VERSION 5.8 ;
BUSBITCHARS "[]" ;
DIVIDERCHAR "/" ;
UNITS
    DATABASE MICRONS 1000 ;
END UNITS

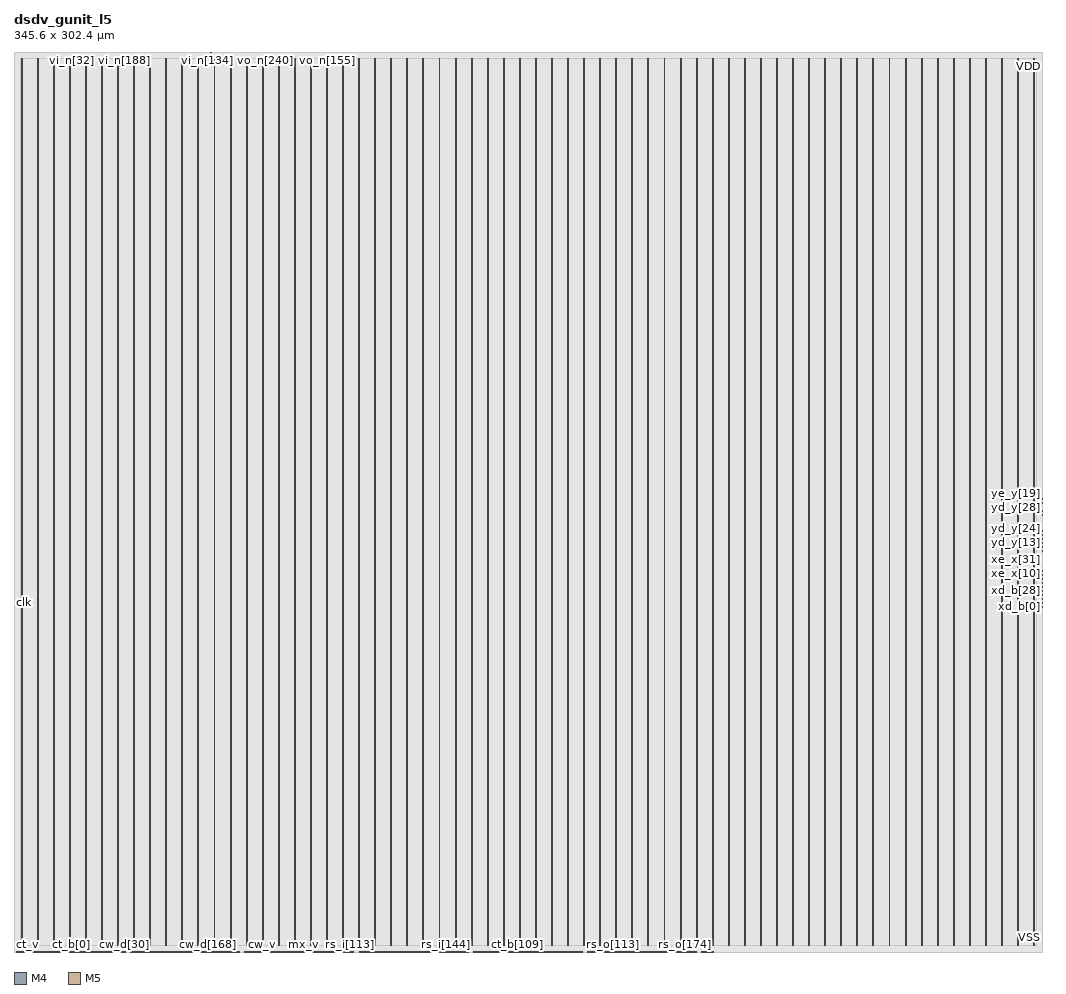
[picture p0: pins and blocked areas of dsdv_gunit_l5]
MACRO dsdv_gunit_l5
  FOREIGN dsdv_gunit_l5 0 0 ;
  CLASS BLOCK ;
  SIZE 345.6 BY 302.4 ;
  PIN clk
    DIRECTION INPUT ;
    USE SIGNAL ;
    PORT
      LAYER M4 ;
        RECT  0 117.456 0.084 117.48 ;
    END
  END clk
  PIN ct_b[0]
    DIRECTION OUTPUT ;
    USE SIGNAL ;
    PORT
      LAYER M5 ;
        RECT  19.152 0 19.176 0.084 ;
    END
  END ct_b[0]
  PIN ct_b[100]
    DIRECTION OUTPUT ;
    USE SIGNAL ;
    PORT
      LAYER M5 ;
        RECT  167.376 0 167.4 0.084 ;
    END
  END ct_b[100]
  PIN ct_b[101]
    DIRECTION OUTPUT ;
    USE SIGNAL ;
    PORT
      LAYER M5 ;
        RECT  167.568 0 167.592 0.084 ;
    END
  END ct_b[101]
  PIN ct_b[102]
    DIRECTION OUTPUT ;
    USE SIGNAL ;
    PORT
      LAYER M5 ;
        RECT  167.76 0 167.784 0.084 ;
    END
  END ct_b[102]
  PIN ct_b[103]
    DIRECTION OUTPUT ;
    USE SIGNAL ;
    PORT
      LAYER M5 ;
        RECT  167.952 0 167.976 0.084 ;
    END
  END ct_b[103]
  PIN ct_b[104]
    DIRECTION OUTPUT ;
    USE SIGNAL ;
    PORT
      LAYER M5 ;
        RECT  168.144 0 168.168 0.084 ;
    END
  END ct_b[104]
  PIN ct_b[105]
    DIRECTION OUTPUT ;
    USE SIGNAL ;
    PORT
      LAYER M5 ;
        RECT  168.336 0 168.36 0.084 ;
    END
  END ct_b[105]
  PIN ct_b[106]
    DIRECTION OUTPUT ;
    USE SIGNAL ;
    PORT
      LAYER M5 ;
        RECT  168.528 0 168.552 0.084 ;
    END
  END ct_b[106]
  PIN ct_b[107]
    DIRECTION OUTPUT ;
    USE SIGNAL ;
    PORT
      LAYER M5 ;
        RECT  168.72 0 168.744 0.084 ;
    END
  END ct_b[107]
  PIN ct_b[108]
    DIRECTION OUTPUT ;
    USE SIGNAL ;
    PORT
      LAYER M5 ;
        RECT  168.912 0 168.936 0.084 ;
    END
  END ct_b[108]
  PIN ct_b[109]
    DIRECTION OUTPUT ;
    USE SIGNAL ;
    PORT
      LAYER M5 ;
        RECT  169.104 0 169.128 0.084 ;
    END
  END ct_b[109]
  PIN ct_b[10]
    DIRECTION OUTPUT ;
    USE SIGNAL ;
    PORT
      LAYER M5 ;
        RECT  21.072 0 21.096 0.084 ;
    END
  END ct_b[10]
  PIN ct_b[110]
    DIRECTION OUTPUT ;
    USE SIGNAL ;
    PORT
      LAYER M5 ;
        RECT  169.296 0 169.32 0.084 ;
    END
  END ct_b[110]
  PIN ct_b[111]
    DIRECTION OUTPUT ;
    USE SIGNAL ;
    PORT
      LAYER M5 ;
        RECT  169.488 0 169.512 0.084 ;
    END
  END ct_b[111]
  PIN ct_b[112]
    DIRECTION OUTPUT ;
    USE SIGNAL ;
    PORT
      LAYER M5 ;
        RECT  169.68 0 169.704 0.084 ;
    END
  END ct_b[112]
  PIN ct_b[113]
    DIRECTION OUTPUT ;
    USE SIGNAL ;
    PORT
      LAYER M5 ;
        RECT  169.872 0 169.896 0.084 ;
    END
  END ct_b[113]
  PIN ct_b[114]
    DIRECTION OUTPUT ;
    USE SIGNAL ;
    PORT
      LAYER M5 ;
        RECT  170.064 0 170.088 0.084 ;
    END
  END ct_b[114]
  PIN ct_b[115]
    DIRECTION OUTPUT ;
    USE SIGNAL ;
    PORT
      LAYER M5 ;
        RECT  170.256 0 170.28 0.084 ;
    END
  END ct_b[115]
  PIN ct_b[116]
    DIRECTION OUTPUT ;
    USE SIGNAL ;
    PORT
      LAYER M5 ;
        RECT  170.448 0 170.472 0.084 ;
    END
  END ct_b[116]
  PIN ct_b[117]
    DIRECTION OUTPUT ;
    USE SIGNAL ;
    PORT
      LAYER M5 ;
        RECT  170.64 0 170.664 0.084 ;
    END
  END ct_b[117]
  PIN ct_b[118]
    DIRECTION OUTPUT ;
    USE SIGNAL ;
    PORT
      LAYER M5 ;
        RECT  170.832 0 170.856 0.084 ;
    END
  END ct_b[118]
  PIN ct_b[119]
    DIRECTION OUTPUT ;
    USE SIGNAL ;
    PORT
      LAYER M5 ;
        RECT  171.024 0 171.048 0.084 ;
    END
  END ct_b[119]
  PIN ct_b[11]
    DIRECTION OUTPUT ;
    USE SIGNAL ;
    PORT
      LAYER M5 ;
        RECT  21.264 0 21.288 0.084 ;
    END
  END ct_b[11]
  PIN ct_b[120]
    DIRECTION OUTPUT ;
    USE SIGNAL ;
    PORT
      LAYER M5 ;
        RECT  171.216 0 171.24 0.084 ;
    END
  END ct_b[120]
  PIN ct_b[121]
    DIRECTION OUTPUT ;
    USE SIGNAL ;
    PORT
      LAYER M5 ;
        RECT  171.408 0 171.432 0.084 ;
    END
  END ct_b[121]
  PIN ct_b[122]
    DIRECTION OUTPUT ;
    USE SIGNAL ;
    PORT
      LAYER M5 ;
        RECT  171.6 0 171.624 0.084 ;
    END
  END ct_b[122]
  PIN ct_b[123]
    DIRECTION OUTPUT ;
    USE SIGNAL ;
    PORT
      LAYER M5 ;
        RECT  171.792 0 171.816 0.084 ;
    END
  END ct_b[123]
  PIN ct_b[124]
    DIRECTION OUTPUT ;
    USE SIGNAL ;
    PORT
      LAYER M5 ;
        RECT  171.984 0 172.008 0.084 ;
    END
  END ct_b[124]
  PIN ct_b[125]
    DIRECTION OUTPUT ;
    USE SIGNAL ;
    PORT
      LAYER M5 ;
        RECT  172.176 0 172.2 0.084 ;
    END
  END ct_b[125]
  PIN ct_b[126]
    DIRECTION OUTPUT ;
    USE SIGNAL ;
    PORT
      LAYER M5 ;
        RECT  172.368 0 172.392 0.084 ;
    END
  END ct_b[126]
  PIN ct_b[127]
    DIRECTION OUTPUT ;
    USE SIGNAL ;
    PORT
      LAYER M5 ;
        RECT  172.56 0 172.584 0.084 ;
    END
  END ct_b[127]
  PIN ct_b[128]
    DIRECTION OUTPUT ;
    USE SIGNAL ;
    PORT
      LAYER M5 ;
        RECT  172.752 0 172.776 0.084 ;
    END
  END ct_b[128]
  PIN ct_b[129]
    DIRECTION OUTPUT ;
    USE SIGNAL ;
    PORT
      LAYER M5 ;
        RECT  172.944 0 172.968 0.084 ;
    END
  END ct_b[129]
  PIN ct_b[12]
    DIRECTION OUTPUT ;
    USE SIGNAL ;
    PORT
      LAYER M5 ;
        RECT  21.456 0 21.48 0.084 ;
    END
  END ct_b[12]
  PIN ct_b[130]
    DIRECTION OUTPUT ;
    USE SIGNAL ;
    PORT
      LAYER M5 ;
        RECT  173.136 0 173.16 0.084 ;
    END
  END ct_b[130]
  PIN ct_b[131]
    DIRECTION OUTPUT ;
    USE SIGNAL ;
    PORT
      LAYER M5 ;
        RECT  173.328 0 173.352 0.084 ;
    END
  END ct_b[131]
  PIN ct_b[132]
    DIRECTION OUTPUT ;
    USE SIGNAL ;
    PORT
      LAYER M5 ;
        RECT  173.52 0 173.544 0.084 ;
    END
  END ct_b[132]
  PIN ct_b[133]
    DIRECTION OUTPUT ;
    USE SIGNAL ;
    PORT
      LAYER M5 ;
        RECT  173.712 0 173.736 0.084 ;
    END
  END ct_b[133]
  PIN ct_b[134]
    DIRECTION OUTPUT ;
    USE SIGNAL ;
    PORT
      LAYER M5 ;
        RECT  173.904 0 173.928 0.084 ;
    END
  END ct_b[134]
  PIN ct_b[135]
    DIRECTION OUTPUT ;
    USE SIGNAL ;
    PORT
      LAYER M5 ;
        RECT  174.096 0 174.12 0.084 ;
    END
  END ct_b[135]
  PIN ct_b[136]
    DIRECTION OUTPUT ;
    USE SIGNAL ;
    PORT
      LAYER M5 ;
        RECT  174.288 0 174.312 0.084 ;
    END
  END ct_b[136]
  PIN ct_b[137]
    DIRECTION OUTPUT ;
    USE SIGNAL ;
    PORT
      LAYER M5 ;
        RECT  174.48 0 174.504 0.084 ;
    END
  END ct_b[137]
  PIN ct_b[138]
    DIRECTION OUTPUT ;
    USE SIGNAL ;
    PORT
      LAYER M5 ;
        RECT  174.672 0 174.696 0.084 ;
    END
  END ct_b[138]
  PIN ct_b[139]
    DIRECTION OUTPUT ;
    USE SIGNAL ;
    PORT
      LAYER M5 ;
        RECT  174.864 0 174.888 0.084 ;
    END
  END ct_b[139]
  PIN ct_b[13]
    DIRECTION OUTPUT ;
    USE SIGNAL ;
    PORT
      LAYER M5 ;
        RECT  21.648 0 21.672 0.084 ;
    END
  END ct_b[13]
  PIN ct_b[140]
    DIRECTION OUTPUT ;
    USE SIGNAL ;
    PORT
      LAYER M5 ;
        RECT  175.056 0 175.08 0.084 ;
    END
  END ct_b[140]
  PIN ct_b[141]
    DIRECTION OUTPUT ;
    USE SIGNAL ;
    PORT
      LAYER M5 ;
        RECT  175.248 0 175.272 0.084 ;
    END
  END ct_b[141]
  PIN ct_b[142]
    DIRECTION OUTPUT ;
    USE SIGNAL ;
    PORT
      LAYER M5 ;
        RECT  175.44 0 175.464 0.084 ;
    END
  END ct_b[142]
  PIN ct_b[143]
    DIRECTION OUTPUT ;
    USE SIGNAL ;
    PORT
      LAYER M5 ;
        RECT  175.632 0 175.656 0.084 ;
    END
  END ct_b[143]
  PIN ct_b[144]
    DIRECTION OUTPUT ;
    USE SIGNAL ;
    PORT
      LAYER M5 ;
        RECT  175.824 0 175.848 0.084 ;
    END
  END ct_b[144]
  PIN ct_b[145]
    DIRECTION OUTPUT ;
    USE SIGNAL ;
    PORT
      LAYER M5 ;
        RECT  176.016 0 176.04 0.084 ;
    END
  END ct_b[145]
  PIN ct_b[146]
    DIRECTION OUTPUT ;
    USE SIGNAL ;
    PORT
      LAYER M5 ;
        RECT  176.208 0 176.232 0.084 ;
    END
  END ct_b[146]
  PIN ct_b[147]
    DIRECTION OUTPUT ;
    USE SIGNAL ;
    PORT
      LAYER M5 ;
        RECT  176.4 0 176.424 0.084 ;
    END
  END ct_b[147]
  PIN ct_b[148]
    DIRECTION OUTPUT ;
    USE SIGNAL ;
    PORT
      LAYER M5 ;
        RECT  176.592 0 176.616 0.084 ;
    END
  END ct_b[148]
  PIN ct_b[149]
    DIRECTION OUTPUT ;
    USE SIGNAL ;
    PORT
      LAYER M5 ;
        RECT  176.784 0 176.808 0.084 ;
    END
  END ct_b[149]
  PIN ct_b[14]
    DIRECTION OUTPUT ;
    USE SIGNAL ;
    PORT
      LAYER M5 ;
        RECT  21.84 0 21.864 0.084 ;
    END
  END ct_b[14]
  PIN ct_b[150]
    DIRECTION OUTPUT ;
    USE SIGNAL ;
    PORT
      LAYER M5 ;
        RECT  176.976 0 177 0.084 ;
    END
  END ct_b[150]
  PIN ct_b[151]
    DIRECTION OUTPUT ;
    USE SIGNAL ;
    PORT
      LAYER M5 ;
        RECT  177.168 0 177.192 0.084 ;
    END
  END ct_b[151]
  PIN ct_b[152]
    DIRECTION OUTPUT ;
    USE SIGNAL ;
    PORT
      LAYER M5 ;
        RECT  177.36 0 177.384 0.084 ;
    END
  END ct_b[152]
  PIN ct_b[153]
    DIRECTION OUTPUT ;
    USE SIGNAL ;
    PORT
      LAYER M5 ;
        RECT  177.552 0 177.576 0.084 ;
    END
  END ct_b[153]
  PIN ct_b[154]
    DIRECTION OUTPUT ;
    USE SIGNAL ;
    PORT
      LAYER M5 ;
        RECT  177.744 0 177.768 0.084 ;
    END
  END ct_b[154]
  PIN ct_b[155]
    DIRECTION OUTPUT ;
    USE SIGNAL ;
    PORT
      LAYER M5 ;
        RECT  177.936 0 177.96 0.084 ;
    END
  END ct_b[155]
  PIN ct_b[156]
    DIRECTION OUTPUT ;
    USE SIGNAL ;
    PORT
      LAYER M5 ;
        RECT  178.128 0 178.152 0.084 ;
    END
  END ct_b[156]
  PIN ct_b[157]
    DIRECTION OUTPUT ;
    USE SIGNAL ;
    PORT
      LAYER M5 ;
        RECT  178.32 0 178.344 0.084 ;
    END
  END ct_b[157]
  PIN ct_b[158]
    DIRECTION OUTPUT ;
    USE SIGNAL ;
    PORT
      LAYER M5 ;
        RECT  178.512 0 178.536 0.084 ;
    END
  END ct_b[158]
  PIN ct_b[159]
    DIRECTION OUTPUT ;
    USE SIGNAL ;
    PORT
      LAYER M5 ;
        RECT  178.704 0 178.728 0.084 ;
    END
  END ct_b[159]
  PIN ct_b[15]
    DIRECTION OUTPUT ;
    USE SIGNAL ;
    PORT
      LAYER M5 ;
        RECT  22.032 0 22.056 0.084 ;
    END
  END ct_b[15]
  PIN ct_b[160]
    DIRECTION OUTPUT ;
    USE SIGNAL ;
    PORT
      LAYER M5 ;
        RECT  178.896 0 178.92 0.084 ;
    END
  END ct_b[160]
  PIN ct_b[161]
    DIRECTION OUTPUT ;
    USE SIGNAL ;
    PORT
      LAYER M5 ;
        RECT  179.088 0 179.112 0.084 ;
    END
  END ct_b[161]
  PIN ct_b[162]
    DIRECTION OUTPUT ;
    USE SIGNAL ;
    PORT
      LAYER M5 ;
        RECT  179.28 0 179.304 0.084 ;
    END
  END ct_b[162]
  PIN ct_b[163]
    DIRECTION OUTPUT ;
    USE SIGNAL ;
    PORT
      LAYER M5 ;
        RECT  179.472 0 179.496 0.084 ;
    END
  END ct_b[163]
  PIN ct_b[164]
    DIRECTION OUTPUT ;
    USE SIGNAL ;
    PORT
      LAYER M5 ;
        RECT  179.664 0 179.688 0.084 ;
    END
  END ct_b[164]
  PIN ct_b[165]
    DIRECTION OUTPUT ;
    USE SIGNAL ;
    PORT
      LAYER M5 ;
        RECT  179.856 0 179.88 0.084 ;
    END
  END ct_b[165]
  PIN ct_b[166]
    DIRECTION OUTPUT ;
    USE SIGNAL ;
    PORT
      LAYER M5 ;
        RECT  180.048 0 180.072 0.084 ;
    END
  END ct_b[166]
  PIN ct_b[167]
    DIRECTION OUTPUT ;
    USE SIGNAL ;
    PORT
      LAYER M5 ;
        RECT  180.24 0 180.264 0.084 ;
    END
  END ct_b[167]
  PIN ct_b[168]
    DIRECTION OUTPUT ;
    USE SIGNAL ;
    PORT
      LAYER M5 ;
        RECT  180.432 0 180.456 0.084 ;
    END
  END ct_b[168]
  PIN ct_b[169]
    DIRECTION OUTPUT ;
    USE SIGNAL ;
    PORT
      LAYER M5 ;
        RECT  180.624 0 180.648 0.084 ;
    END
  END ct_b[169]
  PIN ct_b[16]
    DIRECTION OUTPUT ;
    USE SIGNAL ;
    PORT
      LAYER M5 ;
        RECT  22.224 0 22.248 0.084 ;
    END
  END ct_b[16]
  PIN ct_b[170]
    DIRECTION OUTPUT ;
    USE SIGNAL ;
    PORT
      LAYER M5 ;
        RECT  180.816 0 180.84 0.084 ;
    END
  END ct_b[170]
  PIN ct_b[171]
    DIRECTION OUTPUT ;
    USE SIGNAL ;
    PORT
      LAYER M5 ;
        RECT  181.008 0 181.032 0.084 ;
    END
  END ct_b[171]
  PIN ct_b[172]
    DIRECTION OUTPUT ;
    USE SIGNAL ;
    PORT
      LAYER M5 ;
        RECT  181.2 0 181.224 0.084 ;
    END
  END ct_b[172]
  PIN ct_b[173]
    DIRECTION OUTPUT ;
    USE SIGNAL ;
    PORT
      LAYER M5 ;
        RECT  181.392 0 181.416 0.084 ;
    END
  END ct_b[173]
  PIN ct_b[174]
    DIRECTION OUTPUT ;
    USE SIGNAL ;
    PORT
      LAYER M5 ;
        RECT  181.584 0 181.608 0.084 ;
    END
  END ct_b[174]
  PIN ct_b[175]
    DIRECTION OUTPUT ;
    USE SIGNAL ;
    PORT
      LAYER M5 ;
        RECT  181.776 0 181.8 0.084 ;
    END
  END ct_b[175]
  PIN ct_b[176]
    DIRECTION OUTPUT ;
    USE SIGNAL ;
    PORT
      LAYER M5 ;
        RECT  181.968 0 181.992 0.084 ;
    END
  END ct_b[176]
  PIN ct_b[177]
    DIRECTION OUTPUT ;
    USE SIGNAL ;
    PORT
      LAYER M5 ;
        RECT  182.16 0 182.184 0.084 ;
    END
  END ct_b[177]
  PIN ct_b[178]
    DIRECTION OUTPUT ;
    USE SIGNAL ;
    PORT
      LAYER M5 ;
        RECT  182.352 0 182.376 0.084 ;
    END
  END ct_b[178]
  PIN ct_b[179]
    DIRECTION OUTPUT ;
    USE SIGNAL ;
    PORT
      LAYER M5 ;
        RECT  182.544 0 182.568 0.084 ;
    END
  END ct_b[179]
  PIN ct_b[17]
    DIRECTION OUTPUT ;
    USE SIGNAL ;
    PORT
      LAYER M5 ;
        RECT  22.416 0 22.44 0.084 ;
    END
  END ct_b[17]
  PIN ct_b[180]
    DIRECTION OUTPUT ;
    USE SIGNAL ;
    PORT
      LAYER M5 ;
        RECT  182.736 0 182.76 0.084 ;
    END
  END ct_b[180]
  PIN ct_b[181]
    DIRECTION OUTPUT ;
    USE SIGNAL ;
    PORT
      LAYER M5 ;
        RECT  182.928 0 182.952 0.084 ;
    END
  END ct_b[181]
  PIN ct_b[182]
    DIRECTION OUTPUT ;
    USE SIGNAL ;
    PORT
      LAYER M5 ;
        RECT  183.12 0 183.144 0.084 ;
    END
  END ct_b[182]
  PIN ct_b[183]
    DIRECTION OUTPUT ;
    USE SIGNAL ;
    PORT
      LAYER M5 ;
        RECT  183.312 0 183.336 0.084 ;
    END
  END ct_b[183]
  PIN ct_b[184]
    DIRECTION OUTPUT ;
    USE SIGNAL ;
    PORT
      LAYER M5 ;
        RECT  183.504 0 183.528 0.084 ;
    END
  END ct_b[184]
  PIN ct_b[185]
    DIRECTION OUTPUT ;
    USE SIGNAL ;
    PORT
      LAYER M5 ;
        RECT  183.696 0 183.72 0.084 ;
    END
  END ct_b[185]
  PIN ct_b[186]
    DIRECTION OUTPUT ;
    USE SIGNAL ;
    PORT
      LAYER M5 ;
        RECT  183.888 0 183.912 0.084 ;
    END
  END ct_b[186]
  PIN ct_b[187]
    DIRECTION OUTPUT ;
    USE SIGNAL ;
    PORT
      LAYER M5 ;
        RECT  184.08 0 184.104 0.084 ;
    END
  END ct_b[187]
  PIN ct_b[188]
    DIRECTION OUTPUT ;
    USE SIGNAL ;
    PORT
      LAYER M5 ;
        RECT  184.272 0 184.296 0.084 ;
    END
  END ct_b[188]
  PIN ct_b[189]
    DIRECTION OUTPUT ;
    USE SIGNAL ;
    PORT
      LAYER M5 ;
        RECT  184.464 0 184.488 0.084 ;
    END
  END ct_b[189]
  PIN ct_b[18]
    DIRECTION OUTPUT ;
    USE SIGNAL ;
    PORT
      LAYER M5 ;
        RECT  22.608 0 22.632 0.084 ;
    END
  END ct_b[18]
  PIN ct_b[190]
    DIRECTION OUTPUT ;
    USE SIGNAL ;
    PORT
      LAYER M5 ;
        RECT  184.656 0 184.68 0.084 ;
    END
  END ct_b[190]
  PIN ct_b[191]
    DIRECTION OUTPUT ;
    USE SIGNAL ;
    PORT
      LAYER M5 ;
        RECT  184.848 0 184.872 0.084 ;
    END
  END ct_b[191]
  PIN ct_b[192]
    DIRECTION OUTPUT ;
    USE SIGNAL ;
    PORT
      LAYER M5 ;
        RECT  6.864 0 6.888 0.084 ;
    END
  END ct_b[192]
  PIN ct_b[193]
    DIRECTION OUTPUT ;
    USE SIGNAL ;
    PORT
      LAYER M5 ;
        RECT  7.056 0 7.08 0.084 ;
    END
  END ct_b[193]
  PIN ct_b[194]
    DIRECTION OUTPUT ;
    USE SIGNAL ;
    PORT
      LAYER M5 ;
        RECT  7.248 0 7.272 0.084 ;
    END
  END ct_b[194]
  PIN ct_b[195]
    DIRECTION OUTPUT ;
    USE SIGNAL ;
    PORT
      LAYER M5 ;
        RECT  7.44 0 7.464 0.084 ;
    END
  END ct_b[195]
  PIN ct_b[196]
    DIRECTION OUTPUT ;
    USE SIGNAL ;
    PORT
      LAYER M5 ;
        RECT  7.632 0 7.656 0.084 ;
    END
  END ct_b[196]
  PIN ct_b[197]
    DIRECTION OUTPUT ;
    USE SIGNAL ;
    PORT
      LAYER M5 ;
        RECT  7.824 0 7.848 0.084 ;
    END
  END ct_b[197]
  PIN ct_b[198]
    DIRECTION OUTPUT ;
    USE SIGNAL ;
    PORT
      LAYER M5 ;
        RECT  8.016 0 8.04 0.084 ;
    END
  END ct_b[198]
  PIN ct_b[199]
    DIRECTION OUTPUT ;
    USE SIGNAL ;
    PORT
      LAYER M5 ;
        RECT  8.208 0 8.232 0.084 ;
    END
  END ct_b[199]
  PIN ct_b[19]
    DIRECTION OUTPUT ;
    USE SIGNAL ;
    PORT
      LAYER M5 ;
        RECT  22.8 0 22.824 0.084 ;
    END
  END ct_b[19]
  PIN ct_b[1]
    DIRECTION OUTPUT ;
    USE SIGNAL ;
    PORT
      LAYER M5 ;
        RECT  19.344 0 19.368 0.084 ;
    END
  END ct_b[1]
  PIN ct_b[200]
    DIRECTION OUTPUT ;
    USE SIGNAL ;
    PORT
      LAYER M5 ;
        RECT  8.4 0 8.424 0.084 ;
    END
  END ct_b[200]
  PIN ct_b[201]
    DIRECTION OUTPUT ;
    USE SIGNAL ;
    PORT
      LAYER M5 ;
        RECT  8.592 0 8.616 0.084 ;
    END
  END ct_b[201]
  PIN ct_b[202]
    DIRECTION OUTPUT ;
    USE SIGNAL ;
    PORT
      LAYER M5 ;
        RECT  8.784 0 8.808 0.084 ;
    END
  END ct_b[202]
  PIN ct_b[203]
    DIRECTION OUTPUT ;
    USE SIGNAL ;
    PORT
      LAYER M5 ;
        RECT  8.976 0 9 0.084 ;
    END
  END ct_b[203]
  PIN ct_b[204]
    DIRECTION OUTPUT ;
    USE SIGNAL ;
    PORT
      LAYER M5 ;
        RECT  9.168 0 9.192 0.084 ;
    END
  END ct_b[204]
  PIN ct_b[205]
    DIRECTION OUTPUT ;
    USE SIGNAL ;
    PORT
      LAYER M5 ;
        RECT  9.36 0 9.384 0.084 ;
    END
  END ct_b[205]
  PIN ct_b[206]
    DIRECTION OUTPUT ;
    USE SIGNAL ;
    PORT
      LAYER M5 ;
        RECT  9.552 0 9.576 0.084 ;
    END
  END ct_b[206]
  PIN ct_b[207]
    DIRECTION OUTPUT ;
    USE SIGNAL ;
    PORT
      LAYER M5 ;
        RECT  9.744 0 9.768 0.084 ;
    END
  END ct_b[207]
  PIN ct_b[208]
    DIRECTION OUTPUT ;
    USE SIGNAL ;
    PORT
      LAYER M5 ;
        RECT  9.936 0 9.96 0.084 ;
    END
  END ct_b[208]
  PIN ct_b[209]
    DIRECTION OUTPUT ;
    USE SIGNAL ;
    PORT
      LAYER M5 ;
        RECT  10.128 0 10.152 0.084 ;
    END
  END ct_b[209]
  PIN ct_b[20]
    DIRECTION OUTPUT ;
    USE SIGNAL ;
    PORT
      LAYER M5 ;
        RECT  22.992 0 23.016 0.084 ;
    END
  END ct_b[20]
  PIN ct_b[210]
    DIRECTION OUTPUT ;
    USE SIGNAL ;
    PORT
      LAYER M5 ;
        RECT  10.32 0 10.344 0.084 ;
    END
  END ct_b[210]
  PIN ct_b[211]
    DIRECTION OUTPUT ;
    USE SIGNAL ;
    PORT
      LAYER M5 ;
        RECT  10.512 0 10.536 0.084 ;
    END
  END ct_b[211]
  PIN ct_b[212]
    DIRECTION OUTPUT ;
    USE SIGNAL ;
    PORT
      LAYER M5 ;
        RECT  10.704 0 10.728 0.084 ;
    END
  END ct_b[212]
  PIN ct_b[213]
    DIRECTION OUTPUT ;
    USE SIGNAL ;
    PORT
      LAYER M5 ;
        RECT  10.896 0 10.92 0.084 ;
    END
  END ct_b[213]
  PIN ct_b[214]
    DIRECTION OUTPUT ;
    USE SIGNAL ;
    PORT
      LAYER M5 ;
        RECT  11.088 0 11.112 0.084 ;
    END
  END ct_b[214]
  PIN ct_b[215]
    DIRECTION OUTPUT ;
    USE SIGNAL ;
    PORT
      LAYER M5 ;
        RECT  11.28 0 11.304 0.084 ;
    END
  END ct_b[215]
  PIN ct_b[216]
    DIRECTION OUTPUT ;
    USE SIGNAL ;
    PORT
      LAYER M5 ;
        RECT  11.472 0 11.496 0.084 ;
    END
  END ct_b[216]
  PIN ct_b[217]
    DIRECTION OUTPUT ;
    USE SIGNAL ;
    PORT
      LAYER M5 ;
        RECT  11.664 0 11.688 0.084 ;
    END
  END ct_b[217]
  PIN ct_b[218]
    DIRECTION OUTPUT ;
    USE SIGNAL ;
    PORT
      LAYER M5 ;
        RECT  11.856 0 11.88 0.084 ;
    END
  END ct_b[218]
  PIN ct_b[219]
    DIRECTION OUTPUT ;
    USE SIGNAL ;
    PORT
      LAYER M5 ;
        RECT  12.048 0 12.072 0.084 ;
    END
  END ct_b[219]
  PIN ct_b[21]
    DIRECTION OUTPUT ;
    USE SIGNAL ;
    PORT
      LAYER M5 ;
        RECT  23.184 0 23.208 0.084 ;
    END
  END ct_b[21]
  PIN ct_b[220]
    DIRECTION OUTPUT ;
    USE SIGNAL ;
    PORT
      LAYER M5 ;
        RECT  12.24 0 12.264 0.084 ;
    END
  END ct_b[220]
  PIN ct_b[221]
    DIRECTION OUTPUT ;
    USE SIGNAL ;
    PORT
      LAYER M5 ;
        RECT  12.432 0 12.456 0.084 ;
    END
  END ct_b[221]
  PIN ct_b[222]
    DIRECTION OUTPUT ;
    USE SIGNAL ;
    PORT
      LAYER M5 ;
        RECT  12.624 0 12.648 0.084 ;
    END
  END ct_b[222]
  PIN ct_b[223]
    DIRECTION OUTPUT ;
    USE SIGNAL ;
    PORT
      LAYER M5 ;
        RECT  12.816 0 12.84 0.084 ;
    END
  END ct_b[223]
  PIN ct_b[224]
    DIRECTION OUTPUT ;
    USE SIGNAL ;
    PORT
      LAYER M5 ;
        RECT  13.008 0 13.032 0.084 ;
    END
  END ct_b[224]
  PIN ct_b[225]
    DIRECTION OUTPUT ;
    USE SIGNAL ;
    PORT
      LAYER M5 ;
        RECT  13.2 0 13.224 0.084 ;
    END
  END ct_b[225]
  PIN ct_b[226]
    DIRECTION OUTPUT ;
    USE SIGNAL ;
    PORT
      LAYER M5 ;
        RECT  13.392 0 13.416 0.084 ;
    END
  END ct_b[226]
  PIN ct_b[227]
    DIRECTION OUTPUT ;
    USE SIGNAL ;
    PORT
      LAYER M5 ;
        RECT  13.584 0 13.608 0.084 ;
    END
  END ct_b[227]
  PIN ct_b[228]
    DIRECTION OUTPUT ;
    USE SIGNAL ;
    PORT
      LAYER M5 ;
        RECT  13.776 0 13.8 0.084 ;
    END
  END ct_b[228]
  PIN ct_b[229]
    DIRECTION OUTPUT ;
    USE SIGNAL ;
    PORT
      LAYER M5 ;
        RECT  13.968 0 13.992 0.084 ;
    END
  END ct_b[229]
  PIN ct_b[22]
    DIRECTION OUTPUT ;
    USE SIGNAL ;
    PORT
      LAYER M5 ;
        RECT  23.376 0 23.4 0.084 ;
    END
  END ct_b[22]
  PIN ct_b[230]
    DIRECTION OUTPUT ;
    USE SIGNAL ;
    PORT
      LAYER M5 ;
        RECT  14.16 0 14.184 0.084 ;
    END
  END ct_b[230]
  PIN ct_b[231]
    DIRECTION OUTPUT ;
    USE SIGNAL ;
    PORT
      LAYER M5 ;
        RECT  14.352 0 14.376 0.084 ;
    END
  END ct_b[231]
  PIN ct_b[232]
    DIRECTION OUTPUT ;
    USE SIGNAL ;
    PORT
      LAYER M5 ;
        RECT  14.544 0 14.568 0.084 ;
    END
  END ct_b[232]
  PIN ct_b[233]
    DIRECTION OUTPUT ;
    USE SIGNAL ;
    PORT
      LAYER M5 ;
        RECT  14.736 0 14.76 0.084 ;
    END
  END ct_b[233]
  PIN ct_b[234]
    DIRECTION OUTPUT ;
    USE SIGNAL ;
    PORT
      LAYER M5 ;
        RECT  14.928 0 14.952 0.084 ;
    END
  END ct_b[234]
  PIN ct_b[235]
    DIRECTION OUTPUT ;
    USE SIGNAL ;
    PORT
      LAYER M5 ;
        RECT  15.12 0 15.144 0.084 ;
    END
  END ct_b[235]
  PIN ct_b[236]
    DIRECTION OUTPUT ;
    USE SIGNAL ;
    PORT
      LAYER M5 ;
        RECT  15.312 0 15.336 0.084 ;
    END
  END ct_b[236]
  PIN ct_b[237]
    DIRECTION OUTPUT ;
    USE SIGNAL ;
    PORT
      LAYER M5 ;
        RECT  15.504 0 15.528 0.084 ;
    END
  END ct_b[237]
  PIN ct_b[238]
    DIRECTION OUTPUT ;
    USE SIGNAL ;
    PORT
      LAYER M5 ;
        RECT  15.696 0 15.72 0.084 ;
    END
  END ct_b[238]
  PIN ct_b[239]
    DIRECTION OUTPUT ;
    USE SIGNAL ;
    PORT
      LAYER M5 ;
        RECT  15.888 0 15.912 0.084 ;
    END
  END ct_b[239]
  PIN ct_b[23]
    DIRECTION OUTPUT ;
    USE SIGNAL ;
    PORT
      LAYER M5 ;
        RECT  23.568 0 23.592 0.084 ;
    END
  END ct_b[23]
  PIN ct_b[240]
    DIRECTION OUTPUT ;
    USE SIGNAL ;
    PORT
      LAYER M5 ;
        RECT  16.08 0 16.104 0.084 ;
    END
  END ct_b[240]
  PIN ct_b[241]
    DIRECTION OUTPUT ;
    USE SIGNAL ;
    PORT
      LAYER M5 ;
        RECT  16.272 0 16.296 0.084 ;
    END
  END ct_b[241]
  PIN ct_b[242]
    DIRECTION OUTPUT ;
    USE SIGNAL ;
    PORT
      LAYER M5 ;
        RECT  16.464 0 16.488 0.084 ;
    END
  END ct_b[242]
  PIN ct_b[243]
    DIRECTION OUTPUT ;
    USE SIGNAL ;
    PORT
      LAYER M5 ;
        RECT  16.656 0 16.68 0.084 ;
    END
  END ct_b[243]
  PIN ct_b[244]
    DIRECTION OUTPUT ;
    USE SIGNAL ;
    PORT
      LAYER M5 ;
        RECT  16.848 0 16.872 0.084 ;
    END
  END ct_b[244]
  PIN ct_b[245]
    DIRECTION OUTPUT ;
    USE SIGNAL ;
    PORT
      LAYER M5 ;
        RECT  17.04 0 17.064 0.084 ;
    END
  END ct_b[245]
  PIN ct_b[246]
    DIRECTION OUTPUT ;
    USE SIGNAL ;
    PORT
      LAYER M5 ;
        RECT  17.232 0 17.256 0.084 ;
    END
  END ct_b[246]
  PIN ct_b[247]
    DIRECTION OUTPUT ;
    USE SIGNAL ;
    PORT
      LAYER M5 ;
        RECT  17.424 0 17.448 0.084 ;
    END
  END ct_b[247]
  PIN ct_b[248]
    DIRECTION OUTPUT ;
    USE SIGNAL ;
    PORT
      LAYER M5 ;
        RECT  17.616 0 17.64 0.084 ;
    END
  END ct_b[248]
  PIN ct_b[249]
    DIRECTION OUTPUT ;
    USE SIGNAL ;
    PORT
      LAYER M5 ;
        RECT  17.808 0 17.832 0.084 ;
    END
  END ct_b[249]
  PIN ct_b[24]
    DIRECTION OUTPUT ;
    USE SIGNAL ;
    PORT
      LAYER M5 ;
        RECT  23.76 0 23.784 0.084 ;
    END
  END ct_b[24]
  PIN ct_b[250]
    DIRECTION OUTPUT ;
    USE SIGNAL ;
    PORT
      LAYER M5 ;
        RECT  18 0 18.024 0.084 ;
    END
  END ct_b[250]
  PIN ct_b[251]
    DIRECTION OUTPUT ;
    USE SIGNAL ;
    PORT
      LAYER M5 ;
        RECT  18.192 0 18.216 0.084 ;
    END
  END ct_b[251]
  PIN ct_b[252]
    DIRECTION OUTPUT ;
    USE SIGNAL ;
    PORT
      LAYER M5 ;
        RECT  18.384 0 18.408 0.084 ;
    END
  END ct_b[252]
  PIN ct_b[253]
    DIRECTION OUTPUT ;
    USE SIGNAL ;
    PORT
      LAYER M5 ;
        RECT  18.576 0 18.6 0.084 ;
    END
  END ct_b[253]
  PIN ct_b[254]
    DIRECTION OUTPUT ;
    USE SIGNAL ;
    PORT
      LAYER M5 ;
        RECT  18.768 0 18.792 0.084 ;
    END
  END ct_b[254]
  PIN ct_b[255]
    DIRECTION OUTPUT ;
    USE SIGNAL ;
    PORT
      LAYER M5 ;
        RECT  18.96 0 18.984 0.084 ;
    END
  END ct_b[255]
  PIN ct_b[256]
    DIRECTION OUTPUT ;
    USE SIGNAL ;
    PORT
      LAYER M5 ;
        RECT  0.72 0 0.744 0.084 ;
    END
  END ct_b[256]
  PIN ct_b[257]
    DIRECTION OUTPUT ;
    USE SIGNAL ;
    PORT
      LAYER M5 ;
        RECT  0.912 0 0.936 0.084 ;
    END
  END ct_b[257]
  PIN ct_b[258]
    DIRECTION OUTPUT ;
    USE SIGNAL ;
    PORT
      LAYER M5 ;
        RECT  1.104 0 1.128 0.084 ;
    END
  END ct_b[258]
  PIN ct_b[259]
    DIRECTION OUTPUT ;
    USE SIGNAL ;
    PORT
      LAYER M5 ;
        RECT  1.296 0 1.32 0.084 ;
    END
  END ct_b[259]
  PIN ct_b[25]
    DIRECTION OUTPUT ;
    USE SIGNAL ;
    PORT
      LAYER M5 ;
        RECT  23.952 0 23.976 0.084 ;
    END
  END ct_b[25]
  PIN ct_b[260]
    DIRECTION OUTPUT ;
    USE SIGNAL ;
    PORT
      LAYER M5 ;
        RECT  1.488 0 1.512 0.084 ;
    END
  END ct_b[260]
  PIN ct_b[261]
    DIRECTION OUTPUT ;
    USE SIGNAL ;
    PORT
      LAYER M5 ;
        RECT  1.68 0 1.704 0.084 ;
    END
  END ct_b[261]
  PIN ct_b[262]
    DIRECTION OUTPUT ;
    USE SIGNAL ;
    PORT
      LAYER M5 ;
        RECT  1.872 0 1.896 0.084 ;
    END
  END ct_b[262]
  PIN ct_b[263]
    DIRECTION OUTPUT ;
    USE SIGNAL ;
    PORT
      LAYER M5 ;
        RECT  2.064 0 2.088 0.084 ;
    END
  END ct_b[263]
  PIN ct_b[264]
    DIRECTION OUTPUT ;
    USE SIGNAL ;
    PORT
      LAYER M5 ;
        RECT  2.256 0 2.28 0.084 ;
    END
  END ct_b[264]
  PIN ct_b[265]
    DIRECTION OUTPUT ;
    USE SIGNAL ;
    PORT
      LAYER M5 ;
        RECT  2.448 0 2.472 0.084 ;
    END
  END ct_b[265]
  PIN ct_b[266]
    DIRECTION OUTPUT ;
    USE SIGNAL ;
    PORT
      LAYER M5 ;
        RECT  2.64 0 2.664 0.084 ;
    END
  END ct_b[266]
  PIN ct_b[267]
    DIRECTION OUTPUT ;
    USE SIGNAL ;
    PORT
      LAYER M5 ;
        RECT  2.832 0 2.856 0.084 ;
    END
  END ct_b[267]
  PIN ct_b[268]
    DIRECTION OUTPUT ;
    USE SIGNAL ;
    PORT
      LAYER M5 ;
        RECT  3.024 0 3.048 0.084 ;
    END
  END ct_b[268]
  PIN ct_b[269]
    DIRECTION OUTPUT ;
    USE SIGNAL ;
    PORT
      LAYER M5 ;
        RECT  3.216 0 3.24 0.084 ;
    END
  END ct_b[269]
  PIN ct_b[26]
    DIRECTION OUTPUT ;
    USE SIGNAL ;
    PORT
      LAYER M5 ;
        RECT  24.144 0 24.168 0.084 ;
    END
  END ct_b[26]
  PIN ct_b[270]
    DIRECTION OUTPUT ;
    USE SIGNAL ;
    PORT
      LAYER M5 ;
        RECT  3.408 0 3.432 0.084 ;
    END
  END ct_b[270]
  PIN ct_b[271]
    DIRECTION OUTPUT ;
    USE SIGNAL ;
    PORT
      LAYER M5 ;
        RECT  3.6 0 3.624 0.084 ;
    END
  END ct_b[271]
  PIN ct_b[272]
    DIRECTION OUTPUT ;
    USE SIGNAL ;
    PORT
      LAYER M5 ;
        RECT  3.792 0 3.816 0.084 ;
    END
  END ct_b[272]
  PIN ct_b[273]
    DIRECTION OUTPUT ;
    USE SIGNAL ;
    PORT
      LAYER M5 ;
        RECT  3.984 0 4.008 0.084 ;
    END
  END ct_b[273]
  PIN ct_b[274]
    DIRECTION OUTPUT ;
    USE SIGNAL ;
    PORT
      LAYER M5 ;
        RECT  4.176 0 4.2 0.084 ;
    END
  END ct_b[274]
  PIN ct_b[275]
    DIRECTION OUTPUT ;
    USE SIGNAL ;
    PORT
      LAYER M5 ;
        RECT  4.368 0 4.392 0.084 ;
    END
  END ct_b[275]
  PIN ct_b[27]
    DIRECTION OUTPUT ;
    USE SIGNAL ;
    PORT
      LAYER M5 ;
        RECT  24.336 0 24.36 0.084 ;
    END
  END ct_b[27]
  PIN ct_b[28]
    DIRECTION OUTPUT ;
    USE SIGNAL ;
    PORT
      LAYER M5 ;
        RECT  24.528 0 24.552 0.084 ;
    END
  END ct_b[28]
  PIN ct_b[29]
    DIRECTION OUTPUT ;
    USE SIGNAL ;
    PORT
      LAYER M5 ;
        RECT  24.72 0 24.744 0.084 ;
    END
  END ct_b[29]
  PIN ct_b[2]
    DIRECTION OUTPUT ;
    USE SIGNAL ;
    PORT
      LAYER M5 ;
        RECT  19.536 0 19.56 0.084 ;
    END
  END ct_b[2]
  PIN ct_b[30]
    DIRECTION OUTPUT ;
    USE SIGNAL ;
    PORT
      LAYER M5 ;
        RECT  24.912 0 24.936 0.084 ;
    END
  END ct_b[30]
  PIN ct_b[31]
    DIRECTION OUTPUT ;
    USE SIGNAL ;
    PORT
      LAYER M5 ;
        RECT  25.104 0 25.128 0.084 ;
    END
  END ct_b[31]
  PIN ct_b[32]
    DIRECTION OUTPUT ;
    USE SIGNAL ;
    PORT
      LAYER M5 ;
        RECT  25.296 0 25.32 0.084 ;
    END
  END ct_b[32]
  PIN ct_b[33]
    DIRECTION OUTPUT ;
    USE SIGNAL ;
    PORT
      LAYER M5 ;
        RECT  25.488 0 25.512 0.084 ;
    END
  END ct_b[33]
  PIN ct_b[34]
    DIRECTION OUTPUT ;
    USE SIGNAL ;
    PORT
      LAYER M5 ;
        RECT  25.68 0 25.704 0.084 ;
    END
  END ct_b[34]
  PIN ct_b[35]
    DIRECTION OUTPUT ;
    USE SIGNAL ;
    PORT
      LAYER M5 ;
        RECT  25.872 0 25.896 0.084 ;
    END
  END ct_b[35]
  PIN ct_b[36]
    DIRECTION OUTPUT ;
    USE SIGNAL ;
    PORT
      LAYER M5 ;
        RECT  26.064 0 26.088 0.084 ;
    END
  END ct_b[36]
  PIN ct_b[37]
    DIRECTION OUTPUT ;
    USE SIGNAL ;
    PORT
      LAYER M5 ;
        RECT  26.256 0 26.28 0.084 ;
    END
  END ct_b[37]
  PIN ct_b[38]
    DIRECTION OUTPUT ;
    USE SIGNAL ;
    PORT
      LAYER M5 ;
        RECT  26.448 0 26.472 0.084 ;
    END
  END ct_b[38]
  PIN ct_b[39]
    DIRECTION OUTPUT ;
    USE SIGNAL ;
    PORT
      LAYER M5 ;
        RECT  26.64 0 26.664 0.084 ;
    END
  END ct_b[39]
  PIN ct_b[3]
    DIRECTION OUTPUT ;
    USE SIGNAL ;
    PORT
      LAYER M5 ;
        RECT  19.728 0 19.752 0.084 ;
    END
  END ct_b[3]
  PIN ct_b[40]
    DIRECTION OUTPUT ;
    USE SIGNAL ;
    PORT
      LAYER M5 ;
        RECT  26.832 0 26.856 0.084 ;
    END
  END ct_b[40]
  PIN ct_b[41]
    DIRECTION OUTPUT ;
    USE SIGNAL ;
    PORT
      LAYER M5 ;
        RECT  27.024 0 27.048 0.084 ;
    END
  END ct_b[41]
  PIN ct_b[42]
    DIRECTION OUTPUT ;
    USE SIGNAL ;
    PORT
      LAYER M5 ;
        RECT  27.216 0 27.24 0.084 ;
    END
  END ct_b[42]
  PIN ct_b[43]
    DIRECTION OUTPUT ;
    USE SIGNAL ;
    PORT
      LAYER M5 ;
        RECT  27.408 0 27.432 0.084 ;
    END
  END ct_b[43]
  PIN ct_b[44]
    DIRECTION OUTPUT ;
    USE SIGNAL ;
    PORT
      LAYER M5 ;
        RECT  27.6 0 27.624 0.084 ;
    END
  END ct_b[44]
  PIN ct_b[45]
    DIRECTION OUTPUT ;
    USE SIGNAL ;
    PORT
      LAYER M5 ;
        RECT  27.792 0 27.816 0.084 ;
    END
  END ct_b[45]
  PIN ct_b[46]
    DIRECTION OUTPUT ;
    USE SIGNAL ;
    PORT
      LAYER M5 ;
        RECT  27.984 0 28.008 0.084 ;
    END
  END ct_b[46]
  PIN ct_b[47]
    DIRECTION OUTPUT ;
    USE SIGNAL ;
    PORT
      LAYER M5 ;
        RECT  28.176 0 28.2 0.084 ;
    END
  END ct_b[47]
  PIN ct_b[48]
    DIRECTION OUTPUT ;
    USE SIGNAL ;
    PORT
      LAYER M5 ;
        RECT  28.368 0 28.392 0.084 ;
    END
  END ct_b[48]
  PIN ct_b[49]
    DIRECTION OUTPUT ;
    USE SIGNAL ;
    PORT
      LAYER M5 ;
        RECT  28.56 0 28.584 0.084 ;
    END
  END ct_b[49]
  PIN ct_b[4]
    DIRECTION OUTPUT ;
    USE SIGNAL ;
    PORT
      LAYER M5 ;
        RECT  19.92 0 19.944 0.084 ;
    END
  END ct_b[4]
  PIN ct_b[50]
    DIRECTION OUTPUT ;
    USE SIGNAL ;
    PORT
      LAYER M5 ;
        RECT  28.752 0 28.776 0.084 ;
    END
  END ct_b[50]
  PIN ct_b[51]
    DIRECTION OUTPUT ;
    USE SIGNAL ;
    PORT
      LAYER M5 ;
        RECT  28.944 0 28.968 0.084 ;
    END
  END ct_b[51]
  PIN ct_b[52]
    DIRECTION OUTPUT ;
    USE SIGNAL ;
    PORT
      LAYER M5 ;
        RECT  29.136 0 29.16 0.084 ;
    END
  END ct_b[52]
  PIN ct_b[53]
    DIRECTION OUTPUT ;
    USE SIGNAL ;
    PORT
      LAYER M5 ;
        RECT  29.328 0 29.352 0.084 ;
    END
  END ct_b[53]
  PIN ct_b[54]
    DIRECTION OUTPUT ;
    USE SIGNAL ;
    PORT
      LAYER M5 ;
        RECT  29.52 0 29.544 0.084 ;
    END
  END ct_b[54]
  PIN ct_b[55]
    DIRECTION OUTPUT ;
    USE SIGNAL ;
    PORT
      LAYER M5 ;
        RECT  29.712 0 29.736 0.084 ;
    END
  END ct_b[55]
  PIN ct_b[56]
    DIRECTION OUTPUT ;
    USE SIGNAL ;
    PORT
      LAYER M5 ;
        RECT  29.904 0 29.928 0.084 ;
    END
  END ct_b[56]
  PIN ct_b[57]
    DIRECTION OUTPUT ;
    USE SIGNAL ;
    PORT
      LAYER M5 ;
        RECT  30.096 0 30.12 0.084 ;
    END
  END ct_b[57]
  PIN ct_b[58]
    DIRECTION OUTPUT ;
    USE SIGNAL ;
    PORT
      LAYER M5 ;
        RECT  30.288 0 30.312 0.084 ;
    END
  END ct_b[58]
  PIN ct_b[59]
    DIRECTION OUTPUT ;
    USE SIGNAL ;
    PORT
      LAYER M5 ;
        RECT  30.48 0 30.504 0.084 ;
    END
  END ct_b[59]
  PIN ct_b[5]
    DIRECTION OUTPUT ;
    USE SIGNAL ;
    PORT
      LAYER M5 ;
        RECT  20.112 0 20.136 0.084 ;
    END
  END ct_b[5]
  PIN ct_b[60]
    DIRECTION OUTPUT ;
    USE SIGNAL ;
    PORT
      LAYER M5 ;
        RECT  30.672 0 30.696 0.084 ;
    END
  END ct_b[60]
  PIN ct_b[61]
    DIRECTION OUTPUT ;
    USE SIGNAL ;
    PORT
      LAYER M5 ;
        RECT  30.864 0 30.888 0.084 ;
    END
  END ct_b[61]
  PIN ct_b[62]
    DIRECTION OUTPUT ;
    USE SIGNAL ;
    PORT
      LAYER M5 ;
        RECT  31.056 0 31.08 0.084 ;
    END
  END ct_b[62]
  PIN ct_b[63]
    DIRECTION OUTPUT ;
    USE SIGNAL ;
    PORT
      LAYER M5 ;
        RECT  31.248 0 31.272 0.084 ;
    END
  END ct_b[63]
  PIN ct_b[64]
    DIRECTION OUTPUT ;
    USE SIGNAL ;
    PORT
      LAYER M5 ;
        RECT  185.04 0 185.064 0.084 ;
    END
  END ct_b[64]
  PIN ct_b[65]
    DIRECTION OUTPUT ;
    USE SIGNAL ;
    PORT
      LAYER M5 ;
        RECT  185.232 0 185.256 0.084 ;
    END
  END ct_b[65]
  PIN ct_b[66]
    DIRECTION OUTPUT ;
    USE SIGNAL ;
    PORT
      LAYER M5 ;
        RECT  185.424 0 185.448 0.084 ;
    END
  END ct_b[66]
  PIN ct_b[67]
    DIRECTION OUTPUT ;
    USE SIGNAL ;
    PORT
      LAYER M5 ;
        RECT  185.616 0 185.64 0.084 ;
    END
  END ct_b[67]
  PIN ct_b[68]
    DIRECTION OUTPUT ;
    USE SIGNAL ;
    PORT
      LAYER M5 ;
        RECT  185.808 0 185.832 0.084 ;
    END
  END ct_b[68]
  PIN ct_b[69]
    DIRECTION OUTPUT ;
    USE SIGNAL ;
    PORT
      LAYER M5 ;
        RECT  186 0 186.024 0.084 ;
    END
  END ct_b[69]
  PIN ct_b[6]
    DIRECTION OUTPUT ;
    USE SIGNAL ;
    PORT
      LAYER M5 ;
        RECT  20.304 0 20.328 0.084 ;
    END
  END ct_b[6]
  PIN ct_b[70]
    DIRECTION OUTPUT ;
    USE SIGNAL ;
    PORT
      LAYER M5 ;
        RECT  186.192 0 186.216 0.084 ;
    END
  END ct_b[70]
  PIN ct_b[71]
    DIRECTION OUTPUT ;
    USE SIGNAL ;
    PORT
      LAYER M5 ;
        RECT  186.384 0 186.408 0.084 ;
    END
  END ct_b[71]
  PIN ct_b[72]
    DIRECTION OUTPUT ;
    USE SIGNAL ;
    PORT
      LAYER M5 ;
        RECT  186.576 0 186.6 0.084 ;
    END
  END ct_b[72]
  PIN ct_b[73]
    DIRECTION OUTPUT ;
    USE SIGNAL ;
    PORT
      LAYER M5 ;
        RECT  186.768 0 186.792 0.084 ;
    END
  END ct_b[73]
  PIN ct_b[74]
    DIRECTION OUTPUT ;
    USE SIGNAL ;
    PORT
      LAYER M5 ;
        RECT  186.96 0 186.984 0.084 ;
    END
  END ct_b[74]
  PIN ct_b[75]
    DIRECTION OUTPUT ;
    USE SIGNAL ;
    PORT
      LAYER M5 ;
        RECT  187.152 0 187.176 0.084 ;
    END
  END ct_b[75]
  PIN ct_b[76]
    DIRECTION OUTPUT ;
    USE SIGNAL ;
    PORT
      LAYER M5 ;
        RECT  187.344 0 187.368 0.084 ;
    END
  END ct_b[76]
  PIN ct_b[77]
    DIRECTION OUTPUT ;
    USE SIGNAL ;
    PORT
      LAYER M5 ;
        RECT  187.536 0 187.56 0.084 ;
    END
  END ct_b[77]
  PIN ct_b[78]
    DIRECTION OUTPUT ;
    USE SIGNAL ;
    PORT
      LAYER M5 ;
        RECT  187.728 0 187.752 0.084 ;
    END
  END ct_b[78]
  PIN ct_b[79]
    DIRECTION OUTPUT ;
    USE SIGNAL ;
    PORT
      LAYER M5 ;
        RECT  187.92 0 187.944 0.084 ;
    END
  END ct_b[79]
  PIN ct_b[7]
    DIRECTION OUTPUT ;
    USE SIGNAL ;
    PORT
      LAYER M5 ;
        RECT  20.496 0 20.52 0.084 ;
    END
  END ct_b[7]
  PIN ct_b[80]
    DIRECTION OUTPUT ;
    USE SIGNAL ;
    PORT
      LAYER M5 ;
        RECT  188.112 0 188.136 0.084 ;
    END
  END ct_b[80]
  PIN ct_b[81]
    DIRECTION OUTPUT ;
    USE SIGNAL ;
    PORT
      LAYER M5 ;
        RECT  188.304 0 188.328 0.084 ;
    END
  END ct_b[81]
  PIN ct_b[82]
    DIRECTION OUTPUT ;
    USE SIGNAL ;
    PORT
      LAYER M5 ;
        RECT  188.496 0 188.52 0.084 ;
    END
  END ct_b[82]
  PIN ct_b[83]
    DIRECTION OUTPUT ;
    USE SIGNAL ;
    PORT
      LAYER M5 ;
        RECT  188.688 0 188.712 0.084 ;
    END
  END ct_b[83]
  PIN ct_b[84]
    DIRECTION OUTPUT ;
    USE SIGNAL ;
    PORT
      LAYER M5 ;
        RECT  188.88 0 188.904 0.084 ;
    END
  END ct_b[84]
  PIN ct_b[85]
    DIRECTION OUTPUT ;
    USE SIGNAL ;
    PORT
      LAYER M5 ;
        RECT  189.072 0 189.096 0.084 ;
    END
  END ct_b[85]
  PIN ct_b[86]
    DIRECTION OUTPUT ;
    USE SIGNAL ;
    PORT
      LAYER M5 ;
        RECT  189.264 0 189.288 0.084 ;
    END
  END ct_b[86]
  PIN ct_b[87]
    DIRECTION OUTPUT ;
    USE SIGNAL ;
    PORT
      LAYER M5 ;
        RECT  189.456 0 189.48 0.084 ;
    END
  END ct_b[87]
  PIN ct_b[88]
    DIRECTION OUTPUT ;
    USE SIGNAL ;
    PORT
      LAYER M5 ;
        RECT  189.648 0 189.672 0.084 ;
    END
  END ct_b[88]
  PIN ct_b[89]
    DIRECTION OUTPUT ;
    USE SIGNAL ;
    PORT
      LAYER M5 ;
        RECT  189.84 0 189.864 0.084 ;
    END
  END ct_b[89]
  PIN ct_b[8]
    DIRECTION OUTPUT ;
    USE SIGNAL ;
    PORT
      LAYER M5 ;
        RECT  20.688 0 20.712 0.084 ;
    END
  END ct_b[8]
  PIN ct_b[90]
    DIRECTION OUTPUT ;
    USE SIGNAL ;
    PORT
      LAYER M5 ;
        RECT  190.032 0 190.056 0.084 ;
    END
  END ct_b[90]
  PIN ct_b[91]
    DIRECTION OUTPUT ;
    USE SIGNAL ;
    PORT
      LAYER M5 ;
        RECT  190.224 0 190.248 0.084 ;
    END
  END ct_b[91]
  PIN ct_b[92]
    DIRECTION OUTPUT ;
    USE SIGNAL ;
    PORT
      LAYER M5 ;
        RECT  190.416 0 190.44 0.084 ;
    END
  END ct_b[92]
  PIN ct_b[93]
    DIRECTION OUTPUT ;
    USE SIGNAL ;
    PORT
      LAYER M5 ;
        RECT  190.608 0 190.632 0.084 ;
    END
  END ct_b[93]
  PIN ct_b[94]
    DIRECTION OUTPUT ;
    USE SIGNAL ;
    PORT
      LAYER M5 ;
        RECT  190.8 0 190.824 0.084 ;
    END
  END ct_b[94]
  PIN ct_b[95]
    DIRECTION OUTPUT ;
    USE SIGNAL ;
    PORT
      LAYER M5 ;
        RECT  190.992 0 191.016 0.084 ;
    END
  END ct_b[95]
  PIN ct_b[96]
    DIRECTION OUTPUT ;
    USE SIGNAL ;
    PORT
      LAYER M5 ;
        RECT  166.608 0 166.632 0.084 ;
    END
  END ct_b[96]
  PIN ct_b[97]
    DIRECTION OUTPUT ;
    USE SIGNAL ;
    PORT
      LAYER M5 ;
        RECT  166.8 0 166.824 0.084 ;
    END
  END ct_b[97]
  PIN ct_b[98]
    DIRECTION OUTPUT ;
    USE SIGNAL ;
    PORT
      LAYER M5 ;
        RECT  166.992 0 167.016 0.084 ;
    END
  END ct_b[98]
  PIN ct_b[99]
    DIRECTION OUTPUT ;
    USE SIGNAL ;
    PORT
      LAYER M5 ;
        RECT  167.184 0 167.208 0.084 ;
    END
  END ct_b[99]
  PIN ct_b[9]
    DIRECTION OUTPUT ;
    USE SIGNAL ;
    PORT
      LAYER M5 ;
        RECT  20.88 0 20.904 0.084 ;
    END
  END ct_b[9]
  PIN ct_v
    DIRECTION OUTPUT ;
    USE SIGNAL ;
    PORT
      LAYER M5 ;
        RECT  4.56 0 4.584 0.084 ;
    END
  END ct_v
  PIN cw_a[0]
    DIRECTION INPUT ;
    USE SIGNAL ;
    PORT
      LAYER M5 ;
        RECT  4.752 0 4.776 0.084 ;
    END
  END cw_a[0]
  PIN cw_a[1]
    DIRECTION INPUT ;
    USE SIGNAL ;
    PORT
      LAYER M5 ;
        RECT  4.944 0 4.968 0.084 ;
    END
  END cw_a[1]
  PIN cw_a[2]
    DIRECTION INPUT ;
    USE SIGNAL ;
    PORT
      LAYER M5 ;
        RECT  5.136 0 5.16 0.084 ;
    END
  END cw_a[2]
  PIN cw_a[3]
    DIRECTION INPUT ;
    USE SIGNAL ;
    PORT
      LAYER M5 ;
        RECT  5.328 0 5.352 0.084 ;
    END
  END cw_a[3]
  PIN cw_a[4]
    DIRECTION INPUT ;
    USE SIGNAL ;
    PORT
      LAYER M5 ;
        RECT  5.52 0 5.544 0.084 ;
    END
  END cw_a[4]
  PIN cw_a[5]
    DIRECTION INPUT ;
    USE SIGNAL ;
    PORT
      LAYER M5 ;
        RECT  5.712 0 5.736 0.084 ;
    END
  END cw_a[5]
  PIN cw_a[6]
    DIRECTION INPUT ;
    USE SIGNAL ;
    PORT
      LAYER M5 ;
        RECT  5.904 0 5.928 0.084 ;
    END
  END cw_a[6]
  PIN cw_a[7]
    DIRECTION INPUT ;
    USE SIGNAL ;
    PORT
      LAYER M5 ;
        RECT  6.096 0 6.12 0.084 ;
    END
  END cw_a[7]
  PIN cw_a[8]
    DIRECTION INPUT ;
    USE SIGNAL ;
    PORT
      LAYER M5 ;
        RECT  6.288 0 6.312 0.084 ;
    END
  END cw_a[8]
  PIN cw_a[9]
    DIRECTION INPUT ;
    USE SIGNAL ;
    PORT
      LAYER M5 ;
        RECT  6.48 0 6.504 0.084 ;
    END
  END cw_a[9]
  PIN cw_d[0]
    DIRECTION INPUT ;
    USE SIGNAL ;
    PORT
      LAYER M5 ;
        RECT  6.672 0 6.696 0.084 ;
    END
  END cw_d[0]
  PIN cw_d[100]
    DIRECTION INPUT ;
    USE SIGNAL ;
    PORT
      LAYER M5 ;
        RECT  39.696 0 39.72 0.084 ;
    END
  END cw_d[100]
  PIN cw_d[101]
    DIRECTION INPUT ;
    USE SIGNAL ;
    PORT
      LAYER M5 ;
        RECT  39.888 0 39.912 0.084 ;
    END
  END cw_d[101]
  PIN cw_d[102]
    DIRECTION INPUT ;
    USE SIGNAL ;
    PORT
      LAYER M5 ;
        RECT  40.08 0 40.104 0.084 ;
    END
  END cw_d[102]
  PIN cw_d[103]
    DIRECTION INPUT ;
    USE SIGNAL ;
    PORT
      LAYER M5 ;
        RECT  40.272 0 40.296 0.084 ;
    END
  END cw_d[103]
  PIN cw_d[104]
    DIRECTION INPUT ;
    USE SIGNAL ;
    PORT
      LAYER M5 ;
        RECT  40.464 0 40.488 0.084 ;
    END
  END cw_d[104]
  PIN cw_d[105]
    DIRECTION INPUT ;
    USE SIGNAL ;
    PORT
      LAYER M5 ;
        RECT  40.656 0 40.68 0.084 ;
    END
  END cw_d[105]
  PIN cw_d[106]
    DIRECTION INPUT ;
    USE SIGNAL ;
    PORT
      LAYER M5 ;
        RECT  40.848 0 40.872 0.084 ;
    END
  END cw_d[106]
  PIN cw_d[107]
    DIRECTION INPUT ;
    USE SIGNAL ;
    PORT
      LAYER M5 ;
        RECT  41.04 0 41.064 0.084 ;
    END
  END cw_d[107]
  PIN cw_d[108]
    DIRECTION INPUT ;
    USE SIGNAL ;
    PORT
      LAYER M5 ;
        RECT  41.232 0 41.256 0.084 ;
    END
  END cw_d[108]
  PIN cw_d[109]
    DIRECTION INPUT ;
    USE SIGNAL ;
    PORT
      LAYER M5 ;
        RECT  41.424 0 41.448 0.084 ;
    END
  END cw_d[109]
  PIN cw_d[10]
    DIRECTION INPUT ;
    USE SIGNAL ;
    PORT
      LAYER M5 ;
        RECT  33.168 0 33.192 0.084 ;
    END
  END cw_d[10]
  PIN cw_d[110]
    DIRECTION INPUT ;
    USE SIGNAL ;
    PORT
      LAYER M5 ;
        RECT  41.616 0 41.64 0.084 ;
    END
  END cw_d[110]
  PIN cw_d[111]
    DIRECTION INPUT ;
    USE SIGNAL ;
    PORT
      LAYER M5 ;
        RECT  41.808 0 41.832 0.084 ;
    END
  END cw_d[111]
  PIN cw_d[112]
    DIRECTION INPUT ;
    USE SIGNAL ;
    PORT
      LAYER M5 ;
        RECT  42 0 42.024 0.084 ;
    END
  END cw_d[112]
  PIN cw_d[113]
    DIRECTION INPUT ;
    USE SIGNAL ;
    PORT
      LAYER M5 ;
        RECT  42.192 0 42.216 0.084 ;
    END
  END cw_d[113]
  PIN cw_d[114]
    DIRECTION INPUT ;
    USE SIGNAL ;
    PORT
      LAYER M5 ;
        RECT  42.384 0 42.408 0.084 ;
    END
  END cw_d[114]
  PIN cw_d[115]
    DIRECTION INPUT ;
    USE SIGNAL ;
    PORT
      LAYER M5 ;
        RECT  42.576 0 42.6 0.084 ;
    END
  END cw_d[115]
  PIN cw_d[116]
    DIRECTION INPUT ;
    USE SIGNAL ;
    PORT
      LAYER M5 ;
        RECT  42.768 0 42.792 0.084 ;
    END
  END cw_d[116]
  PIN cw_d[117]
    DIRECTION INPUT ;
    USE SIGNAL ;
    PORT
      LAYER M5 ;
        RECT  42.96 0 42.984 0.084 ;
    END
  END cw_d[117]
  PIN cw_d[118]
    DIRECTION INPUT ;
    USE SIGNAL ;
    PORT
      LAYER M5 ;
        RECT  43.152 0 43.176 0.084 ;
    END
  END cw_d[118]
  PIN cw_d[119]
    DIRECTION INPUT ;
    USE SIGNAL ;
    PORT
      LAYER M5 ;
        RECT  43.344 0 43.368 0.084 ;
    END
  END cw_d[119]
  PIN cw_d[11]
    DIRECTION INPUT ;
    USE SIGNAL ;
    PORT
      LAYER M5 ;
        RECT  33.36 0 33.384 0.084 ;
    END
  END cw_d[11]
  PIN cw_d[120]
    DIRECTION INPUT ;
    USE SIGNAL ;
    PORT
      LAYER M5 ;
        RECT  43.536 0 43.56 0.084 ;
    END
  END cw_d[120]
  PIN cw_d[121]
    DIRECTION INPUT ;
    USE SIGNAL ;
    PORT
      LAYER M5 ;
        RECT  43.728 0 43.752 0.084 ;
    END
  END cw_d[121]
  PIN cw_d[122]
    DIRECTION INPUT ;
    USE SIGNAL ;
    PORT
      LAYER M5 ;
        RECT  43.92 0 43.944 0.084 ;
    END
  END cw_d[122]
  PIN cw_d[123]
    DIRECTION INPUT ;
    USE SIGNAL ;
    PORT
      LAYER M5 ;
        RECT  44.112 0 44.136 0.084 ;
    END
  END cw_d[123]
  PIN cw_d[124]
    DIRECTION INPUT ;
    USE SIGNAL ;
    PORT
      LAYER M5 ;
        RECT  44.304 0 44.328 0.084 ;
    END
  END cw_d[124]
  PIN cw_d[125]
    DIRECTION INPUT ;
    USE SIGNAL ;
    PORT
      LAYER M5 ;
        RECT  44.496 0 44.52 0.084 ;
    END
  END cw_d[125]
  PIN cw_d[126]
    DIRECTION INPUT ;
    USE SIGNAL ;
    PORT
      LAYER M5 ;
        RECT  44.688 0 44.712 0.084 ;
    END
  END cw_d[126]
  PIN cw_d[127]
    DIRECTION INPUT ;
    USE SIGNAL ;
    PORT
      LAYER M5 ;
        RECT  44.88 0 44.904 0.084 ;
    END
  END cw_d[127]
  PIN cw_d[128]
    DIRECTION INPUT ;
    USE SIGNAL ;
    PORT
      LAYER M5 ;
        RECT  45.072 0 45.096 0.084 ;
    END
  END cw_d[128]
  PIN cw_d[129]
    DIRECTION INPUT ;
    USE SIGNAL ;
    PORT
      LAYER M5 ;
        RECT  45.264 0 45.288 0.084 ;
    END
  END cw_d[129]
  PIN cw_d[12]
    DIRECTION INPUT ;
    USE SIGNAL ;
    PORT
      LAYER M5 ;
        RECT  33.552 0 33.576 0.084 ;
    END
  END cw_d[12]
  PIN cw_d[130]
    DIRECTION INPUT ;
    USE SIGNAL ;
    PORT
      LAYER M5 ;
        RECT  45.456 0 45.48 0.084 ;
    END
  END cw_d[130]
  PIN cw_d[131]
    DIRECTION INPUT ;
    USE SIGNAL ;
    PORT
      LAYER M5 ;
        RECT  45.648 0 45.672 0.084 ;
    END
  END cw_d[131]
  PIN cw_d[132]
    DIRECTION INPUT ;
    USE SIGNAL ;
    PORT
      LAYER M5 ;
        RECT  45.84 0 45.864 0.084 ;
    END
  END cw_d[132]
  PIN cw_d[133]
    DIRECTION INPUT ;
    USE SIGNAL ;
    PORT
      LAYER M5 ;
        RECT  46.032 0 46.056 0.084 ;
    END
  END cw_d[133]
  PIN cw_d[134]
    DIRECTION INPUT ;
    USE SIGNAL ;
    PORT
      LAYER M5 ;
        RECT  46.224 0 46.248 0.084 ;
    END
  END cw_d[134]
  PIN cw_d[135]
    DIRECTION INPUT ;
    USE SIGNAL ;
    PORT
      LAYER M5 ;
        RECT  46.416 0 46.44 0.084 ;
    END
  END cw_d[135]
  PIN cw_d[136]
    DIRECTION INPUT ;
    USE SIGNAL ;
    PORT
      LAYER M5 ;
        RECT  46.608 0 46.632 0.084 ;
    END
  END cw_d[136]
  PIN cw_d[137]
    DIRECTION INPUT ;
    USE SIGNAL ;
    PORT
      LAYER M5 ;
        RECT  46.8 0 46.824 0.084 ;
    END
  END cw_d[137]
  PIN cw_d[138]
    DIRECTION INPUT ;
    USE SIGNAL ;
    PORT
      LAYER M5 ;
        RECT  46.992 0 47.016 0.084 ;
    END
  END cw_d[138]
  PIN cw_d[139]
    DIRECTION INPUT ;
    USE SIGNAL ;
    PORT
      LAYER M5 ;
        RECT  47.184 0 47.208 0.084 ;
    END
  END cw_d[139]
  PIN cw_d[13]
    DIRECTION INPUT ;
    USE SIGNAL ;
    PORT
      LAYER M5 ;
        RECT  33.744 0 33.768 0.084 ;
    END
  END cw_d[13]
  PIN cw_d[140]
    DIRECTION INPUT ;
    USE SIGNAL ;
    PORT
      LAYER M5 ;
        RECT  47.376 0 47.4 0.084 ;
    END
  END cw_d[140]
  PIN cw_d[141]
    DIRECTION INPUT ;
    USE SIGNAL ;
    PORT
      LAYER M5 ;
        RECT  47.568 0 47.592 0.084 ;
    END
  END cw_d[141]
  PIN cw_d[142]
    DIRECTION INPUT ;
    USE SIGNAL ;
    PORT
      LAYER M5 ;
        RECT  47.76 0 47.784 0.084 ;
    END
  END cw_d[142]
  PIN cw_d[143]
    DIRECTION INPUT ;
    USE SIGNAL ;
    PORT
      LAYER M5 ;
        RECT  47.952 0 47.976 0.084 ;
    END
  END cw_d[143]
  PIN cw_d[144]
    DIRECTION INPUT ;
    USE SIGNAL ;
    PORT
      LAYER M5 ;
        RECT  48.144 0 48.168 0.084 ;
    END
  END cw_d[144]
  PIN cw_d[145]
    DIRECTION INPUT ;
    USE SIGNAL ;
    PORT
      LAYER M5 ;
        RECT  48.336 0 48.36 0.084 ;
    END
  END cw_d[145]
  PIN cw_d[146]
    DIRECTION INPUT ;
    USE SIGNAL ;
    PORT
      LAYER M5 ;
        RECT  48.528 0 48.552 0.084 ;
    END
  END cw_d[146]
  PIN cw_d[147]
    DIRECTION INPUT ;
    USE SIGNAL ;
    PORT
      LAYER M5 ;
        RECT  48.72 0 48.744 0.084 ;
    END
  END cw_d[147]
  PIN cw_d[148]
    DIRECTION INPUT ;
    USE SIGNAL ;
    PORT
      LAYER M5 ;
        RECT  48.912 0 48.936 0.084 ;
    END
  END cw_d[148]
  PIN cw_d[149]
    DIRECTION INPUT ;
    USE SIGNAL ;
    PORT
      LAYER M5 ;
        RECT  49.104 0 49.128 0.084 ;
    END
  END cw_d[149]
  PIN cw_d[14]
    DIRECTION INPUT ;
    USE SIGNAL ;
    PORT
      LAYER M5 ;
        RECT  33.936 0 33.96 0.084 ;
    END
  END cw_d[14]
  PIN cw_d[150]
    DIRECTION INPUT ;
    USE SIGNAL ;
    PORT
      LAYER M5 ;
        RECT  49.296 0 49.32 0.084 ;
    END
  END cw_d[150]
  PIN cw_d[151]
    DIRECTION INPUT ;
    USE SIGNAL ;
    PORT
      LAYER M5 ;
        RECT  49.488 0 49.512 0.084 ;
    END
  END cw_d[151]
  PIN cw_d[152]
    DIRECTION INPUT ;
    USE SIGNAL ;
    PORT
      LAYER M5 ;
        RECT  49.68 0 49.704 0.084 ;
    END
  END cw_d[152]
  PIN cw_d[153]
    DIRECTION INPUT ;
    USE SIGNAL ;
    PORT
      LAYER M5 ;
        RECT  49.872 0 49.896 0.084 ;
    END
  END cw_d[153]
  PIN cw_d[154]
    DIRECTION INPUT ;
    USE SIGNAL ;
    PORT
      LAYER M5 ;
        RECT  50.064 0 50.088 0.084 ;
    END
  END cw_d[154]
  PIN cw_d[155]
    DIRECTION INPUT ;
    USE SIGNAL ;
    PORT
      LAYER M5 ;
        RECT  50.256 0 50.28 0.084 ;
    END
  END cw_d[155]
  PIN cw_d[156]
    DIRECTION INPUT ;
    USE SIGNAL ;
    PORT
      LAYER M5 ;
        RECT  50.448 0 50.472 0.084 ;
    END
  END cw_d[156]
  PIN cw_d[157]
    DIRECTION INPUT ;
    USE SIGNAL ;
    PORT
      LAYER M5 ;
        RECT  50.64 0 50.664 0.084 ;
    END
  END cw_d[157]
  PIN cw_d[158]
    DIRECTION INPUT ;
    USE SIGNAL ;
    PORT
      LAYER M5 ;
        RECT  50.832 0 50.856 0.084 ;
    END
  END cw_d[158]
  PIN cw_d[159]
    DIRECTION INPUT ;
    USE SIGNAL ;
    PORT
      LAYER M5 ;
        RECT  51.024 0 51.048 0.084 ;
    END
  END cw_d[159]
  PIN cw_d[15]
    DIRECTION INPUT ;
    USE SIGNAL ;
    PORT
      LAYER M5 ;
        RECT  34.128 0 34.152 0.084 ;
    END
  END cw_d[15]
  PIN cw_d[160]
    DIRECTION INPUT ;
    USE SIGNAL ;
    PORT
      LAYER M5 ;
        RECT  51.216 0 51.24 0.084 ;
    END
  END cw_d[160]
  PIN cw_d[161]
    DIRECTION INPUT ;
    USE SIGNAL ;
    PORT
      LAYER M5 ;
        RECT  63.696 0 63.72 0.084 ;
    END
  END cw_d[161]
  PIN cw_d[162]
    DIRECTION INPUT ;
    USE SIGNAL ;
    PORT
      LAYER M5 ;
        RECT  63.888 0 63.912 0.084 ;
    END
  END cw_d[162]
  PIN cw_d[163]
    DIRECTION INPUT ;
    USE SIGNAL ;
    PORT
      LAYER M5 ;
        RECT  64.08 0 64.104 0.084 ;
    END
  END cw_d[163]
  PIN cw_d[164]
    DIRECTION INPUT ;
    USE SIGNAL ;
    PORT
      LAYER M5 ;
        RECT  64.272 0 64.296 0.084 ;
    END
  END cw_d[164]
  PIN cw_d[165]
    DIRECTION INPUT ;
    USE SIGNAL ;
    PORT
      LAYER M5 ;
        RECT  64.464 0 64.488 0.084 ;
    END
  END cw_d[165]
  PIN cw_d[166]
    DIRECTION INPUT ;
    USE SIGNAL ;
    PORT
      LAYER M5 ;
        RECT  64.656 0 64.68 0.084 ;
    END
  END cw_d[166]
  PIN cw_d[167]
    DIRECTION INPUT ;
    USE SIGNAL ;
    PORT
      LAYER M5 ;
        RECT  64.848 0 64.872 0.084 ;
    END
  END cw_d[167]
  PIN cw_d[168]
    DIRECTION INPUT ;
    USE SIGNAL ;
    PORT
      LAYER M5 ;
        RECT  65.04 0 65.064 0.084 ;
    END
  END cw_d[168]
  PIN cw_d[169]
    DIRECTION INPUT ;
    USE SIGNAL ;
    PORT
      LAYER M5 ;
        RECT  65.232 0 65.256 0.084 ;
    END
  END cw_d[169]
  PIN cw_d[16]
    DIRECTION INPUT ;
    USE SIGNAL ;
    PORT
      LAYER M5 ;
        RECT  34.32 0 34.344 0.084 ;
    END
  END cw_d[16]
  PIN cw_d[170]
    DIRECTION INPUT ;
    USE SIGNAL ;
    PORT
      LAYER M5 ;
        RECT  65.424 0 65.448 0.084 ;
    END
  END cw_d[170]
  PIN cw_d[171]
    DIRECTION INPUT ;
    USE SIGNAL ;
    PORT
      LAYER M5 ;
        RECT  65.616 0 65.64 0.084 ;
    END
  END cw_d[171]
  PIN cw_d[172]
    DIRECTION INPUT ;
    USE SIGNAL ;
    PORT
      LAYER M5 ;
        RECT  65.808 0 65.832 0.084 ;
    END
  END cw_d[172]
  PIN cw_d[173]
    DIRECTION INPUT ;
    USE SIGNAL ;
    PORT
      LAYER M5 ;
        RECT  66 0 66.024 0.084 ;
    END
  END cw_d[173]
  PIN cw_d[174]
    DIRECTION INPUT ;
    USE SIGNAL ;
    PORT
      LAYER M5 ;
        RECT  66.192 0 66.216 0.084 ;
    END
  END cw_d[174]
  PIN cw_d[175]
    DIRECTION INPUT ;
    USE SIGNAL ;
    PORT
      LAYER M5 ;
        RECT  66.384 0 66.408 0.084 ;
    END
  END cw_d[175]
  PIN cw_d[176]
    DIRECTION INPUT ;
    USE SIGNAL ;
    PORT
      LAYER M5 ;
        RECT  66.576 0 66.6 0.084 ;
    END
  END cw_d[176]
  PIN cw_d[177]
    DIRECTION INPUT ;
    USE SIGNAL ;
    PORT
      LAYER M5 ;
        RECT  66.768 0 66.792 0.084 ;
    END
  END cw_d[177]
  PIN cw_d[178]
    DIRECTION INPUT ;
    USE SIGNAL ;
    PORT
      LAYER M5 ;
        RECT  66.96 0 66.984 0.084 ;
    END
  END cw_d[178]
  PIN cw_d[179]
    DIRECTION INPUT ;
    USE SIGNAL ;
    PORT
      LAYER M5 ;
        RECT  67.152 0 67.176 0.084 ;
    END
  END cw_d[179]
  PIN cw_d[17]
    DIRECTION INPUT ;
    USE SIGNAL ;
    PORT
      LAYER M5 ;
        RECT  34.512 0 34.536 0.084 ;
    END
  END cw_d[17]
  PIN cw_d[180]
    DIRECTION INPUT ;
    USE SIGNAL ;
    PORT
      LAYER M5 ;
        RECT  67.344 0 67.368 0.084 ;
    END
  END cw_d[180]
  PIN cw_d[181]
    DIRECTION INPUT ;
    USE SIGNAL ;
    PORT
      LAYER M5 ;
        RECT  67.536 0 67.56 0.084 ;
    END
  END cw_d[181]
  PIN cw_d[182]
    DIRECTION INPUT ;
    USE SIGNAL ;
    PORT
      LAYER M5 ;
        RECT  67.728 0 67.752 0.084 ;
    END
  END cw_d[182]
  PIN cw_d[183]
    DIRECTION INPUT ;
    USE SIGNAL ;
    PORT
      LAYER M5 ;
        RECT  67.92 0 67.944 0.084 ;
    END
  END cw_d[183]
  PIN cw_d[184]
    DIRECTION INPUT ;
    USE SIGNAL ;
    PORT
      LAYER M5 ;
        RECT  68.112 0 68.136 0.084 ;
    END
  END cw_d[184]
  PIN cw_d[185]
    DIRECTION INPUT ;
    USE SIGNAL ;
    PORT
      LAYER M5 ;
        RECT  68.304 0 68.328 0.084 ;
    END
  END cw_d[185]
  PIN cw_d[186]
    DIRECTION INPUT ;
    USE SIGNAL ;
    PORT
      LAYER M5 ;
        RECT  68.496 0 68.52 0.084 ;
    END
  END cw_d[186]
  PIN cw_d[187]
    DIRECTION INPUT ;
    USE SIGNAL ;
    PORT
      LAYER M5 ;
        RECT  68.688 0 68.712 0.084 ;
    END
  END cw_d[187]
  PIN cw_d[188]
    DIRECTION INPUT ;
    USE SIGNAL ;
    PORT
      LAYER M5 ;
        RECT  68.88 0 68.904 0.084 ;
    END
  END cw_d[188]
  PIN cw_d[189]
    DIRECTION INPUT ;
    USE SIGNAL ;
    PORT
      LAYER M5 ;
        RECT  69.072 0 69.096 0.084 ;
    END
  END cw_d[189]
  PIN cw_d[18]
    DIRECTION INPUT ;
    USE SIGNAL ;
    PORT
      LAYER M5 ;
        RECT  34.704 0 34.728 0.084 ;
    END
  END cw_d[18]
  PIN cw_d[190]
    DIRECTION INPUT ;
    USE SIGNAL ;
    PORT
      LAYER M5 ;
        RECT  69.264 0 69.288 0.084 ;
    END
  END cw_d[190]
  PIN cw_d[191]
    DIRECTION INPUT ;
    USE SIGNAL ;
    PORT
      LAYER M5 ;
        RECT  69.456 0 69.48 0.084 ;
    END
  END cw_d[191]
  PIN cw_d[192]
    DIRECTION INPUT ;
    USE SIGNAL ;
    PORT
      LAYER M5 ;
        RECT  69.648 0 69.672 0.084 ;
    END
  END cw_d[192]
  PIN cw_d[193]
    DIRECTION INPUT ;
    USE SIGNAL ;
    PORT
      LAYER M5 ;
        RECT  51.408 0 51.432 0.084 ;
    END
  END cw_d[193]
  PIN cw_d[194]
    DIRECTION INPUT ;
    USE SIGNAL ;
    PORT
      LAYER M5 ;
        RECT  51.6 0 51.624 0.084 ;
    END
  END cw_d[194]
  PIN cw_d[195]
    DIRECTION INPUT ;
    USE SIGNAL ;
    PORT
      LAYER M5 ;
        RECT  51.792 0 51.816 0.084 ;
    END
  END cw_d[195]
  PIN cw_d[196]
    DIRECTION INPUT ;
    USE SIGNAL ;
    PORT
      LAYER M5 ;
        RECT  51.984 0 52.008 0.084 ;
    END
  END cw_d[196]
  PIN cw_d[197]
    DIRECTION INPUT ;
    USE SIGNAL ;
    PORT
      LAYER M5 ;
        RECT  52.176 0 52.2 0.084 ;
    END
  END cw_d[197]
  PIN cw_d[198]
    DIRECTION INPUT ;
    USE SIGNAL ;
    PORT
      LAYER M5 ;
        RECT  52.368 0 52.392 0.084 ;
    END
  END cw_d[198]
  PIN cw_d[199]
    DIRECTION INPUT ;
    USE SIGNAL ;
    PORT
      LAYER M5 ;
        RECT  52.56 0 52.584 0.084 ;
    END
  END cw_d[199]
  PIN cw_d[19]
    DIRECTION INPUT ;
    USE SIGNAL ;
    PORT
      LAYER M5 ;
        RECT  34.896 0 34.92 0.084 ;
    END
  END cw_d[19]
  PIN cw_d[1]
    DIRECTION INPUT ;
    USE SIGNAL ;
    PORT
      LAYER M5 ;
        RECT  31.44 0 31.464 0.084 ;
    END
  END cw_d[1]
  PIN cw_d[200]
    DIRECTION INPUT ;
    USE SIGNAL ;
    PORT
      LAYER M5 ;
        RECT  52.752 0 52.776 0.084 ;
    END
  END cw_d[200]
  PIN cw_d[201]
    DIRECTION INPUT ;
    USE SIGNAL ;
    PORT
      LAYER M5 ;
        RECT  52.944 0 52.968 0.084 ;
    END
  END cw_d[201]
  PIN cw_d[202]
    DIRECTION INPUT ;
    USE SIGNAL ;
    PORT
      LAYER M5 ;
        RECT  53.136 0 53.16 0.084 ;
    END
  END cw_d[202]
  PIN cw_d[203]
    DIRECTION INPUT ;
    USE SIGNAL ;
    PORT
      LAYER M5 ;
        RECT  53.328 0 53.352 0.084 ;
    END
  END cw_d[203]
  PIN cw_d[204]
    DIRECTION INPUT ;
    USE SIGNAL ;
    PORT
      LAYER M5 ;
        RECT  53.52 0 53.544 0.084 ;
    END
  END cw_d[204]
  PIN cw_d[205]
    DIRECTION INPUT ;
    USE SIGNAL ;
    PORT
      LAYER M5 ;
        RECT  53.712 0 53.736 0.084 ;
    END
  END cw_d[205]
  PIN cw_d[206]
    DIRECTION INPUT ;
    USE SIGNAL ;
    PORT
      LAYER M5 ;
        RECT  53.904 0 53.928 0.084 ;
    END
  END cw_d[206]
  PIN cw_d[207]
    DIRECTION INPUT ;
    USE SIGNAL ;
    PORT
      LAYER M5 ;
        RECT  54.096 0 54.12 0.084 ;
    END
  END cw_d[207]
  PIN cw_d[208]
    DIRECTION INPUT ;
    USE SIGNAL ;
    PORT
      LAYER M5 ;
        RECT  54.288 0 54.312 0.084 ;
    END
  END cw_d[208]
  PIN cw_d[209]
    DIRECTION INPUT ;
    USE SIGNAL ;
    PORT
      LAYER M5 ;
        RECT  54.48 0 54.504 0.084 ;
    END
  END cw_d[209]
  PIN cw_d[20]
    DIRECTION INPUT ;
    USE SIGNAL ;
    PORT
      LAYER M5 ;
        RECT  35.088 0 35.112 0.084 ;
    END
  END cw_d[20]
  PIN cw_d[210]
    DIRECTION INPUT ;
    USE SIGNAL ;
    PORT
      LAYER M5 ;
        RECT  54.672 0 54.696 0.084 ;
    END
  END cw_d[210]
  PIN cw_d[211]
    DIRECTION INPUT ;
    USE SIGNAL ;
    PORT
      LAYER M5 ;
        RECT  54.864 0 54.888 0.084 ;
    END
  END cw_d[211]
  PIN cw_d[212]
    DIRECTION INPUT ;
    USE SIGNAL ;
    PORT
      LAYER M5 ;
        RECT  55.056 0 55.08 0.084 ;
    END
  END cw_d[212]
  PIN cw_d[213]
    DIRECTION INPUT ;
    USE SIGNAL ;
    PORT
      LAYER M5 ;
        RECT  55.248 0 55.272 0.084 ;
    END
  END cw_d[213]
  PIN cw_d[214]
    DIRECTION INPUT ;
    USE SIGNAL ;
    PORT
      LAYER M5 ;
        RECT  55.44 0 55.464 0.084 ;
    END
  END cw_d[214]
  PIN cw_d[215]
    DIRECTION INPUT ;
    USE SIGNAL ;
    PORT
      LAYER M5 ;
        RECT  55.632 0 55.656 0.084 ;
    END
  END cw_d[215]
  PIN cw_d[216]
    DIRECTION INPUT ;
    USE SIGNAL ;
    PORT
      LAYER M5 ;
        RECT  55.824 0 55.848 0.084 ;
    END
  END cw_d[216]
  PIN cw_d[217]
    DIRECTION INPUT ;
    USE SIGNAL ;
    PORT
      LAYER M5 ;
        RECT  56.016 0 56.04 0.084 ;
    END
  END cw_d[217]
  PIN cw_d[218]
    DIRECTION INPUT ;
    USE SIGNAL ;
    PORT
      LAYER M5 ;
        RECT  56.208 0 56.232 0.084 ;
    END
  END cw_d[218]
  PIN cw_d[219]
    DIRECTION INPUT ;
    USE SIGNAL ;
    PORT
      LAYER M5 ;
        RECT  56.4 0 56.424 0.084 ;
    END
  END cw_d[219]
  PIN cw_d[21]
    DIRECTION INPUT ;
    USE SIGNAL ;
    PORT
      LAYER M5 ;
        RECT  35.28 0 35.304 0.084 ;
    END
  END cw_d[21]
  PIN cw_d[220]
    DIRECTION INPUT ;
    USE SIGNAL ;
    PORT
      LAYER M5 ;
        RECT  56.592 0 56.616 0.084 ;
    END
  END cw_d[220]
  PIN cw_d[221]
    DIRECTION INPUT ;
    USE SIGNAL ;
    PORT
      LAYER M5 ;
        RECT  56.784 0 56.808 0.084 ;
    END
  END cw_d[221]
  PIN cw_d[222]
    DIRECTION INPUT ;
    USE SIGNAL ;
    PORT
      LAYER M5 ;
        RECT  56.976 0 57 0.084 ;
    END
  END cw_d[222]
  PIN cw_d[223]
    DIRECTION INPUT ;
    USE SIGNAL ;
    PORT
      LAYER M5 ;
        RECT  57.168 0 57.192 0.084 ;
    END
  END cw_d[223]
  PIN cw_d[224]
    DIRECTION INPUT ;
    USE SIGNAL ;
    PORT
      LAYER M5 ;
        RECT  57.36 0 57.384 0.084 ;
    END
  END cw_d[224]
  PIN cw_d[225]
    DIRECTION INPUT ;
    USE SIGNAL ;
    PORT
      LAYER M5 ;
        RECT  77.52 0 77.544 0.084 ;
    END
  END cw_d[225]
  PIN cw_d[226]
    DIRECTION INPUT ;
    USE SIGNAL ;
    PORT
      LAYER M5 ;
        RECT  77.712 0 77.736 0.084 ;
    END
  END cw_d[226]
  PIN cw_d[227]
    DIRECTION INPUT ;
    USE SIGNAL ;
    PORT
      LAYER M5 ;
        RECT  77.904 0 77.928 0.084 ;
    END
  END cw_d[227]
  PIN cw_d[228]
    DIRECTION INPUT ;
    USE SIGNAL ;
    PORT
      LAYER M5 ;
        RECT  78.096 0 78.12 0.084 ;
    END
  END cw_d[228]
  PIN cw_d[229]
    DIRECTION INPUT ;
    USE SIGNAL ;
    PORT
      LAYER M5 ;
        RECT  78.288 0 78.312 0.084 ;
    END
  END cw_d[229]
  PIN cw_d[22]
    DIRECTION INPUT ;
    USE SIGNAL ;
    PORT
      LAYER M5 ;
        RECT  35.472 0 35.496 0.084 ;
    END
  END cw_d[22]
  PIN cw_d[230]
    DIRECTION INPUT ;
    USE SIGNAL ;
    PORT
      LAYER M5 ;
        RECT  78.48 0 78.504 0.084 ;
    END
  END cw_d[230]
  PIN cw_d[231]
    DIRECTION INPUT ;
    USE SIGNAL ;
    PORT
      LAYER M5 ;
        RECT  78.672 0 78.696 0.084 ;
    END
  END cw_d[231]
  PIN cw_d[232]
    DIRECTION INPUT ;
    USE SIGNAL ;
    PORT
      LAYER M5 ;
        RECT  78.864 0 78.888 0.084 ;
    END
  END cw_d[232]
  PIN cw_d[233]
    DIRECTION INPUT ;
    USE SIGNAL ;
    PORT
      LAYER M5 ;
        RECT  79.056 0 79.08 0.084 ;
    END
  END cw_d[233]
  PIN cw_d[234]
    DIRECTION INPUT ;
    USE SIGNAL ;
    PORT
      LAYER M5 ;
        RECT  79.248 0 79.272 0.084 ;
    END
  END cw_d[234]
  PIN cw_d[235]
    DIRECTION INPUT ;
    USE SIGNAL ;
    PORT
      LAYER M5 ;
        RECT  79.44 0 79.464 0.084 ;
    END
  END cw_d[235]
  PIN cw_d[236]
    DIRECTION INPUT ;
    USE SIGNAL ;
    PORT
      LAYER M5 ;
        RECT  79.632 0 79.656 0.084 ;
    END
  END cw_d[236]
  PIN cw_d[237]
    DIRECTION INPUT ;
    USE SIGNAL ;
    PORT
      LAYER M5 ;
        RECT  79.824 0 79.848 0.084 ;
    END
  END cw_d[237]
  PIN cw_d[238]
    DIRECTION INPUT ;
    USE SIGNAL ;
    PORT
      LAYER M5 ;
        RECT  80.016 0 80.04 0.084 ;
    END
  END cw_d[238]
  PIN cw_d[239]
    DIRECTION INPUT ;
    USE SIGNAL ;
    PORT
      LAYER M5 ;
        RECT  80.208 0 80.232 0.084 ;
    END
  END cw_d[239]
  PIN cw_d[23]
    DIRECTION INPUT ;
    USE SIGNAL ;
    PORT
      LAYER M5 ;
        RECT  35.664 0 35.688 0.084 ;
    END
  END cw_d[23]
  PIN cw_d[240]
    DIRECTION INPUT ;
    USE SIGNAL ;
    PORT
      LAYER M5 ;
        RECT  80.4 0 80.424 0.084 ;
    END
  END cw_d[240]
  PIN cw_d[241]
    DIRECTION INPUT ;
    USE SIGNAL ;
    PORT
      LAYER M5 ;
        RECT  80.592 0 80.616 0.084 ;
    END
  END cw_d[241]
  PIN cw_d[242]
    DIRECTION INPUT ;
    USE SIGNAL ;
    PORT
      LAYER M5 ;
        RECT  80.784 0 80.808 0.084 ;
    END
  END cw_d[242]
  PIN cw_d[243]
    DIRECTION INPUT ;
    USE SIGNAL ;
    PORT
      LAYER M5 ;
        RECT  80.976 0 81 0.084 ;
    END
  END cw_d[243]
  PIN cw_d[244]
    DIRECTION INPUT ;
    USE SIGNAL ;
    PORT
      LAYER M5 ;
        RECT  81.168 0 81.192 0.084 ;
    END
  END cw_d[244]
  PIN cw_d[245]
    DIRECTION INPUT ;
    USE SIGNAL ;
    PORT
      LAYER M5 ;
        RECT  81.36 0 81.384 0.084 ;
    END
  END cw_d[245]
  PIN cw_d[246]
    DIRECTION INPUT ;
    USE SIGNAL ;
    PORT
      LAYER M5 ;
        RECT  81.552 0 81.576 0.084 ;
    END
  END cw_d[246]
  PIN cw_d[247]
    DIRECTION INPUT ;
    USE SIGNAL ;
    PORT
      LAYER M5 ;
        RECT  81.744 0 81.768 0.084 ;
    END
  END cw_d[247]
  PIN cw_d[248]
    DIRECTION INPUT ;
    USE SIGNAL ;
    PORT
      LAYER M5 ;
        RECT  81.936 0 81.96 0.084 ;
    END
  END cw_d[248]
  PIN cw_d[249]
    DIRECTION INPUT ;
    USE SIGNAL ;
    PORT
      LAYER M5 ;
        RECT  82.128 0 82.152 0.084 ;
    END
  END cw_d[249]
  PIN cw_d[24]
    DIRECTION INPUT ;
    USE SIGNAL ;
    PORT
      LAYER M5 ;
        RECT  35.856 0 35.88 0.084 ;
    END
  END cw_d[24]
  PIN cw_d[250]
    DIRECTION INPUT ;
    USE SIGNAL ;
    PORT
      LAYER M5 ;
        RECT  82.32 0 82.344 0.084 ;
    END
  END cw_d[250]
  PIN cw_d[251]
    DIRECTION INPUT ;
    USE SIGNAL ;
    PORT
      LAYER M5 ;
        RECT  82.512 0 82.536 0.084 ;
    END
  END cw_d[251]
  PIN cw_d[252]
    DIRECTION INPUT ;
    USE SIGNAL ;
    PORT
      LAYER M5 ;
        RECT  82.704 0 82.728 0.084 ;
    END
  END cw_d[252]
  PIN cw_d[253]
    DIRECTION INPUT ;
    USE SIGNAL ;
    PORT
      LAYER M5 ;
        RECT  82.896 0 82.92 0.084 ;
    END
  END cw_d[253]
  PIN cw_d[254]
    DIRECTION INPUT ;
    USE SIGNAL ;
    PORT
      LAYER M5 ;
        RECT  83.088 0 83.112 0.084 ;
    END
  END cw_d[254]
  PIN cw_d[255]
    DIRECTION INPUT ;
    USE SIGNAL ;
    PORT
      LAYER M5 ;
        RECT  83.28 0 83.304 0.084 ;
    END
  END cw_d[255]
  PIN cw_d[25]
    DIRECTION INPUT ;
    USE SIGNAL ;
    PORT
      LAYER M5 ;
        RECT  36.048 0 36.072 0.084 ;
    END
  END cw_d[25]
  PIN cw_d[26]
    DIRECTION INPUT ;
    USE SIGNAL ;
    PORT
      LAYER M5 ;
        RECT  36.24 0 36.264 0.084 ;
    END
  END cw_d[26]
  PIN cw_d[27]
    DIRECTION INPUT ;
    USE SIGNAL ;
    PORT
      LAYER M5 ;
        RECT  36.432 0 36.456 0.084 ;
    END
  END cw_d[27]
  PIN cw_d[28]
    DIRECTION INPUT ;
    USE SIGNAL ;
    PORT
      LAYER M5 ;
        RECT  36.624 0 36.648 0.084 ;
    END
  END cw_d[28]
  PIN cw_d[29]
    DIRECTION INPUT ;
    USE SIGNAL ;
    PORT
      LAYER M5 ;
        RECT  36.816 0 36.84 0.084 ;
    END
  END cw_d[29]
  PIN cw_d[2]
    DIRECTION INPUT ;
    USE SIGNAL ;
    PORT
      LAYER M5 ;
        RECT  31.632 0 31.656 0.084 ;
    END
  END cw_d[2]
  PIN cw_d[30]
    DIRECTION INPUT ;
    USE SIGNAL ;
    PORT
      LAYER M5 ;
        RECT  37.008 0 37.032 0.084 ;
    END
  END cw_d[30]
  PIN cw_d[31]
    DIRECTION INPUT ;
    USE SIGNAL ;
    PORT
      LAYER M5 ;
        RECT  37.2 0 37.224 0.084 ;
    END
  END cw_d[31]
  PIN cw_d[32]
    DIRECTION INPUT ;
    USE SIGNAL ;
    PORT
      LAYER M5 ;
        RECT  37.392 0 37.416 0.084 ;
    END
  END cw_d[32]
  PIN cw_d[33]
    DIRECTION INPUT ;
    USE SIGNAL ;
    PORT
      LAYER M5 ;
        RECT  57.552 0 57.576 0.084 ;
    END
  END cw_d[33]
  PIN cw_d[34]
    DIRECTION INPUT ;
    USE SIGNAL ;
    PORT
      LAYER M5 ;
        RECT  57.744 0 57.768 0.084 ;
    END
  END cw_d[34]
  PIN cw_d[35]
    DIRECTION INPUT ;
    USE SIGNAL ;
    PORT
      LAYER M5 ;
        RECT  57.936 0 57.96 0.084 ;
    END
  END cw_d[35]
  PIN cw_d[36]
    DIRECTION INPUT ;
    USE SIGNAL ;
    PORT
      LAYER M5 ;
        RECT  58.128 0 58.152 0.084 ;
    END
  END cw_d[36]
  PIN cw_d[37]
    DIRECTION INPUT ;
    USE SIGNAL ;
    PORT
      LAYER M5 ;
        RECT  58.32 0 58.344 0.084 ;
    END
  END cw_d[37]
  PIN cw_d[38]
    DIRECTION INPUT ;
    USE SIGNAL ;
    PORT
      LAYER M5 ;
        RECT  58.512 0 58.536 0.084 ;
    END
  END cw_d[38]
  PIN cw_d[39]
    DIRECTION INPUT ;
    USE SIGNAL ;
    PORT
      LAYER M5 ;
        RECT  58.704 0 58.728 0.084 ;
    END
  END cw_d[39]
  PIN cw_d[3]
    DIRECTION INPUT ;
    USE SIGNAL ;
    PORT
      LAYER M5 ;
        RECT  31.824 0 31.848 0.084 ;
    END
  END cw_d[3]
  PIN cw_d[40]
    DIRECTION INPUT ;
    USE SIGNAL ;
    PORT
      LAYER M5 ;
        RECT  58.896 0 58.92 0.084 ;
    END
  END cw_d[40]
  PIN cw_d[41]
    DIRECTION INPUT ;
    USE SIGNAL ;
    PORT
      LAYER M5 ;
        RECT  59.088 0 59.112 0.084 ;
    END
  END cw_d[41]
  PIN cw_d[42]
    DIRECTION INPUT ;
    USE SIGNAL ;
    PORT
      LAYER M5 ;
        RECT  59.28 0 59.304 0.084 ;
    END
  END cw_d[42]
  PIN cw_d[43]
    DIRECTION INPUT ;
    USE SIGNAL ;
    PORT
      LAYER M5 ;
        RECT  59.472 0 59.496 0.084 ;
    END
  END cw_d[43]
  PIN cw_d[44]
    DIRECTION INPUT ;
    USE SIGNAL ;
    PORT
      LAYER M5 ;
        RECT  59.664 0 59.688 0.084 ;
    END
  END cw_d[44]
  PIN cw_d[45]
    DIRECTION INPUT ;
    USE SIGNAL ;
    PORT
      LAYER M5 ;
        RECT  59.856 0 59.88 0.084 ;
    END
  END cw_d[45]
  PIN cw_d[46]
    DIRECTION INPUT ;
    USE SIGNAL ;
    PORT
      LAYER M5 ;
        RECT  60.048 0 60.072 0.084 ;
    END
  END cw_d[46]
  PIN cw_d[47]
    DIRECTION INPUT ;
    USE SIGNAL ;
    PORT
      LAYER M5 ;
        RECT  60.24 0 60.264 0.084 ;
    END
  END cw_d[47]
  PIN cw_d[48]
    DIRECTION INPUT ;
    USE SIGNAL ;
    PORT
      LAYER M5 ;
        RECT  60.432 0 60.456 0.084 ;
    END
  END cw_d[48]
  PIN cw_d[49]
    DIRECTION INPUT ;
    USE SIGNAL ;
    PORT
      LAYER M5 ;
        RECT  60.624 0 60.648 0.084 ;
    END
  END cw_d[49]
  PIN cw_d[4]
    DIRECTION INPUT ;
    USE SIGNAL ;
    PORT
      LAYER M5 ;
        RECT  32.016 0 32.04 0.084 ;
    END
  END cw_d[4]
  PIN cw_d[50]
    DIRECTION INPUT ;
    USE SIGNAL ;
    PORT
      LAYER M5 ;
        RECT  60.816 0 60.84 0.084 ;
    END
  END cw_d[50]
  PIN cw_d[51]
    DIRECTION INPUT ;
    USE SIGNAL ;
    PORT
      LAYER M5 ;
        RECT  61.008 0 61.032 0.084 ;
    END
  END cw_d[51]
  PIN cw_d[52]
    DIRECTION INPUT ;
    USE SIGNAL ;
    PORT
      LAYER M5 ;
        RECT  61.2 0 61.224 0.084 ;
    END
  END cw_d[52]
  PIN cw_d[53]
    DIRECTION INPUT ;
    USE SIGNAL ;
    PORT
      LAYER M5 ;
        RECT  61.392 0 61.416 0.084 ;
    END
  END cw_d[53]
  PIN cw_d[54]
    DIRECTION INPUT ;
    USE SIGNAL ;
    PORT
      LAYER M5 ;
        RECT  61.584 0 61.608 0.084 ;
    END
  END cw_d[54]
  PIN cw_d[55]
    DIRECTION INPUT ;
    USE SIGNAL ;
    PORT
      LAYER M5 ;
        RECT  61.776 0 61.8 0.084 ;
    END
  END cw_d[55]
  PIN cw_d[56]
    DIRECTION INPUT ;
    USE SIGNAL ;
    PORT
      LAYER M5 ;
        RECT  61.968 0 61.992 0.084 ;
    END
  END cw_d[56]
  PIN cw_d[57]
    DIRECTION INPUT ;
    USE SIGNAL ;
    PORT
      LAYER M5 ;
        RECT  62.16 0 62.184 0.084 ;
    END
  END cw_d[57]
  PIN cw_d[58]
    DIRECTION INPUT ;
    USE SIGNAL ;
    PORT
      LAYER M5 ;
        RECT  62.352 0 62.376 0.084 ;
    END
  END cw_d[58]
  PIN cw_d[59]
    DIRECTION INPUT ;
    USE SIGNAL ;
    PORT
      LAYER M5 ;
        RECT  62.544 0 62.568 0.084 ;
    END
  END cw_d[59]
  PIN cw_d[5]
    DIRECTION INPUT ;
    USE SIGNAL ;
    PORT
      LAYER M5 ;
        RECT  32.208 0 32.232 0.084 ;
    END
  END cw_d[5]
  PIN cw_d[60]
    DIRECTION INPUT ;
    USE SIGNAL ;
    PORT
      LAYER M5 ;
        RECT  62.736 0 62.76 0.084 ;
    END
  END cw_d[60]
  PIN cw_d[61]
    DIRECTION INPUT ;
    USE SIGNAL ;
    PORT
      LAYER M5 ;
        RECT  62.928 0 62.952 0.084 ;
    END
  END cw_d[61]
  PIN cw_d[62]
    DIRECTION INPUT ;
    USE SIGNAL ;
    PORT
      LAYER M5 ;
        RECT  63.12 0 63.144 0.084 ;
    END
  END cw_d[62]
  PIN cw_d[63]
    DIRECTION INPUT ;
    USE SIGNAL ;
    PORT
      LAYER M5 ;
        RECT  63.312 0 63.336 0.084 ;
    END
  END cw_d[63]
  PIN cw_d[64]
    DIRECTION INPUT ;
    USE SIGNAL ;
    PORT
      LAYER M5 ;
        RECT  63.504 0 63.528 0.084 ;
    END
  END cw_d[64]
  PIN cw_d[65]
    DIRECTION INPUT ;
    USE SIGNAL ;
    PORT
      LAYER M5 ;
        RECT  69.84 0 69.864 0.084 ;
    END
  END cw_d[65]
  PIN cw_d[66]
    DIRECTION INPUT ;
    USE SIGNAL ;
    PORT
      LAYER M5 ;
        RECT  70.032 0 70.056 0.084 ;
    END
  END cw_d[66]
  PIN cw_d[67]
    DIRECTION INPUT ;
    USE SIGNAL ;
    PORT
      LAYER M5 ;
        RECT  70.224 0 70.248 0.084 ;
    END
  END cw_d[67]
  PIN cw_d[68]
    DIRECTION INPUT ;
    USE SIGNAL ;
    PORT
      LAYER M5 ;
        RECT  70.416 0 70.44 0.084 ;
    END
  END cw_d[68]
  PIN cw_d[69]
    DIRECTION INPUT ;
    USE SIGNAL ;
    PORT
      LAYER M5 ;
        RECT  70.608 0 70.632 0.084 ;
    END
  END cw_d[69]
  PIN cw_d[6]
    DIRECTION INPUT ;
    USE SIGNAL ;
    PORT
      LAYER M5 ;
        RECT  32.4 0 32.424 0.084 ;
    END
  END cw_d[6]
  PIN cw_d[70]
    DIRECTION INPUT ;
    USE SIGNAL ;
    PORT
      LAYER M5 ;
        RECT  70.8 0 70.824 0.084 ;
    END
  END cw_d[70]
  PIN cw_d[71]
    DIRECTION INPUT ;
    USE SIGNAL ;
    PORT
      LAYER M5 ;
        RECT  70.992 0 71.016 0.084 ;
    END
  END cw_d[71]
  PIN cw_d[72]
    DIRECTION INPUT ;
    USE SIGNAL ;
    PORT
      LAYER M5 ;
        RECT  71.184 0 71.208 0.084 ;
    END
  END cw_d[72]
  PIN cw_d[73]
    DIRECTION INPUT ;
    USE SIGNAL ;
    PORT
      LAYER M5 ;
        RECT  71.376 0 71.4 0.084 ;
    END
  END cw_d[73]
  PIN cw_d[74]
    DIRECTION INPUT ;
    USE SIGNAL ;
    PORT
      LAYER M5 ;
        RECT  71.568 0 71.592 0.084 ;
    END
  END cw_d[74]
  PIN cw_d[75]
    DIRECTION INPUT ;
    USE SIGNAL ;
    PORT
      LAYER M5 ;
        RECT  71.76 0 71.784 0.084 ;
    END
  END cw_d[75]
  PIN cw_d[76]
    DIRECTION INPUT ;
    USE SIGNAL ;
    PORT
      LAYER M5 ;
        RECT  71.952 0 71.976 0.084 ;
    END
  END cw_d[76]
  PIN cw_d[77]
    DIRECTION INPUT ;
    USE SIGNAL ;
    PORT
      LAYER M5 ;
        RECT  72.144 0 72.168 0.084 ;
    END
  END cw_d[77]
  PIN cw_d[78]
    DIRECTION INPUT ;
    USE SIGNAL ;
    PORT
      LAYER M5 ;
        RECT  72.336 0 72.36 0.084 ;
    END
  END cw_d[78]
  PIN cw_d[79]
    DIRECTION INPUT ;
    USE SIGNAL ;
    PORT
      LAYER M5 ;
        RECT  72.528 0 72.552 0.084 ;
    END
  END cw_d[79]
  PIN cw_d[7]
    DIRECTION INPUT ;
    USE SIGNAL ;
    PORT
      LAYER M5 ;
        RECT  32.592 0 32.616 0.084 ;
    END
  END cw_d[7]
  PIN cw_d[80]
    DIRECTION INPUT ;
    USE SIGNAL ;
    PORT
      LAYER M5 ;
        RECT  72.72 0 72.744 0.084 ;
    END
  END cw_d[80]
  PIN cw_d[81]
    DIRECTION INPUT ;
    USE SIGNAL ;
    PORT
      LAYER M5 ;
        RECT  72.912 0 72.936 0.084 ;
    END
  END cw_d[81]
  PIN cw_d[82]
    DIRECTION INPUT ;
    USE SIGNAL ;
    PORT
      LAYER M5 ;
        RECT  73.104 0 73.128 0.084 ;
    END
  END cw_d[82]
  PIN cw_d[83]
    DIRECTION INPUT ;
    USE SIGNAL ;
    PORT
      LAYER M5 ;
        RECT  73.296 0 73.32 0.084 ;
    END
  END cw_d[83]
  PIN cw_d[84]
    DIRECTION INPUT ;
    USE SIGNAL ;
    PORT
      LAYER M5 ;
        RECT  73.488 0 73.512 0.084 ;
    END
  END cw_d[84]
  PIN cw_d[85]
    DIRECTION INPUT ;
    USE SIGNAL ;
    PORT
      LAYER M5 ;
        RECT  73.68 0 73.704 0.084 ;
    END
  END cw_d[85]
  PIN cw_d[86]
    DIRECTION INPUT ;
    USE SIGNAL ;
    PORT
      LAYER M5 ;
        RECT  73.872 0 73.896 0.084 ;
    END
  END cw_d[86]
  PIN cw_d[87]
    DIRECTION INPUT ;
    USE SIGNAL ;
    PORT
      LAYER M5 ;
        RECT  74.064 0 74.088 0.084 ;
    END
  END cw_d[87]
  PIN cw_d[88]
    DIRECTION INPUT ;
    USE SIGNAL ;
    PORT
      LAYER M5 ;
        RECT  74.256 0 74.28 0.084 ;
    END
  END cw_d[88]
  PIN cw_d[89]
    DIRECTION INPUT ;
    USE SIGNAL ;
    PORT
      LAYER M5 ;
        RECT  74.448 0 74.472 0.084 ;
    END
  END cw_d[89]
  PIN cw_d[8]
    DIRECTION INPUT ;
    USE SIGNAL ;
    PORT
      LAYER M5 ;
        RECT  32.784 0 32.808 0.084 ;
    END
  END cw_d[8]
  PIN cw_d[90]
    DIRECTION INPUT ;
    USE SIGNAL ;
    PORT
      LAYER M5 ;
        RECT  74.64 0 74.664 0.084 ;
    END
  END cw_d[90]
  PIN cw_d[91]
    DIRECTION INPUT ;
    USE SIGNAL ;
    PORT
      LAYER M5 ;
        RECT  74.832 0 74.856 0.084 ;
    END
  END cw_d[91]
  PIN cw_d[92]
    DIRECTION INPUT ;
    USE SIGNAL ;
    PORT
      LAYER M5 ;
        RECT  75.024 0 75.048 0.084 ;
    END
  END cw_d[92]
  PIN cw_d[93]
    DIRECTION INPUT ;
    USE SIGNAL ;
    PORT
      LAYER M5 ;
        RECT  75.216 0 75.24 0.084 ;
    END
  END cw_d[93]
  PIN cw_d[94]
    DIRECTION INPUT ;
    USE SIGNAL ;
    PORT
      LAYER M5 ;
        RECT  75.408 0 75.432 0.084 ;
    END
  END cw_d[94]
  PIN cw_d[95]
    DIRECTION INPUT ;
    USE SIGNAL ;
    PORT
      LAYER M5 ;
        RECT  75.6 0 75.624 0.084 ;
    END
  END cw_d[95]
  PIN cw_d[96]
    DIRECTION INPUT ;
    USE SIGNAL ;
    PORT
      LAYER M5 ;
        RECT  75.792 0 75.816 0.084 ;
    END
  END cw_d[96]
  PIN cw_d[97]
    DIRECTION INPUT ;
    USE SIGNAL ;
    PORT
      LAYER M5 ;
        RECT  39.12 0 39.144 0.084 ;
    END
  END cw_d[97]
  PIN cw_d[98]
    DIRECTION INPUT ;
    USE SIGNAL ;
    PORT
      LAYER M5 ;
        RECT  39.312 0 39.336 0.084 ;
    END
  END cw_d[98]
  PIN cw_d[99]
    DIRECTION INPUT ;
    USE SIGNAL ;
    PORT
      LAYER M5 ;
        RECT  39.504 0 39.528 0.084 ;
    END
  END cw_d[99]
  PIN cw_d[9]
    DIRECTION INPUT ;
    USE SIGNAL ;
    PORT
      LAYER M5 ;
        RECT  32.976 0 33 0.084 ;
    END
  END cw_d[9]
  PIN cw_v
    DIRECTION INPUT ;
    USE SIGNAL ;
    PORT
      LAYER M5 ;
        RECT  83.472 0 83.496 0.084 ;
    END
  END cw_v
  PIN fault
    DIRECTION OUTPUT ;
    USE SIGNAL ;
    PORT
      LAYER M5 ;
        RECT  95.952 0 95.976 0.084 ;
    END
  END fault
  PIN launch
    DIRECTION INPUT ;
    USE SIGNAL ;
    PORT
      LAYER M5 ;
        RECT  96.144 0 96.168 0.084 ;
    END
  END launch
  PIN mx_i[0]
    DIRECTION INPUT ;
    USE SIGNAL ;
    PORT
      LAYER M5 ;
        RECT  96.336 0 96.36 0.084 ;
    END
  END mx_i[0]
  PIN mx_i[1]
    DIRECTION INPUT ;
    USE SIGNAL ;
    PORT
      LAYER M5 ;
        RECT  96.528 0 96.552 0.084 ;
    END
  END mx_i[1]
  PIN mx_i[2]
    DIRECTION INPUT ;
    USE SIGNAL ;
    PORT
      LAYER M5 ;
        RECT  96.72 0 96.744 0.084 ;
    END
  END mx_i[2]
  PIN mx_i[3]
    DIRECTION INPUT ;
    USE SIGNAL ;
    PORT
      LAYER M5 ;
        RECT  96.912 0 96.936 0.084 ;
    END
  END mx_i[3]
  PIN mx_i[4]
    DIRECTION INPUT ;
    USE SIGNAL ;
    PORT
      LAYER M5 ;
        RECT  97.104 0 97.128 0.084 ;
    END
  END mx_i[4]
  PIN mx_v
    DIRECTION INPUT ;
    USE SIGNAL ;
    PORT
      LAYER M5 ;
        RECT  97.296 0 97.32 0.084 ;
    END
  END mx_v
  PIN mx_y[0]
    DIRECTION INPUT ;
    USE SIGNAL ;
    PORT
      LAYER M5 ;
        RECT  97.488 0 97.512 0.084 ;
    END
  END mx_y[0]
  PIN mx_y[10]
    DIRECTION INPUT ;
    USE SIGNAL ;
    PORT
      LAYER M5 ;
        RECT  99.408 0 99.432 0.084 ;
    END
  END mx_y[10]
  PIN mx_y[11]
    DIRECTION INPUT ;
    USE SIGNAL ;
    PORT
      LAYER M5 ;
        RECT  99.6 0 99.624 0.084 ;
    END
  END mx_y[11]
  PIN mx_y[12]
    DIRECTION INPUT ;
    USE SIGNAL ;
    PORT
      LAYER M5 ;
        RECT  99.792 0 99.816 0.084 ;
    END
  END mx_y[12]
  PIN mx_y[13]
    DIRECTION INPUT ;
    USE SIGNAL ;
    PORT
      LAYER M5 ;
        RECT  99.984 0 100.008 0.084 ;
    END
  END mx_y[13]
  PIN mx_y[14]
    DIRECTION INPUT ;
    USE SIGNAL ;
    PORT
      LAYER M5 ;
        RECT  100.176 0 100.2 0.084 ;
    END
  END mx_y[14]
  PIN mx_y[15]
    DIRECTION INPUT ;
    USE SIGNAL ;
    PORT
      LAYER M5 ;
        RECT  100.368 0 100.392 0.084 ;
    END
  END mx_y[15]
  PIN mx_y[16]
    DIRECTION INPUT ;
    USE SIGNAL ;
    PORT
      LAYER M5 ;
        RECT  100.56 0 100.584 0.084 ;
    END
  END mx_y[16]
  PIN mx_y[17]
    DIRECTION INPUT ;
    USE SIGNAL ;
    PORT
      LAYER M5 ;
        RECT  100.752 0 100.776 0.084 ;
    END
  END mx_y[17]
  PIN mx_y[18]
    DIRECTION INPUT ;
    USE SIGNAL ;
    PORT
      LAYER M5 ;
        RECT  100.944 0 100.968 0.084 ;
    END
  END mx_y[18]
  PIN mx_y[19]
    DIRECTION INPUT ;
    USE SIGNAL ;
    PORT
      LAYER M5 ;
        RECT  101.136 0 101.16 0.084 ;
    END
  END mx_y[19]
  PIN mx_y[1]
    DIRECTION INPUT ;
    USE SIGNAL ;
    PORT
      LAYER M5 ;
        RECT  97.68 0 97.704 0.084 ;
    END
  END mx_y[1]
  PIN mx_y[20]
    DIRECTION INPUT ;
    USE SIGNAL ;
    PORT
      LAYER M5 ;
        RECT  101.328 0 101.352 0.084 ;
    END
  END mx_y[20]
  PIN mx_y[21]
    DIRECTION INPUT ;
    USE SIGNAL ;
    PORT
      LAYER M5 ;
        RECT  101.52 0 101.544 0.084 ;
    END
  END mx_y[21]
  PIN mx_y[22]
    DIRECTION INPUT ;
    USE SIGNAL ;
    PORT
      LAYER M5 ;
        RECT  101.712 0 101.736 0.084 ;
    END
  END mx_y[22]
  PIN mx_y[23]
    DIRECTION INPUT ;
    USE SIGNAL ;
    PORT
      LAYER M5 ;
        RECT  101.904 0 101.928 0.084 ;
    END
  END mx_y[23]
  PIN mx_y[24]
    DIRECTION INPUT ;
    USE SIGNAL ;
    PORT
      LAYER M5 ;
        RECT  102.096 0 102.12 0.084 ;
    END
  END mx_y[24]
  PIN mx_y[25]
    DIRECTION INPUT ;
    USE SIGNAL ;
    PORT
      LAYER M5 ;
        RECT  102.288 0 102.312 0.084 ;
    END
  END mx_y[25]
  PIN mx_y[26]
    DIRECTION INPUT ;
    USE SIGNAL ;
    PORT
      LAYER M5 ;
        RECT  102.48 0 102.504 0.084 ;
    END
  END mx_y[26]
  PIN mx_y[27]
    DIRECTION INPUT ;
    USE SIGNAL ;
    PORT
      LAYER M5 ;
        RECT  102.672 0 102.696 0.084 ;
    END
  END mx_y[27]
  PIN mx_y[28]
    DIRECTION INPUT ;
    USE SIGNAL ;
    PORT
      LAYER M5 ;
        RECT  102.864 0 102.888 0.084 ;
    END
  END mx_y[28]
  PIN mx_y[29]
    DIRECTION INPUT ;
    USE SIGNAL ;
    PORT
      LAYER M5 ;
        RECT  103.056 0 103.08 0.084 ;
    END
  END mx_y[29]
  PIN mx_y[2]
    DIRECTION INPUT ;
    USE SIGNAL ;
    PORT
      LAYER M5 ;
        RECT  97.872 0 97.896 0.084 ;
    END
  END mx_y[2]
  PIN mx_y[30]
    DIRECTION INPUT ;
    USE SIGNAL ;
    PORT
      LAYER M5 ;
        RECT  103.248 0 103.272 0.084 ;
    END
  END mx_y[30]
  PIN mx_y[31]
    DIRECTION INPUT ;
    USE SIGNAL ;
    PORT
      LAYER M5 ;
        RECT  103.44 0 103.464 0.084 ;
    END
  END mx_y[31]
  PIN mx_y[3]
    DIRECTION INPUT ;
    USE SIGNAL ;
    PORT
      LAYER M5 ;
        RECT  98.064 0 98.088 0.084 ;
    END
  END mx_y[3]
  PIN mx_y[4]
    DIRECTION INPUT ;
    USE SIGNAL ;
    PORT
      LAYER M5 ;
        RECT  98.256 0 98.28 0.084 ;
    END
  END mx_y[4]
  PIN mx_y[5]
    DIRECTION INPUT ;
    USE SIGNAL ;
    PORT
      LAYER M5 ;
        RECT  98.448 0 98.472 0.084 ;
    END
  END mx_y[5]
  PIN mx_y[6]
    DIRECTION INPUT ;
    USE SIGNAL ;
    PORT
      LAYER M5 ;
        RECT  98.64 0 98.664 0.084 ;
    END
  END mx_y[6]
  PIN mx_y[7]
    DIRECTION INPUT ;
    USE SIGNAL ;
    PORT
      LAYER M5 ;
        RECT  98.832 0 98.856 0.084 ;
    END
  END mx_y[7]
  PIN mx_y[8]
    DIRECTION INPUT ;
    USE SIGNAL ;
    PORT
      LAYER M5 ;
        RECT  99.024 0 99.048 0.084 ;
    END
  END mx_y[8]
  PIN mx_y[9]
    DIRECTION INPUT ;
    USE SIGNAL ;
    PORT
      LAYER M5 ;
        RECT  99.216 0 99.24 0.084 ;
    END
  END mx_y[9]
  PIN rs_i[0]
    DIRECTION INPUT ;
    USE SIGNAL ;
    PORT
      LAYER M5 ;
        RECT  103.632 0 103.656 0.084 ;
    END
  END rs_i[0]
  PIN rs_i[100]
    DIRECTION INPUT ;
    USE SIGNAL ;
    PORT
      LAYER M5 ;
        RECT  110.544 0 110.568 0.084 ;
    END
  END rs_i[100]
  PIN rs_i[101]
    DIRECTION INPUT ;
    USE SIGNAL ;
    PORT
      LAYER M5 ;
        RECT  110.736 0 110.76 0.084 ;
    END
  END rs_i[101]
  PIN rs_i[102]
    DIRECTION INPUT ;
    USE SIGNAL ;
    PORT
      LAYER M5 ;
        RECT  110.928 0 110.952 0.084 ;
    END
  END rs_i[102]
  PIN rs_i[103]
    DIRECTION INPUT ;
    USE SIGNAL ;
    PORT
      LAYER M5 ;
        RECT  111.12 0 111.144 0.084 ;
    END
  END rs_i[103]
  PIN rs_i[104]
    DIRECTION INPUT ;
    USE SIGNAL ;
    PORT
      LAYER M5 ;
        RECT  111.312 0 111.336 0.084 ;
    END
  END rs_i[104]
  PIN rs_i[105]
    DIRECTION INPUT ;
    USE SIGNAL ;
    PORT
      LAYER M5 ;
        RECT  111.504 0 111.528 0.084 ;
    END
  END rs_i[105]
  PIN rs_i[106]
    DIRECTION INPUT ;
    USE SIGNAL ;
    PORT
      LAYER M5 ;
        RECT  111.696 0 111.72 0.084 ;
    END
  END rs_i[106]
  PIN rs_i[107]
    DIRECTION INPUT ;
    USE SIGNAL ;
    PORT
      LAYER M5 ;
        RECT  111.888 0 111.912 0.084 ;
    END
  END rs_i[107]
  PIN rs_i[108]
    DIRECTION INPUT ;
    USE SIGNAL ;
    PORT
      LAYER M5 ;
        RECT  112.08 0 112.104 0.084 ;
    END
  END rs_i[108]
  PIN rs_i[109]
    DIRECTION INPUT ;
    USE SIGNAL ;
    PORT
      LAYER M5 ;
        RECT  112.272 0 112.296 0.084 ;
    END
  END rs_i[109]
  PIN rs_i[10]
    DIRECTION INPUT ;
    USE SIGNAL ;
    PORT
      LAYER M5 ;
        RECT  105.552 0 105.576 0.084 ;
    END
  END rs_i[10]
  PIN rs_i[110]
    DIRECTION INPUT ;
    USE SIGNAL ;
    PORT
      LAYER M5 ;
        RECT  112.464 0 112.488 0.084 ;
    END
  END rs_i[110]
  PIN rs_i[111]
    DIRECTION INPUT ;
    USE SIGNAL ;
    PORT
      LAYER M5 ;
        RECT  112.656 0 112.68 0.084 ;
    END
  END rs_i[111]
  PIN rs_i[112]
    DIRECTION INPUT ;
    USE SIGNAL ;
    PORT
      LAYER M5 ;
        RECT  112.848 0 112.872 0.084 ;
    END
  END rs_i[112]
  PIN rs_i[113]
    DIRECTION INPUT ;
    USE SIGNAL ;
    PORT
      LAYER M5 ;
        RECT  113.04 0 113.064 0.084 ;
    END
  END rs_i[113]
  PIN rs_i[114]
    DIRECTION INPUT ;
    USE SIGNAL ;
    PORT
      LAYER M5 ;
        RECT  113.232 0 113.256 0.084 ;
    END
  END rs_i[114]
  PIN rs_i[115]
    DIRECTION INPUT ;
    USE SIGNAL ;
    PORT
      LAYER M5 ;
        RECT  113.424 0 113.448 0.084 ;
    END
  END rs_i[115]
  PIN rs_i[116]
    DIRECTION INPUT ;
    USE SIGNAL ;
    PORT
      LAYER M5 ;
        RECT  113.616 0 113.64 0.084 ;
    END
  END rs_i[116]
  PIN rs_i[117]
    DIRECTION INPUT ;
    USE SIGNAL ;
    PORT
      LAYER M5 ;
        RECT  113.808 0 113.832 0.084 ;
    END
  END rs_i[117]
  PIN rs_i[118]
    DIRECTION INPUT ;
    USE SIGNAL ;
    PORT
      LAYER M5 ;
        RECT  114 0 114.024 0.084 ;
    END
  END rs_i[118]
  PIN rs_i[119]
    DIRECTION INPUT ;
    USE SIGNAL ;
    PORT
      LAYER M5 ;
        RECT  114.192 0 114.216 0.084 ;
    END
  END rs_i[119]
  PIN rs_i[11]
    DIRECTION INPUT ;
    USE SIGNAL ;
    PORT
      LAYER M5 ;
        RECT  105.744 0 105.768 0.084 ;
    END
  END rs_i[11]
  PIN rs_i[120]
    DIRECTION INPUT ;
    USE SIGNAL ;
    PORT
      LAYER M5 ;
        RECT  140.496 0 140.52 0.084 ;
    END
  END rs_i[120]
  PIN rs_i[121]
    DIRECTION INPUT ;
    USE SIGNAL ;
    PORT
      LAYER M5 ;
        RECT  140.688 0 140.712 0.084 ;
    END
  END rs_i[121]
  PIN rs_i[122]
    DIRECTION INPUT ;
    USE SIGNAL ;
    PORT
      LAYER M5 ;
        RECT  140.88 0 140.904 0.084 ;
    END
  END rs_i[122]
  PIN rs_i[123]
    DIRECTION INPUT ;
    USE SIGNAL ;
    PORT
      LAYER M5 ;
        RECT  141.072 0 141.096 0.084 ;
    END
  END rs_i[123]
  PIN rs_i[124]
    DIRECTION INPUT ;
    USE SIGNAL ;
    PORT
      LAYER M5 ;
        RECT  141.264 0 141.288 0.084 ;
    END
  END rs_i[124]
  PIN rs_i[125]
    DIRECTION INPUT ;
    USE SIGNAL ;
    PORT
      LAYER M5 ;
        RECT  141.456 0 141.48 0.084 ;
    END
  END rs_i[125]
  PIN rs_i[126]
    DIRECTION INPUT ;
    USE SIGNAL ;
    PORT
      LAYER M5 ;
        RECT  141.648 0 141.672 0.084 ;
    END
  END rs_i[126]
  PIN rs_i[127]
    DIRECTION INPUT ;
    USE SIGNAL ;
    PORT
      LAYER M5 ;
        RECT  141.84 0 141.864 0.084 ;
    END
  END rs_i[127]
  PIN rs_i[128]
    DIRECTION INPUT ;
    USE SIGNAL ;
    PORT
      LAYER M5 ;
        RECT  142.032 0 142.056 0.084 ;
    END
  END rs_i[128]
  PIN rs_i[129]
    DIRECTION INPUT ;
    USE SIGNAL ;
    PORT
      LAYER M5 ;
        RECT  142.224 0 142.248 0.084 ;
    END
  END rs_i[129]
  PIN rs_i[12]
    DIRECTION INPUT ;
    USE SIGNAL ;
    PORT
      LAYER M5 ;
        RECT  105.936 0 105.96 0.084 ;
    END
  END rs_i[12]
  PIN rs_i[130]
    DIRECTION INPUT ;
    USE SIGNAL ;
    PORT
      LAYER M5 ;
        RECT  142.416 0 142.44 0.084 ;
    END
  END rs_i[130]
  PIN rs_i[131]
    DIRECTION INPUT ;
    USE SIGNAL ;
    PORT
      LAYER M5 ;
        RECT  142.608 0 142.632 0.084 ;
    END
  END rs_i[131]
  PIN rs_i[132]
    DIRECTION INPUT ;
    USE SIGNAL ;
    PORT
      LAYER M5 ;
        RECT  142.8 0 142.824 0.084 ;
    END
  END rs_i[132]
  PIN rs_i[133]
    DIRECTION INPUT ;
    USE SIGNAL ;
    PORT
      LAYER M5 ;
        RECT  142.992 0 143.016 0.084 ;
    END
  END rs_i[133]
  PIN rs_i[134]
    DIRECTION INPUT ;
    USE SIGNAL ;
    PORT
      LAYER M5 ;
        RECT  143.184 0 143.208 0.084 ;
    END
  END rs_i[134]
  PIN rs_i[135]
    DIRECTION INPUT ;
    USE SIGNAL ;
    PORT
      LAYER M5 ;
        RECT  143.376 0 143.4 0.084 ;
    END
  END rs_i[135]
  PIN rs_i[136]
    DIRECTION INPUT ;
    USE SIGNAL ;
    PORT
      LAYER M5 ;
        RECT  143.568 0 143.592 0.084 ;
    END
  END rs_i[136]
  PIN rs_i[137]
    DIRECTION INPUT ;
    USE SIGNAL ;
    PORT
      LAYER M5 ;
        RECT  143.76 0 143.784 0.084 ;
    END
  END rs_i[137]
  PIN rs_i[138]
    DIRECTION INPUT ;
    USE SIGNAL ;
    PORT
      LAYER M5 ;
        RECT  143.952 0 143.976 0.084 ;
    END
  END rs_i[138]
  PIN rs_i[139]
    DIRECTION INPUT ;
    USE SIGNAL ;
    PORT
      LAYER M5 ;
        RECT  144.144 0 144.168 0.084 ;
    END
  END rs_i[139]
  PIN rs_i[13]
    DIRECTION INPUT ;
    USE SIGNAL ;
    PORT
      LAYER M5 ;
        RECT  106.128 0 106.152 0.084 ;
    END
  END rs_i[13]
  PIN rs_i[140]
    DIRECTION INPUT ;
    USE SIGNAL ;
    PORT
      LAYER M5 ;
        RECT  144.336 0 144.36 0.084 ;
    END
  END rs_i[140]
  PIN rs_i[141]
    DIRECTION INPUT ;
    USE SIGNAL ;
    PORT
      LAYER M5 ;
        RECT  144.528 0 144.552 0.084 ;
    END
  END rs_i[141]
  PIN rs_i[142]
    DIRECTION INPUT ;
    USE SIGNAL ;
    PORT
      LAYER M5 ;
        RECT  144.72 0 144.744 0.084 ;
    END
  END rs_i[142]
  PIN rs_i[143]
    DIRECTION INPUT ;
    USE SIGNAL ;
    PORT
      LAYER M5 ;
        RECT  144.912 0 144.936 0.084 ;
    END
  END rs_i[143]
  PIN rs_i[144]
    DIRECTION INPUT ;
    USE SIGNAL ;
    PORT
      LAYER M5 ;
        RECT  145.104 0 145.128 0.084 ;
    END
  END rs_i[144]
  PIN rs_i[145]
    DIRECTION INPUT ;
    USE SIGNAL ;
    PORT
      LAYER M5 ;
        RECT  145.296 0 145.32 0.084 ;
    END
  END rs_i[145]
  PIN rs_i[146]
    DIRECTION INPUT ;
    USE SIGNAL ;
    PORT
      LAYER M5 ;
        RECT  145.488 0 145.512 0.084 ;
    END
  END rs_i[146]
  PIN rs_i[147]
    DIRECTION INPUT ;
    USE SIGNAL ;
    PORT
      LAYER M5 ;
        RECT  145.68 0 145.704 0.084 ;
    END
  END rs_i[147]
  PIN rs_i[148]
    DIRECTION INPUT ;
    USE SIGNAL ;
    PORT
      LAYER M5 ;
        RECT  145.872 0 145.896 0.084 ;
    END
  END rs_i[148]
  PIN rs_i[149]
    DIRECTION INPUT ;
    USE SIGNAL ;
    PORT
      LAYER M5 ;
        RECT  146.064 0 146.088 0.084 ;
    END
  END rs_i[149]
  PIN rs_i[14]
    DIRECTION INPUT ;
    USE SIGNAL ;
    PORT
      LAYER M5 ;
        RECT  106.32 0 106.344 0.084 ;
    END
  END rs_i[14]
  PIN rs_i[150]
    DIRECTION INPUT ;
    USE SIGNAL ;
    PORT
      LAYER M5 ;
        RECT  146.256 0 146.28 0.084 ;
    END
  END rs_i[150]
  PIN rs_i[151]
    DIRECTION INPUT ;
    USE SIGNAL ;
    PORT
      LAYER M5 ;
        RECT  146.448 0 146.472 0.084 ;
    END
  END rs_i[151]
  PIN rs_i[152]
    DIRECTION INPUT ;
    USE SIGNAL ;
    PORT
      LAYER M5 ;
        RECT  146.64 0 146.664 0.084 ;
    END
  END rs_i[152]
  PIN rs_i[153]
    DIRECTION INPUT ;
    USE SIGNAL ;
    PORT
      LAYER M5 ;
        RECT  146.832 0 146.856 0.084 ;
    END
  END rs_i[153]
  PIN rs_i[154]
    DIRECTION INPUT ;
    USE SIGNAL ;
    PORT
      LAYER M5 ;
        RECT  147.024 0 147.048 0.084 ;
    END
  END rs_i[154]
  PIN rs_i[155]
    DIRECTION INPUT ;
    USE SIGNAL ;
    PORT
      LAYER M5 ;
        RECT  147.216 0 147.24 0.084 ;
    END
  END rs_i[155]
  PIN rs_i[156]
    DIRECTION INPUT ;
    USE SIGNAL ;
    PORT
      LAYER M5 ;
        RECT  147.408 0 147.432 0.084 ;
    END
  END rs_i[156]
  PIN rs_i[157]
    DIRECTION INPUT ;
    USE SIGNAL ;
    PORT
      LAYER M5 ;
        RECT  147.6 0 147.624 0.084 ;
    END
  END rs_i[157]
  PIN rs_i[158]
    DIRECTION INPUT ;
    USE SIGNAL ;
    PORT
      LAYER M5 ;
        RECT  147.792 0 147.816 0.084 ;
    END
  END rs_i[158]
  PIN rs_i[159]
    DIRECTION INPUT ;
    USE SIGNAL ;
    PORT
      LAYER M5 ;
        RECT  147.984 0 148.008 0.084 ;
    END
  END rs_i[159]
  PIN rs_i[15]
    DIRECTION INPUT ;
    USE SIGNAL ;
    PORT
      LAYER M5 ;
        RECT  106.512 0 106.536 0.084 ;
    END
  END rs_i[15]
  PIN rs_i[160]
    DIRECTION INPUT ;
    USE SIGNAL ;
    PORT
      LAYER M5 ;
        RECT  148.176 0 148.2 0.084 ;
    END
  END rs_i[160]
  PIN rs_i[161]
    DIRECTION INPUT ;
    USE SIGNAL ;
    PORT
      LAYER M5 ;
        RECT  148.368 0 148.392 0.084 ;
    END
  END rs_i[161]
  PIN rs_i[162]
    DIRECTION INPUT ;
    USE SIGNAL ;
    PORT
      LAYER M5 ;
        RECT  148.56 0 148.584 0.084 ;
    END
  END rs_i[162]
  PIN rs_i[163]
    DIRECTION INPUT ;
    USE SIGNAL ;
    PORT
      LAYER M5 ;
        RECT  148.752 0 148.776 0.084 ;
    END
  END rs_i[163]
  PIN rs_i[164]
    DIRECTION INPUT ;
    USE SIGNAL ;
    PORT
      LAYER M5 ;
        RECT  148.944 0 148.968 0.084 ;
    END
  END rs_i[164]
  PIN rs_i[165]
    DIRECTION INPUT ;
    USE SIGNAL ;
    PORT
      LAYER M5 ;
        RECT  149.136 0 149.16 0.084 ;
    END
  END rs_i[165]
  PIN rs_i[166]
    DIRECTION INPUT ;
    USE SIGNAL ;
    PORT
      LAYER M5 ;
        RECT  149.328 0 149.352 0.084 ;
    END
  END rs_i[166]
  PIN rs_i[167]
    DIRECTION INPUT ;
    USE SIGNAL ;
    PORT
      LAYER M5 ;
        RECT  149.52 0 149.544 0.084 ;
    END
  END rs_i[167]
  PIN rs_i[168]
    DIRECTION INPUT ;
    USE SIGNAL ;
    PORT
      LAYER M5 ;
        RECT  149.712 0 149.736 0.084 ;
    END
  END rs_i[168]
  PIN rs_i[169]
    DIRECTION INPUT ;
    USE SIGNAL ;
    PORT
      LAYER M5 ;
        RECT  149.904 0 149.928 0.084 ;
    END
  END rs_i[169]
  PIN rs_i[16]
    DIRECTION INPUT ;
    USE SIGNAL ;
    PORT
      LAYER M5 ;
        RECT  106.704 0 106.728 0.084 ;
    END
  END rs_i[16]
  PIN rs_i[170]
    DIRECTION INPUT ;
    USE SIGNAL ;
    PORT
      LAYER M5 ;
        RECT  150.096 0 150.12 0.084 ;
    END
  END rs_i[170]
  PIN rs_i[171]
    DIRECTION INPUT ;
    USE SIGNAL ;
    PORT
      LAYER M5 ;
        RECT  150.288 0 150.312 0.084 ;
    END
  END rs_i[171]
  PIN rs_i[172]
    DIRECTION INPUT ;
    USE SIGNAL ;
    PORT
      LAYER M5 ;
        RECT  150.48 0 150.504 0.084 ;
    END
  END rs_i[172]
  PIN rs_i[173]
    DIRECTION INPUT ;
    USE SIGNAL ;
    PORT
      LAYER M5 ;
        RECT  150.672 0 150.696 0.084 ;
    END
  END rs_i[173]
  PIN rs_i[174]
    DIRECTION INPUT ;
    USE SIGNAL ;
    PORT
      LAYER M5 ;
        RECT  150.864 0 150.888 0.084 ;
    END
  END rs_i[174]
  PIN rs_i[175]
    DIRECTION INPUT ;
    USE SIGNAL ;
    PORT
      LAYER M5 ;
        RECT  151.056 0 151.08 0.084 ;
    END
  END rs_i[175]
  PIN rs_i[176]
    DIRECTION INPUT ;
    USE SIGNAL ;
    PORT
      LAYER M5 ;
        RECT  151.248 0 151.272 0.084 ;
    END
  END rs_i[176]
  PIN rs_i[177]
    DIRECTION INPUT ;
    USE SIGNAL ;
    PORT
      LAYER M5 ;
        RECT  151.44 0 151.464 0.084 ;
    END
  END rs_i[177]
  PIN rs_i[178]
    DIRECTION INPUT ;
    USE SIGNAL ;
    PORT
      LAYER M5 ;
        RECT  151.632 0 151.656 0.084 ;
    END
  END rs_i[178]
  PIN rs_i[179]
    DIRECTION INPUT ;
    USE SIGNAL ;
    PORT
      LAYER M5 ;
        RECT  151.824 0 151.848 0.084 ;
    END
  END rs_i[179]
  PIN rs_i[17]
    DIRECTION INPUT ;
    USE SIGNAL ;
    PORT
      LAYER M5 ;
        RECT  106.896 0 106.92 0.084 ;
    END
  END rs_i[17]
  PIN rs_i[180]
    DIRECTION INPUT ;
    USE SIGNAL ;
    PORT
      LAYER M5 ;
        RECT  152.016 0 152.04 0.084 ;
    END
  END rs_i[180]
  PIN rs_i[181]
    DIRECTION INPUT ;
    USE SIGNAL ;
    PORT
      LAYER M5 ;
        RECT  152.208 0 152.232 0.084 ;
    END
  END rs_i[181]
  PIN rs_i[182]
    DIRECTION INPUT ;
    USE SIGNAL ;
    PORT
      LAYER M5 ;
        RECT  152.4 0 152.424 0.084 ;
    END
  END rs_i[182]
  PIN rs_i[183]
    DIRECTION INPUT ;
    USE SIGNAL ;
    PORT
      LAYER M5 ;
        RECT  152.592 0 152.616 0.084 ;
    END
  END rs_i[183]
  PIN rs_i[184]
    DIRECTION INPUT ;
    USE SIGNAL ;
    PORT
      LAYER M5 ;
        RECT  128.208 0 128.232 0.084 ;
    END
  END rs_i[184]
  PIN rs_i[185]
    DIRECTION INPUT ;
    USE SIGNAL ;
    PORT
      LAYER M5 ;
        RECT  128.4 0 128.424 0.084 ;
    END
  END rs_i[185]
  PIN rs_i[186]
    DIRECTION INPUT ;
    USE SIGNAL ;
    PORT
      LAYER M5 ;
        RECT  128.592 0 128.616 0.084 ;
    END
  END rs_i[186]
  PIN rs_i[187]
    DIRECTION INPUT ;
    USE SIGNAL ;
    PORT
      LAYER M5 ;
        RECT  128.784 0 128.808 0.084 ;
    END
  END rs_i[187]
  PIN rs_i[188]
    DIRECTION INPUT ;
    USE SIGNAL ;
    PORT
      LAYER M5 ;
        RECT  128.976 0 129 0.084 ;
    END
  END rs_i[188]
  PIN rs_i[189]
    DIRECTION INPUT ;
    USE SIGNAL ;
    PORT
      LAYER M5 ;
        RECT  129.168 0 129.192 0.084 ;
    END
  END rs_i[189]
  PIN rs_i[18]
    DIRECTION INPUT ;
    USE SIGNAL ;
    PORT
      LAYER M5 ;
        RECT  107.088 0 107.112 0.084 ;
    END
  END rs_i[18]
  PIN rs_i[190]
    DIRECTION INPUT ;
    USE SIGNAL ;
    PORT
      LAYER M5 ;
        RECT  129.36 0 129.384 0.084 ;
    END
  END rs_i[190]
  PIN rs_i[191]
    DIRECTION INPUT ;
    USE SIGNAL ;
    PORT
      LAYER M5 ;
        RECT  129.552 0 129.576 0.084 ;
    END
  END rs_i[191]
  PIN rs_i[192]
    DIRECTION INPUT ;
    USE SIGNAL ;
    PORT
      LAYER M5 ;
        RECT  129.744 0 129.768 0.084 ;
    END
  END rs_i[192]
  PIN rs_i[193]
    DIRECTION INPUT ;
    USE SIGNAL ;
    PORT
      LAYER M5 ;
        RECT  129.936 0 129.96 0.084 ;
    END
  END rs_i[193]
  PIN rs_i[194]
    DIRECTION INPUT ;
    USE SIGNAL ;
    PORT
      LAYER M5 ;
        RECT  130.128 0 130.152 0.084 ;
    END
  END rs_i[194]
  PIN rs_i[195]
    DIRECTION INPUT ;
    USE SIGNAL ;
    PORT
      LAYER M5 ;
        RECT  130.32 0 130.344 0.084 ;
    END
  END rs_i[195]
  PIN rs_i[196]
    DIRECTION INPUT ;
    USE SIGNAL ;
    PORT
      LAYER M5 ;
        RECT  130.512 0 130.536 0.084 ;
    END
  END rs_i[196]
  PIN rs_i[197]
    DIRECTION INPUT ;
    USE SIGNAL ;
    PORT
      LAYER M5 ;
        RECT  130.704 0 130.728 0.084 ;
    END
  END rs_i[197]
  PIN rs_i[198]
    DIRECTION INPUT ;
    USE SIGNAL ;
    PORT
      LAYER M5 ;
        RECT  130.896 0 130.92 0.084 ;
    END
  END rs_i[198]
  PIN rs_i[199]
    DIRECTION INPUT ;
    USE SIGNAL ;
    PORT
      LAYER M5 ;
        RECT  131.088 0 131.112 0.084 ;
    END
  END rs_i[199]
  PIN rs_i[19]
    DIRECTION INPUT ;
    USE SIGNAL ;
    PORT
      LAYER M5 ;
        RECT  107.28 0 107.304 0.084 ;
    END
  END rs_i[19]
  PIN rs_i[1]
    DIRECTION INPUT ;
    USE SIGNAL ;
    PORT
      LAYER M5 ;
        RECT  103.824 0 103.848 0.084 ;
    END
  END rs_i[1]
  PIN rs_i[200]
    DIRECTION INPUT ;
    USE SIGNAL ;
    PORT
      LAYER M5 ;
        RECT  131.28 0 131.304 0.084 ;
    END
  END rs_i[200]
  PIN rs_i[201]
    DIRECTION INPUT ;
    USE SIGNAL ;
    PORT
      LAYER M5 ;
        RECT  131.472 0 131.496 0.084 ;
    END
  END rs_i[201]
  PIN rs_i[202]
    DIRECTION INPUT ;
    USE SIGNAL ;
    PORT
      LAYER M5 ;
        RECT  131.664 0 131.688 0.084 ;
    END
  END rs_i[202]
  PIN rs_i[203]
    DIRECTION INPUT ;
    USE SIGNAL ;
    PORT
      LAYER M5 ;
        RECT  131.856 0 131.88 0.084 ;
    END
  END rs_i[203]
  PIN rs_i[204]
    DIRECTION INPUT ;
    USE SIGNAL ;
    PORT
      LAYER M5 ;
        RECT  132.048 0 132.072 0.084 ;
    END
  END rs_i[204]
  PIN rs_i[205]
    DIRECTION INPUT ;
    USE SIGNAL ;
    PORT
      LAYER M5 ;
        RECT  132.24 0 132.264 0.084 ;
    END
  END rs_i[205]
  PIN rs_i[206]
    DIRECTION INPUT ;
    USE SIGNAL ;
    PORT
      LAYER M5 ;
        RECT  132.432 0 132.456 0.084 ;
    END
  END rs_i[206]
  PIN rs_i[207]
    DIRECTION INPUT ;
    USE SIGNAL ;
    PORT
      LAYER M5 ;
        RECT  132.624 0 132.648 0.084 ;
    END
  END rs_i[207]
  PIN rs_i[208]
    DIRECTION INPUT ;
    USE SIGNAL ;
    PORT
      LAYER M5 ;
        RECT  132.816 0 132.84 0.084 ;
    END
  END rs_i[208]
  PIN rs_i[209]
    DIRECTION INPUT ;
    USE SIGNAL ;
    PORT
      LAYER M5 ;
        RECT  133.008 0 133.032 0.084 ;
    END
  END rs_i[209]
  PIN rs_i[20]
    DIRECTION INPUT ;
    USE SIGNAL ;
    PORT
      LAYER M5 ;
        RECT  107.472 0 107.496 0.084 ;
    END
  END rs_i[20]
  PIN rs_i[210]
    DIRECTION INPUT ;
    USE SIGNAL ;
    PORT
      LAYER M5 ;
        RECT  133.2 0 133.224 0.084 ;
    END
  END rs_i[210]
  PIN rs_i[211]
    DIRECTION INPUT ;
    USE SIGNAL ;
    PORT
      LAYER M5 ;
        RECT  133.392 0 133.416 0.084 ;
    END
  END rs_i[211]
  PIN rs_i[212]
    DIRECTION INPUT ;
    USE SIGNAL ;
    PORT
      LAYER M5 ;
        RECT  133.584 0 133.608 0.084 ;
    END
  END rs_i[212]
  PIN rs_i[213]
    DIRECTION INPUT ;
    USE SIGNAL ;
    PORT
      LAYER M5 ;
        RECT  133.776 0 133.8 0.084 ;
    END
  END rs_i[213]
  PIN rs_i[214]
    DIRECTION INPUT ;
    USE SIGNAL ;
    PORT
      LAYER M5 ;
        RECT  133.968 0 133.992 0.084 ;
    END
  END rs_i[214]
  PIN rs_i[215]
    DIRECTION INPUT ;
    USE SIGNAL ;
    PORT
      LAYER M5 ;
        RECT  134.16 0 134.184 0.084 ;
    END
  END rs_i[215]
  PIN rs_i[216]
    DIRECTION INPUT ;
    USE SIGNAL ;
    PORT
      LAYER M5 ;
        RECT  115.92 0 115.944 0.084 ;
    END
  END rs_i[216]
  PIN rs_i[217]
    DIRECTION INPUT ;
    USE SIGNAL ;
    PORT
      LAYER M5 ;
        RECT  116.112 0 116.136 0.084 ;
    END
  END rs_i[217]
  PIN rs_i[218]
    DIRECTION INPUT ;
    USE SIGNAL ;
    PORT
      LAYER M5 ;
        RECT  116.304 0 116.328 0.084 ;
    END
  END rs_i[218]
  PIN rs_i[219]
    DIRECTION INPUT ;
    USE SIGNAL ;
    PORT
      LAYER M5 ;
        RECT  116.496 0 116.52 0.084 ;
    END
  END rs_i[219]
  PIN rs_i[21]
    DIRECTION INPUT ;
    USE SIGNAL ;
    PORT
      LAYER M5 ;
        RECT  107.664 0 107.688 0.084 ;
    END
  END rs_i[21]
  PIN rs_i[220]
    DIRECTION INPUT ;
    USE SIGNAL ;
    PORT
      LAYER M5 ;
        RECT  116.688 0 116.712 0.084 ;
    END
  END rs_i[220]
  PIN rs_i[221]
    DIRECTION INPUT ;
    USE SIGNAL ;
    PORT
      LAYER M5 ;
        RECT  116.88 0 116.904 0.084 ;
    END
  END rs_i[221]
  PIN rs_i[222]
    DIRECTION INPUT ;
    USE SIGNAL ;
    PORT
      LAYER M5 ;
        RECT  117.072 0 117.096 0.084 ;
    END
  END rs_i[222]
  PIN rs_i[223]
    DIRECTION INPUT ;
    USE SIGNAL ;
    PORT
      LAYER M5 ;
        RECT  117.264 0 117.288 0.084 ;
    END
  END rs_i[223]
  PIN rs_i[224]
    DIRECTION INPUT ;
    USE SIGNAL ;
    PORT
      LAYER M5 ;
        RECT  117.456 0 117.48 0.084 ;
    END
  END rs_i[224]
  PIN rs_i[225]
    DIRECTION INPUT ;
    USE SIGNAL ;
    PORT
      LAYER M5 ;
        RECT  117.648 0 117.672 0.084 ;
    END
  END rs_i[225]
  PIN rs_i[226]
    DIRECTION INPUT ;
    USE SIGNAL ;
    PORT
      LAYER M5 ;
        RECT  117.84 0 117.864 0.084 ;
    END
  END rs_i[226]
  PIN rs_i[227]
    DIRECTION INPUT ;
    USE SIGNAL ;
    PORT
      LAYER M5 ;
        RECT  118.032 0 118.056 0.084 ;
    END
  END rs_i[227]
  PIN rs_i[228]
    DIRECTION INPUT ;
    USE SIGNAL ;
    PORT
      LAYER M5 ;
        RECT  118.224 0 118.248 0.084 ;
    END
  END rs_i[228]
  PIN rs_i[229]
    DIRECTION INPUT ;
    USE SIGNAL ;
    PORT
      LAYER M5 ;
        RECT  118.416 0 118.44 0.084 ;
    END
  END rs_i[229]
  PIN rs_i[22]
    DIRECTION INPUT ;
    USE SIGNAL ;
    PORT
      LAYER M5 ;
        RECT  107.856 0 107.88 0.084 ;
    END
  END rs_i[22]
  PIN rs_i[230]
    DIRECTION INPUT ;
    USE SIGNAL ;
    PORT
      LAYER M5 ;
        RECT  118.608 0 118.632 0.084 ;
    END
  END rs_i[230]
  PIN rs_i[231]
    DIRECTION INPUT ;
    USE SIGNAL ;
    PORT
      LAYER M5 ;
        RECT  118.8 0 118.824 0.084 ;
    END
  END rs_i[231]
  PIN rs_i[232]
    DIRECTION INPUT ;
    USE SIGNAL ;
    PORT
      LAYER M5 ;
        RECT  118.992 0 119.016 0.084 ;
    END
  END rs_i[232]
  PIN rs_i[233]
    DIRECTION INPUT ;
    USE SIGNAL ;
    PORT
      LAYER M5 ;
        RECT  119.184 0 119.208 0.084 ;
    END
  END rs_i[233]
  PIN rs_i[234]
    DIRECTION INPUT ;
    USE SIGNAL ;
    PORT
      LAYER M5 ;
        RECT  119.376 0 119.4 0.084 ;
    END
  END rs_i[234]
  PIN rs_i[235]
    DIRECTION INPUT ;
    USE SIGNAL ;
    PORT
      LAYER M5 ;
        RECT  119.568 0 119.592 0.084 ;
    END
  END rs_i[235]
  PIN rs_i[236]
    DIRECTION INPUT ;
    USE SIGNAL ;
    PORT
      LAYER M5 ;
        RECT  119.76 0 119.784 0.084 ;
    END
  END rs_i[236]
  PIN rs_i[237]
    DIRECTION INPUT ;
    USE SIGNAL ;
    PORT
      LAYER M5 ;
        RECT  119.952 0 119.976 0.084 ;
    END
  END rs_i[237]
  PIN rs_i[238]
    DIRECTION INPUT ;
    USE SIGNAL ;
    PORT
      LAYER M5 ;
        RECT  120.144 0 120.168 0.084 ;
    END
  END rs_i[238]
  PIN rs_i[239]
    DIRECTION INPUT ;
    USE SIGNAL ;
    PORT
      LAYER M5 ;
        RECT  120.336 0 120.36 0.084 ;
    END
  END rs_i[239]
  PIN rs_i[23]
    DIRECTION INPUT ;
    USE SIGNAL ;
    PORT
      LAYER M5 ;
        RECT  108.048 0 108.072 0.084 ;
    END
  END rs_i[23]
  PIN rs_i[240]
    DIRECTION INPUT ;
    USE SIGNAL ;
    PORT
      LAYER M5 ;
        RECT  120.528 0 120.552 0.084 ;
    END
  END rs_i[240]
  PIN rs_i[241]
    DIRECTION INPUT ;
    USE SIGNAL ;
    PORT
      LAYER M5 ;
        RECT  120.72 0 120.744 0.084 ;
    END
  END rs_i[241]
  PIN rs_i[242]
    DIRECTION INPUT ;
    USE SIGNAL ;
    PORT
      LAYER M5 ;
        RECT  120.912 0 120.936 0.084 ;
    END
  END rs_i[242]
  PIN rs_i[243]
    DIRECTION INPUT ;
    USE SIGNAL ;
    PORT
      LAYER M5 ;
        RECT  121.104 0 121.128 0.084 ;
    END
  END rs_i[243]
  PIN rs_i[244]
    DIRECTION INPUT ;
    USE SIGNAL ;
    PORT
      LAYER M5 ;
        RECT  121.296 0 121.32 0.084 ;
    END
  END rs_i[244]
  PIN rs_i[245]
    DIRECTION INPUT ;
    USE SIGNAL ;
    PORT
      LAYER M5 ;
        RECT  121.488 0 121.512 0.084 ;
    END
  END rs_i[245]
  PIN rs_i[246]
    DIRECTION INPUT ;
    USE SIGNAL ;
    PORT
      LAYER M5 ;
        RECT  121.68 0 121.704 0.084 ;
    END
  END rs_i[246]
  PIN rs_i[247]
    DIRECTION INPUT ;
    USE SIGNAL ;
    PORT
      LAYER M5 ;
        RECT  121.872 0 121.896 0.084 ;
    END
  END rs_i[247]
  PIN rs_i[248]
    DIRECTION INPUT ;
    USE SIGNAL ;
    PORT
      LAYER M5 ;
        RECT  122.064 0 122.088 0.084 ;
    END
  END rs_i[248]
  PIN rs_i[249]
    DIRECTION INPUT ;
    USE SIGNAL ;
    PORT
      LAYER M5 ;
        RECT  122.256 0 122.28 0.084 ;
    END
  END rs_i[249]
  PIN rs_i[24]
    DIRECTION INPUT ;
    USE SIGNAL ;
    PORT
      LAYER M5 ;
        RECT  89.808 0 89.832 0.084 ;
    END
  END rs_i[24]
  PIN rs_i[250]
    DIRECTION INPUT ;
    USE SIGNAL ;
    PORT
      LAYER M5 ;
        RECT  122.448 0 122.472 0.084 ;
    END
  END rs_i[250]
  PIN rs_i[251]
    DIRECTION INPUT ;
    USE SIGNAL ;
    PORT
      LAYER M5 ;
        RECT  122.64 0 122.664 0.084 ;
    END
  END rs_i[251]
  PIN rs_i[252]
    DIRECTION INPUT ;
    USE SIGNAL ;
    PORT
      LAYER M5 ;
        RECT  122.832 0 122.856 0.084 ;
    END
  END rs_i[252]
  PIN rs_i[253]
    DIRECTION INPUT ;
    USE SIGNAL ;
    PORT
      LAYER M5 ;
        RECT  123.024 0 123.048 0.084 ;
    END
  END rs_i[253]
  PIN rs_i[254]
    DIRECTION INPUT ;
    USE SIGNAL ;
    PORT
      LAYER M5 ;
        RECT  123.216 0 123.24 0.084 ;
    END
  END rs_i[254]
  PIN rs_i[255]
    DIRECTION INPUT ;
    USE SIGNAL ;
    PORT
      LAYER M5 ;
        RECT  123.408 0 123.432 0.084 ;
    END
  END rs_i[255]
  PIN rs_i[256]
    DIRECTION INPUT ;
    USE SIGNAL ;
    PORT
      LAYER M5 ;
        RECT  123.6 0 123.624 0.084 ;
    END
  END rs_i[256]
  PIN rs_i[257]
    DIRECTION INPUT ;
    USE SIGNAL ;
    PORT
      LAYER M5 ;
        RECT  123.792 0 123.816 0.084 ;
    END
  END rs_i[257]
  PIN rs_i[258]
    DIRECTION INPUT ;
    USE SIGNAL ;
    PORT
      LAYER M5 ;
        RECT  123.984 0 124.008 0.084 ;
    END
  END rs_i[258]
  PIN rs_i[259]
    DIRECTION INPUT ;
    USE SIGNAL ;
    PORT
      LAYER M5 ;
        RECT  124.176 0 124.2 0.084 ;
    END
  END rs_i[259]
  PIN rs_i[25]
    DIRECTION INPUT ;
    USE SIGNAL ;
    PORT
      LAYER M5 ;
        RECT  90 0 90.024 0.084 ;
    END
  END rs_i[25]
  PIN rs_i[260]
    DIRECTION INPUT ;
    USE SIGNAL ;
    PORT
      LAYER M5 ;
        RECT  124.368 0 124.392 0.084 ;
    END
  END rs_i[260]
  PIN rs_i[261]
    DIRECTION INPUT ;
    USE SIGNAL ;
    PORT
      LAYER M5 ;
        RECT  124.56 0 124.584 0.084 ;
    END
  END rs_i[261]
  PIN rs_i[262]
    DIRECTION INPUT ;
    USE SIGNAL ;
    PORT
      LAYER M5 ;
        RECT  124.752 0 124.776 0.084 ;
    END
  END rs_i[262]
  PIN rs_i[263]
    DIRECTION INPUT ;
    USE SIGNAL ;
    PORT
      LAYER M5 ;
        RECT  124.944 0 124.968 0.084 ;
    END
  END rs_i[263]
  PIN rs_i[264]
    DIRECTION INPUT ;
    USE SIGNAL ;
    PORT
      LAYER M5 ;
        RECT  125.136 0 125.16 0.084 ;
    END
  END rs_i[264]
  PIN rs_i[265]
    DIRECTION INPUT ;
    USE SIGNAL ;
    PORT
      LAYER M5 ;
        RECT  125.328 0 125.352 0.084 ;
    END
  END rs_i[265]
  PIN rs_i[266]
    DIRECTION INPUT ;
    USE SIGNAL ;
    PORT
      LAYER M5 ;
        RECT  125.52 0 125.544 0.084 ;
    END
  END rs_i[266]
  PIN rs_i[267]
    DIRECTION INPUT ;
    USE SIGNAL ;
    PORT
      LAYER M5 ;
        RECT  125.712 0 125.736 0.084 ;
    END
  END rs_i[267]
  PIN rs_i[268]
    DIRECTION INPUT ;
    USE SIGNAL ;
    PORT
      LAYER M5 ;
        RECT  125.904 0 125.928 0.084 ;
    END
  END rs_i[268]
  PIN rs_i[269]
    DIRECTION INPUT ;
    USE SIGNAL ;
    PORT
      LAYER M5 ;
        RECT  126.096 0 126.12 0.084 ;
    END
  END rs_i[269]
  PIN rs_i[26]
    DIRECTION INPUT ;
    USE SIGNAL ;
    PORT
      LAYER M5 ;
        RECT  90.192 0 90.216 0.084 ;
    END
  END rs_i[26]
  PIN rs_i[270]
    DIRECTION INPUT ;
    USE SIGNAL ;
    PORT
      LAYER M5 ;
        RECT  126.288 0 126.312 0.084 ;
    END
  END rs_i[270]
  PIN rs_i[271]
    DIRECTION INPUT ;
    USE SIGNAL ;
    PORT
      LAYER M5 ;
        RECT  126.48 0 126.504 0.084 ;
    END
  END rs_i[271]
  PIN rs_i[272]
    DIRECTION INPUT ;
    USE SIGNAL ;
    PORT
      LAYER M5 ;
        RECT  126.672 0 126.696 0.084 ;
    END
  END rs_i[272]
  PIN rs_i[273]
    DIRECTION INPUT ;
    USE SIGNAL ;
    PORT
      LAYER M5 ;
        RECT  126.864 0 126.888 0.084 ;
    END
  END rs_i[273]
  PIN rs_i[274]
    DIRECTION INPUT ;
    USE SIGNAL ;
    PORT
      LAYER M5 ;
        RECT  127.056 0 127.08 0.084 ;
    END
  END rs_i[274]
  PIN rs_i[275]
    DIRECTION INPUT ;
    USE SIGNAL ;
    PORT
      LAYER M5 ;
        RECT  127.248 0 127.272 0.084 ;
    END
  END rs_i[275]
  PIN rs_i[27]
    DIRECTION INPUT ;
    USE SIGNAL ;
    PORT
      LAYER M5 ;
        RECT  90.384 0 90.408 0.084 ;
    END
  END rs_i[27]
  PIN rs_i[28]
    DIRECTION INPUT ;
    USE SIGNAL ;
    PORT
      LAYER M5 ;
        RECT  90.576 0 90.6 0.084 ;
    END
  END rs_i[28]
  PIN rs_i[29]
    DIRECTION INPUT ;
    USE SIGNAL ;
    PORT
      LAYER M5 ;
        RECT  90.768 0 90.792 0.084 ;
    END
  END rs_i[29]
  PIN rs_i[2]
    DIRECTION INPUT ;
    USE SIGNAL ;
    PORT
      LAYER M5 ;
        RECT  104.016 0 104.04 0.084 ;
    END
  END rs_i[2]
  PIN rs_i[30]
    DIRECTION INPUT ;
    USE SIGNAL ;
    PORT
      LAYER M5 ;
        RECT  90.96 0 90.984 0.084 ;
    END
  END rs_i[30]
  PIN rs_i[31]
    DIRECTION INPUT ;
    USE SIGNAL ;
    PORT
      LAYER M5 ;
        RECT  91.152 0 91.176 0.084 ;
    END
  END rs_i[31]
  PIN rs_i[32]
    DIRECTION INPUT ;
    USE SIGNAL ;
    PORT
      LAYER M5 ;
        RECT  91.344 0 91.368 0.084 ;
    END
  END rs_i[32]
  PIN rs_i[33]
    DIRECTION INPUT ;
    USE SIGNAL ;
    PORT
      LAYER M5 ;
        RECT  91.536 0 91.56 0.084 ;
    END
  END rs_i[33]
  PIN rs_i[34]
    DIRECTION INPUT ;
    USE SIGNAL ;
    PORT
      LAYER M5 ;
        RECT  91.728 0 91.752 0.084 ;
    END
  END rs_i[34]
  PIN rs_i[35]
    DIRECTION INPUT ;
    USE SIGNAL ;
    PORT
      LAYER M5 ;
        RECT  91.92 0 91.944 0.084 ;
    END
  END rs_i[35]
  PIN rs_i[36]
    DIRECTION INPUT ;
    USE SIGNAL ;
    PORT
      LAYER M5 ;
        RECT  92.112 0 92.136 0.084 ;
    END
  END rs_i[36]
  PIN rs_i[37]
    DIRECTION INPUT ;
    USE SIGNAL ;
    PORT
      LAYER M5 ;
        RECT  92.304 0 92.328 0.084 ;
    END
  END rs_i[37]
  PIN rs_i[38]
    DIRECTION INPUT ;
    USE SIGNAL ;
    PORT
      LAYER M5 ;
        RECT  92.496 0 92.52 0.084 ;
    END
  END rs_i[38]
  PIN rs_i[39]
    DIRECTION INPUT ;
    USE SIGNAL ;
    PORT
      LAYER M5 ;
        RECT  92.688 0 92.712 0.084 ;
    END
  END rs_i[39]
  PIN rs_i[3]
    DIRECTION INPUT ;
    USE SIGNAL ;
    PORT
      LAYER M5 ;
        RECT  104.208 0 104.232 0.084 ;
    END
  END rs_i[3]
  PIN rs_i[40]
    DIRECTION INPUT ;
    USE SIGNAL ;
    PORT
      LAYER M5 ;
        RECT  92.88 0 92.904 0.084 ;
    END
  END rs_i[40]
  PIN rs_i[41]
    DIRECTION INPUT ;
    USE SIGNAL ;
    PORT
      LAYER M5 ;
        RECT  93.072 0 93.096 0.084 ;
    END
  END rs_i[41]
  PIN rs_i[42]
    DIRECTION INPUT ;
    USE SIGNAL ;
    PORT
      LAYER M5 ;
        RECT  93.264 0 93.288 0.084 ;
    END
  END rs_i[42]
  PIN rs_i[43]
    DIRECTION INPUT ;
    USE SIGNAL ;
    PORT
      LAYER M5 ;
        RECT  93.456 0 93.48 0.084 ;
    END
  END rs_i[43]
  PIN rs_i[44]
    DIRECTION INPUT ;
    USE SIGNAL ;
    PORT
      LAYER M5 ;
        RECT  93.648 0 93.672 0.084 ;
    END
  END rs_i[44]
  PIN rs_i[45]
    DIRECTION INPUT ;
    USE SIGNAL ;
    PORT
      LAYER M5 ;
        RECT  93.84 0 93.864 0.084 ;
    END
  END rs_i[45]
  PIN rs_i[46]
    DIRECTION INPUT ;
    USE SIGNAL ;
    PORT
      LAYER M5 ;
        RECT  94.032 0 94.056 0.084 ;
    END
  END rs_i[46]
  PIN rs_i[47]
    DIRECTION INPUT ;
    USE SIGNAL ;
    PORT
      LAYER M5 ;
        RECT  94.224 0 94.248 0.084 ;
    END
  END rs_i[47]
  PIN rs_i[48]
    DIRECTION INPUT ;
    USE SIGNAL ;
    PORT
      LAYER M5 ;
        RECT  94.416 0 94.44 0.084 ;
    END
  END rs_i[48]
  PIN rs_i[49]
    DIRECTION INPUT ;
    USE SIGNAL ;
    PORT
      LAYER M5 ;
        RECT  94.608 0 94.632 0.084 ;
    END
  END rs_i[49]
  PIN rs_i[4]
    DIRECTION INPUT ;
    USE SIGNAL ;
    PORT
      LAYER M5 ;
        RECT  104.4 0 104.424 0.084 ;
    END
  END rs_i[4]
  PIN rs_i[50]
    DIRECTION INPUT ;
    USE SIGNAL ;
    PORT
      LAYER M5 ;
        RECT  94.8 0 94.824 0.084 ;
    END
  END rs_i[50]
  PIN rs_i[51]
    DIRECTION INPUT ;
    USE SIGNAL ;
    PORT
      LAYER M5 ;
        RECT  94.992 0 95.016 0.084 ;
    END
  END rs_i[51]
  PIN rs_i[52]
    DIRECTION INPUT ;
    USE SIGNAL ;
    PORT
      LAYER M5 ;
        RECT  95.184 0 95.208 0.084 ;
    END
  END rs_i[52]
  PIN rs_i[53]
    DIRECTION INPUT ;
    USE SIGNAL ;
    PORT
      LAYER M5 ;
        RECT  95.376 0 95.4 0.084 ;
    END
  END rs_i[53]
  PIN rs_i[54]
    DIRECTION INPUT ;
    USE SIGNAL ;
    PORT
      LAYER M5 ;
        RECT  95.568 0 95.592 0.084 ;
    END
  END rs_i[54]
  PIN rs_i[55]
    DIRECTION INPUT ;
    USE SIGNAL ;
    PORT
      LAYER M5 ;
        RECT  95.76 0 95.784 0.084 ;
    END
  END rs_i[55]
  PIN rs_i[56]
    DIRECTION INPUT ;
    USE SIGNAL ;
    PORT
      LAYER M5 ;
        RECT  83.664 0 83.688 0.084 ;
    END
  END rs_i[56]
  PIN rs_i[57]
    DIRECTION INPUT ;
    USE SIGNAL ;
    PORT
      LAYER M5 ;
        RECT  83.856 0 83.88 0.084 ;
    END
  END rs_i[57]
  PIN rs_i[58]
    DIRECTION INPUT ;
    USE SIGNAL ;
    PORT
      LAYER M5 ;
        RECT  84.048 0 84.072 0.084 ;
    END
  END rs_i[58]
  PIN rs_i[59]
    DIRECTION INPUT ;
    USE SIGNAL ;
    PORT
      LAYER M5 ;
        RECT  84.24 0 84.264 0.084 ;
    END
  END rs_i[59]
  PIN rs_i[5]
    DIRECTION INPUT ;
    USE SIGNAL ;
    PORT
      LAYER M5 ;
        RECT  104.592 0 104.616 0.084 ;
    END
  END rs_i[5]
  PIN rs_i[60]
    DIRECTION INPUT ;
    USE SIGNAL ;
    PORT
      LAYER M5 ;
        RECT  84.432 0 84.456 0.084 ;
    END
  END rs_i[60]
  PIN rs_i[61]
    DIRECTION INPUT ;
    USE SIGNAL ;
    PORT
      LAYER M5 ;
        RECT  84.624 0 84.648 0.084 ;
    END
  END rs_i[61]
  PIN rs_i[62]
    DIRECTION INPUT ;
    USE SIGNAL ;
    PORT
      LAYER M5 ;
        RECT  84.816 0 84.84 0.084 ;
    END
  END rs_i[62]
  PIN rs_i[63]
    DIRECTION INPUT ;
    USE SIGNAL ;
    PORT
      LAYER M5 ;
        RECT  85.008 0 85.032 0.084 ;
    END
  END rs_i[63]
  PIN rs_i[64]
    DIRECTION INPUT ;
    USE SIGNAL ;
    PORT
      LAYER M5 ;
        RECT  85.2 0 85.224 0.084 ;
    END
  END rs_i[64]
  PIN rs_i[65]
    DIRECTION INPUT ;
    USE SIGNAL ;
    PORT
      LAYER M5 ;
        RECT  85.392 0 85.416 0.084 ;
    END
  END rs_i[65]
  PIN rs_i[66]
    DIRECTION INPUT ;
    USE SIGNAL ;
    PORT
      LAYER M5 ;
        RECT  85.584 0 85.608 0.084 ;
    END
  END rs_i[66]
  PIN rs_i[67]
    DIRECTION INPUT ;
    USE SIGNAL ;
    PORT
      LAYER M5 ;
        RECT  85.776 0 85.8 0.084 ;
    END
  END rs_i[67]
  PIN rs_i[68]
    DIRECTION INPUT ;
    USE SIGNAL ;
    PORT
      LAYER M5 ;
        RECT  85.968 0 85.992 0.084 ;
    END
  END rs_i[68]
  PIN rs_i[69]
    DIRECTION INPUT ;
    USE SIGNAL ;
    PORT
      LAYER M5 ;
        RECT  86.16 0 86.184 0.084 ;
    END
  END rs_i[69]
  PIN rs_i[6]
    DIRECTION INPUT ;
    USE SIGNAL ;
    PORT
      LAYER M5 ;
        RECT  104.784 0 104.808 0.084 ;
    END
  END rs_i[6]
  PIN rs_i[70]
    DIRECTION INPUT ;
    USE SIGNAL ;
    PORT
      LAYER M5 ;
        RECT  86.352 0 86.376 0.084 ;
    END
  END rs_i[70]
  PIN rs_i[71]
    DIRECTION INPUT ;
    USE SIGNAL ;
    PORT
      LAYER M5 ;
        RECT  86.544 0 86.568 0.084 ;
    END
  END rs_i[71]
  PIN rs_i[72]
    DIRECTION INPUT ;
    USE SIGNAL ;
    PORT
      LAYER M5 ;
        RECT  86.736 0 86.76 0.084 ;
    END
  END rs_i[72]
  PIN rs_i[73]
    DIRECTION INPUT ;
    USE SIGNAL ;
    PORT
      LAYER M5 ;
        RECT  86.928 0 86.952 0.084 ;
    END
  END rs_i[73]
  PIN rs_i[74]
    DIRECTION INPUT ;
    USE SIGNAL ;
    PORT
      LAYER M5 ;
        RECT  87.12 0 87.144 0.084 ;
    END
  END rs_i[74]
  PIN rs_i[75]
    DIRECTION INPUT ;
    USE SIGNAL ;
    PORT
      LAYER M5 ;
        RECT  87.312 0 87.336 0.084 ;
    END
  END rs_i[75]
  PIN rs_i[76]
    DIRECTION INPUT ;
    USE SIGNAL ;
    PORT
      LAYER M5 ;
        RECT  87.504 0 87.528 0.084 ;
    END
  END rs_i[76]
  PIN rs_i[77]
    DIRECTION INPUT ;
    USE SIGNAL ;
    PORT
      LAYER M5 ;
        RECT  87.696 0 87.72 0.084 ;
    END
  END rs_i[77]
  PIN rs_i[78]
    DIRECTION INPUT ;
    USE SIGNAL ;
    PORT
      LAYER M5 ;
        RECT  87.888 0 87.912 0.084 ;
    END
  END rs_i[78]
  PIN rs_i[79]
    DIRECTION INPUT ;
    USE SIGNAL ;
    PORT
      LAYER M5 ;
        RECT  88.08 0 88.104 0.084 ;
    END
  END rs_i[79]
  PIN rs_i[7]
    DIRECTION INPUT ;
    USE SIGNAL ;
    PORT
      LAYER M5 ;
        RECT  104.976 0 105 0.084 ;
    END
  END rs_i[7]
  PIN rs_i[80]
    DIRECTION INPUT ;
    USE SIGNAL ;
    PORT
      LAYER M5 ;
        RECT  88.272 0 88.296 0.084 ;
    END
  END rs_i[80]
  PIN rs_i[81]
    DIRECTION INPUT ;
    USE SIGNAL ;
    PORT
      LAYER M5 ;
        RECT  88.464 0 88.488 0.084 ;
    END
  END rs_i[81]
  PIN rs_i[82]
    DIRECTION INPUT ;
    USE SIGNAL ;
    PORT
      LAYER M5 ;
        RECT  88.656 0 88.68 0.084 ;
    END
  END rs_i[82]
  PIN rs_i[83]
    DIRECTION INPUT ;
    USE SIGNAL ;
    PORT
      LAYER M5 ;
        RECT  88.848 0 88.872 0.084 ;
    END
  END rs_i[83]
  PIN rs_i[84]
    DIRECTION INPUT ;
    USE SIGNAL ;
    PORT
      LAYER M5 ;
        RECT  89.04 0 89.064 0.084 ;
    END
  END rs_i[84]
  PIN rs_i[85]
    DIRECTION INPUT ;
    USE SIGNAL ;
    PORT
      LAYER M5 ;
        RECT  89.232 0 89.256 0.084 ;
    END
  END rs_i[85]
  PIN rs_i[86]
    DIRECTION INPUT ;
    USE SIGNAL ;
    PORT
      LAYER M5 ;
        RECT  89.424 0 89.448 0.084 ;
    END
  END rs_i[86]
  PIN rs_i[87]
    DIRECTION INPUT ;
    USE SIGNAL ;
    PORT
      LAYER M5 ;
        RECT  89.616 0 89.64 0.084 ;
    END
  END rs_i[87]
  PIN rs_i[88]
    DIRECTION INPUT ;
    USE SIGNAL ;
    PORT
      LAYER M5 ;
        RECT  108.24 0 108.264 0.084 ;
    END
  END rs_i[88]
  PIN rs_i[89]
    DIRECTION INPUT ;
    USE SIGNAL ;
    PORT
      LAYER M5 ;
        RECT  108.432 0 108.456 0.084 ;
    END
  END rs_i[89]
  PIN rs_i[8]
    DIRECTION INPUT ;
    USE SIGNAL ;
    PORT
      LAYER M5 ;
        RECT  105.168 0 105.192 0.084 ;
    END
  END rs_i[8]
  PIN rs_i[90]
    DIRECTION INPUT ;
    USE SIGNAL ;
    PORT
      LAYER M5 ;
        RECT  108.624 0 108.648 0.084 ;
    END
  END rs_i[90]
  PIN rs_i[91]
    DIRECTION INPUT ;
    USE SIGNAL ;
    PORT
      LAYER M5 ;
        RECT  108.816 0 108.84 0.084 ;
    END
  END rs_i[91]
  PIN rs_i[92]
    DIRECTION INPUT ;
    USE SIGNAL ;
    PORT
      LAYER M5 ;
        RECT  109.008 0 109.032 0.084 ;
    END
  END rs_i[92]
  PIN rs_i[93]
    DIRECTION INPUT ;
    USE SIGNAL ;
    PORT
      LAYER M5 ;
        RECT  109.2 0 109.224 0.084 ;
    END
  END rs_i[93]
  PIN rs_i[94]
    DIRECTION INPUT ;
    USE SIGNAL ;
    PORT
      LAYER M5 ;
        RECT  109.392 0 109.416 0.084 ;
    END
  END rs_i[94]
  PIN rs_i[95]
    DIRECTION INPUT ;
    USE SIGNAL ;
    PORT
      LAYER M5 ;
        RECT  109.584 0 109.608 0.084 ;
    END
  END rs_i[95]
  PIN rs_i[96]
    DIRECTION INPUT ;
    USE SIGNAL ;
    PORT
      LAYER M5 ;
        RECT  109.776 0 109.8 0.084 ;
    END
  END rs_i[96]
  PIN rs_i[97]
    DIRECTION INPUT ;
    USE SIGNAL ;
    PORT
      LAYER M5 ;
        RECT  109.968 0 109.992 0.084 ;
    END
  END rs_i[97]
  PIN rs_i[98]
    DIRECTION INPUT ;
    USE SIGNAL ;
    PORT
      LAYER M5 ;
        RECT  110.16 0 110.184 0.084 ;
    END
  END rs_i[98]
  PIN rs_i[99]
    DIRECTION INPUT ;
    USE SIGNAL ;
    PORT
      LAYER M5 ;
        RECT  110.352 0 110.376 0.084 ;
    END
  END rs_i[99]
  PIN rs_i[9]
    DIRECTION INPUT ;
    USE SIGNAL ;
    PORT
      LAYER M5 ;
        RECT  105.36 0 105.384 0.084 ;
    END
  END rs_i[9]
  PIN rs_o[0]
    DIRECTION OUTPUT ;
    USE SIGNAL ;
    PORT
      LAYER M5 ;
        RECT  127.44 0 127.464 0.084 ;
    END
  END rs_o[0]
  PIN rs_o[100]
    DIRECTION OUTPUT ;
    USE SIGNAL ;
    PORT
      LAYER M5 ;
        RECT  198.864 0 198.888 0.084 ;
    END
  END rs_o[100]
  PIN rs_o[101]
    DIRECTION OUTPUT ;
    USE SIGNAL ;
    PORT
      LAYER M5 ;
        RECT  199.056 0 199.08 0.084 ;
    END
  END rs_o[101]
  PIN rs_o[102]
    DIRECTION OUTPUT ;
    USE SIGNAL ;
    PORT
      LAYER M5 ;
        RECT  199.248 0 199.272 0.084 ;
    END
  END rs_o[102]
  PIN rs_o[103]
    DIRECTION OUTPUT ;
    USE SIGNAL ;
    PORT
      LAYER M5 ;
        RECT  199.44 0 199.464 0.084 ;
    END
  END rs_o[103]
  PIN rs_o[104]
    DIRECTION OUTPUT ;
    USE SIGNAL ;
    PORT
      LAYER M5 ;
        RECT  199.632 0 199.656 0.084 ;
    END
  END rs_o[104]
  PIN rs_o[105]
    DIRECTION OUTPUT ;
    USE SIGNAL ;
    PORT
      LAYER M5 ;
        RECT  199.824 0 199.848 0.084 ;
    END
  END rs_o[105]
  PIN rs_o[106]
    DIRECTION OUTPUT ;
    USE SIGNAL ;
    PORT
      LAYER M5 ;
        RECT  200.016 0 200.04 0.084 ;
    END
  END rs_o[106]
  PIN rs_o[107]
    DIRECTION OUTPUT ;
    USE SIGNAL ;
    PORT
      LAYER M5 ;
        RECT  200.208 0 200.232 0.084 ;
    END
  END rs_o[107]
  PIN rs_o[108]
    DIRECTION OUTPUT ;
    USE SIGNAL ;
    PORT
      LAYER M5 ;
        RECT  200.4 0 200.424 0.084 ;
    END
  END rs_o[108]
  PIN rs_o[109]
    DIRECTION OUTPUT ;
    USE SIGNAL ;
    PORT
      LAYER M5 ;
        RECT  200.592 0 200.616 0.084 ;
    END
  END rs_o[109]
  PIN rs_o[10]
    DIRECTION OUTPUT ;
    USE SIGNAL ;
    PORT
      LAYER M5 ;
        RECT  135.504 0 135.528 0.084 ;
    END
  END rs_o[10]
  PIN rs_o[110]
    DIRECTION OUTPUT ;
    USE SIGNAL ;
    PORT
      LAYER M5 ;
        RECT  200.784 0 200.808 0.084 ;
    END
  END rs_o[110]
  PIN rs_o[111]
    DIRECTION OUTPUT ;
    USE SIGNAL ;
    PORT
      LAYER M5 ;
        RECT  200.976 0 201 0.084 ;
    END
  END rs_o[111]
  PIN rs_o[112]
    DIRECTION OUTPUT ;
    USE SIGNAL ;
    PORT
      LAYER M5 ;
        RECT  201.168 0 201.192 0.084 ;
    END
  END rs_o[112]
  PIN rs_o[113]
    DIRECTION OUTPUT ;
    USE SIGNAL ;
    PORT
      LAYER M5 ;
        RECT  201.36 0 201.384 0.084 ;
    END
  END rs_o[113]
  PIN rs_o[114]
    DIRECTION OUTPUT ;
    USE SIGNAL ;
    PORT
      LAYER M5 ;
        RECT  201.552 0 201.576 0.084 ;
    END
  END rs_o[114]
  PIN rs_o[115]
    DIRECTION OUTPUT ;
    USE SIGNAL ;
    PORT
      LAYER M5 ;
        RECT  201.744 0 201.768 0.084 ;
    END
  END rs_o[115]
  PIN rs_o[116]
    DIRECTION OUTPUT ;
    USE SIGNAL ;
    PORT
      LAYER M5 ;
        RECT  201.936 0 201.96 0.084 ;
    END
  END rs_o[116]
  PIN rs_o[117]
    DIRECTION OUTPUT ;
    USE SIGNAL ;
    PORT
      LAYER M5 ;
        RECT  202.128 0 202.152 0.084 ;
    END
  END rs_o[117]
  PIN rs_o[118]
    DIRECTION OUTPUT ;
    USE SIGNAL ;
    PORT
      LAYER M5 ;
        RECT  202.32 0 202.344 0.084 ;
    END
  END rs_o[118]
  PIN rs_o[119]
    DIRECTION OUTPUT ;
    USE SIGNAL ;
    PORT
      LAYER M5 ;
        RECT  202.512 0 202.536 0.084 ;
    END
  END rs_o[119]
  PIN rs_o[11]
    DIRECTION OUTPUT ;
    USE SIGNAL ;
    PORT
      LAYER M5 ;
        RECT  135.696 0 135.72 0.084 ;
    END
  END rs_o[11]
  PIN rs_o[120]
    DIRECTION OUTPUT ;
    USE SIGNAL ;
    PORT
      LAYER M5 ;
        RECT  202.704 0 202.728 0.084 ;
    END
  END rs_o[120]
  PIN rs_o[121]
    DIRECTION OUTPUT ;
    USE SIGNAL ;
    PORT
      LAYER M5 ;
        RECT  202.896 0 202.92 0.084 ;
    END
  END rs_o[121]
  PIN rs_o[122]
    DIRECTION OUTPUT ;
    USE SIGNAL ;
    PORT
      LAYER M5 ;
        RECT  203.088 0 203.112 0.084 ;
    END
  END rs_o[122]
  PIN rs_o[123]
    DIRECTION OUTPUT ;
    USE SIGNAL ;
    PORT
      LAYER M5 ;
        RECT  203.28 0 203.304 0.084 ;
    END
  END rs_o[123]
  PIN rs_o[124]
    DIRECTION OUTPUT ;
    USE SIGNAL ;
    PORT
      LAYER M5 ;
        RECT  203.472 0 203.496 0.084 ;
    END
  END rs_o[124]
  PIN rs_o[125]
    DIRECTION OUTPUT ;
    USE SIGNAL ;
    PORT
      LAYER M5 ;
        RECT  203.664 0 203.688 0.084 ;
    END
  END rs_o[125]
  PIN rs_o[126]
    DIRECTION OUTPUT ;
    USE SIGNAL ;
    PORT
      LAYER M5 ;
        RECT  203.856 0 203.88 0.084 ;
    END
  END rs_o[126]
  PIN rs_o[127]
    DIRECTION OUTPUT ;
    USE SIGNAL ;
    PORT
      LAYER M5 ;
        RECT  204.048 0 204.072 0.084 ;
    END
  END rs_o[127]
  PIN rs_o[128]
    DIRECTION OUTPUT ;
    USE SIGNAL ;
    PORT
      LAYER M5 ;
        RECT  204.24 0 204.264 0.084 ;
    END
  END rs_o[128]
  PIN rs_o[129]
    DIRECTION OUTPUT ;
    USE SIGNAL ;
    PORT
      LAYER M5 ;
        RECT  204.432 0 204.456 0.084 ;
    END
  END rs_o[129]
  PIN rs_o[12]
    DIRECTION OUTPUT ;
    USE SIGNAL ;
    PORT
      LAYER M5 ;
        RECT  135.888 0 135.912 0.084 ;
    END
  END rs_o[12]
  PIN rs_o[130]
    DIRECTION OUTPUT ;
    USE SIGNAL ;
    PORT
      LAYER M5 ;
        RECT  204.624 0 204.648 0.084 ;
    END
  END rs_o[130]
  PIN rs_o[131]
    DIRECTION OUTPUT ;
    USE SIGNAL ;
    PORT
      LAYER M5 ;
        RECT  204.816 0 204.84 0.084 ;
    END
  END rs_o[131]
  PIN rs_o[132]
    DIRECTION OUTPUT ;
    USE SIGNAL ;
    PORT
      LAYER M5 ;
        RECT  211.152 0 211.176 0.084 ;
    END
  END rs_o[132]
  PIN rs_o[133]
    DIRECTION OUTPUT ;
    USE SIGNAL ;
    PORT
      LAYER M5 ;
        RECT  211.344 0 211.368 0.084 ;
    END
  END rs_o[133]
  PIN rs_o[134]
    DIRECTION OUTPUT ;
    USE SIGNAL ;
    PORT
      LAYER M5 ;
        RECT  211.536 0 211.56 0.084 ;
    END
  END rs_o[134]
  PIN rs_o[135]
    DIRECTION OUTPUT ;
    USE SIGNAL ;
    PORT
      LAYER M5 ;
        RECT  211.728 0 211.752 0.084 ;
    END
  END rs_o[135]
  PIN rs_o[136]
    DIRECTION OUTPUT ;
    USE SIGNAL ;
    PORT
      LAYER M5 ;
        RECT  211.92 0 211.944 0.084 ;
    END
  END rs_o[136]
  PIN rs_o[137]
    DIRECTION OUTPUT ;
    USE SIGNAL ;
    PORT
      LAYER M5 ;
        RECT  212.112 0 212.136 0.084 ;
    END
  END rs_o[137]
  PIN rs_o[138]
    DIRECTION OUTPUT ;
    USE SIGNAL ;
    PORT
      LAYER M5 ;
        RECT  212.304 0 212.328 0.084 ;
    END
  END rs_o[138]
  PIN rs_o[139]
    DIRECTION OUTPUT ;
    USE SIGNAL ;
    PORT
      LAYER M5 ;
        RECT  212.496 0 212.52 0.084 ;
    END
  END rs_o[139]
  PIN rs_o[13]
    DIRECTION OUTPUT ;
    USE SIGNAL ;
    PORT
      LAYER M5 ;
        RECT  136.08 0 136.104 0.084 ;
    END
  END rs_o[13]
  PIN rs_o[140]
    DIRECTION OUTPUT ;
    USE SIGNAL ;
    PORT
      LAYER M5 ;
        RECT  212.688 0 212.712 0.084 ;
    END
  END rs_o[140]
  PIN rs_o[141]
    DIRECTION OUTPUT ;
    USE SIGNAL ;
    PORT
      LAYER M5 ;
        RECT  212.88 0 212.904 0.084 ;
    END
  END rs_o[141]
  PIN rs_o[142]
    DIRECTION OUTPUT ;
    USE SIGNAL ;
    PORT
      LAYER M5 ;
        RECT  213.072 0 213.096 0.084 ;
    END
  END rs_o[142]
  PIN rs_o[143]
    DIRECTION OUTPUT ;
    USE SIGNAL ;
    PORT
      LAYER M5 ;
        RECT  213.264 0 213.288 0.084 ;
    END
  END rs_o[143]
  PIN rs_o[144]
    DIRECTION OUTPUT ;
    USE SIGNAL ;
    PORT
      LAYER M5 ;
        RECT  213.456 0 213.48 0.084 ;
    END
  END rs_o[144]
  PIN rs_o[145]
    DIRECTION OUTPUT ;
    USE SIGNAL ;
    PORT
      LAYER M5 ;
        RECT  213.648 0 213.672 0.084 ;
    END
  END rs_o[145]
  PIN rs_o[146]
    DIRECTION OUTPUT ;
    USE SIGNAL ;
    PORT
      LAYER M5 ;
        RECT  213.84 0 213.864 0.084 ;
    END
  END rs_o[146]
  PIN rs_o[147]
    DIRECTION OUTPUT ;
    USE SIGNAL ;
    PORT
      LAYER M5 ;
        RECT  214.032 0 214.056 0.084 ;
    END
  END rs_o[147]
  PIN rs_o[148]
    DIRECTION OUTPUT ;
    USE SIGNAL ;
    PORT
      LAYER M5 ;
        RECT  214.224 0 214.248 0.084 ;
    END
  END rs_o[148]
  PIN rs_o[149]
    DIRECTION OUTPUT ;
    USE SIGNAL ;
    PORT
      LAYER M5 ;
        RECT  214.416 0 214.44 0.084 ;
    END
  END rs_o[149]
  PIN rs_o[14]
    DIRECTION OUTPUT ;
    USE SIGNAL ;
    PORT
      LAYER M5 ;
        RECT  136.272 0 136.296 0.084 ;
    END
  END rs_o[14]
  PIN rs_o[150]
    DIRECTION OUTPUT ;
    USE SIGNAL ;
    PORT
      LAYER M5 ;
        RECT  214.608 0 214.632 0.084 ;
    END
  END rs_o[150]
  PIN rs_o[151]
    DIRECTION OUTPUT ;
    USE SIGNAL ;
    PORT
      LAYER M5 ;
        RECT  214.8 0 214.824 0.084 ;
    END
  END rs_o[151]
  PIN rs_o[152]
    DIRECTION OUTPUT ;
    USE SIGNAL ;
    PORT
      LAYER M5 ;
        RECT  214.992 0 215.016 0.084 ;
    END
  END rs_o[152]
  PIN rs_o[153]
    DIRECTION OUTPUT ;
    USE SIGNAL ;
    PORT
      LAYER M5 ;
        RECT  215.184 0 215.208 0.084 ;
    END
  END rs_o[153]
  PIN rs_o[154]
    DIRECTION OUTPUT ;
    USE SIGNAL ;
    PORT
      LAYER M5 ;
        RECT  215.376 0 215.4 0.084 ;
    END
  END rs_o[154]
  PIN rs_o[155]
    DIRECTION OUTPUT ;
    USE SIGNAL ;
    PORT
      LAYER M5 ;
        RECT  215.568 0 215.592 0.084 ;
    END
  END rs_o[155]
  PIN rs_o[156]
    DIRECTION OUTPUT ;
    USE SIGNAL ;
    PORT
      LAYER M5 ;
        RECT  215.76 0 215.784 0.084 ;
    END
  END rs_o[156]
  PIN rs_o[157]
    DIRECTION OUTPUT ;
    USE SIGNAL ;
    PORT
      LAYER M5 ;
        RECT  215.952 0 215.976 0.084 ;
    END
  END rs_o[157]
  PIN rs_o[158]
    DIRECTION OUTPUT ;
    USE SIGNAL ;
    PORT
      LAYER M5 ;
        RECT  216.144 0 216.168 0.084 ;
    END
  END rs_o[158]
  PIN rs_o[159]
    DIRECTION OUTPUT ;
    USE SIGNAL ;
    PORT
      LAYER M5 ;
        RECT  216.336 0 216.36 0.084 ;
    END
  END rs_o[159]
  PIN rs_o[15]
    DIRECTION OUTPUT ;
    USE SIGNAL ;
    PORT
      LAYER M5 ;
        RECT  136.464 0 136.488 0.084 ;
    END
  END rs_o[15]
  PIN rs_o[160]
    DIRECTION OUTPUT ;
    USE SIGNAL ;
    PORT
      LAYER M5 ;
        RECT  216.528 0 216.552 0.084 ;
    END
  END rs_o[160]
  PIN rs_o[161]
    DIRECTION OUTPUT ;
    USE SIGNAL ;
    PORT
      LAYER M5 ;
        RECT  216.72 0 216.744 0.084 ;
    END
  END rs_o[161]
  PIN rs_o[162]
    DIRECTION OUTPUT ;
    USE SIGNAL ;
    PORT
      LAYER M5 ;
        RECT  216.912 0 216.936 0.084 ;
    END
  END rs_o[162]
  PIN rs_o[163]
    DIRECTION OUTPUT ;
    USE SIGNAL ;
    PORT
      LAYER M5 ;
        RECT  217.104 0 217.128 0.084 ;
    END
  END rs_o[163]
  PIN rs_o[164]
    DIRECTION OUTPUT ;
    USE SIGNAL ;
    PORT
      LAYER M5 ;
        RECT  223.44 0 223.464 0.084 ;
    END
  END rs_o[164]
  PIN rs_o[165]
    DIRECTION OUTPUT ;
    USE SIGNAL ;
    PORT
      LAYER M5 ;
        RECT  223.632 0 223.656 0.084 ;
    END
  END rs_o[165]
  PIN rs_o[166]
    DIRECTION OUTPUT ;
    USE SIGNAL ;
    PORT
      LAYER M5 ;
        RECT  223.824 0 223.848 0.084 ;
    END
  END rs_o[166]
  PIN rs_o[167]
    DIRECTION OUTPUT ;
    USE SIGNAL ;
    PORT
      LAYER M5 ;
        RECT  224.016 0 224.04 0.084 ;
    END
  END rs_o[167]
  PIN rs_o[168]
    DIRECTION OUTPUT ;
    USE SIGNAL ;
    PORT
      LAYER M5 ;
        RECT  224.208 0 224.232 0.084 ;
    END
  END rs_o[168]
  PIN rs_o[169]
    DIRECTION OUTPUT ;
    USE SIGNAL ;
    PORT
      LAYER M5 ;
        RECT  224.4 0 224.424 0.084 ;
    END
  END rs_o[169]
  PIN rs_o[16]
    DIRECTION OUTPUT ;
    USE SIGNAL ;
    PORT
      LAYER M5 ;
        RECT  136.656 0 136.68 0.084 ;
    END
  END rs_o[16]
  PIN rs_o[170]
    DIRECTION OUTPUT ;
    USE SIGNAL ;
    PORT
      LAYER M5 ;
        RECT  224.592 0 224.616 0.084 ;
    END
  END rs_o[170]
  PIN rs_o[171]
    DIRECTION OUTPUT ;
    USE SIGNAL ;
    PORT
      LAYER M5 ;
        RECT  224.784 0 224.808 0.084 ;
    END
  END rs_o[171]
  PIN rs_o[172]
    DIRECTION OUTPUT ;
    USE SIGNAL ;
    PORT
      LAYER M5 ;
        RECT  224.976 0 225 0.084 ;
    END
  END rs_o[172]
  PIN rs_o[173]
    DIRECTION OUTPUT ;
    USE SIGNAL ;
    PORT
      LAYER M5 ;
        RECT  225.168 0 225.192 0.084 ;
    END
  END rs_o[173]
  PIN rs_o[174]
    DIRECTION OUTPUT ;
    USE SIGNAL ;
    PORT
      LAYER M5 ;
        RECT  225.36 0 225.384 0.084 ;
    END
  END rs_o[174]
  PIN rs_o[175]
    DIRECTION OUTPUT ;
    USE SIGNAL ;
    PORT
      LAYER M5 ;
        RECT  225.552 0 225.576 0.084 ;
    END
  END rs_o[175]
  PIN rs_o[176]
    DIRECTION OUTPUT ;
    USE SIGNAL ;
    PORT
      LAYER M5 ;
        RECT  225.744 0 225.768 0.084 ;
    END
  END rs_o[176]
  PIN rs_o[177]
    DIRECTION OUTPUT ;
    USE SIGNAL ;
    PORT
      LAYER M5 ;
        RECT  225.936 0 225.96 0.084 ;
    END
  END rs_o[177]
  PIN rs_o[178]
    DIRECTION OUTPUT ;
    USE SIGNAL ;
    PORT
      LAYER M5 ;
        RECT  226.128 0 226.152 0.084 ;
    END
  END rs_o[178]
  PIN rs_o[179]
    DIRECTION OUTPUT ;
    USE SIGNAL ;
    PORT
      LAYER M5 ;
        RECT  226.32 0 226.344 0.084 ;
    END
  END rs_o[179]
  PIN rs_o[17]
    DIRECTION OUTPUT ;
    USE SIGNAL ;
    PORT
      LAYER M5 ;
        RECT  136.848 0 136.872 0.084 ;
    END
  END rs_o[17]
  PIN rs_o[180]
    DIRECTION OUTPUT ;
    USE SIGNAL ;
    PORT
      LAYER M5 ;
        RECT  226.512 0 226.536 0.084 ;
    END
  END rs_o[180]
  PIN rs_o[181]
    DIRECTION OUTPUT ;
    USE SIGNAL ;
    PORT
      LAYER M5 ;
        RECT  226.704 0 226.728 0.084 ;
    END
  END rs_o[181]
  PIN rs_o[182]
    DIRECTION OUTPUT ;
    USE SIGNAL ;
    PORT
      LAYER M5 ;
        RECT  226.896 0 226.92 0.084 ;
    END
  END rs_o[182]
  PIN rs_o[183]
    DIRECTION OUTPUT ;
    USE SIGNAL ;
    PORT
      LAYER M5 ;
        RECT  227.088 0 227.112 0.084 ;
    END
  END rs_o[183]
  PIN rs_o[184]
    DIRECTION OUTPUT ;
    USE SIGNAL ;
    PORT
      LAYER M5 ;
        RECT  227.28 0 227.304 0.084 ;
    END
  END rs_o[184]
  PIN rs_o[185]
    DIRECTION OUTPUT ;
    USE SIGNAL ;
    PORT
      LAYER M5 ;
        RECT  227.472 0 227.496 0.084 ;
    END
  END rs_o[185]
  PIN rs_o[186]
    DIRECTION OUTPUT ;
    USE SIGNAL ;
    PORT
      LAYER M5 ;
        RECT  227.664 0 227.688 0.084 ;
    END
  END rs_o[186]
  PIN rs_o[187]
    DIRECTION OUTPUT ;
    USE SIGNAL ;
    PORT
      LAYER M5 ;
        RECT  227.856 0 227.88 0.084 ;
    END
  END rs_o[187]
  PIN rs_o[188]
    DIRECTION OUTPUT ;
    USE SIGNAL ;
    PORT
      LAYER M5 ;
        RECT  228.048 0 228.072 0.084 ;
    END
  END rs_o[188]
  PIN rs_o[189]
    DIRECTION OUTPUT ;
    USE SIGNAL ;
    PORT
      LAYER M5 ;
        RECT  228.24 0 228.264 0.084 ;
    END
  END rs_o[189]
  PIN rs_o[18]
    DIRECTION OUTPUT ;
    USE SIGNAL ;
    PORT
      LAYER M5 ;
        RECT  137.04 0 137.064 0.084 ;
    END
  END rs_o[18]
  PIN rs_o[190]
    DIRECTION OUTPUT ;
    USE SIGNAL ;
    PORT
      LAYER M5 ;
        RECT  228.432 0 228.456 0.084 ;
    END
  END rs_o[190]
  PIN rs_o[191]
    DIRECTION OUTPUT ;
    USE SIGNAL ;
    PORT
      LAYER M5 ;
        RECT  228.624 0 228.648 0.084 ;
    END
  END rs_o[191]
  PIN rs_o[192]
    DIRECTION OUTPUT ;
    USE SIGNAL ;
    PORT
      LAYER M5 ;
        RECT  228.816 0 228.84 0.084 ;
    END
  END rs_o[192]
  PIN rs_o[193]
    DIRECTION OUTPUT ;
    USE SIGNAL ;
    PORT
      LAYER M5 ;
        RECT  229.008 0 229.032 0.084 ;
    END
  END rs_o[193]
  PIN rs_o[194]
    DIRECTION OUTPUT ;
    USE SIGNAL ;
    PORT
      LAYER M5 ;
        RECT  229.2 0 229.224 0.084 ;
    END
  END rs_o[194]
  PIN rs_o[195]
    DIRECTION OUTPUT ;
    USE SIGNAL ;
    PORT
      LAYER M5 ;
        RECT  229.392 0 229.416 0.084 ;
    END
  END rs_o[195]
  PIN rs_o[196]
    DIRECTION OUTPUT ;
    USE SIGNAL ;
    PORT
      LAYER M5 ;
        RECT  205.008 0 205.032 0.084 ;
    END
  END rs_o[196]
  PIN rs_o[197]
    DIRECTION OUTPUT ;
    USE SIGNAL ;
    PORT
      LAYER M5 ;
        RECT  205.2 0 205.224 0.084 ;
    END
  END rs_o[197]
  PIN rs_o[198]
    DIRECTION OUTPUT ;
    USE SIGNAL ;
    PORT
      LAYER M5 ;
        RECT  205.392 0 205.416 0.084 ;
    END
  END rs_o[198]
  PIN rs_o[199]
    DIRECTION OUTPUT ;
    USE SIGNAL ;
    PORT
      LAYER M5 ;
        RECT  205.584 0 205.608 0.084 ;
    END
  END rs_o[199]
  PIN rs_o[19]
    DIRECTION OUTPUT ;
    USE SIGNAL ;
    PORT
      LAYER M5 ;
        RECT  137.232 0 137.256 0.084 ;
    END
  END rs_o[19]
  PIN rs_o[1]
    DIRECTION OUTPUT ;
    USE SIGNAL ;
    PORT
      LAYER M5 ;
        RECT  127.632 0 127.656 0.084 ;
    END
  END rs_o[1]
  PIN rs_o[200]
    DIRECTION OUTPUT ;
    USE SIGNAL ;
    PORT
      LAYER M5 ;
        RECT  205.776 0 205.8 0.084 ;
    END
  END rs_o[200]
  PIN rs_o[201]
    DIRECTION OUTPUT ;
    USE SIGNAL ;
    PORT
      LAYER M5 ;
        RECT  205.968 0 205.992 0.084 ;
    END
  END rs_o[201]
  PIN rs_o[202]
    DIRECTION OUTPUT ;
    USE SIGNAL ;
    PORT
      LAYER M5 ;
        RECT  206.16 0 206.184 0.084 ;
    END
  END rs_o[202]
  PIN rs_o[203]
    DIRECTION OUTPUT ;
    USE SIGNAL ;
    PORT
      LAYER M5 ;
        RECT  206.352 0 206.376 0.084 ;
    END
  END rs_o[203]
  PIN rs_o[204]
    DIRECTION OUTPUT ;
    USE SIGNAL ;
    PORT
      LAYER M5 ;
        RECT  206.544 0 206.568 0.084 ;
    END
  END rs_o[204]
  PIN rs_o[205]
    DIRECTION OUTPUT ;
    USE SIGNAL ;
    PORT
      LAYER M5 ;
        RECT  206.736 0 206.76 0.084 ;
    END
  END rs_o[205]
  PIN rs_o[206]
    DIRECTION OUTPUT ;
    USE SIGNAL ;
    PORT
      LAYER M5 ;
        RECT  206.928 0 206.952 0.084 ;
    END
  END rs_o[206]
  PIN rs_o[207]
    DIRECTION OUTPUT ;
    USE SIGNAL ;
    PORT
      LAYER M5 ;
        RECT  207.12 0 207.144 0.084 ;
    END
  END rs_o[207]
  PIN rs_o[208]
    DIRECTION OUTPUT ;
    USE SIGNAL ;
    PORT
      LAYER M5 ;
        RECT  207.312 0 207.336 0.084 ;
    END
  END rs_o[208]
  PIN rs_o[209]
    DIRECTION OUTPUT ;
    USE SIGNAL ;
    PORT
      LAYER M5 ;
        RECT  207.504 0 207.528 0.084 ;
    END
  END rs_o[209]
  PIN rs_o[20]
    DIRECTION OUTPUT ;
    USE SIGNAL ;
    PORT
      LAYER M5 ;
        RECT  137.424 0 137.448 0.084 ;
    END
  END rs_o[20]
  PIN rs_o[210]
    DIRECTION OUTPUT ;
    USE SIGNAL ;
    PORT
      LAYER M5 ;
        RECT  207.696 0 207.72 0.084 ;
    END
  END rs_o[210]
  PIN rs_o[211]
    DIRECTION OUTPUT ;
    USE SIGNAL ;
    PORT
      LAYER M5 ;
        RECT  207.888 0 207.912 0.084 ;
    END
  END rs_o[211]
  PIN rs_o[212]
    DIRECTION OUTPUT ;
    USE SIGNAL ;
    PORT
      LAYER M5 ;
        RECT  208.08 0 208.104 0.084 ;
    END
  END rs_o[212]
  PIN rs_o[213]
    DIRECTION OUTPUT ;
    USE SIGNAL ;
    PORT
      LAYER M5 ;
        RECT  208.272 0 208.296 0.084 ;
    END
  END rs_o[213]
  PIN rs_o[214]
    DIRECTION OUTPUT ;
    USE SIGNAL ;
    PORT
      LAYER M5 ;
        RECT  208.464 0 208.488 0.084 ;
    END
  END rs_o[214]
  PIN rs_o[215]
    DIRECTION OUTPUT ;
    USE SIGNAL ;
    PORT
      LAYER M5 ;
        RECT  208.656 0 208.68 0.084 ;
    END
  END rs_o[215]
  PIN rs_o[216]
    DIRECTION OUTPUT ;
    USE SIGNAL ;
    PORT
      LAYER M5 ;
        RECT  208.848 0 208.872 0.084 ;
    END
  END rs_o[216]
  PIN rs_o[217]
    DIRECTION OUTPUT ;
    USE SIGNAL ;
    PORT
      LAYER M5 ;
        RECT  209.04 0 209.064 0.084 ;
    END
  END rs_o[217]
  PIN rs_o[218]
    DIRECTION OUTPUT ;
    USE SIGNAL ;
    PORT
      LAYER M5 ;
        RECT  209.232 0 209.256 0.084 ;
    END
  END rs_o[218]
  PIN rs_o[219]
    DIRECTION OUTPUT ;
    USE SIGNAL ;
    PORT
      LAYER M5 ;
        RECT  209.424 0 209.448 0.084 ;
    END
  END rs_o[219]
  PIN rs_o[21]
    DIRECTION OUTPUT ;
    USE SIGNAL ;
    PORT
      LAYER M5 ;
        RECT  137.616 0 137.64 0.084 ;
    END
  END rs_o[21]
  PIN rs_o[220]
    DIRECTION OUTPUT ;
    USE SIGNAL ;
    PORT
      LAYER M5 ;
        RECT  209.616 0 209.64 0.084 ;
    END
  END rs_o[220]
  PIN rs_o[221]
    DIRECTION OUTPUT ;
    USE SIGNAL ;
    PORT
      LAYER M5 ;
        RECT  209.808 0 209.832 0.084 ;
    END
  END rs_o[221]
  PIN rs_o[222]
    DIRECTION OUTPUT ;
    USE SIGNAL ;
    PORT
      LAYER M5 ;
        RECT  210 0 210.024 0.084 ;
    END
  END rs_o[222]
  PIN rs_o[223]
    DIRECTION OUTPUT ;
    USE SIGNAL ;
    PORT
      LAYER M5 ;
        RECT  210.192 0 210.216 0.084 ;
    END
  END rs_o[223]
  PIN rs_o[224]
    DIRECTION OUTPUT ;
    USE SIGNAL ;
    PORT
      LAYER M5 ;
        RECT  210.384 0 210.408 0.084 ;
    END
  END rs_o[224]
  PIN rs_o[225]
    DIRECTION OUTPUT ;
    USE SIGNAL ;
    PORT
      LAYER M5 ;
        RECT  210.576 0 210.6 0.084 ;
    END
  END rs_o[225]
  PIN rs_o[226]
    DIRECTION OUTPUT ;
    USE SIGNAL ;
    PORT
      LAYER M5 ;
        RECT  210.768 0 210.792 0.084 ;
    END
  END rs_o[226]
  PIN rs_o[227]
    DIRECTION OUTPUT ;
    USE SIGNAL ;
    PORT
      LAYER M5 ;
        RECT  210.96 0 210.984 0.084 ;
    END
  END rs_o[227]
  PIN rs_o[228]
    DIRECTION OUTPUT ;
    USE SIGNAL ;
    PORT
      LAYER M5 ;
        RECT  217.296 0 217.32 0.084 ;
    END
  END rs_o[228]
  PIN rs_o[229]
    DIRECTION OUTPUT ;
    USE SIGNAL ;
    PORT
      LAYER M5 ;
        RECT  217.488 0 217.512 0.084 ;
    END
  END rs_o[229]
  PIN rs_o[22]
    DIRECTION OUTPUT ;
    USE SIGNAL ;
    PORT
      LAYER M5 ;
        RECT  137.808 0 137.832 0.084 ;
    END
  END rs_o[22]
  PIN rs_o[230]
    DIRECTION OUTPUT ;
    USE SIGNAL ;
    PORT
      LAYER M5 ;
        RECT  217.68 0 217.704 0.084 ;
    END
  END rs_o[230]
  PIN rs_o[231]
    DIRECTION OUTPUT ;
    USE SIGNAL ;
    PORT
      LAYER M5 ;
        RECT  217.872 0 217.896 0.084 ;
    END
  END rs_o[231]
  PIN rs_o[232]
    DIRECTION OUTPUT ;
    USE SIGNAL ;
    PORT
      LAYER M5 ;
        RECT  218.064 0 218.088 0.084 ;
    END
  END rs_o[232]
  PIN rs_o[233]
    DIRECTION OUTPUT ;
    USE SIGNAL ;
    PORT
      LAYER M5 ;
        RECT  218.256 0 218.28 0.084 ;
    END
  END rs_o[233]
  PIN rs_o[234]
    DIRECTION OUTPUT ;
    USE SIGNAL ;
    PORT
      LAYER M5 ;
        RECT  218.448 0 218.472 0.084 ;
    END
  END rs_o[234]
  PIN rs_o[235]
    DIRECTION OUTPUT ;
    USE SIGNAL ;
    PORT
      LAYER M5 ;
        RECT  218.64 0 218.664 0.084 ;
    END
  END rs_o[235]
  PIN rs_o[236]
    DIRECTION OUTPUT ;
    USE SIGNAL ;
    PORT
      LAYER M5 ;
        RECT  218.832 0 218.856 0.084 ;
    END
  END rs_o[236]
  PIN rs_o[237]
    DIRECTION OUTPUT ;
    USE SIGNAL ;
    PORT
      LAYER M5 ;
        RECT  219.024 0 219.048 0.084 ;
    END
  END rs_o[237]
  PIN rs_o[238]
    DIRECTION OUTPUT ;
    USE SIGNAL ;
    PORT
      LAYER M5 ;
        RECT  219.216 0 219.24 0.084 ;
    END
  END rs_o[238]
  PIN rs_o[239]
    DIRECTION OUTPUT ;
    USE SIGNAL ;
    PORT
      LAYER M5 ;
        RECT  219.408 0 219.432 0.084 ;
    END
  END rs_o[239]
  PIN rs_o[23]
    DIRECTION OUTPUT ;
    USE SIGNAL ;
    PORT
      LAYER M5 ;
        RECT  138 0 138.024 0.084 ;
    END
  END rs_o[23]
  PIN rs_o[240]
    DIRECTION OUTPUT ;
    USE SIGNAL ;
    PORT
      LAYER M5 ;
        RECT  219.6 0 219.624 0.084 ;
    END
  END rs_o[240]
  PIN rs_o[241]
    DIRECTION OUTPUT ;
    USE SIGNAL ;
    PORT
      LAYER M5 ;
        RECT  219.792 0 219.816 0.084 ;
    END
  END rs_o[241]
  PIN rs_o[242]
    DIRECTION OUTPUT ;
    USE SIGNAL ;
    PORT
      LAYER M5 ;
        RECT  219.984 0 220.008 0.084 ;
    END
  END rs_o[242]
  PIN rs_o[243]
    DIRECTION OUTPUT ;
    USE SIGNAL ;
    PORT
      LAYER M5 ;
        RECT  220.176 0 220.2 0.084 ;
    END
  END rs_o[243]
  PIN rs_o[244]
    DIRECTION OUTPUT ;
    USE SIGNAL ;
    PORT
      LAYER M5 ;
        RECT  220.368 0 220.392 0.084 ;
    END
  END rs_o[244]
  PIN rs_o[245]
    DIRECTION OUTPUT ;
    USE SIGNAL ;
    PORT
      LAYER M5 ;
        RECT  220.56 0 220.584 0.084 ;
    END
  END rs_o[245]
  PIN rs_o[246]
    DIRECTION OUTPUT ;
    USE SIGNAL ;
    PORT
      LAYER M5 ;
        RECT  220.752 0 220.776 0.084 ;
    END
  END rs_o[246]
  PIN rs_o[247]
    DIRECTION OUTPUT ;
    USE SIGNAL ;
    PORT
      LAYER M5 ;
        RECT  220.944 0 220.968 0.084 ;
    END
  END rs_o[247]
  PIN rs_o[248]
    DIRECTION OUTPUT ;
    USE SIGNAL ;
    PORT
      LAYER M5 ;
        RECT  221.136 0 221.16 0.084 ;
    END
  END rs_o[248]
  PIN rs_o[249]
    DIRECTION OUTPUT ;
    USE SIGNAL ;
    PORT
      LAYER M5 ;
        RECT  221.328 0 221.352 0.084 ;
    END
  END rs_o[249]
  PIN rs_o[24]
    DIRECTION OUTPUT ;
    USE SIGNAL ;
    PORT
      LAYER M5 ;
        RECT  138.192 0 138.216 0.084 ;
    END
  END rs_o[24]
  PIN rs_o[250]
    DIRECTION OUTPUT ;
    USE SIGNAL ;
    PORT
      LAYER M5 ;
        RECT  221.52 0 221.544 0.084 ;
    END
  END rs_o[250]
  PIN rs_o[251]
    DIRECTION OUTPUT ;
    USE SIGNAL ;
    PORT
      LAYER M5 ;
        RECT  221.712 0 221.736 0.084 ;
    END
  END rs_o[251]
  PIN rs_o[252]
    DIRECTION OUTPUT ;
    USE SIGNAL ;
    PORT
      LAYER M5 ;
        RECT  221.904 0 221.928 0.084 ;
    END
  END rs_o[252]
  PIN rs_o[253]
    DIRECTION OUTPUT ;
    USE SIGNAL ;
    PORT
      LAYER M5 ;
        RECT  222.096 0 222.12 0.084 ;
    END
  END rs_o[253]
  PIN rs_o[254]
    DIRECTION OUTPUT ;
    USE SIGNAL ;
    PORT
      LAYER M5 ;
        RECT  222.288 0 222.312 0.084 ;
    END
  END rs_o[254]
  PIN rs_o[255]
    DIRECTION OUTPUT ;
    USE SIGNAL ;
    PORT
      LAYER M5 ;
        RECT  222.48 0 222.504 0.084 ;
    END
  END rs_o[255]
  PIN rs_o[256]
    DIRECTION OUTPUT ;
    USE SIGNAL ;
    PORT
      LAYER M5 ;
        RECT  222.672 0 222.696 0.084 ;
    END
  END rs_o[256]
  PIN rs_o[257]
    DIRECTION OUTPUT ;
    USE SIGNAL ;
    PORT
      LAYER M5 ;
        RECT  222.864 0 222.888 0.084 ;
    END
  END rs_o[257]
  PIN rs_o[258]
    DIRECTION OUTPUT ;
    USE SIGNAL ;
    PORT
      LAYER M5 ;
        RECT  223.056 0 223.08 0.084 ;
    END
  END rs_o[258]
  PIN rs_o[259]
    DIRECTION OUTPUT ;
    USE SIGNAL ;
    PORT
      LAYER M5 ;
        RECT  223.248 0 223.272 0.084 ;
    END
  END rs_o[259]
  PIN rs_o[25]
    DIRECTION OUTPUT ;
    USE SIGNAL ;
    PORT
      LAYER M5 ;
        RECT  138.384 0 138.408 0.084 ;
    END
  END rs_o[25]
  PIN rs_o[260]
    DIRECTION OUTPUT ;
    USE SIGNAL ;
    PORT
      LAYER M5 ;
        RECT  192.72 0 192.744 0.084 ;
    END
  END rs_o[260]
  PIN rs_o[261]
    DIRECTION OUTPUT ;
    USE SIGNAL ;
    PORT
      LAYER M5 ;
        RECT  192.912 0 192.936 0.084 ;
    END
  END rs_o[261]
  PIN rs_o[262]
    DIRECTION OUTPUT ;
    USE SIGNAL ;
    PORT
      LAYER M5 ;
        RECT  193.104 0 193.128 0.084 ;
    END
  END rs_o[262]
  PIN rs_o[263]
    DIRECTION OUTPUT ;
    USE SIGNAL ;
    PORT
      LAYER M5 ;
        RECT  193.296 0 193.32 0.084 ;
    END
  END rs_o[263]
  PIN rs_o[264]
    DIRECTION OUTPUT ;
    USE SIGNAL ;
    PORT
      LAYER M5 ;
        RECT  193.488 0 193.512 0.084 ;
    END
  END rs_o[264]
  PIN rs_o[265]
    DIRECTION OUTPUT ;
    USE SIGNAL ;
    PORT
      LAYER M5 ;
        RECT  193.68 0 193.704 0.084 ;
    END
  END rs_o[265]
  PIN rs_o[266]
    DIRECTION OUTPUT ;
    USE SIGNAL ;
    PORT
      LAYER M5 ;
        RECT  193.872 0 193.896 0.084 ;
    END
  END rs_o[266]
  PIN rs_o[267]
    DIRECTION OUTPUT ;
    USE SIGNAL ;
    PORT
      LAYER M5 ;
        RECT  194.064 0 194.088 0.084 ;
    END
  END rs_o[267]
  PIN rs_o[268]
    DIRECTION OUTPUT ;
    USE SIGNAL ;
    PORT
      LAYER M5 ;
        RECT  194.256 0 194.28 0.084 ;
    END
  END rs_o[268]
  PIN rs_o[269]
    DIRECTION OUTPUT ;
    USE SIGNAL ;
    PORT
      LAYER M5 ;
        RECT  194.448 0 194.472 0.084 ;
    END
  END rs_o[269]
  PIN rs_o[26]
    DIRECTION OUTPUT ;
    USE SIGNAL ;
    PORT
      LAYER M5 ;
        RECT  138.576 0 138.6 0.084 ;
    END
  END rs_o[26]
  PIN rs_o[270]
    DIRECTION OUTPUT ;
    USE SIGNAL ;
    PORT
      LAYER M5 ;
        RECT  194.64 0 194.664 0.084 ;
    END
  END rs_o[270]
  PIN rs_o[271]
    DIRECTION OUTPUT ;
    USE SIGNAL ;
    PORT
      LAYER M5 ;
        RECT  194.832 0 194.856 0.084 ;
    END
  END rs_o[271]
  PIN rs_o[272]
    DIRECTION OUTPUT ;
    USE SIGNAL ;
    PORT
      LAYER M5 ;
        RECT  195.024 0 195.048 0.084 ;
    END
  END rs_o[272]
  PIN rs_o[273]
    DIRECTION OUTPUT ;
    USE SIGNAL ;
    PORT
      LAYER M5 ;
        RECT  195.216 0 195.24 0.084 ;
    END
  END rs_o[273]
  PIN rs_o[274]
    DIRECTION OUTPUT ;
    USE SIGNAL ;
    PORT
      LAYER M5 ;
        RECT  195.408 0 195.432 0.084 ;
    END
  END rs_o[274]
  PIN rs_o[275]
    DIRECTION OUTPUT ;
    USE SIGNAL ;
    PORT
      LAYER M5 ;
        RECT  195.6 0 195.624 0.084 ;
    END
  END rs_o[275]
  PIN rs_o[27]
    DIRECTION OUTPUT ;
    USE SIGNAL ;
    PORT
      LAYER M5 ;
        RECT  138.768 0 138.792 0.084 ;
    END
  END rs_o[27]
  PIN rs_o[28]
    DIRECTION OUTPUT ;
    USE SIGNAL ;
    PORT
      LAYER M5 ;
        RECT  138.96 0 138.984 0.084 ;
    END
  END rs_o[28]
  PIN rs_o[29]
    DIRECTION OUTPUT ;
    USE SIGNAL ;
    PORT
      LAYER M5 ;
        RECT  139.152 0 139.176 0.084 ;
    END
  END rs_o[29]
  PIN rs_o[2]
    DIRECTION OUTPUT ;
    USE SIGNAL ;
    PORT
      LAYER M5 ;
        RECT  127.824 0 127.848 0.084 ;
    END
  END rs_o[2]
  PIN rs_o[30]
    DIRECTION OUTPUT ;
    USE SIGNAL ;
    PORT
      LAYER M5 ;
        RECT  139.344 0 139.368 0.084 ;
    END
  END rs_o[30]
  PIN rs_o[31]
    DIRECTION OUTPUT ;
    USE SIGNAL ;
    PORT
      LAYER M5 ;
        RECT  139.536 0 139.56 0.084 ;
    END
  END rs_o[31]
  PIN rs_o[32]
    DIRECTION OUTPUT ;
    USE SIGNAL ;
    PORT
      LAYER M5 ;
        RECT  139.728 0 139.752 0.084 ;
    END
  END rs_o[32]
  PIN rs_o[33]
    DIRECTION OUTPUT ;
    USE SIGNAL ;
    PORT
      LAYER M5 ;
        RECT  139.92 0 139.944 0.084 ;
    END
  END rs_o[33]
  PIN rs_o[34]
    DIRECTION OUTPUT ;
    USE SIGNAL ;
    PORT
      LAYER M5 ;
        RECT  140.112 0 140.136 0.084 ;
    END
  END rs_o[34]
  PIN rs_o[35]
    DIRECTION OUTPUT ;
    USE SIGNAL ;
    PORT
      LAYER M5 ;
        RECT  140.304 0 140.328 0.084 ;
    END
  END rs_o[35]
  PIN rs_o[36]
    DIRECTION OUTPUT ;
    USE SIGNAL ;
    PORT
      LAYER M5 ;
        RECT  160.464 0 160.488 0.084 ;
    END
  END rs_o[36]
  PIN rs_o[37]
    DIRECTION OUTPUT ;
    USE SIGNAL ;
    PORT
      LAYER M5 ;
        RECT  160.656 0 160.68 0.084 ;
    END
  END rs_o[37]
  PIN rs_o[38]
    DIRECTION OUTPUT ;
    USE SIGNAL ;
    PORT
      LAYER M5 ;
        RECT  160.848 0 160.872 0.084 ;
    END
  END rs_o[38]
  PIN rs_o[39]
    DIRECTION OUTPUT ;
    USE SIGNAL ;
    PORT
      LAYER M5 ;
        RECT  161.04 0 161.064 0.084 ;
    END
  END rs_o[39]
  PIN rs_o[3]
    DIRECTION OUTPUT ;
    USE SIGNAL ;
    PORT
      LAYER M5 ;
        RECT  128.016 0 128.04 0.084 ;
    END
  END rs_o[3]
  PIN rs_o[40]
    DIRECTION OUTPUT ;
    USE SIGNAL ;
    PORT
      LAYER M5 ;
        RECT  161.232 0 161.256 0.084 ;
    END
  END rs_o[40]
  PIN rs_o[41]
    DIRECTION OUTPUT ;
    USE SIGNAL ;
    PORT
      LAYER M5 ;
        RECT  161.424 0 161.448 0.084 ;
    END
  END rs_o[41]
  PIN rs_o[42]
    DIRECTION OUTPUT ;
    USE SIGNAL ;
    PORT
      LAYER M5 ;
        RECT  161.616 0 161.64 0.084 ;
    END
  END rs_o[42]
  PIN rs_o[43]
    DIRECTION OUTPUT ;
    USE SIGNAL ;
    PORT
      LAYER M5 ;
        RECT  161.808 0 161.832 0.084 ;
    END
  END rs_o[43]
  PIN rs_o[44]
    DIRECTION OUTPUT ;
    USE SIGNAL ;
    PORT
      LAYER M5 ;
        RECT  162 0 162.024 0.084 ;
    END
  END rs_o[44]
  PIN rs_o[45]
    DIRECTION OUTPUT ;
    USE SIGNAL ;
    PORT
      LAYER M5 ;
        RECT  162.192 0 162.216 0.084 ;
    END
  END rs_o[45]
  PIN rs_o[46]
    DIRECTION OUTPUT ;
    USE SIGNAL ;
    PORT
      LAYER M5 ;
        RECT  162.384 0 162.408 0.084 ;
    END
  END rs_o[46]
  PIN rs_o[47]
    DIRECTION OUTPUT ;
    USE SIGNAL ;
    PORT
      LAYER M5 ;
        RECT  162.576 0 162.6 0.084 ;
    END
  END rs_o[47]
  PIN rs_o[48]
    DIRECTION OUTPUT ;
    USE SIGNAL ;
    PORT
      LAYER M5 ;
        RECT  162.768 0 162.792 0.084 ;
    END
  END rs_o[48]
  PIN rs_o[49]
    DIRECTION OUTPUT ;
    USE SIGNAL ;
    PORT
      LAYER M5 ;
        RECT  162.96 0 162.984 0.084 ;
    END
  END rs_o[49]
  PIN rs_o[4]
    DIRECTION OUTPUT ;
    USE SIGNAL ;
    PORT
      LAYER M5 ;
        RECT  134.352 0 134.376 0.084 ;
    END
  END rs_o[4]
  PIN rs_o[50]
    DIRECTION OUTPUT ;
    USE SIGNAL ;
    PORT
      LAYER M5 ;
        RECT  163.152 0 163.176 0.084 ;
    END
  END rs_o[50]
  PIN rs_o[51]
    DIRECTION OUTPUT ;
    USE SIGNAL ;
    PORT
      LAYER M5 ;
        RECT  163.344 0 163.368 0.084 ;
    END
  END rs_o[51]
  PIN rs_o[52]
    DIRECTION OUTPUT ;
    USE SIGNAL ;
    PORT
      LAYER M5 ;
        RECT  163.536 0 163.56 0.084 ;
    END
  END rs_o[52]
  PIN rs_o[53]
    DIRECTION OUTPUT ;
    USE SIGNAL ;
    PORT
      LAYER M5 ;
        RECT  163.728 0 163.752 0.084 ;
    END
  END rs_o[53]
  PIN rs_o[54]
    DIRECTION OUTPUT ;
    USE SIGNAL ;
    PORT
      LAYER M5 ;
        RECT  163.92 0 163.944 0.084 ;
    END
  END rs_o[54]
  PIN rs_o[55]
    DIRECTION OUTPUT ;
    USE SIGNAL ;
    PORT
      LAYER M5 ;
        RECT  164.112 0 164.136 0.084 ;
    END
  END rs_o[55]
  PIN rs_o[56]
    DIRECTION OUTPUT ;
    USE SIGNAL ;
    PORT
      LAYER M5 ;
        RECT  164.304 0 164.328 0.084 ;
    END
  END rs_o[56]
  PIN rs_o[57]
    DIRECTION OUTPUT ;
    USE SIGNAL ;
    PORT
      LAYER M5 ;
        RECT  164.496 0 164.52 0.084 ;
    END
  END rs_o[57]
  PIN rs_o[58]
    DIRECTION OUTPUT ;
    USE SIGNAL ;
    PORT
      LAYER M5 ;
        RECT  164.688 0 164.712 0.084 ;
    END
  END rs_o[58]
  PIN rs_o[59]
    DIRECTION OUTPUT ;
    USE SIGNAL ;
    PORT
      LAYER M5 ;
        RECT  164.88 0 164.904 0.084 ;
    END
  END rs_o[59]
  PIN rs_o[5]
    DIRECTION OUTPUT ;
    USE SIGNAL ;
    PORT
      LAYER M5 ;
        RECT  134.544 0 134.568 0.084 ;
    END
  END rs_o[5]
  PIN rs_o[60]
    DIRECTION OUTPUT ;
    USE SIGNAL ;
    PORT
      LAYER M5 ;
        RECT  165.072 0 165.096 0.084 ;
    END
  END rs_o[60]
  PIN rs_o[61]
    DIRECTION OUTPUT ;
    USE SIGNAL ;
    PORT
      LAYER M5 ;
        RECT  165.264 0 165.288 0.084 ;
    END
  END rs_o[61]
  PIN rs_o[62]
    DIRECTION OUTPUT ;
    USE SIGNAL ;
    PORT
      LAYER M5 ;
        RECT  165.456 0 165.48 0.084 ;
    END
  END rs_o[62]
  PIN rs_o[63]
    DIRECTION OUTPUT ;
    USE SIGNAL ;
    PORT
      LAYER M5 ;
        RECT  165.648 0 165.672 0.084 ;
    END
  END rs_o[63]
  PIN rs_o[64]
    DIRECTION OUTPUT ;
    USE SIGNAL ;
    PORT
      LAYER M5 ;
        RECT  165.84 0 165.864 0.084 ;
    END
  END rs_o[64]
  PIN rs_o[65]
    DIRECTION OUTPUT ;
    USE SIGNAL ;
    PORT
      LAYER M5 ;
        RECT  166.032 0 166.056 0.084 ;
    END
  END rs_o[65]
  PIN rs_o[66]
    DIRECTION OUTPUT ;
    USE SIGNAL ;
    PORT
      LAYER M5 ;
        RECT  166.224 0 166.248 0.084 ;
    END
  END rs_o[66]
  PIN rs_o[67]
    DIRECTION OUTPUT ;
    USE SIGNAL ;
    PORT
      LAYER M5 ;
        RECT  166.416 0 166.44 0.084 ;
    END
  END rs_o[67]
  PIN rs_o[68]
    DIRECTION OUTPUT ;
    USE SIGNAL ;
    PORT
      LAYER M5 ;
        RECT  154.32 0 154.344 0.084 ;
    END
  END rs_o[68]
  PIN rs_o[69]
    DIRECTION OUTPUT ;
    USE SIGNAL ;
    PORT
      LAYER M5 ;
        RECT  154.512 0 154.536 0.084 ;
    END
  END rs_o[69]
  PIN rs_o[6]
    DIRECTION OUTPUT ;
    USE SIGNAL ;
    PORT
      LAYER M5 ;
        RECT  134.736 0 134.76 0.084 ;
    END
  END rs_o[6]
  PIN rs_o[70]
    DIRECTION OUTPUT ;
    USE SIGNAL ;
    PORT
      LAYER M5 ;
        RECT  154.704 0 154.728 0.084 ;
    END
  END rs_o[70]
  PIN rs_o[71]
    DIRECTION OUTPUT ;
    USE SIGNAL ;
    PORT
      LAYER M5 ;
        RECT  154.896 0 154.92 0.084 ;
    END
  END rs_o[71]
  PIN rs_o[72]
    DIRECTION OUTPUT ;
    USE SIGNAL ;
    PORT
      LAYER M5 ;
        RECT  155.088 0 155.112 0.084 ;
    END
  END rs_o[72]
  PIN rs_o[73]
    DIRECTION OUTPUT ;
    USE SIGNAL ;
    PORT
      LAYER M5 ;
        RECT  155.28 0 155.304 0.084 ;
    END
  END rs_o[73]
  PIN rs_o[74]
    DIRECTION OUTPUT ;
    USE SIGNAL ;
    PORT
      LAYER M5 ;
        RECT  155.472 0 155.496 0.084 ;
    END
  END rs_o[74]
  PIN rs_o[75]
    DIRECTION OUTPUT ;
    USE SIGNAL ;
    PORT
      LAYER M5 ;
        RECT  155.664 0 155.688 0.084 ;
    END
  END rs_o[75]
  PIN rs_o[76]
    DIRECTION OUTPUT ;
    USE SIGNAL ;
    PORT
      LAYER M5 ;
        RECT  155.856 0 155.88 0.084 ;
    END
  END rs_o[76]
  PIN rs_o[77]
    DIRECTION OUTPUT ;
    USE SIGNAL ;
    PORT
      LAYER M5 ;
        RECT  156.048 0 156.072 0.084 ;
    END
  END rs_o[77]
  PIN rs_o[78]
    DIRECTION OUTPUT ;
    USE SIGNAL ;
    PORT
      LAYER M5 ;
        RECT  156.24 0 156.264 0.084 ;
    END
  END rs_o[78]
  PIN rs_o[79]
    DIRECTION OUTPUT ;
    USE SIGNAL ;
    PORT
      LAYER M5 ;
        RECT  156.432 0 156.456 0.084 ;
    END
  END rs_o[79]
  PIN rs_o[7]
    DIRECTION OUTPUT ;
    USE SIGNAL ;
    PORT
      LAYER M5 ;
        RECT  134.928 0 134.952 0.084 ;
    END
  END rs_o[7]
  PIN rs_o[80]
    DIRECTION OUTPUT ;
    USE SIGNAL ;
    PORT
      LAYER M5 ;
        RECT  156.624 0 156.648 0.084 ;
    END
  END rs_o[80]
  PIN rs_o[81]
    DIRECTION OUTPUT ;
    USE SIGNAL ;
    PORT
      LAYER M5 ;
        RECT  156.816 0 156.84 0.084 ;
    END
  END rs_o[81]
  PIN rs_o[82]
    DIRECTION OUTPUT ;
    USE SIGNAL ;
    PORT
      LAYER M5 ;
        RECT  157.008 0 157.032 0.084 ;
    END
  END rs_o[82]
  PIN rs_o[83]
    DIRECTION OUTPUT ;
    USE SIGNAL ;
    PORT
      LAYER M5 ;
        RECT  157.2 0 157.224 0.084 ;
    END
  END rs_o[83]
  PIN rs_o[84]
    DIRECTION OUTPUT ;
    USE SIGNAL ;
    PORT
      LAYER M5 ;
        RECT  157.392 0 157.416 0.084 ;
    END
  END rs_o[84]
  PIN rs_o[85]
    DIRECTION OUTPUT ;
    USE SIGNAL ;
    PORT
      LAYER M5 ;
        RECT  157.584 0 157.608 0.084 ;
    END
  END rs_o[85]
  PIN rs_o[86]
    DIRECTION OUTPUT ;
    USE SIGNAL ;
    PORT
      LAYER M5 ;
        RECT  157.776 0 157.8 0.084 ;
    END
  END rs_o[86]
  PIN rs_o[87]
    DIRECTION OUTPUT ;
    USE SIGNAL ;
    PORT
      LAYER M5 ;
        RECT  157.968 0 157.992 0.084 ;
    END
  END rs_o[87]
  PIN rs_o[88]
    DIRECTION OUTPUT ;
    USE SIGNAL ;
    PORT
      LAYER M5 ;
        RECT  158.16 0 158.184 0.084 ;
    END
  END rs_o[88]
  PIN rs_o[89]
    DIRECTION OUTPUT ;
    USE SIGNAL ;
    PORT
      LAYER M5 ;
        RECT  158.352 0 158.376 0.084 ;
    END
  END rs_o[89]
  PIN rs_o[8]
    DIRECTION OUTPUT ;
    USE SIGNAL ;
    PORT
      LAYER M5 ;
        RECT  135.12 0 135.144 0.084 ;
    END
  END rs_o[8]
  PIN rs_o[90]
    DIRECTION OUTPUT ;
    USE SIGNAL ;
    PORT
      LAYER M5 ;
        RECT  158.544 0 158.568 0.084 ;
    END
  END rs_o[90]
  PIN rs_o[91]
    DIRECTION OUTPUT ;
    USE SIGNAL ;
    PORT
      LAYER M5 ;
        RECT  158.736 0 158.76 0.084 ;
    END
  END rs_o[91]
  PIN rs_o[92]
    DIRECTION OUTPUT ;
    USE SIGNAL ;
    PORT
      LAYER M5 ;
        RECT  158.928 0 158.952 0.084 ;
    END
  END rs_o[92]
  PIN rs_o[93]
    DIRECTION OUTPUT ;
    USE SIGNAL ;
    PORT
      LAYER M5 ;
        RECT  159.12 0 159.144 0.084 ;
    END
  END rs_o[93]
  PIN rs_o[94]
    DIRECTION OUTPUT ;
    USE SIGNAL ;
    PORT
      LAYER M5 ;
        RECT  159.312 0 159.336 0.084 ;
    END
  END rs_o[94]
  PIN rs_o[95]
    DIRECTION OUTPUT ;
    USE SIGNAL ;
    PORT
      LAYER M5 ;
        RECT  159.504 0 159.528 0.084 ;
    END
  END rs_o[95]
  PIN rs_o[96]
    DIRECTION OUTPUT ;
    USE SIGNAL ;
    PORT
      LAYER M5 ;
        RECT  159.696 0 159.72 0.084 ;
    END
  END rs_o[96]
  PIN rs_o[97]
    DIRECTION OUTPUT ;
    USE SIGNAL ;
    PORT
      LAYER M5 ;
        RECT  159.888 0 159.912 0.084 ;
    END
  END rs_o[97]
  PIN rs_o[98]
    DIRECTION OUTPUT ;
    USE SIGNAL ;
    PORT
      LAYER M5 ;
        RECT  160.08 0 160.104 0.084 ;
    END
  END rs_o[98]
  PIN rs_o[99]
    DIRECTION OUTPUT ;
    USE SIGNAL ;
    PORT
      LAYER M5 ;
        RECT  160.272 0 160.296 0.084 ;
    END
  END rs_o[99]
  PIN rs_o[9]
    DIRECTION OUTPUT ;
    USE SIGNAL ;
    PORT
      LAYER M5 ;
        RECT  135.312 0 135.336 0.084 ;
    END
  END rs_o[9]
  PIN rst_n
    DIRECTION INPUT ;
    USE SIGNAL ;
    PORT
      LAYER M4 ;
        RECT  0 117.648 0.084 117.672 ;
    END
  END rst_n
  PIN sid_i[0]
    DIRECTION INPUT ;
    USE SIGNAL ;
    PORT
      LAYER M5 ;
        RECT  195.792 0 195.816 0.084 ;
    END
  END sid_i[0]
  PIN sid_i[1]
    DIRECTION INPUT ;
    USE SIGNAL ;
    PORT
      LAYER M5 ;
        RECT  195.984 0 196.008 0.084 ;
    END
  END sid_i[1]
  PIN sid_i[2]
    DIRECTION INPUT ;
    USE SIGNAL ;
    PORT
      LAYER M5 ;
        RECT  196.176 0 196.2 0.084 ;
    END
  END sid_i[2]
  PIN sid_i[3]
    DIRECTION INPUT ;
    USE SIGNAL ;
    PORT
      LAYER M5 ;
        RECT  196.368 0 196.392 0.084 ;
    END
  END sid_i[3]
  PIN t_lm[0]
    DIRECTION INPUT ;
    USE SIGNAL ;
    PORT
      LAYER M5 ;
        RECT  196.56 0 196.584 0.084 ;
    END
  END t_lm[0]
  PIN t_lm[1]
    DIRECTION INPUT ;
    USE SIGNAL ;
    PORT
      LAYER M5 ;
        RECT  196.752 0 196.776 0.084 ;
    END
  END t_lm[1]
  PIN t_lm[2]
    DIRECTION INPUT ;
    USE SIGNAL ;
    PORT
      LAYER M5 ;
        RECT  196.944 0 196.968 0.084 ;
    END
  END t_lm[2]
  PIN t_lm[3]
    DIRECTION INPUT ;
    USE SIGNAL ;
    PORT
      LAYER M5 ;
        RECT  197.136 0 197.16 0.084 ;
    END
  END t_lm[3]
  PIN t_lm[4]
    DIRECTION INPUT ;
    USE SIGNAL ;
    PORT
      LAYER M5 ;
        RECT  197.328 0 197.352 0.084 ;
    END
  END t_lm[4]
  PIN t_row[0]
    DIRECTION INPUT ;
    USE SIGNAL ;
    PORT
      LAYER M5 ;
        RECT  197.52 0 197.544 0.084 ;
    END
  END t_row[0]
  PIN t_row[1]
    DIRECTION INPUT ;
    USE SIGNAL ;
    PORT
      LAYER M5 ;
        RECT  197.712 0 197.736 0.084 ;
    END
  END t_row[1]
  PIN t_row[2]
    DIRECTION INPUT ;
    USE SIGNAL ;
    PORT
      LAYER M5 ;
        RECT  197.904 0 197.928 0.084 ;
    END
  END t_row[2]
  PIN t_row[3]
    DIRECTION INPUT ;
    USE SIGNAL ;
    PORT
      LAYER M5 ;
        RECT  198.096 0 198.12 0.084 ;
    END
  END t_row[3]
  PIN t_row[4]
    DIRECTION INPUT ;
    USE SIGNAL ;
    PORT
      LAYER M5 ;
        RECT  198.288 0 198.312 0.084 ;
    END
  END t_row[4]
  PIN t_row[5]
    DIRECTION INPUT ;
    USE SIGNAL ;
    PORT
      LAYER M5 ;
        RECT  198.48 0 198.504 0.084 ;
    END
  END t_row[5]
  PIN t_row[6]
    DIRECTION INPUT ;
    USE SIGNAL ;
    PORT
      LAYER M5 ;
        RECT  198.672 0 198.696 0.084 ;
    END
  END t_row[6]
  PIN t_row[7]
    DIRECTION INPUT ;
    USE SIGNAL ;
    PORT
      LAYER M5 ;
        RECT  231.12 0 231.144 0.084 ;
    END
  END t_row[7]
  PIN t_row[8]
    DIRECTION INPUT ;
    USE SIGNAL ;
    PORT
      LAYER M5 ;
        RECT  231.312 0 231.336 0.084 ;
    END
  END t_row[8]
  PIN t_row[9]
    DIRECTION INPUT ;
    USE SIGNAL ;
    PORT
      LAYER M5 ;
        RECT  231.504 0 231.528 0.084 ;
    END
  END t_row[9]
  PIN t_set
    DIRECTION INPUT ;
    USE SIGNAL ;
    PORT
      LAYER M5 ;
        RECT  231.696 0 231.72 0.084 ;
    END
  END t_set
  PIN t_sm[0]
    DIRECTION INPUT ;
    USE SIGNAL ;
    PORT
      LAYER M5 ;
        RECT  231.888 0 231.912 0.084 ;
    END
  END t_sm[0]
  PIN t_sm[10]
    DIRECTION INPUT ;
    USE SIGNAL ;
    PORT
      LAYER M5 ;
        RECT  233.808 0 233.832 0.084 ;
    END
  END t_sm[10]
  PIN t_sm[11]
    DIRECTION INPUT ;
    USE SIGNAL ;
    PORT
      LAYER M5 ;
        RECT  234 0 234.024 0.084 ;
    END
  END t_sm[11]
  PIN t_sm[12]
    DIRECTION INPUT ;
    USE SIGNAL ;
    PORT
      LAYER M5 ;
        RECT  234.192 0 234.216 0.084 ;
    END
  END t_sm[12]
  PIN t_sm[13]
    DIRECTION INPUT ;
    USE SIGNAL ;
    PORT
      LAYER M5 ;
        RECT  234.384 0 234.408 0.084 ;
    END
  END t_sm[13]
  PIN t_sm[14]
    DIRECTION INPUT ;
    USE SIGNAL ;
    PORT
      LAYER M5 ;
        RECT  234.576 0 234.6 0.084 ;
    END
  END t_sm[14]
  PIN t_sm[15]
    DIRECTION INPUT ;
    USE SIGNAL ;
    PORT
      LAYER M5 ;
        RECT  234.768 0 234.792 0.084 ;
    END
  END t_sm[15]
  PIN t_sm[1]
    DIRECTION INPUT ;
    USE SIGNAL ;
    PORT
      LAYER M5 ;
        RECT  232.08 0 232.104 0.084 ;
    END
  END t_sm[1]
  PIN t_sm[2]
    DIRECTION INPUT ;
    USE SIGNAL ;
    PORT
      LAYER M5 ;
        RECT  232.272 0 232.296 0.084 ;
    END
  END t_sm[2]
  PIN t_sm[3]
    DIRECTION INPUT ;
    USE SIGNAL ;
    PORT
      LAYER M5 ;
        RECT  232.464 0 232.488 0.084 ;
    END
  END t_sm[3]
  PIN t_sm[4]
    DIRECTION INPUT ;
    USE SIGNAL ;
    PORT
      LAYER M5 ;
        RECT  232.656 0 232.68 0.084 ;
    END
  END t_sm[4]
  PIN t_sm[5]
    DIRECTION INPUT ;
    USE SIGNAL ;
    PORT
      LAYER M5 ;
        RECT  232.848 0 232.872 0.084 ;
    END
  END t_sm[5]
  PIN t_sm[6]
    DIRECTION INPUT ;
    USE SIGNAL ;
    PORT
      LAYER M5 ;
        RECT  233.04 0 233.064 0.084 ;
    END
  END t_sm[6]
  PIN t_sm[7]
    DIRECTION INPUT ;
    USE SIGNAL ;
    PORT
      LAYER M5 ;
        RECT  233.232 0 233.256 0.084 ;
    END
  END t_sm[7]
  PIN t_sm[8]
    DIRECTION INPUT ;
    USE SIGNAL ;
    PORT
      LAYER M5 ;
        RECT  233.424 0 233.448 0.084 ;
    END
  END t_sm[8]
  PIN t_sm[9]
    DIRECTION INPUT ;
    USE SIGNAL ;
    PORT
      LAYER M5 ;
        RECT  233.616 0 233.64 0.084 ;
    END
  END t_sm[9]
  PIN t_w
    DIRECTION INPUT ;
    USE SIGNAL ;
    PORT
      LAYER M5 ;
        RECT  234.96 0 234.984 0.084 ;
    END
  END t_w
  PIN vi_n[0]
    DIRECTION INPUT ;
    USE SIGNAL ;
    PORT
      LAYER M5 ;
        RECT  25.488 302.316 25.512 302.4 ;
    END
  END vi_n[0]
  PIN vi_n[100]
    DIRECTION INPUT ;
    USE SIGNAL ;
    PORT
      LAYER M5 ;
        RECT  1.68 302.316 1.704 302.4 ;
    END
  END vi_n[100]
  PIN vi_n[101]
    DIRECTION INPUT ;
    USE SIGNAL ;
    PORT
      LAYER M5 ;
        RECT  1.872 302.316 1.896 302.4 ;
    END
  END vi_n[101]
  PIN vi_n[102]
    DIRECTION INPUT ;
    USE SIGNAL ;
    PORT
      LAYER M5 ;
        RECT  2.064 302.316 2.088 302.4 ;
    END
  END vi_n[102]
  PIN vi_n[103]
    DIRECTION INPUT ;
    USE SIGNAL ;
    PORT
      LAYER M5 ;
        RECT  2.256 302.316 2.28 302.4 ;
    END
  END vi_n[103]
  PIN vi_n[104]
    DIRECTION INPUT ;
    USE SIGNAL ;
    PORT
      LAYER M5 ;
        RECT  2.448 302.316 2.472 302.4 ;
    END
  END vi_n[104]
  PIN vi_n[105]
    DIRECTION INPUT ;
    USE SIGNAL ;
    PORT
      LAYER M5 ;
        RECT  2.64 302.316 2.664 302.4 ;
    END
  END vi_n[105]
  PIN vi_n[106]
    DIRECTION INPUT ;
    USE SIGNAL ;
    PORT
      LAYER M5 ;
        RECT  2.832 302.316 2.856 302.4 ;
    END
  END vi_n[106]
  PIN vi_n[107]
    DIRECTION INPUT ;
    USE SIGNAL ;
    PORT
      LAYER M5 ;
        RECT  3.024 302.316 3.048 302.4 ;
    END
  END vi_n[107]
  PIN vi_n[108]
    DIRECTION INPUT ;
    USE SIGNAL ;
    PORT
      LAYER M5 ;
        RECT  3.216 302.316 3.24 302.4 ;
    END
  END vi_n[108]
  PIN vi_n[109]
    DIRECTION INPUT ;
    USE SIGNAL ;
    PORT
      LAYER M5 ;
        RECT  3.408 302.316 3.432 302.4 ;
    END
  END vi_n[109]
  PIN vi_n[10]
    DIRECTION INPUT ;
    USE SIGNAL ;
    PORT
      LAYER M5 ;
        RECT  27.408 302.316 27.432 302.4 ;
    END
  END vi_n[10]
  PIN vi_n[110]
    DIRECTION INPUT ;
    USE SIGNAL ;
    PORT
      LAYER M5 ;
        RECT  3.6 302.316 3.624 302.4 ;
    END
  END vi_n[110]
  PIN vi_n[111]
    DIRECTION INPUT ;
    USE SIGNAL ;
    PORT
      LAYER M5 ;
        RECT  3.792 302.316 3.816 302.4 ;
    END
  END vi_n[111]
  PIN vi_n[112]
    DIRECTION INPUT ;
    USE SIGNAL ;
    PORT
      LAYER M5 ;
        RECT  3.984 302.316 4.008 302.4 ;
    END
  END vi_n[112]
  PIN vi_n[113]
    DIRECTION INPUT ;
    USE SIGNAL ;
    PORT
      LAYER M5 ;
        RECT  4.176 302.316 4.2 302.4 ;
    END
  END vi_n[113]
  PIN vi_n[114]
    DIRECTION INPUT ;
    USE SIGNAL ;
    PORT
      LAYER M5 ;
        RECT  4.368 302.316 4.392 302.4 ;
    END
  END vi_n[114]
  PIN vi_n[115]
    DIRECTION INPUT ;
    USE SIGNAL ;
    PORT
      LAYER M5 ;
        RECT  4.56 302.316 4.584 302.4 ;
    END
  END vi_n[115]
  PIN vi_n[116]
    DIRECTION INPUT ;
    USE SIGNAL ;
    PORT
      LAYER M5 ;
        RECT  4.752 302.316 4.776 302.4 ;
    END
  END vi_n[116]
  PIN vi_n[117]
    DIRECTION INPUT ;
    USE SIGNAL ;
    PORT
      LAYER M5 ;
        RECT  4.944 302.316 4.968 302.4 ;
    END
  END vi_n[117]
  PIN vi_n[118]
    DIRECTION INPUT ;
    USE SIGNAL ;
    PORT
      LAYER M5 ;
        RECT  5.136 302.316 5.16 302.4 ;
    END
  END vi_n[118]
  PIN vi_n[119]
    DIRECTION INPUT ;
    USE SIGNAL ;
    PORT
      LAYER M5 ;
        RECT  5.328 302.316 5.352 302.4 ;
    END
  END vi_n[119]
  PIN vi_n[11]
    DIRECTION INPUT ;
    USE SIGNAL ;
    PORT
      LAYER M5 ;
        RECT  27.6 302.316 27.624 302.4 ;
    END
  END vi_n[11]
  PIN vi_n[120]
    DIRECTION INPUT ;
    USE SIGNAL ;
    PORT
      LAYER M5 ;
        RECT  5.52 302.316 5.544 302.4 ;
    END
  END vi_n[120]
  PIN vi_n[121]
    DIRECTION INPUT ;
    USE SIGNAL ;
    PORT
      LAYER M5 ;
        RECT  5.712 302.316 5.736 302.4 ;
    END
  END vi_n[121]
  PIN vi_n[122]
    DIRECTION INPUT ;
    USE SIGNAL ;
    PORT
      LAYER M5 ;
        RECT  5.904 302.316 5.928 302.4 ;
    END
  END vi_n[122]
  PIN vi_n[123]
    DIRECTION INPUT ;
    USE SIGNAL ;
    PORT
      LAYER M5 ;
        RECT  6.096 302.316 6.12 302.4 ;
    END
  END vi_n[123]
  PIN vi_n[124]
    DIRECTION INPUT ;
    USE SIGNAL ;
    PORT
      LAYER M5 ;
        RECT  6.288 302.316 6.312 302.4 ;
    END
  END vi_n[124]
  PIN vi_n[125]
    DIRECTION INPUT ;
    USE SIGNAL ;
    PORT
      LAYER M5 ;
        RECT  6.48 302.316 6.504 302.4 ;
    END
  END vi_n[125]
  PIN vi_n[126]
    DIRECTION INPUT ;
    USE SIGNAL ;
    PORT
      LAYER M5 ;
        RECT  6.672 302.316 6.696 302.4 ;
    END
  END vi_n[126]
  PIN vi_n[127]
    DIRECTION INPUT ;
    USE SIGNAL ;
    PORT
      LAYER M5 ;
        RECT  6.864 302.316 6.888 302.4 ;
    END
  END vi_n[127]
  PIN vi_n[128]
    DIRECTION INPUT ;
    USE SIGNAL ;
    PORT
      LAYER M5 ;
        RECT  63.888 302.316 63.912 302.4 ;
    END
  END vi_n[128]
  PIN vi_n[129]
    DIRECTION INPUT ;
    USE SIGNAL ;
    PORT
      LAYER M5 ;
        RECT  64.08 302.316 64.104 302.4 ;
    END
  END vi_n[129]
  PIN vi_n[12]
    DIRECTION INPUT ;
    USE SIGNAL ;
    PORT
      LAYER M5 ;
        RECT  27.792 302.316 27.816 302.4 ;
    END
  END vi_n[12]
  PIN vi_n[130]
    DIRECTION INPUT ;
    USE SIGNAL ;
    PORT
      LAYER M5 ;
        RECT  64.272 302.316 64.296 302.4 ;
    END
  END vi_n[130]
  PIN vi_n[131]
    DIRECTION INPUT ;
    USE SIGNAL ;
    PORT
      LAYER M5 ;
        RECT  64.464 302.316 64.488 302.4 ;
    END
  END vi_n[131]
  PIN vi_n[132]
    DIRECTION INPUT ;
    USE SIGNAL ;
    PORT
      LAYER M5 ;
        RECT  64.656 302.316 64.68 302.4 ;
    END
  END vi_n[132]
  PIN vi_n[133]
    DIRECTION INPUT ;
    USE SIGNAL ;
    PORT
      LAYER M5 ;
        RECT  64.848 302.316 64.872 302.4 ;
    END
  END vi_n[133]
  PIN vi_n[134]
    DIRECTION INPUT ;
    USE SIGNAL ;
    PORT
      LAYER M5 ;
        RECT  65.04 302.316 65.064 302.4 ;
    END
  END vi_n[134]
  PIN vi_n[135]
    DIRECTION INPUT ;
    USE SIGNAL ;
    PORT
      LAYER M5 ;
        RECT  65.232 302.316 65.256 302.4 ;
    END
  END vi_n[135]
  PIN vi_n[136]
    DIRECTION INPUT ;
    USE SIGNAL ;
    PORT
      LAYER M5 ;
        RECT  65.424 302.316 65.448 302.4 ;
    END
  END vi_n[136]
  PIN vi_n[137]
    DIRECTION INPUT ;
    USE SIGNAL ;
    PORT
      LAYER M5 ;
        RECT  65.616 302.316 65.64 302.4 ;
    END
  END vi_n[137]
  PIN vi_n[138]
    DIRECTION INPUT ;
    USE SIGNAL ;
    PORT
      LAYER M5 ;
        RECT  65.808 302.316 65.832 302.4 ;
    END
  END vi_n[138]
  PIN vi_n[139]
    DIRECTION INPUT ;
    USE SIGNAL ;
    PORT
      LAYER M5 ;
        RECT  66 302.316 66.024 302.4 ;
    END
  END vi_n[139]
  PIN vi_n[13]
    DIRECTION INPUT ;
    USE SIGNAL ;
    PORT
      LAYER M5 ;
        RECT  27.984 302.316 28.008 302.4 ;
    END
  END vi_n[13]
  PIN vi_n[140]
    DIRECTION INPUT ;
    USE SIGNAL ;
    PORT
      LAYER M5 ;
        RECT  66.192 302.316 66.216 302.4 ;
    END
  END vi_n[140]
  PIN vi_n[141]
    DIRECTION INPUT ;
    USE SIGNAL ;
    PORT
      LAYER M5 ;
        RECT  66.384 302.316 66.408 302.4 ;
    END
  END vi_n[141]
  PIN vi_n[142]
    DIRECTION INPUT ;
    USE SIGNAL ;
    PORT
      LAYER M5 ;
        RECT  66.576 302.316 66.6 302.4 ;
    END
  END vi_n[142]
  PIN vi_n[143]
    DIRECTION INPUT ;
    USE SIGNAL ;
    PORT
      LAYER M5 ;
        RECT  66.768 302.316 66.792 302.4 ;
    END
  END vi_n[143]
  PIN vi_n[144]
    DIRECTION INPUT ;
    USE SIGNAL ;
    PORT
      LAYER M5 ;
        RECT  66.96 302.316 66.984 302.4 ;
    END
  END vi_n[144]
  PIN vi_n[145]
    DIRECTION INPUT ;
    USE SIGNAL ;
    PORT
      LAYER M5 ;
        RECT  67.152 302.316 67.176 302.4 ;
    END
  END vi_n[145]
  PIN vi_n[146]
    DIRECTION INPUT ;
    USE SIGNAL ;
    PORT
      LAYER M5 ;
        RECT  67.344 302.316 67.368 302.4 ;
    END
  END vi_n[146]
  PIN vi_n[147]
    DIRECTION INPUT ;
    USE SIGNAL ;
    PORT
      LAYER M5 ;
        RECT  67.536 302.316 67.56 302.4 ;
    END
  END vi_n[147]
  PIN vi_n[148]
    DIRECTION INPUT ;
    USE SIGNAL ;
    PORT
      LAYER M5 ;
        RECT  67.728 302.316 67.752 302.4 ;
    END
  END vi_n[148]
  PIN vi_n[149]
    DIRECTION INPUT ;
    USE SIGNAL ;
    PORT
      LAYER M5 ;
        RECT  67.92 302.316 67.944 302.4 ;
    END
  END vi_n[149]
  PIN vi_n[14]
    DIRECTION INPUT ;
    USE SIGNAL ;
    PORT
      LAYER M5 ;
        RECT  28.176 302.316 28.2 302.4 ;
    END
  END vi_n[14]
  PIN vi_n[150]
    DIRECTION INPUT ;
    USE SIGNAL ;
    PORT
      LAYER M5 ;
        RECT  68.112 302.316 68.136 302.4 ;
    END
  END vi_n[150]
  PIN vi_n[151]
    DIRECTION INPUT ;
    USE SIGNAL ;
    PORT
      LAYER M5 ;
        RECT  68.304 302.316 68.328 302.4 ;
    END
  END vi_n[151]
  PIN vi_n[152]
    DIRECTION INPUT ;
    USE SIGNAL ;
    PORT
      LAYER M5 ;
        RECT  68.496 302.316 68.52 302.4 ;
    END
  END vi_n[152]
  PIN vi_n[153]
    DIRECTION INPUT ;
    USE SIGNAL ;
    PORT
      LAYER M5 ;
        RECT  68.688 302.316 68.712 302.4 ;
    END
  END vi_n[153]
  PIN vi_n[154]
    DIRECTION INPUT ;
    USE SIGNAL ;
    PORT
      LAYER M5 ;
        RECT  68.88 302.316 68.904 302.4 ;
    END
  END vi_n[154]
  PIN vi_n[155]
    DIRECTION INPUT ;
    USE SIGNAL ;
    PORT
      LAYER M5 ;
        RECT  69.072 302.316 69.096 302.4 ;
    END
  END vi_n[155]
  PIN vi_n[156]
    DIRECTION INPUT ;
    USE SIGNAL ;
    PORT
      LAYER M5 ;
        RECT  69.264 302.316 69.288 302.4 ;
    END
  END vi_n[156]
  PIN vi_n[157]
    DIRECTION INPUT ;
    USE SIGNAL ;
    PORT
      LAYER M5 ;
        RECT  69.456 302.316 69.48 302.4 ;
    END
  END vi_n[157]
  PIN vi_n[158]
    DIRECTION INPUT ;
    USE SIGNAL ;
    PORT
      LAYER M5 ;
        RECT  69.648 302.316 69.672 302.4 ;
    END
  END vi_n[158]
  PIN vi_n[159]
    DIRECTION INPUT ;
    USE SIGNAL ;
    PORT
      LAYER M5 ;
        RECT  69.84 302.316 69.864 302.4 ;
    END
  END vi_n[159]
  PIN vi_n[15]
    DIRECTION INPUT ;
    USE SIGNAL ;
    PORT
      LAYER M5 ;
        RECT  28.368 302.316 28.392 302.4 ;
    END
  END vi_n[15]
  PIN vi_n[160]
    DIRECTION INPUT ;
    USE SIGNAL ;
    PORT
      LAYER M5 ;
        RECT  31.632 302.316 31.656 302.4 ;
    END
  END vi_n[160]
  PIN vi_n[161]
    DIRECTION INPUT ;
    USE SIGNAL ;
    PORT
      LAYER M5 ;
        RECT  31.824 302.316 31.848 302.4 ;
    END
  END vi_n[161]
  PIN vi_n[162]
    DIRECTION INPUT ;
    USE SIGNAL ;
    PORT
      LAYER M5 ;
        RECT  32.016 302.316 32.04 302.4 ;
    END
  END vi_n[162]
  PIN vi_n[163]
    DIRECTION INPUT ;
    USE SIGNAL ;
    PORT
      LAYER M5 ;
        RECT  32.208 302.316 32.232 302.4 ;
    END
  END vi_n[163]
  PIN vi_n[164]
    DIRECTION INPUT ;
    USE SIGNAL ;
    PORT
      LAYER M5 ;
        RECT  32.4 302.316 32.424 302.4 ;
    END
  END vi_n[164]
  PIN vi_n[165]
    DIRECTION INPUT ;
    USE SIGNAL ;
    PORT
      LAYER M5 ;
        RECT  32.592 302.316 32.616 302.4 ;
    END
  END vi_n[165]
  PIN vi_n[166]
    DIRECTION INPUT ;
    USE SIGNAL ;
    PORT
      LAYER M5 ;
        RECT  32.784 302.316 32.808 302.4 ;
    END
  END vi_n[166]
  PIN vi_n[167]
    DIRECTION INPUT ;
    USE SIGNAL ;
    PORT
      LAYER M5 ;
        RECT  32.976 302.316 33 302.4 ;
    END
  END vi_n[167]
  PIN vi_n[168]
    DIRECTION INPUT ;
    USE SIGNAL ;
    PORT
      LAYER M5 ;
        RECT  33.168 302.316 33.192 302.4 ;
    END
  END vi_n[168]
  PIN vi_n[169]
    DIRECTION INPUT ;
    USE SIGNAL ;
    PORT
      LAYER M5 ;
        RECT  33.36 302.316 33.384 302.4 ;
    END
  END vi_n[169]
  PIN vi_n[16]
    DIRECTION INPUT ;
    USE SIGNAL ;
    PORT
      LAYER M5 ;
        RECT  28.56 302.316 28.584 302.4 ;
    END
  END vi_n[16]
  PIN vi_n[170]
    DIRECTION INPUT ;
    USE SIGNAL ;
    PORT
      LAYER M5 ;
        RECT  33.552 302.316 33.576 302.4 ;
    END
  END vi_n[170]
  PIN vi_n[171]
    DIRECTION INPUT ;
    USE SIGNAL ;
    PORT
      LAYER M5 ;
        RECT  33.744 302.316 33.768 302.4 ;
    END
  END vi_n[171]
  PIN vi_n[172]
    DIRECTION INPUT ;
    USE SIGNAL ;
    PORT
      LAYER M5 ;
        RECT  33.936 302.316 33.96 302.4 ;
    END
  END vi_n[172]
  PIN vi_n[173]
    DIRECTION INPUT ;
    USE SIGNAL ;
    PORT
      LAYER M5 ;
        RECT  34.128 302.316 34.152 302.4 ;
    END
  END vi_n[173]
  PIN vi_n[174]
    DIRECTION INPUT ;
    USE SIGNAL ;
    PORT
      LAYER M5 ;
        RECT  34.32 302.316 34.344 302.4 ;
    END
  END vi_n[174]
  PIN vi_n[175]
    DIRECTION INPUT ;
    USE SIGNAL ;
    PORT
      LAYER M5 ;
        RECT  34.512 302.316 34.536 302.4 ;
    END
  END vi_n[175]
  PIN vi_n[176]
    DIRECTION INPUT ;
    USE SIGNAL ;
    PORT
      LAYER M5 ;
        RECT  34.704 302.316 34.728 302.4 ;
    END
  END vi_n[176]
  PIN vi_n[177]
    DIRECTION INPUT ;
    USE SIGNAL ;
    PORT
      LAYER M5 ;
        RECT  34.896 302.316 34.92 302.4 ;
    END
  END vi_n[177]
  PIN vi_n[178]
    DIRECTION INPUT ;
    USE SIGNAL ;
    PORT
      LAYER M5 ;
        RECT  35.088 302.316 35.112 302.4 ;
    END
  END vi_n[178]
  PIN vi_n[179]
    DIRECTION INPUT ;
    USE SIGNAL ;
    PORT
      LAYER M5 ;
        RECT  35.28 302.316 35.304 302.4 ;
    END
  END vi_n[179]
  PIN vi_n[17]
    DIRECTION INPUT ;
    USE SIGNAL ;
    PORT
      LAYER M5 ;
        RECT  28.752 302.316 28.776 302.4 ;
    END
  END vi_n[17]
  PIN vi_n[180]
    DIRECTION INPUT ;
    USE SIGNAL ;
    PORT
      LAYER M5 ;
        RECT  35.472 302.316 35.496 302.4 ;
    END
  END vi_n[180]
  PIN vi_n[181]
    DIRECTION INPUT ;
    USE SIGNAL ;
    PORT
      LAYER M5 ;
        RECT  35.664 302.316 35.688 302.4 ;
    END
  END vi_n[181]
  PIN vi_n[182]
    DIRECTION INPUT ;
    USE SIGNAL ;
    PORT
      LAYER M5 ;
        RECT  35.856 302.316 35.88 302.4 ;
    END
  END vi_n[182]
  PIN vi_n[183]
    DIRECTION INPUT ;
    USE SIGNAL ;
    PORT
      LAYER M5 ;
        RECT  36.048 302.316 36.072 302.4 ;
    END
  END vi_n[183]
  PIN vi_n[184]
    DIRECTION INPUT ;
    USE SIGNAL ;
    PORT
      LAYER M5 ;
        RECT  36.24 302.316 36.264 302.4 ;
    END
  END vi_n[184]
  PIN vi_n[185]
    DIRECTION INPUT ;
    USE SIGNAL ;
    PORT
      LAYER M5 ;
        RECT  36.432 302.316 36.456 302.4 ;
    END
  END vi_n[185]
  PIN vi_n[186]
    DIRECTION INPUT ;
    USE SIGNAL ;
    PORT
      LAYER M5 ;
        RECT  36.624 302.316 36.648 302.4 ;
    END
  END vi_n[186]
  PIN vi_n[187]
    DIRECTION INPUT ;
    USE SIGNAL ;
    PORT
      LAYER M5 ;
        RECT  36.816 302.316 36.84 302.4 ;
    END
  END vi_n[187]
  PIN vi_n[188]
    DIRECTION INPUT ;
    USE SIGNAL ;
    PORT
      LAYER M5 ;
        RECT  37.008 302.316 37.032 302.4 ;
    END
  END vi_n[188]
  PIN vi_n[189]
    DIRECTION INPUT ;
    USE SIGNAL ;
    PORT
      LAYER M5 ;
        RECT  37.2 302.316 37.224 302.4 ;
    END
  END vi_n[189]
  PIN vi_n[18]
    DIRECTION INPUT ;
    USE SIGNAL ;
    PORT
      LAYER M5 ;
        RECT  28.944 302.316 28.968 302.4 ;
    END
  END vi_n[18]
  PIN vi_n[190]
    DIRECTION INPUT ;
    USE SIGNAL ;
    PORT
      LAYER M5 ;
        RECT  37.392 302.316 37.416 302.4 ;
    END
  END vi_n[190]
  PIN vi_n[191]
    DIRECTION INPUT ;
    USE SIGNAL ;
    PORT
      LAYER M5 ;
        RECT  37.584 302.316 37.608 302.4 ;
    END
  END vi_n[191]
  PIN vi_n[192]
    DIRECTION INPUT ;
    USE SIGNAL ;
    PORT
      LAYER M5 ;
        RECT  13.2 302.316 13.224 302.4 ;
    END
  END vi_n[192]
  PIN vi_n[193]
    DIRECTION INPUT ;
    USE SIGNAL ;
    PORT
      LAYER M5 ;
        RECT  13.392 302.316 13.416 302.4 ;
    END
  END vi_n[193]
  PIN vi_n[194]
    DIRECTION INPUT ;
    USE SIGNAL ;
    PORT
      LAYER M5 ;
        RECT  13.584 302.316 13.608 302.4 ;
    END
  END vi_n[194]
  PIN vi_n[195]
    DIRECTION INPUT ;
    USE SIGNAL ;
    PORT
      LAYER M5 ;
        RECT  13.776 302.316 13.8 302.4 ;
    END
  END vi_n[195]
  PIN vi_n[196]
    DIRECTION INPUT ;
    USE SIGNAL ;
    PORT
      LAYER M5 ;
        RECT  13.968 302.316 13.992 302.4 ;
    END
  END vi_n[196]
  PIN vi_n[197]
    DIRECTION INPUT ;
    USE SIGNAL ;
    PORT
      LAYER M5 ;
        RECT  14.16 302.316 14.184 302.4 ;
    END
  END vi_n[197]
  PIN vi_n[198]
    DIRECTION INPUT ;
    USE SIGNAL ;
    PORT
      LAYER M5 ;
        RECT  14.352 302.316 14.376 302.4 ;
    END
  END vi_n[198]
  PIN vi_n[199]
    DIRECTION INPUT ;
    USE SIGNAL ;
    PORT
      LAYER M5 ;
        RECT  14.544 302.316 14.568 302.4 ;
    END
  END vi_n[199]
  PIN vi_n[19]
    DIRECTION INPUT ;
    USE SIGNAL ;
    PORT
      LAYER M5 ;
        RECT  29.136 302.316 29.16 302.4 ;
    END
  END vi_n[19]
  PIN vi_n[1]
    DIRECTION INPUT ;
    USE SIGNAL ;
    PORT
      LAYER M5 ;
        RECT  25.68 302.316 25.704 302.4 ;
    END
  END vi_n[1]
  PIN vi_n[200]
    DIRECTION INPUT ;
    USE SIGNAL ;
    PORT
      LAYER M5 ;
        RECT  14.736 302.316 14.76 302.4 ;
    END
  END vi_n[200]
  PIN vi_n[201]
    DIRECTION INPUT ;
    USE SIGNAL ;
    PORT
      LAYER M5 ;
        RECT  14.928 302.316 14.952 302.4 ;
    END
  END vi_n[201]
  PIN vi_n[202]
    DIRECTION INPUT ;
    USE SIGNAL ;
    PORT
      LAYER M5 ;
        RECT  15.12 302.316 15.144 302.4 ;
    END
  END vi_n[202]
  PIN vi_n[203]
    DIRECTION INPUT ;
    USE SIGNAL ;
    PORT
      LAYER M5 ;
        RECT  15.312 302.316 15.336 302.4 ;
    END
  END vi_n[203]
  PIN vi_n[204]
    DIRECTION INPUT ;
    USE SIGNAL ;
    PORT
      LAYER M5 ;
        RECT  15.504 302.316 15.528 302.4 ;
    END
  END vi_n[204]
  PIN vi_n[205]
    DIRECTION INPUT ;
    USE SIGNAL ;
    PORT
      LAYER M5 ;
        RECT  15.696 302.316 15.72 302.4 ;
    END
  END vi_n[205]
  PIN vi_n[206]
    DIRECTION INPUT ;
    USE SIGNAL ;
    PORT
      LAYER M5 ;
        RECT  15.888 302.316 15.912 302.4 ;
    END
  END vi_n[206]
  PIN vi_n[207]
    DIRECTION INPUT ;
    USE SIGNAL ;
    PORT
      LAYER M5 ;
        RECT  16.08 302.316 16.104 302.4 ;
    END
  END vi_n[207]
  PIN vi_n[208]
    DIRECTION INPUT ;
    USE SIGNAL ;
    PORT
      LAYER M5 ;
        RECT  16.272 302.316 16.296 302.4 ;
    END
  END vi_n[208]
  PIN vi_n[209]
    DIRECTION INPUT ;
    USE SIGNAL ;
    PORT
      LAYER M5 ;
        RECT  16.464 302.316 16.488 302.4 ;
    END
  END vi_n[209]
  PIN vi_n[20]
    DIRECTION INPUT ;
    USE SIGNAL ;
    PORT
      LAYER M5 ;
        RECT  29.328 302.316 29.352 302.4 ;
    END
  END vi_n[20]
  PIN vi_n[210]
    DIRECTION INPUT ;
    USE SIGNAL ;
    PORT
      LAYER M5 ;
        RECT  16.656 302.316 16.68 302.4 ;
    END
  END vi_n[210]
  PIN vi_n[211]
    DIRECTION INPUT ;
    USE SIGNAL ;
    PORT
      LAYER M5 ;
        RECT  16.848 302.316 16.872 302.4 ;
    END
  END vi_n[211]
  PIN vi_n[212]
    DIRECTION INPUT ;
    USE SIGNAL ;
    PORT
      LAYER M5 ;
        RECT  17.04 302.316 17.064 302.4 ;
    END
  END vi_n[212]
  PIN vi_n[213]
    DIRECTION INPUT ;
    USE SIGNAL ;
    PORT
      LAYER M5 ;
        RECT  17.232 302.316 17.256 302.4 ;
    END
  END vi_n[213]
  PIN vi_n[214]
    DIRECTION INPUT ;
    USE SIGNAL ;
    PORT
      LAYER M5 ;
        RECT  17.424 302.316 17.448 302.4 ;
    END
  END vi_n[214]
  PIN vi_n[215]
    DIRECTION INPUT ;
    USE SIGNAL ;
    PORT
      LAYER M5 ;
        RECT  17.616 302.316 17.64 302.4 ;
    END
  END vi_n[215]
  PIN vi_n[216]
    DIRECTION INPUT ;
    USE SIGNAL ;
    PORT
      LAYER M5 ;
        RECT  17.808 302.316 17.832 302.4 ;
    END
  END vi_n[216]
  PIN vi_n[217]
    DIRECTION INPUT ;
    USE SIGNAL ;
    PORT
      LAYER M5 ;
        RECT  18 302.316 18.024 302.4 ;
    END
  END vi_n[217]
  PIN vi_n[218]
    DIRECTION INPUT ;
    USE SIGNAL ;
    PORT
      LAYER M5 ;
        RECT  18.192 302.316 18.216 302.4 ;
    END
  END vi_n[218]
  PIN vi_n[219]
    DIRECTION INPUT ;
    USE SIGNAL ;
    PORT
      LAYER M5 ;
        RECT  18.384 302.316 18.408 302.4 ;
    END
  END vi_n[219]
  PIN vi_n[21]
    DIRECTION INPUT ;
    USE SIGNAL ;
    PORT
      LAYER M5 ;
        RECT  29.52 302.316 29.544 302.4 ;
    END
  END vi_n[21]
  PIN vi_n[220]
    DIRECTION INPUT ;
    USE SIGNAL ;
    PORT
      LAYER M5 ;
        RECT  18.576 302.316 18.6 302.4 ;
    END
  END vi_n[220]
  PIN vi_n[221]
    DIRECTION INPUT ;
    USE SIGNAL ;
    PORT
      LAYER M5 ;
        RECT  18.768 302.316 18.792 302.4 ;
    END
  END vi_n[221]
  PIN vi_n[222]
    DIRECTION INPUT ;
    USE SIGNAL ;
    PORT
      LAYER M5 ;
        RECT  18.96 302.316 18.984 302.4 ;
    END
  END vi_n[222]
  PIN vi_n[223]
    DIRECTION INPUT ;
    USE SIGNAL ;
    PORT
      LAYER M5 ;
        RECT  19.152 302.316 19.176 302.4 ;
    END
  END vi_n[223]
  PIN vi_n[224]
    DIRECTION INPUT ;
    USE SIGNAL ;
    PORT
      LAYER M5 ;
        RECT  57.744 302.316 57.768 302.4 ;
    END
  END vi_n[224]
  PIN vi_n[225]
    DIRECTION INPUT ;
    USE SIGNAL ;
    PORT
      LAYER M5 ;
        RECT  57.936 302.316 57.96 302.4 ;
    END
  END vi_n[225]
  PIN vi_n[226]
    DIRECTION INPUT ;
    USE SIGNAL ;
    PORT
      LAYER M5 ;
        RECT  58.128 302.316 58.152 302.4 ;
    END
  END vi_n[226]
  PIN vi_n[227]
    DIRECTION INPUT ;
    USE SIGNAL ;
    PORT
      LAYER M5 ;
        RECT  58.32 302.316 58.344 302.4 ;
    END
  END vi_n[227]
  PIN vi_n[228]
    DIRECTION INPUT ;
    USE SIGNAL ;
    PORT
      LAYER M5 ;
        RECT  58.512 302.316 58.536 302.4 ;
    END
  END vi_n[228]
  PIN vi_n[229]
    DIRECTION INPUT ;
    USE SIGNAL ;
    PORT
      LAYER M5 ;
        RECT  58.704 302.316 58.728 302.4 ;
    END
  END vi_n[229]
  PIN vi_n[22]
    DIRECTION INPUT ;
    USE SIGNAL ;
    PORT
      LAYER M5 ;
        RECT  29.712 302.316 29.736 302.4 ;
    END
  END vi_n[22]
  PIN vi_n[230]
    DIRECTION INPUT ;
    USE SIGNAL ;
    PORT
      LAYER M5 ;
        RECT  58.896 302.316 58.92 302.4 ;
    END
  END vi_n[230]
  PIN vi_n[231]
    DIRECTION INPUT ;
    USE SIGNAL ;
    PORT
      LAYER M5 ;
        RECT  59.088 302.316 59.112 302.4 ;
    END
  END vi_n[231]
  PIN vi_n[232]
    DIRECTION INPUT ;
    USE SIGNAL ;
    PORT
      LAYER M5 ;
        RECT  59.28 302.316 59.304 302.4 ;
    END
  END vi_n[232]
  PIN vi_n[233]
    DIRECTION INPUT ;
    USE SIGNAL ;
    PORT
      LAYER M5 ;
        RECT  59.472 302.316 59.496 302.4 ;
    END
  END vi_n[233]
  PIN vi_n[234]
    DIRECTION INPUT ;
    USE SIGNAL ;
    PORT
      LAYER M5 ;
        RECT  59.664 302.316 59.688 302.4 ;
    END
  END vi_n[234]
  PIN vi_n[235]
    DIRECTION INPUT ;
    USE SIGNAL ;
    PORT
      LAYER M5 ;
        RECT  59.856 302.316 59.88 302.4 ;
    END
  END vi_n[235]
  PIN vi_n[236]
    DIRECTION INPUT ;
    USE SIGNAL ;
    PORT
      LAYER M5 ;
        RECT  60.048 302.316 60.072 302.4 ;
    END
  END vi_n[236]
  PIN vi_n[237]
    DIRECTION INPUT ;
    USE SIGNAL ;
    PORT
      LAYER M5 ;
        RECT  60.24 302.316 60.264 302.4 ;
    END
  END vi_n[237]
  PIN vi_n[238]
    DIRECTION INPUT ;
    USE SIGNAL ;
    PORT
      LAYER M5 ;
        RECT  60.432 302.316 60.456 302.4 ;
    END
  END vi_n[238]
  PIN vi_n[239]
    DIRECTION INPUT ;
    USE SIGNAL ;
    PORT
      LAYER M5 ;
        RECT  60.624 302.316 60.648 302.4 ;
    END
  END vi_n[239]
  PIN vi_n[23]
    DIRECTION INPUT ;
    USE SIGNAL ;
    PORT
      LAYER M5 ;
        RECT  29.904 302.316 29.928 302.4 ;
    END
  END vi_n[23]
  PIN vi_n[240]
    DIRECTION INPUT ;
    USE SIGNAL ;
    PORT
      LAYER M5 ;
        RECT  60.816 302.316 60.84 302.4 ;
    END
  END vi_n[240]
  PIN vi_n[241]
    DIRECTION INPUT ;
    USE SIGNAL ;
    PORT
      LAYER M5 ;
        RECT  61.008 302.316 61.032 302.4 ;
    END
  END vi_n[241]
  PIN vi_n[242]
    DIRECTION INPUT ;
    USE SIGNAL ;
    PORT
      LAYER M5 ;
        RECT  61.2 302.316 61.224 302.4 ;
    END
  END vi_n[242]
  PIN vi_n[243]
    DIRECTION INPUT ;
    USE SIGNAL ;
    PORT
      LAYER M5 ;
        RECT  61.392 302.316 61.416 302.4 ;
    END
  END vi_n[243]
  PIN vi_n[244]
    DIRECTION INPUT ;
    USE SIGNAL ;
    PORT
      LAYER M5 ;
        RECT  61.584 302.316 61.608 302.4 ;
    END
  END vi_n[244]
  PIN vi_n[245]
    DIRECTION INPUT ;
    USE SIGNAL ;
    PORT
      LAYER M5 ;
        RECT  61.776 302.316 61.8 302.4 ;
    END
  END vi_n[245]
  PIN vi_n[246]
    DIRECTION INPUT ;
    USE SIGNAL ;
    PORT
      LAYER M5 ;
        RECT  61.968 302.316 61.992 302.4 ;
    END
  END vi_n[246]
  PIN vi_n[247]
    DIRECTION INPUT ;
    USE SIGNAL ;
    PORT
      LAYER M5 ;
        RECT  62.16 302.316 62.184 302.4 ;
    END
  END vi_n[247]
  PIN vi_n[248]
    DIRECTION INPUT ;
    USE SIGNAL ;
    PORT
      LAYER M5 ;
        RECT  62.352 302.316 62.376 302.4 ;
    END
  END vi_n[248]
  PIN vi_n[249]
    DIRECTION INPUT ;
    USE SIGNAL ;
    PORT
      LAYER M5 ;
        RECT  62.544 302.316 62.568 302.4 ;
    END
  END vi_n[249]
  PIN vi_n[24]
    DIRECTION INPUT ;
    USE SIGNAL ;
    PORT
      LAYER M5 ;
        RECT  30.096 302.316 30.12 302.4 ;
    END
  END vi_n[24]
  PIN vi_n[250]
    DIRECTION INPUT ;
    USE SIGNAL ;
    PORT
      LAYER M5 ;
        RECT  62.736 302.316 62.76 302.4 ;
    END
  END vi_n[250]
  PIN vi_n[251]
    DIRECTION INPUT ;
    USE SIGNAL ;
    PORT
      LAYER M5 ;
        RECT  62.928 302.316 62.952 302.4 ;
    END
  END vi_n[251]
  PIN vi_n[252]
    DIRECTION INPUT ;
    USE SIGNAL ;
    PORT
      LAYER M5 ;
        RECT  63.12 302.316 63.144 302.4 ;
    END
  END vi_n[252]
  PIN vi_n[253]
    DIRECTION INPUT ;
    USE SIGNAL ;
    PORT
      LAYER M5 ;
        RECT  63.312 302.316 63.336 302.4 ;
    END
  END vi_n[253]
  PIN vi_n[254]
    DIRECTION INPUT ;
    USE SIGNAL ;
    PORT
      LAYER M5 ;
        RECT  63.504 302.316 63.528 302.4 ;
    END
  END vi_n[254]
  PIN vi_n[255]
    DIRECTION INPUT ;
    USE SIGNAL ;
    PORT
      LAYER M5 ;
        RECT  63.696 302.316 63.72 302.4 ;
    END
  END vi_n[255]
  PIN vi_n[256]
    DIRECTION INPUT ;
    USE SIGNAL ;
    PORT
      LAYER M5 ;
        RECT  45.456 302.316 45.48 302.4 ;
    END
  END vi_n[256]
  PIN vi_n[257]
    DIRECTION INPUT ;
    USE SIGNAL ;
    PORT
      LAYER M5 ;
        RECT  45.648 302.316 45.672 302.4 ;
    END
  END vi_n[257]
  PIN vi_n[258]
    DIRECTION INPUT ;
    USE SIGNAL ;
    PORT
      LAYER M5 ;
        RECT  45.84 302.316 45.864 302.4 ;
    END
  END vi_n[258]
  PIN vi_n[259]
    DIRECTION INPUT ;
    USE SIGNAL ;
    PORT
      LAYER M5 ;
        RECT  46.032 302.316 46.056 302.4 ;
    END
  END vi_n[259]
  PIN vi_n[25]
    DIRECTION INPUT ;
    USE SIGNAL ;
    PORT
      LAYER M5 ;
        RECT  30.288 302.316 30.312 302.4 ;
    END
  END vi_n[25]
  PIN vi_n[260]
    DIRECTION INPUT ;
    USE SIGNAL ;
    PORT
      LAYER M5 ;
        RECT  46.224 302.316 46.248 302.4 ;
    END
  END vi_n[260]
  PIN vi_n[261]
    DIRECTION INPUT ;
    USE SIGNAL ;
    PORT
      LAYER M5 ;
        RECT  46.416 302.316 46.44 302.4 ;
    END
  END vi_n[261]
  PIN vi_n[262]
    DIRECTION INPUT ;
    USE SIGNAL ;
    PORT
      LAYER M5 ;
        RECT  46.608 302.316 46.632 302.4 ;
    END
  END vi_n[262]
  PIN vi_n[263]
    DIRECTION INPUT ;
    USE SIGNAL ;
    PORT
      LAYER M5 ;
        RECT  46.8 302.316 46.824 302.4 ;
    END
  END vi_n[263]
  PIN vi_n[264]
    DIRECTION INPUT ;
    USE SIGNAL ;
    PORT
      LAYER M5 ;
        RECT  46.992 302.316 47.016 302.4 ;
    END
  END vi_n[264]
  PIN vi_n[265]
    DIRECTION INPUT ;
    USE SIGNAL ;
    PORT
      LAYER M5 ;
        RECT  47.184 302.316 47.208 302.4 ;
    END
  END vi_n[265]
  PIN vi_n[266]
    DIRECTION INPUT ;
    USE SIGNAL ;
    PORT
      LAYER M5 ;
        RECT  47.376 302.316 47.4 302.4 ;
    END
  END vi_n[266]
  PIN vi_n[267]
    DIRECTION INPUT ;
    USE SIGNAL ;
    PORT
      LAYER M5 ;
        RECT  47.568 302.316 47.592 302.4 ;
    END
  END vi_n[267]
  PIN vi_n[268]
    DIRECTION INPUT ;
    USE SIGNAL ;
    PORT
      LAYER M5 ;
        RECT  47.76 302.316 47.784 302.4 ;
    END
  END vi_n[268]
  PIN vi_n[269]
    DIRECTION INPUT ;
    USE SIGNAL ;
    PORT
      LAYER M5 ;
        RECT  47.952 302.316 47.976 302.4 ;
    END
  END vi_n[269]
  PIN vi_n[26]
    DIRECTION INPUT ;
    USE SIGNAL ;
    PORT
      LAYER M5 ;
        RECT  30.48 302.316 30.504 302.4 ;
    END
  END vi_n[26]
  PIN vi_n[270]
    DIRECTION INPUT ;
    USE SIGNAL ;
    PORT
      LAYER M5 ;
        RECT  48.144 302.316 48.168 302.4 ;
    END
  END vi_n[270]
  PIN vi_n[271]
    DIRECTION INPUT ;
    USE SIGNAL ;
    PORT
      LAYER M5 ;
        RECT  48.336 302.316 48.36 302.4 ;
    END
  END vi_n[271]
  PIN vi_n[272]
    DIRECTION INPUT ;
    USE SIGNAL ;
    PORT
      LAYER M5 ;
        RECT  48.528 302.316 48.552 302.4 ;
    END
  END vi_n[272]
  PIN vi_n[273]
    DIRECTION INPUT ;
    USE SIGNAL ;
    PORT
      LAYER M5 ;
        RECT  48.72 302.316 48.744 302.4 ;
    END
  END vi_n[273]
  PIN vi_n[274]
    DIRECTION INPUT ;
    USE SIGNAL ;
    PORT
      LAYER M5 ;
        RECT  48.912 302.316 48.936 302.4 ;
    END
  END vi_n[274]
  PIN vi_n[275]
    DIRECTION INPUT ;
    USE SIGNAL ;
    PORT
      LAYER M5 ;
        RECT  49.104 302.316 49.128 302.4 ;
    END
  END vi_n[275]
  PIN vi_n[27]
    DIRECTION INPUT ;
    USE SIGNAL ;
    PORT
      LAYER M5 ;
        RECT  30.672 302.316 30.696 302.4 ;
    END
  END vi_n[27]
  PIN vi_n[28]
    DIRECTION INPUT ;
    USE SIGNAL ;
    PORT
      LAYER M5 ;
        RECT  30.864 302.316 30.888 302.4 ;
    END
  END vi_n[28]
  PIN vi_n[29]
    DIRECTION INPUT ;
    USE SIGNAL ;
    PORT
      LAYER M5 ;
        RECT  31.056 302.316 31.08 302.4 ;
    END
  END vi_n[29]
  PIN vi_n[2]
    DIRECTION INPUT ;
    USE SIGNAL ;
    PORT
      LAYER M5 ;
        RECT  25.872 302.316 25.896 302.4 ;
    END
  END vi_n[2]
  PIN vi_n[30]
    DIRECTION INPUT ;
    USE SIGNAL ;
    PORT
      LAYER M5 ;
        RECT  31.248 302.316 31.272 302.4 ;
    END
  END vi_n[30]
  PIN vi_n[31]
    DIRECTION INPUT ;
    USE SIGNAL ;
    PORT
      LAYER M5 ;
        RECT  31.44 302.316 31.464 302.4 ;
    END
  END vi_n[31]
  PIN vi_n[32]
    DIRECTION INPUT ;
    USE SIGNAL ;
    PORT
      LAYER M5 ;
        RECT  19.344 302.316 19.368 302.4 ;
    END
  END vi_n[32]
  PIN vi_n[33]
    DIRECTION INPUT ;
    USE SIGNAL ;
    PORT
      LAYER M5 ;
        RECT  19.536 302.316 19.56 302.4 ;
    END
  END vi_n[33]
  PIN vi_n[34]
    DIRECTION INPUT ;
    USE SIGNAL ;
    PORT
      LAYER M5 ;
        RECT  19.728 302.316 19.752 302.4 ;
    END
  END vi_n[34]
  PIN vi_n[35]
    DIRECTION INPUT ;
    USE SIGNAL ;
    PORT
      LAYER M5 ;
        RECT  19.92 302.316 19.944 302.4 ;
    END
  END vi_n[35]
  PIN vi_n[36]
    DIRECTION INPUT ;
    USE SIGNAL ;
    PORT
      LAYER M5 ;
        RECT  20.112 302.316 20.136 302.4 ;
    END
  END vi_n[36]
  PIN vi_n[37]
    DIRECTION INPUT ;
    USE SIGNAL ;
    PORT
      LAYER M5 ;
        RECT  20.304 302.316 20.328 302.4 ;
    END
  END vi_n[37]
  PIN vi_n[38]
    DIRECTION INPUT ;
    USE SIGNAL ;
    PORT
      LAYER M5 ;
        RECT  20.496 302.316 20.52 302.4 ;
    END
  END vi_n[38]
  PIN vi_n[39]
    DIRECTION INPUT ;
    USE SIGNAL ;
    PORT
      LAYER M5 ;
        RECT  20.688 302.316 20.712 302.4 ;
    END
  END vi_n[39]
  PIN vi_n[3]
    DIRECTION INPUT ;
    USE SIGNAL ;
    PORT
      LAYER M5 ;
        RECT  26.064 302.316 26.088 302.4 ;
    END
  END vi_n[3]
  PIN vi_n[40]
    DIRECTION INPUT ;
    USE SIGNAL ;
    PORT
      LAYER M5 ;
        RECT  20.88 302.316 20.904 302.4 ;
    END
  END vi_n[40]
  PIN vi_n[41]
    DIRECTION INPUT ;
    USE SIGNAL ;
    PORT
      LAYER M5 ;
        RECT  21.072 302.316 21.096 302.4 ;
    END
  END vi_n[41]
  PIN vi_n[42]
    DIRECTION INPUT ;
    USE SIGNAL ;
    PORT
      LAYER M5 ;
        RECT  21.264 302.316 21.288 302.4 ;
    END
  END vi_n[42]
  PIN vi_n[43]
    DIRECTION INPUT ;
    USE SIGNAL ;
    PORT
      LAYER M5 ;
        RECT  21.456 302.316 21.48 302.4 ;
    END
  END vi_n[43]
  PIN vi_n[44]
    DIRECTION INPUT ;
    USE SIGNAL ;
    PORT
      LAYER M5 ;
        RECT  21.648 302.316 21.672 302.4 ;
    END
  END vi_n[44]
  PIN vi_n[45]
    DIRECTION INPUT ;
    USE SIGNAL ;
    PORT
      LAYER M5 ;
        RECT  21.84 302.316 21.864 302.4 ;
    END
  END vi_n[45]
  PIN vi_n[46]
    DIRECTION INPUT ;
    USE SIGNAL ;
    PORT
      LAYER M5 ;
        RECT  22.032 302.316 22.056 302.4 ;
    END
  END vi_n[46]
  PIN vi_n[47]
    DIRECTION INPUT ;
    USE SIGNAL ;
    PORT
      LAYER M5 ;
        RECT  22.224 302.316 22.248 302.4 ;
    END
  END vi_n[47]
  PIN vi_n[48]
    DIRECTION INPUT ;
    USE SIGNAL ;
    PORT
      LAYER M5 ;
        RECT  22.416 302.316 22.44 302.4 ;
    END
  END vi_n[48]
  PIN vi_n[49]
    DIRECTION INPUT ;
    USE SIGNAL ;
    PORT
      LAYER M5 ;
        RECT  22.608 302.316 22.632 302.4 ;
    END
  END vi_n[49]
  PIN vi_n[4]
    DIRECTION INPUT ;
    USE SIGNAL ;
    PORT
      LAYER M5 ;
        RECT  26.256 302.316 26.28 302.4 ;
    END
  END vi_n[4]
  PIN vi_n[50]
    DIRECTION INPUT ;
    USE SIGNAL ;
    PORT
      LAYER M5 ;
        RECT  22.8 302.316 22.824 302.4 ;
    END
  END vi_n[50]
  PIN vi_n[51]
    DIRECTION INPUT ;
    USE SIGNAL ;
    PORT
      LAYER M5 ;
        RECT  22.992 302.316 23.016 302.4 ;
    END
  END vi_n[51]
  PIN vi_n[52]
    DIRECTION INPUT ;
    USE SIGNAL ;
    PORT
      LAYER M5 ;
        RECT  23.184 302.316 23.208 302.4 ;
    END
  END vi_n[52]
  PIN vi_n[53]
    DIRECTION INPUT ;
    USE SIGNAL ;
    PORT
      LAYER M5 ;
        RECT  23.376 302.316 23.4 302.4 ;
    END
  END vi_n[53]
  PIN vi_n[54]
    DIRECTION INPUT ;
    USE SIGNAL ;
    PORT
      LAYER M5 ;
        RECT  23.568 302.316 23.592 302.4 ;
    END
  END vi_n[54]
  PIN vi_n[55]
    DIRECTION INPUT ;
    USE SIGNAL ;
    PORT
      LAYER M5 ;
        RECT  23.76 302.316 23.784 302.4 ;
    END
  END vi_n[55]
  PIN vi_n[56]
    DIRECTION INPUT ;
    USE SIGNAL ;
    PORT
      LAYER M5 ;
        RECT  23.952 302.316 23.976 302.4 ;
    END
  END vi_n[56]
  PIN vi_n[57]
    DIRECTION INPUT ;
    USE SIGNAL ;
    PORT
      LAYER M5 ;
        RECT  24.144 302.316 24.168 302.4 ;
    END
  END vi_n[57]
  PIN vi_n[58]
    DIRECTION INPUT ;
    USE SIGNAL ;
    PORT
      LAYER M5 ;
        RECT  24.336 302.316 24.36 302.4 ;
    END
  END vi_n[58]
  PIN vi_n[59]
    DIRECTION INPUT ;
    USE SIGNAL ;
    PORT
      LAYER M5 ;
        RECT  24.528 302.316 24.552 302.4 ;
    END
  END vi_n[59]
  PIN vi_n[5]
    DIRECTION INPUT ;
    USE SIGNAL ;
    PORT
      LAYER M5 ;
        RECT  26.448 302.316 26.472 302.4 ;
    END
  END vi_n[5]
  PIN vi_n[60]
    DIRECTION INPUT ;
    USE SIGNAL ;
    PORT
      LAYER M5 ;
        RECT  24.72 302.316 24.744 302.4 ;
    END
  END vi_n[60]
  PIN vi_n[61]
    DIRECTION INPUT ;
    USE SIGNAL ;
    PORT
      LAYER M5 ;
        RECT  24.912 302.316 24.936 302.4 ;
    END
  END vi_n[61]
  PIN vi_n[62]
    DIRECTION INPUT ;
    USE SIGNAL ;
    PORT
      LAYER M5 ;
        RECT  25.104 302.316 25.128 302.4 ;
    END
  END vi_n[62]
  PIN vi_n[63]
    DIRECTION INPUT ;
    USE SIGNAL ;
    PORT
      LAYER M5 ;
        RECT  25.296 302.316 25.32 302.4 ;
    END
  END vi_n[63]
  PIN vi_n[64]
    DIRECTION INPUT ;
    USE SIGNAL ;
    PORT
      LAYER M5 ;
        RECT  7.056 302.316 7.08 302.4 ;
    END
  END vi_n[64]
  PIN vi_n[65]
    DIRECTION INPUT ;
    USE SIGNAL ;
    PORT
      LAYER M5 ;
        RECT  7.248 302.316 7.272 302.4 ;
    END
  END vi_n[65]
  PIN vi_n[66]
    DIRECTION INPUT ;
    USE SIGNAL ;
    PORT
      LAYER M5 ;
        RECT  7.44 302.316 7.464 302.4 ;
    END
  END vi_n[66]
  PIN vi_n[67]
    DIRECTION INPUT ;
    USE SIGNAL ;
    PORT
      LAYER M5 ;
        RECT  7.632 302.316 7.656 302.4 ;
    END
  END vi_n[67]
  PIN vi_n[68]
    DIRECTION INPUT ;
    USE SIGNAL ;
    PORT
      LAYER M5 ;
        RECT  7.824 302.316 7.848 302.4 ;
    END
  END vi_n[68]
  PIN vi_n[69]
    DIRECTION INPUT ;
    USE SIGNAL ;
    PORT
      LAYER M5 ;
        RECT  8.016 302.316 8.04 302.4 ;
    END
  END vi_n[69]
  PIN vi_n[6]
    DIRECTION INPUT ;
    USE SIGNAL ;
    PORT
      LAYER M5 ;
        RECT  26.64 302.316 26.664 302.4 ;
    END
  END vi_n[6]
  PIN vi_n[70]
    DIRECTION INPUT ;
    USE SIGNAL ;
    PORT
      LAYER M5 ;
        RECT  8.208 302.316 8.232 302.4 ;
    END
  END vi_n[70]
  PIN vi_n[71]
    DIRECTION INPUT ;
    USE SIGNAL ;
    PORT
      LAYER M5 ;
        RECT  8.4 302.316 8.424 302.4 ;
    END
  END vi_n[71]
  PIN vi_n[72]
    DIRECTION INPUT ;
    USE SIGNAL ;
    PORT
      LAYER M5 ;
        RECT  8.592 302.316 8.616 302.4 ;
    END
  END vi_n[72]
  PIN vi_n[73]
    DIRECTION INPUT ;
    USE SIGNAL ;
    PORT
      LAYER M5 ;
        RECT  8.784 302.316 8.808 302.4 ;
    END
  END vi_n[73]
  PIN vi_n[74]
    DIRECTION INPUT ;
    USE SIGNAL ;
    PORT
      LAYER M5 ;
        RECT  8.976 302.316 9 302.4 ;
    END
  END vi_n[74]
  PIN vi_n[75]
    DIRECTION INPUT ;
    USE SIGNAL ;
    PORT
      LAYER M5 ;
        RECT  9.168 302.316 9.192 302.4 ;
    END
  END vi_n[75]
  PIN vi_n[76]
    DIRECTION INPUT ;
    USE SIGNAL ;
    PORT
      LAYER M5 ;
        RECT  9.36 302.316 9.384 302.4 ;
    END
  END vi_n[76]
  PIN vi_n[77]
    DIRECTION INPUT ;
    USE SIGNAL ;
    PORT
      LAYER M5 ;
        RECT  9.552 302.316 9.576 302.4 ;
    END
  END vi_n[77]
  PIN vi_n[78]
    DIRECTION INPUT ;
    USE SIGNAL ;
    PORT
      LAYER M5 ;
        RECT  9.744 302.316 9.768 302.4 ;
    END
  END vi_n[78]
  PIN vi_n[79]
    DIRECTION INPUT ;
    USE SIGNAL ;
    PORT
      LAYER M5 ;
        RECT  9.936 302.316 9.96 302.4 ;
    END
  END vi_n[79]
  PIN vi_n[7]
    DIRECTION INPUT ;
    USE SIGNAL ;
    PORT
      LAYER M5 ;
        RECT  26.832 302.316 26.856 302.4 ;
    END
  END vi_n[7]
  PIN vi_n[80]
    DIRECTION INPUT ;
    USE SIGNAL ;
    PORT
      LAYER M5 ;
        RECT  10.128 302.316 10.152 302.4 ;
    END
  END vi_n[80]
  PIN vi_n[81]
    DIRECTION INPUT ;
    USE SIGNAL ;
    PORT
      LAYER M5 ;
        RECT  10.32 302.316 10.344 302.4 ;
    END
  END vi_n[81]
  PIN vi_n[82]
    DIRECTION INPUT ;
    USE SIGNAL ;
    PORT
      LAYER M5 ;
        RECT  10.512 302.316 10.536 302.4 ;
    END
  END vi_n[82]
  PIN vi_n[83]
    DIRECTION INPUT ;
    USE SIGNAL ;
    PORT
      LAYER M5 ;
        RECT  10.704 302.316 10.728 302.4 ;
    END
  END vi_n[83]
  PIN vi_n[84]
    DIRECTION INPUT ;
    USE SIGNAL ;
    PORT
      LAYER M5 ;
        RECT  10.896 302.316 10.92 302.4 ;
    END
  END vi_n[84]
  PIN vi_n[85]
    DIRECTION INPUT ;
    USE SIGNAL ;
    PORT
      LAYER M5 ;
        RECT  11.088 302.316 11.112 302.4 ;
    END
  END vi_n[85]
  PIN vi_n[86]
    DIRECTION INPUT ;
    USE SIGNAL ;
    PORT
      LAYER M5 ;
        RECT  11.28 302.316 11.304 302.4 ;
    END
  END vi_n[86]
  PIN vi_n[87]
    DIRECTION INPUT ;
    USE SIGNAL ;
    PORT
      LAYER M5 ;
        RECT  11.472 302.316 11.496 302.4 ;
    END
  END vi_n[87]
  PIN vi_n[88]
    DIRECTION INPUT ;
    USE SIGNAL ;
    PORT
      LAYER M5 ;
        RECT  11.664 302.316 11.688 302.4 ;
    END
  END vi_n[88]
  PIN vi_n[89]
    DIRECTION INPUT ;
    USE SIGNAL ;
    PORT
      LAYER M5 ;
        RECT  11.856 302.316 11.88 302.4 ;
    END
  END vi_n[89]
  PIN vi_n[8]
    DIRECTION INPUT ;
    USE SIGNAL ;
    PORT
      LAYER M5 ;
        RECT  27.024 302.316 27.048 302.4 ;
    END
  END vi_n[8]
  PIN vi_n[90]
    DIRECTION INPUT ;
    USE SIGNAL ;
    PORT
      LAYER M5 ;
        RECT  12.048 302.316 12.072 302.4 ;
    END
  END vi_n[90]
  PIN vi_n[91]
    DIRECTION INPUT ;
    USE SIGNAL ;
    PORT
      LAYER M5 ;
        RECT  12.24 302.316 12.264 302.4 ;
    END
  END vi_n[91]
  PIN vi_n[92]
    DIRECTION INPUT ;
    USE SIGNAL ;
    PORT
      LAYER M5 ;
        RECT  12.432 302.316 12.456 302.4 ;
    END
  END vi_n[92]
  PIN vi_n[93]
    DIRECTION INPUT ;
    USE SIGNAL ;
    PORT
      LAYER M5 ;
        RECT  12.624 302.316 12.648 302.4 ;
    END
  END vi_n[93]
  PIN vi_n[94]
    DIRECTION INPUT ;
    USE SIGNAL ;
    PORT
      LAYER M5 ;
        RECT  12.816 302.316 12.84 302.4 ;
    END
  END vi_n[94]
  PIN vi_n[95]
    DIRECTION INPUT ;
    USE SIGNAL ;
    PORT
      LAYER M5 ;
        RECT  13.008 302.316 13.032 302.4 ;
    END
  END vi_n[95]
  PIN vi_n[96]
    DIRECTION INPUT ;
    USE SIGNAL ;
    PORT
      LAYER M5 ;
        RECT  0.912 302.316 0.936 302.4 ;
    END
  END vi_n[96]
  PIN vi_n[97]
    DIRECTION INPUT ;
    USE SIGNAL ;
    PORT
      LAYER M5 ;
        RECT  1.104 302.316 1.128 302.4 ;
    END
  END vi_n[97]
  PIN vi_n[98]
    DIRECTION INPUT ;
    USE SIGNAL ;
    PORT
      LAYER M5 ;
        RECT  1.296 302.316 1.32 302.4 ;
    END
  END vi_n[98]
  PIN vi_n[99]
    DIRECTION INPUT ;
    USE SIGNAL ;
    PORT
      LAYER M5 ;
        RECT  1.488 302.316 1.512 302.4 ;
    END
  END vi_n[99]
  PIN vi_n[9]
    DIRECTION INPUT ;
    USE SIGNAL ;
    PORT
      LAYER M5 ;
        RECT  27.216 302.316 27.24 302.4 ;
    END
  END vi_n[9]
  PIN vo_n[0]
    DIRECTION OUTPUT ;
    USE SIGNAL ;
    PORT
      LAYER M5 ;
        RECT  49.296 302.316 49.32 302.4 ;
    END
  END vo_n[0]
  PIN vo_n[100]
    DIRECTION OUTPUT ;
    USE SIGNAL ;
    PORT
      LAYER M5 ;
        RECT  56.208 302.316 56.232 302.4 ;
    END
  END vo_n[100]
  PIN vo_n[101]
    DIRECTION OUTPUT ;
    USE SIGNAL ;
    PORT
      LAYER M5 ;
        RECT  56.4 302.316 56.424 302.4 ;
    END
  END vo_n[101]
  PIN vo_n[102]
    DIRECTION OUTPUT ;
    USE SIGNAL ;
    PORT
      LAYER M5 ;
        RECT  56.592 302.316 56.616 302.4 ;
    END
  END vo_n[102]
  PIN vo_n[103]
    DIRECTION OUTPUT ;
    USE SIGNAL ;
    PORT
      LAYER M5 ;
        RECT  56.784 302.316 56.808 302.4 ;
    END
  END vo_n[103]
  PIN vo_n[104]
    DIRECTION OUTPUT ;
    USE SIGNAL ;
    PORT
      LAYER M5 ;
        RECT  56.976 302.316 57 302.4 ;
    END
  END vo_n[104]
  PIN vo_n[105]
    DIRECTION OUTPUT ;
    USE SIGNAL ;
    PORT
      LAYER M5 ;
        RECT  57.168 302.316 57.192 302.4 ;
    END
  END vo_n[105]
  PIN vo_n[106]
    DIRECTION OUTPUT ;
    USE SIGNAL ;
    PORT
      LAYER M5 ;
        RECT  57.36 302.316 57.384 302.4 ;
    END
  END vo_n[106]
  PIN vo_n[107]
    DIRECTION OUTPUT ;
    USE SIGNAL ;
    PORT
      LAYER M5 ;
        RECT  57.552 302.316 57.576 302.4 ;
    END
  END vo_n[107]
  PIN vo_n[108]
    DIRECTION OUTPUT ;
    USE SIGNAL ;
    PORT
      LAYER M5 ;
        RECT  90 302.316 90.024 302.4 ;
    END
  END vo_n[108]
  PIN vo_n[109]
    DIRECTION OUTPUT ;
    USE SIGNAL ;
    PORT
      LAYER M5 ;
        RECT  90.192 302.316 90.216 302.4 ;
    END
  END vo_n[109]
  PIN vo_n[10]
    DIRECTION OUTPUT ;
    USE SIGNAL ;
    PORT
      LAYER M5 ;
        RECT  51.216 302.316 51.24 302.4 ;
    END
  END vo_n[10]
  PIN vo_n[110]
    DIRECTION OUTPUT ;
    USE SIGNAL ;
    PORT
      LAYER M5 ;
        RECT  90.384 302.316 90.408 302.4 ;
    END
  END vo_n[110]
  PIN vo_n[111]
    DIRECTION OUTPUT ;
    USE SIGNAL ;
    PORT
      LAYER M5 ;
        RECT  90.576 302.316 90.6 302.4 ;
    END
  END vo_n[111]
  PIN vo_n[112]
    DIRECTION OUTPUT ;
    USE SIGNAL ;
    PORT
      LAYER M5 ;
        RECT  90.768 302.316 90.792 302.4 ;
    END
  END vo_n[112]
  PIN vo_n[113]
    DIRECTION OUTPUT ;
    USE SIGNAL ;
    PORT
      LAYER M5 ;
        RECT  90.96 302.316 90.984 302.4 ;
    END
  END vo_n[113]
  PIN vo_n[114]
    DIRECTION OUTPUT ;
    USE SIGNAL ;
    PORT
      LAYER M5 ;
        RECT  91.152 302.316 91.176 302.4 ;
    END
  END vo_n[114]
  PIN vo_n[115]
    DIRECTION OUTPUT ;
    USE SIGNAL ;
    PORT
      LAYER M5 ;
        RECT  91.344 302.316 91.368 302.4 ;
    END
  END vo_n[115]
  PIN vo_n[116]
    DIRECTION OUTPUT ;
    USE SIGNAL ;
    PORT
      LAYER M5 ;
        RECT  91.536 302.316 91.56 302.4 ;
    END
  END vo_n[116]
  PIN vo_n[117]
    DIRECTION OUTPUT ;
    USE SIGNAL ;
    PORT
      LAYER M5 ;
        RECT  91.728 302.316 91.752 302.4 ;
    END
  END vo_n[117]
  PIN vo_n[118]
    DIRECTION OUTPUT ;
    USE SIGNAL ;
    PORT
      LAYER M5 ;
        RECT  91.92 302.316 91.944 302.4 ;
    END
  END vo_n[118]
  PIN vo_n[119]
    DIRECTION OUTPUT ;
    USE SIGNAL ;
    PORT
      LAYER M5 ;
        RECT  92.112 302.316 92.136 302.4 ;
    END
  END vo_n[119]
  PIN vo_n[11]
    DIRECTION OUTPUT ;
    USE SIGNAL ;
    PORT
      LAYER M5 ;
        RECT  51.408 302.316 51.432 302.4 ;
    END
  END vo_n[11]
  PIN vo_n[120]
    DIRECTION OUTPUT ;
    USE SIGNAL ;
    PORT
      LAYER M5 ;
        RECT  92.304 302.316 92.328 302.4 ;
    END
  END vo_n[120]
  PIN vo_n[121]
    DIRECTION OUTPUT ;
    USE SIGNAL ;
    PORT
      LAYER M5 ;
        RECT  92.496 302.316 92.52 302.4 ;
    END
  END vo_n[121]
  PIN vo_n[122]
    DIRECTION OUTPUT ;
    USE SIGNAL ;
    PORT
      LAYER M5 ;
        RECT  92.688 302.316 92.712 302.4 ;
    END
  END vo_n[122]
  PIN vo_n[123]
    DIRECTION OUTPUT ;
    USE SIGNAL ;
    PORT
      LAYER M5 ;
        RECT  92.88 302.316 92.904 302.4 ;
    END
  END vo_n[123]
  PIN vo_n[124]
    DIRECTION OUTPUT ;
    USE SIGNAL ;
    PORT
      LAYER M5 ;
        RECT  93.072 302.316 93.096 302.4 ;
    END
  END vo_n[124]
  PIN vo_n[125]
    DIRECTION OUTPUT ;
    USE SIGNAL ;
    PORT
      LAYER M5 ;
        RECT  93.264 302.316 93.288 302.4 ;
    END
  END vo_n[125]
  PIN vo_n[126]
    DIRECTION OUTPUT ;
    USE SIGNAL ;
    PORT
      LAYER M5 ;
        RECT  93.456 302.316 93.48 302.4 ;
    END
  END vo_n[126]
  PIN vo_n[127]
    DIRECTION OUTPUT ;
    USE SIGNAL ;
    PORT
      LAYER M5 ;
        RECT  93.648 302.316 93.672 302.4 ;
    END
  END vo_n[127]
  PIN vo_n[128]
    DIRECTION OUTPUT ;
    USE SIGNAL ;
    PORT
      LAYER M5 ;
        RECT  93.84 302.316 93.864 302.4 ;
    END
  END vo_n[128]
  PIN vo_n[129]
    DIRECTION OUTPUT ;
    USE SIGNAL ;
    PORT
      LAYER M5 ;
        RECT  94.032 302.316 94.056 302.4 ;
    END
  END vo_n[129]
  PIN vo_n[12]
    DIRECTION OUTPUT ;
    USE SIGNAL ;
    PORT
      LAYER M5 ;
        RECT  70.032 302.316 70.056 302.4 ;
    END
  END vo_n[12]
  PIN vo_n[130]
    DIRECTION OUTPUT ;
    USE SIGNAL ;
    PORT
      LAYER M5 ;
        RECT  94.224 302.316 94.248 302.4 ;
    END
  END vo_n[130]
  PIN vo_n[131]
    DIRECTION OUTPUT ;
    USE SIGNAL ;
    PORT
      LAYER M5 ;
        RECT  94.416 302.316 94.44 302.4 ;
    END
  END vo_n[131]
  PIN vo_n[132]
    DIRECTION OUTPUT ;
    USE SIGNAL ;
    PORT
      LAYER M5 ;
        RECT  94.608 302.316 94.632 302.4 ;
    END
  END vo_n[132]
  PIN vo_n[133]
    DIRECTION OUTPUT ;
    USE SIGNAL ;
    PORT
      LAYER M5 ;
        RECT  94.8 302.316 94.824 302.4 ;
    END
  END vo_n[133]
  PIN vo_n[134]
    DIRECTION OUTPUT ;
    USE SIGNAL ;
    PORT
      LAYER M5 ;
        RECT  94.992 302.316 95.016 302.4 ;
    END
  END vo_n[134]
  PIN vo_n[135]
    DIRECTION OUTPUT ;
    USE SIGNAL ;
    PORT
      LAYER M5 ;
        RECT  95.184 302.316 95.208 302.4 ;
    END
  END vo_n[135]
  PIN vo_n[136]
    DIRECTION OUTPUT ;
    USE SIGNAL ;
    PORT
      LAYER M5 ;
        RECT  95.376 302.316 95.4 302.4 ;
    END
  END vo_n[136]
  PIN vo_n[137]
    DIRECTION OUTPUT ;
    USE SIGNAL ;
    PORT
      LAYER M5 ;
        RECT  95.568 302.316 95.592 302.4 ;
    END
  END vo_n[137]
  PIN vo_n[138]
    DIRECTION OUTPUT ;
    USE SIGNAL ;
    PORT
      LAYER M5 ;
        RECT  95.76 302.316 95.784 302.4 ;
    END
  END vo_n[138]
  PIN vo_n[139]
    DIRECTION OUTPUT ;
    USE SIGNAL ;
    PORT
      LAYER M5 ;
        RECT  95.952 302.316 95.976 302.4 ;
    END
  END vo_n[139]
  PIN vo_n[13]
    DIRECTION OUTPUT ;
    USE SIGNAL ;
    PORT
      LAYER M5 ;
        RECT  70.224 302.316 70.248 302.4 ;
    END
  END vo_n[13]
  PIN vo_n[140]
    DIRECTION OUTPUT ;
    USE SIGNAL ;
    PORT
      LAYER M5 ;
        RECT  102.288 302.316 102.312 302.4 ;
    END
  END vo_n[140]
  PIN vo_n[141]
    DIRECTION OUTPUT ;
    USE SIGNAL ;
    PORT
      LAYER M5 ;
        RECT  102.48 302.316 102.504 302.4 ;
    END
  END vo_n[141]
  PIN vo_n[142]
    DIRECTION OUTPUT ;
    USE SIGNAL ;
    PORT
      LAYER M5 ;
        RECT  102.672 302.316 102.696 302.4 ;
    END
  END vo_n[142]
  PIN vo_n[143]
    DIRECTION OUTPUT ;
    USE SIGNAL ;
    PORT
      LAYER M5 ;
        RECT  102.864 302.316 102.888 302.4 ;
    END
  END vo_n[143]
  PIN vo_n[144]
    DIRECTION OUTPUT ;
    USE SIGNAL ;
    PORT
      LAYER M5 ;
        RECT  103.056 302.316 103.08 302.4 ;
    END
  END vo_n[144]
  PIN vo_n[145]
    DIRECTION OUTPUT ;
    USE SIGNAL ;
    PORT
      LAYER M5 ;
        RECT  103.248 302.316 103.272 302.4 ;
    END
  END vo_n[145]
  PIN vo_n[146]
    DIRECTION OUTPUT ;
    USE SIGNAL ;
    PORT
      LAYER M5 ;
        RECT  103.44 302.316 103.464 302.4 ;
    END
  END vo_n[146]
  PIN vo_n[147]
    DIRECTION OUTPUT ;
    USE SIGNAL ;
    PORT
      LAYER M5 ;
        RECT  103.632 302.316 103.656 302.4 ;
    END
  END vo_n[147]
  PIN vo_n[148]
    DIRECTION OUTPUT ;
    USE SIGNAL ;
    PORT
      LAYER M5 ;
        RECT  103.824 302.316 103.848 302.4 ;
    END
  END vo_n[148]
  PIN vo_n[149]
    DIRECTION OUTPUT ;
    USE SIGNAL ;
    PORT
      LAYER M5 ;
        RECT  104.016 302.316 104.04 302.4 ;
    END
  END vo_n[149]
  PIN vo_n[14]
    DIRECTION OUTPUT ;
    USE SIGNAL ;
    PORT
      LAYER M5 ;
        RECT  70.416 302.316 70.44 302.4 ;
    END
  END vo_n[14]
  PIN vo_n[150]
    DIRECTION OUTPUT ;
    USE SIGNAL ;
    PORT
      LAYER M5 ;
        RECT  104.208 302.316 104.232 302.4 ;
    END
  END vo_n[150]
  PIN vo_n[151]
    DIRECTION OUTPUT ;
    USE SIGNAL ;
    PORT
      LAYER M5 ;
        RECT  104.4 302.316 104.424 302.4 ;
    END
  END vo_n[151]
  PIN vo_n[152]
    DIRECTION OUTPUT ;
    USE SIGNAL ;
    PORT
      LAYER M5 ;
        RECT  104.592 302.316 104.616 302.4 ;
    END
  END vo_n[152]
  PIN vo_n[153]
    DIRECTION OUTPUT ;
    USE SIGNAL ;
    PORT
      LAYER M5 ;
        RECT  104.784 302.316 104.808 302.4 ;
    END
  END vo_n[153]
  PIN vo_n[154]
    DIRECTION OUTPUT ;
    USE SIGNAL ;
    PORT
      LAYER M5 ;
        RECT  104.976 302.316 105 302.4 ;
    END
  END vo_n[154]
  PIN vo_n[155]
    DIRECTION OUTPUT ;
    USE SIGNAL ;
    PORT
      LAYER M5 ;
        RECT  105.168 302.316 105.192 302.4 ;
    END
  END vo_n[155]
  PIN vo_n[156]
    DIRECTION OUTPUT ;
    USE SIGNAL ;
    PORT
      LAYER M5 ;
        RECT  105.36 302.316 105.384 302.4 ;
    END
  END vo_n[156]
  PIN vo_n[157]
    DIRECTION OUTPUT ;
    USE SIGNAL ;
    PORT
      LAYER M5 ;
        RECT  105.552 302.316 105.576 302.4 ;
    END
  END vo_n[157]
  PIN vo_n[158]
    DIRECTION OUTPUT ;
    USE SIGNAL ;
    PORT
      LAYER M5 ;
        RECT  105.744 302.316 105.768 302.4 ;
    END
  END vo_n[158]
  PIN vo_n[159]
    DIRECTION OUTPUT ;
    USE SIGNAL ;
    PORT
      LAYER M5 ;
        RECT  105.936 302.316 105.96 302.4 ;
    END
  END vo_n[159]
  PIN vo_n[15]
    DIRECTION OUTPUT ;
    USE SIGNAL ;
    PORT
      LAYER M5 ;
        RECT  70.608 302.316 70.632 302.4 ;
    END
  END vo_n[15]
  PIN vo_n[160]
    DIRECTION OUTPUT ;
    USE SIGNAL ;
    PORT
      LAYER M5 ;
        RECT  106.128 302.316 106.152 302.4 ;
    END
  END vo_n[160]
  PIN vo_n[161]
    DIRECTION OUTPUT ;
    USE SIGNAL ;
    PORT
      LAYER M5 ;
        RECT  106.32 302.316 106.344 302.4 ;
    END
  END vo_n[161]
  PIN vo_n[162]
    DIRECTION OUTPUT ;
    USE SIGNAL ;
    PORT
      LAYER M5 ;
        RECT  106.512 302.316 106.536 302.4 ;
    END
  END vo_n[162]
  PIN vo_n[163]
    DIRECTION OUTPUT ;
    USE SIGNAL ;
    PORT
      LAYER M5 ;
        RECT  106.704 302.316 106.728 302.4 ;
    END
  END vo_n[163]
  PIN vo_n[164]
    DIRECTION OUTPUT ;
    USE SIGNAL ;
    PORT
      LAYER M5 ;
        RECT  106.896 302.316 106.92 302.4 ;
    END
  END vo_n[164]
  PIN vo_n[165]
    DIRECTION OUTPUT ;
    USE SIGNAL ;
    PORT
      LAYER M5 ;
        RECT  107.088 302.316 107.112 302.4 ;
    END
  END vo_n[165]
  PIN vo_n[166]
    DIRECTION OUTPUT ;
    USE SIGNAL ;
    PORT
      LAYER M5 ;
        RECT  107.28 302.316 107.304 302.4 ;
    END
  END vo_n[166]
  PIN vo_n[167]
    DIRECTION OUTPUT ;
    USE SIGNAL ;
    PORT
      LAYER M5 ;
        RECT  107.472 302.316 107.496 302.4 ;
    END
  END vo_n[167]
  PIN vo_n[168]
    DIRECTION OUTPUT ;
    USE SIGNAL ;
    PORT
      LAYER M5 ;
        RECT  107.664 302.316 107.688 302.4 ;
    END
  END vo_n[168]
  PIN vo_n[169]
    DIRECTION OUTPUT ;
    USE SIGNAL ;
    PORT
      LAYER M5 ;
        RECT  107.856 302.316 107.88 302.4 ;
    END
  END vo_n[169]
  PIN vo_n[16]
    DIRECTION OUTPUT ;
    USE SIGNAL ;
    PORT
      LAYER M5 ;
        RECT  70.8 302.316 70.824 302.4 ;
    END
  END vo_n[16]
  PIN vo_n[170]
    DIRECTION OUTPUT ;
    USE SIGNAL ;
    PORT
      LAYER M5 ;
        RECT  108.048 302.316 108.072 302.4 ;
    END
  END vo_n[170]
  PIN vo_n[171]
    DIRECTION OUTPUT ;
    USE SIGNAL ;
    PORT
      LAYER M5 ;
        RECT  108.24 302.316 108.264 302.4 ;
    END
  END vo_n[171]
  PIN vo_n[172]
    DIRECTION OUTPUT ;
    USE SIGNAL ;
    PORT
      LAYER M5 ;
        RECT  96.144 302.316 96.168 302.4 ;
    END
  END vo_n[172]
  PIN vo_n[173]
    DIRECTION OUTPUT ;
    USE SIGNAL ;
    PORT
      LAYER M5 ;
        RECT  96.336 302.316 96.36 302.4 ;
    END
  END vo_n[173]
  PIN vo_n[174]
    DIRECTION OUTPUT ;
    USE SIGNAL ;
    PORT
      LAYER M5 ;
        RECT  96.528 302.316 96.552 302.4 ;
    END
  END vo_n[174]
  PIN vo_n[175]
    DIRECTION OUTPUT ;
    USE SIGNAL ;
    PORT
      LAYER M5 ;
        RECT  96.72 302.316 96.744 302.4 ;
    END
  END vo_n[175]
  PIN vo_n[176]
    DIRECTION OUTPUT ;
    USE SIGNAL ;
    PORT
      LAYER M5 ;
        RECT  96.912 302.316 96.936 302.4 ;
    END
  END vo_n[176]
  PIN vo_n[177]
    DIRECTION OUTPUT ;
    USE SIGNAL ;
    PORT
      LAYER M5 ;
        RECT  97.104 302.316 97.128 302.4 ;
    END
  END vo_n[177]
  PIN vo_n[178]
    DIRECTION OUTPUT ;
    USE SIGNAL ;
    PORT
      LAYER M5 ;
        RECT  97.296 302.316 97.32 302.4 ;
    END
  END vo_n[178]
  PIN vo_n[179]
    DIRECTION OUTPUT ;
    USE SIGNAL ;
    PORT
      LAYER M5 ;
        RECT  97.488 302.316 97.512 302.4 ;
    END
  END vo_n[179]
  PIN vo_n[17]
    DIRECTION OUTPUT ;
    USE SIGNAL ;
    PORT
      LAYER M5 ;
        RECT  70.992 302.316 71.016 302.4 ;
    END
  END vo_n[17]
  PIN vo_n[180]
    DIRECTION OUTPUT ;
    USE SIGNAL ;
    PORT
      LAYER M5 ;
        RECT  97.68 302.316 97.704 302.4 ;
    END
  END vo_n[180]
  PIN vo_n[181]
    DIRECTION OUTPUT ;
    USE SIGNAL ;
    PORT
      LAYER M5 ;
        RECT  97.872 302.316 97.896 302.4 ;
    END
  END vo_n[181]
  PIN vo_n[182]
    DIRECTION OUTPUT ;
    USE SIGNAL ;
    PORT
      LAYER M5 ;
        RECT  98.064 302.316 98.088 302.4 ;
    END
  END vo_n[182]
  PIN vo_n[183]
    DIRECTION OUTPUT ;
    USE SIGNAL ;
    PORT
      LAYER M5 ;
        RECT  98.256 302.316 98.28 302.4 ;
    END
  END vo_n[183]
  PIN vo_n[184]
    DIRECTION OUTPUT ;
    USE SIGNAL ;
    PORT
      LAYER M5 ;
        RECT  98.448 302.316 98.472 302.4 ;
    END
  END vo_n[184]
  PIN vo_n[185]
    DIRECTION OUTPUT ;
    USE SIGNAL ;
    PORT
      LAYER M5 ;
        RECT  98.64 302.316 98.664 302.4 ;
    END
  END vo_n[185]
  PIN vo_n[186]
    DIRECTION OUTPUT ;
    USE SIGNAL ;
    PORT
      LAYER M5 ;
        RECT  98.832 302.316 98.856 302.4 ;
    END
  END vo_n[186]
  PIN vo_n[187]
    DIRECTION OUTPUT ;
    USE SIGNAL ;
    PORT
      LAYER M5 ;
        RECT  99.024 302.316 99.048 302.4 ;
    END
  END vo_n[187]
  PIN vo_n[188]
    DIRECTION OUTPUT ;
    USE SIGNAL ;
    PORT
      LAYER M5 ;
        RECT  99.216 302.316 99.24 302.4 ;
    END
  END vo_n[188]
  PIN vo_n[189]
    DIRECTION OUTPUT ;
    USE SIGNAL ;
    PORT
      LAYER M5 ;
        RECT  99.408 302.316 99.432 302.4 ;
    END
  END vo_n[189]
  PIN vo_n[18]
    DIRECTION OUTPUT ;
    USE SIGNAL ;
    PORT
      LAYER M5 ;
        RECT  71.184 302.316 71.208 302.4 ;
    END
  END vo_n[18]
  PIN vo_n[190]
    DIRECTION OUTPUT ;
    USE SIGNAL ;
    PORT
      LAYER M5 ;
        RECT  99.6 302.316 99.624 302.4 ;
    END
  END vo_n[190]
  PIN vo_n[191]
    DIRECTION OUTPUT ;
    USE SIGNAL ;
    PORT
      LAYER M5 ;
        RECT  99.792 302.316 99.816 302.4 ;
    END
  END vo_n[191]
  PIN vo_n[192]
    DIRECTION OUTPUT ;
    USE SIGNAL ;
    PORT
      LAYER M5 ;
        RECT  99.984 302.316 100.008 302.4 ;
    END
  END vo_n[192]
  PIN vo_n[193]
    DIRECTION OUTPUT ;
    USE SIGNAL ;
    PORT
      LAYER M5 ;
        RECT  100.176 302.316 100.2 302.4 ;
    END
  END vo_n[193]
  PIN vo_n[194]
    DIRECTION OUTPUT ;
    USE SIGNAL ;
    PORT
      LAYER M5 ;
        RECT  100.368 302.316 100.392 302.4 ;
    END
  END vo_n[194]
  PIN vo_n[195]
    DIRECTION OUTPUT ;
    USE SIGNAL ;
    PORT
      LAYER M5 ;
        RECT  100.56 302.316 100.584 302.4 ;
    END
  END vo_n[195]
  PIN vo_n[196]
    DIRECTION OUTPUT ;
    USE SIGNAL ;
    PORT
      LAYER M5 ;
        RECT  100.752 302.316 100.776 302.4 ;
    END
  END vo_n[196]
  PIN vo_n[197]
    DIRECTION OUTPUT ;
    USE SIGNAL ;
    PORT
      LAYER M5 ;
        RECT  100.944 302.316 100.968 302.4 ;
    END
  END vo_n[197]
  PIN vo_n[198]
    DIRECTION OUTPUT ;
    USE SIGNAL ;
    PORT
      LAYER M5 ;
        RECT  101.136 302.316 101.16 302.4 ;
    END
  END vo_n[198]
  PIN vo_n[199]
    DIRECTION OUTPUT ;
    USE SIGNAL ;
    PORT
      LAYER M5 ;
        RECT  101.328 302.316 101.352 302.4 ;
    END
  END vo_n[199]
  PIN vo_n[19]
    DIRECTION OUTPUT ;
    USE SIGNAL ;
    PORT
      LAYER M5 ;
        RECT  71.376 302.316 71.4 302.4 ;
    END
  END vo_n[19]
  PIN vo_n[1]
    DIRECTION OUTPUT ;
    USE SIGNAL ;
    PORT
      LAYER M5 ;
        RECT  49.488 302.316 49.512 302.4 ;
    END
  END vo_n[1]
  PIN vo_n[200]
    DIRECTION OUTPUT ;
    USE SIGNAL ;
    PORT
      LAYER M5 ;
        RECT  101.52 302.316 101.544 302.4 ;
    END
  END vo_n[200]
  PIN vo_n[201]
    DIRECTION OUTPUT ;
    USE SIGNAL ;
    PORT
      LAYER M5 ;
        RECT  101.712 302.316 101.736 302.4 ;
    END
  END vo_n[201]
  PIN vo_n[202]
    DIRECTION OUTPUT ;
    USE SIGNAL ;
    PORT
      LAYER M5 ;
        RECT  101.904 302.316 101.928 302.4 ;
    END
  END vo_n[202]
  PIN vo_n[203]
    DIRECTION OUTPUT ;
    USE SIGNAL ;
    PORT
      LAYER M5 ;
        RECT  102.096 302.316 102.12 302.4 ;
    END
  END vo_n[203]
  PIN vo_n[204]
    DIRECTION OUTPUT ;
    USE SIGNAL ;
    PORT
      LAYER M5 ;
        RECT  77.712 302.316 77.736 302.4 ;
    END
  END vo_n[204]
  PIN vo_n[205]
    DIRECTION OUTPUT ;
    USE SIGNAL ;
    PORT
      LAYER M5 ;
        RECT  77.904 302.316 77.928 302.4 ;
    END
  END vo_n[205]
  PIN vo_n[206]
    DIRECTION OUTPUT ;
    USE SIGNAL ;
    PORT
      LAYER M5 ;
        RECT  78.096 302.316 78.12 302.4 ;
    END
  END vo_n[206]
  PIN vo_n[207]
    DIRECTION OUTPUT ;
    USE SIGNAL ;
    PORT
      LAYER M5 ;
        RECT  78.288 302.316 78.312 302.4 ;
    END
  END vo_n[207]
  PIN vo_n[208]
    DIRECTION OUTPUT ;
    USE SIGNAL ;
    PORT
      LAYER M5 ;
        RECT  78.48 302.316 78.504 302.4 ;
    END
  END vo_n[208]
  PIN vo_n[209]
    DIRECTION OUTPUT ;
    USE SIGNAL ;
    PORT
      LAYER M5 ;
        RECT  78.672 302.316 78.696 302.4 ;
    END
  END vo_n[209]
  PIN vo_n[20]
    DIRECTION OUTPUT ;
    USE SIGNAL ;
    PORT
      LAYER M5 ;
        RECT  71.568 302.316 71.592 302.4 ;
    END
  END vo_n[20]
  PIN vo_n[210]
    DIRECTION OUTPUT ;
    USE SIGNAL ;
    PORT
      LAYER M5 ;
        RECT  78.864 302.316 78.888 302.4 ;
    END
  END vo_n[210]
  PIN vo_n[211]
    DIRECTION OUTPUT ;
    USE SIGNAL ;
    PORT
      LAYER M5 ;
        RECT  79.056 302.316 79.08 302.4 ;
    END
  END vo_n[211]
  PIN vo_n[212]
    DIRECTION OUTPUT ;
    USE SIGNAL ;
    PORT
      LAYER M5 ;
        RECT  79.248 302.316 79.272 302.4 ;
    END
  END vo_n[212]
  PIN vo_n[213]
    DIRECTION OUTPUT ;
    USE SIGNAL ;
    PORT
      LAYER M5 ;
        RECT  79.44 302.316 79.464 302.4 ;
    END
  END vo_n[213]
  PIN vo_n[214]
    DIRECTION OUTPUT ;
    USE SIGNAL ;
    PORT
      LAYER M5 ;
        RECT  79.632 302.316 79.656 302.4 ;
    END
  END vo_n[214]
  PIN vo_n[215]
    DIRECTION OUTPUT ;
    USE SIGNAL ;
    PORT
      LAYER M5 ;
        RECT  79.824 302.316 79.848 302.4 ;
    END
  END vo_n[215]
  PIN vo_n[216]
    DIRECTION OUTPUT ;
    USE SIGNAL ;
    PORT
      LAYER M5 ;
        RECT  80.016 302.316 80.04 302.4 ;
    END
  END vo_n[216]
  PIN vo_n[217]
    DIRECTION OUTPUT ;
    USE SIGNAL ;
    PORT
      LAYER M5 ;
        RECT  80.208 302.316 80.232 302.4 ;
    END
  END vo_n[217]
  PIN vo_n[218]
    DIRECTION OUTPUT ;
    USE SIGNAL ;
    PORT
      LAYER M5 ;
        RECT  80.4 302.316 80.424 302.4 ;
    END
  END vo_n[218]
  PIN vo_n[219]
    DIRECTION OUTPUT ;
    USE SIGNAL ;
    PORT
      LAYER M5 ;
        RECT  80.592 302.316 80.616 302.4 ;
    END
  END vo_n[219]
  PIN vo_n[21]
    DIRECTION OUTPUT ;
    USE SIGNAL ;
    PORT
      LAYER M5 ;
        RECT  71.76 302.316 71.784 302.4 ;
    END
  END vo_n[21]
  PIN vo_n[220]
    DIRECTION OUTPUT ;
    USE SIGNAL ;
    PORT
      LAYER M5 ;
        RECT  80.784 302.316 80.808 302.4 ;
    END
  END vo_n[220]
  PIN vo_n[221]
    DIRECTION OUTPUT ;
    USE SIGNAL ;
    PORT
      LAYER M5 ;
        RECT  80.976 302.316 81 302.4 ;
    END
  END vo_n[221]
  PIN vo_n[222]
    DIRECTION OUTPUT ;
    USE SIGNAL ;
    PORT
      LAYER M5 ;
        RECT  81.168 302.316 81.192 302.4 ;
    END
  END vo_n[222]
  PIN vo_n[223]
    DIRECTION OUTPUT ;
    USE SIGNAL ;
    PORT
      LAYER M5 ;
        RECT  81.36 302.316 81.384 302.4 ;
    END
  END vo_n[223]
  PIN vo_n[224]
    DIRECTION OUTPUT ;
    USE SIGNAL ;
    PORT
      LAYER M5 ;
        RECT  81.552 302.316 81.576 302.4 ;
    END
  END vo_n[224]
  PIN vo_n[225]
    DIRECTION OUTPUT ;
    USE SIGNAL ;
    PORT
      LAYER M5 ;
        RECT  81.744 302.316 81.768 302.4 ;
    END
  END vo_n[225]
  PIN vo_n[226]
    DIRECTION OUTPUT ;
    USE SIGNAL ;
    PORT
      LAYER M5 ;
        RECT  81.936 302.316 81.96 302.4 ;
    END
  END vo_n[226]
  PIN vo_n[227]
    DIRECTION OUTPUT ;
    USE SIGNAL ;
    PORT
      LAYER M5 ;
        RECT  82.128 302.316 82.152 302.4 ;
    END
  END vo_n[227]
  PIN vo_n[228]
    DIRECTION OUTPUT ;
    USE SIGNAL ;
    PORT
      LAYER M5 ;
        RECT  82.32 302.316 82.344 302.4 ;
    END
  END vo_n[228]
  PIN vo_n[229]
    DIRECTION OUTPUT ;
    USE SIGNAL ;
    PORT
      LAYER M5 ;
        RECT  82.512 302.316 82.536 302.4 ;
    END
  END vo_n[229]
  PIN vo_n[22]
    DIRECTION OUTPUT ;
    USE SIGNAL ;
    PORT
      LAYER M5 ;
        RECT  71.952 302.316 71.976 302.4 ;
    END
  END vo_n[22]
  PIN vo_n[230]
    DIRECTION OUTPUT ;
    USE SIGNAL ;
    PORT
      LAYER M5 ;
        RECT  82.704 302.316 82.728 302.4 ;
    END
  END vo_n[230]
  PIN vo_n[231]
    DIRECTION OUTPUT ;
    USE SIGNAL ;
    PORT
      LAYER M5 ;
        RECT  82.896 302.316 82.92 302.4 ;
    END
  END vo_n[231]
  PIN vo_n[232]
    DIRECTION OUTPUT ;
    USE SIGNAL ;
    PORT
      LAYER M5 ;
        RECT  83.088 302.316 83.112 302.4 ;
    END
  END vo_n[232]
  PIN vo_n[233]
    DIRECTION OUTPUT ;
    USE SIGNAL ;
    PORT
      LAYER M5 ;
        RECT  83.28 302.316 83.304 302.4 ;
    END
  END vo_n[233]
  PIN vo_n[234]
    DIRECTION OUTPUT ;
    USE SIGNAL ;
    PORT
      LAYER M5 ;
        RECT  83.472 302.316 83.496 302.4 ;
    END
  END vo_n[234]
  PIN vo_n[235]
    DIRECTION OUTPUT ;
    USE SIGNAL ;
    PORT
      LAYER M5 ;
        RECT  83.664 302.316 83.688 302.4 ;
    END
  END vo_n[235]
  PIN vo_n[236]
    DIRECTION OUTPUT ;
    USE SIGNAL ;
    PORT
      LAYER M5 ;
        RECT  83.856 302.316 83.88 302.4 ;
    END
  END vo_n[236]
  PIN vo_n[237]
    DIRECTION OUTPUT ;
    USE SIGNAL ;
    PORT
      LAYER M5 ;
        RECT  84.048 302.316 84.072 302.4 ;
    END
  END vo_n[237]
  PIN vo_n[238]
    DIRECTION OUTPUT ;
    USE SIGNAL ;
    PORT
      LAYER M5 ;
        RECT  84.24 302.316 84.264 302.4 ;
    END
  END vo_n[238]
  PIN vo_n[239]
    DIRECTION OUTPUT ;
    USE SIGNAL ;
    PORT
      LAYER M5 ;
        RECT  84.432 302.316 84.456 302.4 ;
    END
  END vo_n[239]
  PIN vo_n[23]
    DIRECTION OUTPUT ;
    USE SIGNAL ;
    PORT
      LAYER M5 ;
        RECT  72.144 302.316 72.168 302.4 ;
    END
  END vo_n[23]
  PIN vo_n[240]
    DIRECTION OUTPUT ;
    USE SIGNAL ;
    PORT
      LAYER M5 ;
        RECT  84.624 302.316 84.648 302.4 ;
    END
  END vo_n[240]
  PIN vo_n[241]
    DIRECTION OUTPUT ;
    USE SIGNAL ;
    PORT
      LAYER M5 ;
        RECT  84.816 302.316 84.84 302.4 ;
    END
  END vo_n[241]
  PIN vo_n[242]
    DIRECTION OUTPUT ;
    USE SIGNAL ;
    PORT
      LAYER M5 ;
        RECT  85.008 302.316 85.032 302.4 ;
    END
  END vo_n[242]
  PIN vo_n[243]
    DIRECTION OUTPUT ;
    USE SIGNAL ;
    PORT
      LAYER M5 ;
        RECT  85.2 302.316 85.224 302.4 ;
    END
  END vo_n[243]
  PIN vo_n[244]
    DIRECTION OUTPUT ;
    USE SIGNAL ;
    PORT
      LAYER M5 ;
        RECT  85.392 302.316 85.416 302.4 ;
    END
  END vo_n[244]
  PIN vo_n[245]
    DIRECTION OUTPUT ;
    USE SIGNAL ;
    PORT
      LAYER M5 ;
        RECT  85.584 302.316 85.608 302.4 ;
    END
  END vo_n[245]
  PIN vo_n[246]
    DIRECTION OUTPUT ;
    USE SIGNAL ;
    PORT
      LAYER M5 ;
        RECT  85.776 302.316 85.8 302.4 ;
    END
  END vo_n[246]
  PIN vo_n[247]
    DIRECTION OUTPUT ;
    USE SIGNAL ;
    PORT
      LAYER M5 ;
        RECT  85.968 302.316 85.992 302.4 ;
    END
  END vo_n[247]
  PIN vo_n[248]
    DIRECTION OUTPUT ;
    USE SIGNAL ;
    PORT
      LAYER M5 ;
        RECT  86.16 302.316 86.184 302.4 ;
    END
  END vo_n[248]
  PIN vo_n[249]
    DIRECTION OUTPUT ;
    USE SIGNAL ;
    PORT
      LAYER M5 ;
        RECT  86.352 302.316 86.376 302.4 ;
    END
  END vo_n[249]
  PIN vo_n[24]
    DIRECTION OUTPUT ;
    USE SIGNAL ;
    PORT
      LAYER M5 ;
        RECT  72.336 302.316 72.36 302.4 ;
    END
  END vo_n[24]
  PIN vo_n[250]
    DIRECTION OUTPUT ;
    USE SIGNAL ;
    PORT
      LAYER M5 ;
        RECT  86.544 302.316 86.568 302.4 ;
    END
  END vo_n[250]
  PIN vo_n[251]
    DIRECTION OUTPUT ;
    USE SIGNAL ;
    PORT
      LAYER M5 ;
        RECT  86.736 302.316 86.76 302.4 ;
    END
  END vo_n[251]
  PIN vo_n[252]
    DIRECTION OUTPUT ;
    USE SIGNAL ;
    PORT
      LAYER M5 ;
        RECT  86.928 302.316 86.952 302.4 ;
    END
  END vo_n[252]
  PIN vo_n[253]
    DIRECTION OUTPUT ;
    USE SIGNAL ;
    PORT
      LAYER M5 ;
        RECT  87.12 302.316 87.144 302.4 ;
    END
  END vo_n[253]
  PIN vo_n[254]
    DIRECTION OUTPUT ;
    USE SIGNAL ;
    PORT
      LAYER M5 ;
        RECT  87.312 302.316 87.336 302.4 ;
    END
  END vo_n[254]
  PIN vo_n[255]
    DIRECTION OUTPUT ;
    USE SIGNAL ;
    PORT
      LAYER M5 ;
        RECT  87.504 302.316 87.528 302.4 ;
    END
  END vo_n[255]
  PIN vo_n[256]
    DIRECTION OUTPUT ;
    USE SIGNAL ;
    PORT
      LAYER M5 ;
        RECT  87.696 302.316 87.72 302.4 ;
    END
  END vo_n[256]
  PIN vo_n[257]
    DIRECTION OUTPUT ;
    USE SIGNAL ;
    PORT
      LAYER M5 ;
        RECT  87.888 302.316 87.912 302.4 ;
    END
  END vo_n[257]
  PIN vo_n[258]
    DIRECTION OUTPUT ;
    USE SIGNAL ;
    PORT
      LAYER M5 ;
        RECT  88.08 302.316 88.104 302.4 ;
    END
  END vo_n[258]
  PIN vo_n[259]
    DIRECTION OUTPUT ;
    USE SIGNAL ;
    PORT
      LAYER M5 ;
        RECT  88.272 302.316 88.296 302.4 ;
    END
  END vo_n[259]
  PIN vo_n[25]
    DIRECTION OUTPUT ;
    USE SIGNAL ;
    PORT
      LAYER M5 ;
        RECT  72.528 302.316 72.552 302.4 ;
    END
  END vo_n[25]
  PIN vo_n[260]
    DIRECTION OUTPUT ;
    USE SIGNAL ;
    PORT
      LAYER M5 ;
        RECT  88.464 302.316 88.488 302.4 ;
    END
  END vo_n[260]
  PIN vo_n[261]
    DIRECTION OUTPUT ;
    USE SIGNAL ;
    PORT
      LAYER M5 ;
        RECT  88.656 302.316 88.68 302.4 ;
    END
  END vo_n[261]
  PIN vo_n[262]
    DIRECTION OUTPUT ;
    USE SIGNAL ;
    PORT
      LAYER M5 ;
        RECT  88.848 302.316 88.872 302.4 ;
    END
  END vo_n[262]
  PIN vo_n[263]
    DIRECTION OUTPUT ;
    USE SIGNAL ;
    PORT
      LAYER M5 ;
        RECT  89.04 302.316 89.064 302.4 ;
    END
  END vo_n[263]
  PIN vo_n[264]
    DIRECTION OUTPUT ;
    USE SIGNAL ;
    PORT
      LAYER M5 ;
        RECT  89.232 302.316 89.256 302.4 ;
    END
  END vo_n[264]
  PIN vo_n[265]
    DIRECTION OUTPUT ;
    USE SIGNAL ;
    PORT
      LAYER M5 ;
        RECT  89.424 302.316 89.448 302.4 ;
    END
  END vo_n[265]
  PIN vo_n[266]
    DIRECTION OUTPUT ;
    USE SIGNAL ;
    PORT
      LAYER M5 ;
        RECT  89.616 302.316 89.64 302.4 ;
    END
  END vo_n[266]
  PIN vo_n[267]
    DIRECTION OUTPUT ;
    USE SIGNAL ;
    PORT
      LAYER M5 ;
        RECT  89.808 302.316 89.832 302.4 ;
    END
  END vo_n[267]
  PIN vo_n[268]
    DIRECTION OUTPUT ;
    USE SIGNAL ;
    PORT
      LAYER M5 ;
        RECT  37.776 302.316 37.8 302.4 ;
    END
  END vo_n[268]
  PIN vo_n[269]
    DIRECTION OUTPUT ;
    USE SIGNAL ;
    PORT
      LAYER M5 ;
        RECT  37.968 302.316 37.992 302.4 ;
    END
  END vo_n[269]
  PIN vo_n[26]
    DIRECTION OUTPUT ;
    USE SIGNAL ;
    PORT
      LAYER M5 ;
        RECT  72.72 302.316 72.744 302.4 ;
    END
  END vo_n[26]
  PIN vo_n[270]
    DIRECTION OUTPUT ;
    USE SIGNAL ;
    PORT
      LAYER M5 ;
        RECT  38.16 302.316 38.184 302.4 ;
    END
  END vo_n[270]
  PIN vo_n[271]
    DIRECTION OUTPUT ;
    USE SIGNAL ;
    PORT
      LAYER M5 ;
        RECT  38.352 302.316 38.376 302.4 ;
    END
  END vo_n[271]
  PIN vo_n[272]
    DIRECTION OUTPUT ;
    USE SIGNAL ;
    PORT
      LAYER M5 ;
        RECT  38.544 302.316 38.568 302.4 ;
    END
  END vo_n[272]
  PIN vo_n[273]
    DIRECTION OUTPUT ;
    USE SIGNAL ;
    PORT
      LAYER M5 ;
        RECT  38.736 302.316 38.76 302.4 ;
    END
  END vo_n[273]
  PIN vo_n[274]
    DIRECTION OUTPUT ;
    USE SIGNAL ;
    PORT
      LAYER M5 ;
        RECT  38.928 302.316 38.952 302.4 ;
    END
  END vo_n[274]
  PIN vo_n[275]
    DIRECTION OUTPUT ;
    USE SIGNAL ;
    PORT
      LAYER M5 ;
        RECT  39.12 302.316 39.144 302.4 ;
    END
  END vo_n[275]
  PIN vo_n[27]
    DIRECTION OUTPUT ;
    USE SIGNAL ;
    PORT
      LAYER M5 ;
        RECT  72.912 302.316 72.936 302.4 ;
    END
  END vo_n[27]
  PIN vo_n[28]
    DIRECTION OUTPUT ;
    USE SIGNAL ;
    PORT
      LAYER M5 ;
        RECT  73.104 302.316 73.128 302.4 ;
    END
  END vo_n[28]
  PIN vo_n[29]
    DIRECTION OUTPUT ;
    USE SIGNAL ;
    PORT
      LAYER M5 ;
        RECT  73.296 302.316 73.32 302.4 ;
    END
  END vo_n[29]
  PIN vo_n[2]
    DIRECTION OUTPUT ;
    USE SIGNAL ;
    PORT
      LAYER M5 ;
        RECT  49.68 302.316 49.704 302.4 ;
    END
  END vo_n[2]
  PIN vo_n[30]
    DIRECTION OUTPUT ;
    USE SIGNAL ;
    PORT
      LAYER M5 ;
        RECT  73.488 302.316 73.512 302.4 ;
    END
  END vo_n[30]
  PIN vo_n[31]
    DIRECTION OUTPUT ;
    USE SIGNAL ;
    PORT
      LAYER M5 ;
        RECT  73.68 302.316 73.704 302.4 ;
    END
  END vo_n[31]
  PIN vo_n[32]
    DIRECTION OUTPUT ;
    USE SIGNAL ;
    PORT
      LAYER M5 ;
        RECT  73.872 302.316 73.896 302.4 ;
    END
  END vo_n[32]
  PIN vo_n[33]
    DIRECTION OUTPUT ;
    USE SIGNAL ;
    PORT
      LAYER M5 ;
        RECT  74.064 302.316 74.088 302.4 ;
    END
  END vo_n[33]
  PIN vo_n[34]
    DIRECTION OUTPUT ;
    USE SIGNAL ;
    PORT
      LAYER M5 ;
        RECT  74.256 302.316 74.28 302.4 ;
    END
  END vo_n[34]
  PIN vo_n[35]
    DIRECTION OUTPUT ;
    USE SIGNAL ;
    PORT
      LAYER M5 ;
        RECT  74.448 302.316 74.472 302.4 ;
    END
  END vo_n[35]
  PIN vo_n[36]
    DIRECTION OUTPUT ;
    USE SIGNAL ;
    PORT
      LAYER M5 ;
        RECT  74.64 302.316 74.664 302.4 ;
    END
  END vo_n[36]
  PIN vo_n[37]
    DIRECTION OUTPUT ;
    USE SIGNAL ;
    PORT
      LAYER M5 ;
        RECT  74.832 302.316 74.856 302.4 ;
    END
  END vo_n[37]
  PIN vo_n[38]
    DIRECTION OUTPUT ;
    USE SIGNAL ;
    PORT
      LAYER M5 ;
        RECT  75.024 302.316 75.048 302.4 ;
    END
  END vo_n[38]
  PIN vo_n[39]
    DIRECTION OUTPUT ;
    USE SIGNAL ;
    PORT
      LAYER M5 ;
        RECT  75.216 302.316 75.24 302.4 ;
    END
  END vo_n[39]
  PIN vo_n[3]
    DIRECTION OUTPUT ;
    USE SIGNAL ;
    PORT
      LAYER M5 ;
        RECT  49.872 302.316 49.896 302.4 ;
    END
  END vo_n[3]
  PIN vo_n[40]
    DIRECTION OUTPUT ;
    USE SIGNAL ;
    PORT
      LAYER M5 ;
        RECT  75.408 302.316 75.432 302.4 ;
    END
  END vo_n[40]
  PIN vo_n[41]
    DIRECTION OUTPUT ;
    USE SIGNAL ;
    PORT
      LAYER M5 ;
        RECT  75.6 302.316 75.624 302.4 ;
    END
  END vo_n[41]
  PIN vo_n[42]
    DIRECTION OUTPUT ;
    USE SIGNAL ;
    PORT
      LAYER M5 ;
        RECT  75.792 302.316 75.816 302.4 ;
    END
  END vo_n[42]
  PIN vo_n[43]
    DIRECTION OUTPUT ;
    USE SIGNAL ;
    PORT
      LAYER M5 ;
        RECT  75.984 302.316 76.008 302.4 ;
    END
  END vo_n[43]
  PIN vo_n[44]
    DIRECTION OUTPUT ;
    USE SIGNAL ;
    PORT
      LAYER M5 ;
        RECT  39.312 302.316 39.336 302.4 ;
    END
  END vo_n[44]
  PIN vo_n[45]
    DIRECTION OUTPUT ;
    USE SIGNAL ;
    PORT
      LAYER M5 ;
        RECT  39.504 302.316 39.528 302.4 ;
    END
  END vo_n[45]
  PIN vo_n[46]
    DIRECTION OUTPUT ;
    USE SIGNAL ;
    PORT
      LAYER M5 ;
        RECT  39.696 302.316 39.72 302.4 ;
    END
  END vo_n[46]
  PIN vo_n[47]
    DIRECTION OUTPUT ;
    USE SIGNAL ;
    PORT
      LAYER M5 ;
        RECT  39.888 302.316 39.912 302.4 ;
    END
  END vo_n[47]
  PIN vo_n[48]
    DIRECTION OUTPUT ;
    USE SIGNAL ;
    PORT
      LAYER M5 ;
        RECT  40.08 302.316 40.104 302.4 ;
    END
  END vo_n[48]
  PIN vo_n[49]
    DIRECTION OUTPUT ;
    USE SIGNAL ;
    PORT
      LAYER M5 ;
        RECT  40.272 302.316 40.296 302.4 ;
    END
  END vo_n[49]
  PIN vo_n[4]
    DIRECTION OUTPUT ;
    USE SIGNAL ;
    PORT
      LAYER M5 ;
        RECT  50.064 302.316 50.088 302.4 ;
    END
  END vo_n[4]
  PIN vo_n[50]
    DIRECTION OUTPUT ;
    USE SIGNAL ;
    PORT
      LAYER M5 ;
        RECT  40.464 302.316 40.488 302.4 ;
    END
  END vo_n[50]
  PIN vo_n[51]
    DIRECTION OUTPUT ;
    USE SIGNAL ;
    PORT
      LAYER M5 ;
        RECT  40.656 302.316 40.68 302.4 ;
    END
  END vo_n[51]
  PIN vo_n[52]
    DIRECTION OUTPUT ;
    USE SIGNAL ;
    PORT
      LAYER M5 ;
        RECT  40.848 302.316 40.872 302.4 ;
    END
  END vo_n[52]
  PIN vo_n[53]
    DIRECTION OUTPUT ;
    USE SIGNAL ;
    PORT
      LAYER M5 ;
        RECT  41.04 302.316 41.064 302.4 ;
    END
  END vo_n[53]
  PIN vo_n[54]
    DIRECTION OUTPUT ;
    USE SIGNAL ;
    PORT
      LAYER M5 ;
        RECT  41.232 302.316 41.256 302.4 ;
    END
  END vo_n[54]
  PIN vo_n[55]
    DIRECTION OUTPUT ;
    USE SIGNAL ;
    PORT
      LAYER M5 ;
        RECT  41.424 302.316 41.448 302.4 ;
    END
  END vo_n[55]
  PIN vo_n[56]
    DIRECTION OUTPUT ;
    USE SIGNAL ;
    PORT
      LAYER M5 ;
        RECT  41.616 302.316 41.64 302.4 ;
    END
  END vo_n[56]
  PIN vo_n[57]
    DIRECTION OUTPUT ;
    USE SIGNAL ;
    PORT
      LAYER M5 ;
        RECT  41.808 302.316 41.832 302.4 ;
    END
  END vo_n[57]
  PIN vo_n[58]
    DIRECTION OUTPUT ;
    USE SIGNAL ;
    PORT
      LAYER M5 ;
        RECT  42 302.316 42.024 302.4 ;
    END
  END vo_n[58]
  PIN vo_n[59]
    DIRECTION OUTPUT ;
    USE SIGNAL ;
    PORT
      LAYER M5 ;
        RECT  42.192 302.316 42.216 302.4 ;
    END
  END vo_n[59]
  PIN vo_n[5]
    DIRECTION OUTPUT ;
    USE SIGNAL ;
    PORT
      LAYER M5 ;
        RECT  50.256 302.316 50.28 302.4 ;
    END
  END vo_n[5]
  PIN vo_n[60]
    DIRECTION OUTPUT ;
    USE SIGNAL ;
    PORT
      LAYER M5 ;
        RECT  42.384 302.316 42.408 302.4 ;
    END
  END vo_n[60]
  PIN vo_n[61]
    DIRECTION OUTPUT ;
    USE SIGNAL ;
    PORT
      LAYER M5 ;
        RECT  42.576 302.316 42.6 302.4 ;
    END
  END vo_n[61]
  PIN vo_n[62]
    DIRECTION OUTPUT ;
    USE SIGNAL ;
    PORT
      LAYER M5 ;
        RECT  42.768 302.316 42.792 302.4 ;
    END
  END vo_n[62]
  PIN vo_n[63]
    DIRECTION OUTPUT ;
    USE SIGNAL ;
    PORT
      LAYER M5 ;
        RECT  42.96 302.316 42.984 302.4 ;
    END
  END vo_n[63]
  PIN vo_n[64]
    DIRECTION OUTPUT ;
    USE SIGNAL ;
    PORT
      LAYER M5 ;
        RECT  43.152 302.316 43.176 302.4 ;
    END
  END vo_n[64]
  PIN vo_n[65]
    DIRECTION OUTPUT ;
    USE SIGNAL ;
    PORT
      LAYER M5 ;
        RECT  43.344 302.316 43.368 302.4 ;
    END
  END vo_n[65]
  PIN vo_n[66]
    DIRECTION OUTPUT ;
    USE SIGNAL ;
    PORT
      LAYER M5 ;
        RECT  43.536 302.316 43.56 302.4 ;
    END
  END vo_n[66]
  PIN vo_n[67]
    DIRECTION OUTPUT ;
    USE SIGNAL ;
    PORT
      LAYER M5 ;
        RECT  43.728 302.316 43.752 302.4 ;
    END
  END vo_n[67]
  PIN vo_n[68]
    DIRECTION OUTPUT ;
    USE SIGNAL ;
    PORT
      LAYER M5 ;
        RECT  43.92 302.316 43.944 302.4 ;
    END
  END vo_n[68]
  PIN vo_n[69]
    DIRECTION OUTPUT ;
    USE SIGNAL ;
    PORT
      LAYER M5 ;
        RECT  44.112 302.316 44.136 302.4 ;
    END
  END vo_n[69]
  PIN vo_n[6]
    DIRECTION OUTPUT ;
    USE SIGNAL ;
    PORT
      LAYER M5 ;
        RECT  50.448 302.316 50.472 302.4 ;
    END
  END vo_n[6]
  PIN vo_n[70]
    DIRECTION OUTPUT ;
    USE SIGNAL ;
    PORT
      LAYER M5 ;
        RECT  44.304 302.316 44.328 302.4 ;
    END
  END vo_n[70]
  PIN vo_n[71]
    DIRECTION OUTPUT ;
    USE SIGNAL ;
    PORT
      LAYER M5 ;
        RECT  44.496 302.316 44.52 302.4 ;
    END
  END vo_n[71]
  PIN vo_n[72]
    DIRECTION OUTPUT ;
    USE SIGNAL ;
    PORT
      LAYER M5 ;
        RECT  44.688 302.316 44.712 302.4 ;
    END
  END vo_n[72]
  PIN vo_n[73]
    DIRECTION OUTPUT ;
    USE SIGNAL ;
    PORT
      LAYER M5 ;
        RECT  44.88 302.316 44.904 302.4 ;
    END
  END vo_n[73]
  PIN vo_n[74]
    DIRECTION OUTPUT ;
    USE SIGNAL ;
    PORT
      LAYER M5 ;
        RECT  45.072 302.316 45.096 302.4 ;
    END
  END vo_n[74]
  PIN vo_n[75]
    DIRECTION OUTPUT ;
    USE SIGNAL ;
    PORT
      LAYER M5 ;
        RECT  45.264 302.316 45.288 302.4 ;
    END
  END vo_n[75]
  PIN vo_n[76]
    DIRECTION OUTPUT ;
    USE SIGNAL ;
    PORT
      LAYER M5 ;
        RECT  51.6 302.316 51.624 302.4 ;
    END
  END vo_n[76]
  PIN vo_n[77]
    DIRECTION OUTPUT ;
    USE SIGNAL ;
    PORT
      LAYER M5 ;
        RECT  51.792 302.316 51.816 302.4 ;
    END
  END vo_n[77]
  PIN vo_n[78]
    DIRECTION OUTPUT ;
    USE SIGNAL ;
    PORT
      LAYER M5 ;
        RECT  51.984 302.316 52.008 302.4 ;
    END
  END vo_n[78]
  PIN vo_n[79]
    DIRECTION OUTPUT ;
    USE SIGNAL ;
    PORT
      LAYER M5 ;
        RECT  52.176 302.316 52.2 302.4 ;
    END
  END vo_n[79]
  PIN vo_n[7]
    DIRECTION OUTPUT ;
    USE SIGNAL ;
    PORT
      LAYER M5 ;
        RECT  50.64 302.316 50.664 302.4 ;
    END
  END vo_n[7]
  PIN vo_n[80]
    DIRECTION OUTPUT ;
    USE SIGNAL ;
    PORT
      LAYER M5 ;
        RECT  52.368 302.316 52.392 302.4 ;
    END
  END vo_n[80]
  PIN vo_n[81]
    DIRECTION OUTPUT ;
    USE SIGNAL ;
    PORT
      LAYER M5 ;
        RECT  52.56 302.316 52.584 302.4 ;
    END
  END vo_n[81]
  PIN vo_n[82]
    DIRECTION OUTPUT ;
    USE SIGNAL ;
    PORT
      LAYER M5 ;
        RECT  52.752 302.316 52.776 302.4 ;
    END
  END vo_n[82]
  PIN vo_n[83]
    DIRECTION OUTPUT ;
    USE SIGNAL ;
    PORT
      LAYER M5 ;
        RECT  52.944 302.316 52.968 302.4 ;
    END
  END vo_n[83]
  PIN vo_n[84]
    DIRECTION OUTPUT ;
    USE SIGNAL ;
    PORT
      LAYER M5 ;
        RECT  53.136 302.316 53.16 302.4 ;
    END
  END vo_n[84]
  PIN vo_n[85]
    DIRECTION OUTPUT ;
    USE SIGNAL ;
    PORT
      LAYER M5 ;
        RECT  53.328 302.316 53.352 302.4 ;
    END
  END vo_n[85]
  PIN vo_n[86]
    DIRECTION OUTPUT ;
    USE SIGNAL ;
    PORT
      LAYER M5 ;
        RECT  53.52 302.316 53.544 302.4 ;
    END
  END vo_n[86]
  PIN vo_n[87]
    DIRECTION OUTPUT ;
    USE SIGNAL ;
    PORT
      LAYER M5 ;
        RECT  53.712 302.316 53.736 302.4 ;
    END
  END vo_n[87]
  PIN vo_n[88]
    DIRECTION OUTPUT ;
    USE SIGNAL ;
    PORT
      LAYER M5 ;
        RECT  53.904 302.316 53.928 302.4 ;
    END
  END vo_n[88]
  PIN vo_n[89]
    DIRECTION OUTPUT ;
    USE SIGNAL ;
    PORT
      LAYER M5 ;
        RECT  54.096 302.316 54.12 302.4 ;
    END
  END vo_n[89]
  PIN vo_n[8]
    DIRECTION OUTPUT ;
    USE SIGNAL ;
    PORT
      LAYER M5 ;
        RECT  50.832 302.316 50.856 302.4 ;
    END
  END vo_n[8]
  PIN vo_n[90]
    DIRECTION OUTPUT ;
    USE SIGNAL ;
    PORT
      LAYER M5 ;
        RECT  54.288 302.316 54.312 302.4 ;
    END
  END vo_n[90]
  PIN vo_n[91]
    DIRECTION OUTPUT ;
    USE SIGNAL ;
    PORT
      LAYER M5 ;
        RECT  54.48 302.316 54.504 302.4 ;
    END
  END vo_n[91]
  PIN vo_n[92]
    DIRECTION OUTPUT ;
    USE SIGNAL ;
    PORT
      LAYER M5 ;
        RECT  54.672 302.316 54.696 302.4 ;
    END
  END vo_n[92]
  PIN vo_n[93]
    DIRECTION OUTPUT ;
    USE SIGNAL ;
    PORT
      LAYER M5 ;
        RECT  54.864 302.316 54.888 302.4 ;
    END
  END vo_n[93]
  PIN vo_n[94]
    DIRECTION OUTPUT ;
    USE SIGNAL ;
    PORT
      LAYER M5 ;
        RECT  55.056 302.316 55.08 302.4 ;
    END
  END vo_n[94]
  PIN vo_n[95]
    DIRECTION OUTPUT ;
    USE SIGNAL ;
    PORT
      LAYER M5 ;
        RECT  55.248 302.316 55.272 302.4 ;
    END
  END vo_n[95]
  PIN vo_n[96]
    DIRECTION OUTPUT ;
    USE SIGNAL ;
    PORT
      LAYER M5 ;
        RECT  55.44 302.316 55.464 302.4 ;
    END
  END vo_n[96]
  PIN vo_n[97]
    DIRECTION OUTPUT ;
    USE SIGNAL ;
    PORT
      LAYER M5 ;
        RECT  55.632 302.316 55.656 302.4 ;
    END
  END vo_n[97]
  PIN vo_n[98]
    DIRECTION OUTPUT ;
    USE SIGNAL ;
    PORT
      LAYER M5 ;
        RECT  55.824 302.316 55.848 302.4 ;
    END
  END vo_n[98]
  PIN vo_n[99]
    DIRECTION OUTPUT ;
    USE SIGNAL ;
    PORT
      LAYER M5 ;
        RECT  56.016 302.316 56.04 302.4 ;
    END
  END vo_n[99]
  PIN vo_n[9]
    DIRECTION OUTPUT ;
    USE SIGNAL ;
    PORT
      LAYER M5 ;
        RECT  51.024 302.316 51.048 302.4 ;
    END
  END vo_n[9]
  PIN xd_b[0]
    DIRECTION OUTPUT ;
    USE SIGNAL ;
    PORT
      LAYER M4 ;
        RECT  345.516 115.92 345.6 115.944 ;
    END
  END xd_b[0]
  PIN xd_b[10]
    DIRECTION OUTPUT ;
    USE SIGNAL ;
    PORT
      LAYER M4 ;
        RECT  345.516 117.84 345.6 117.864 ;
    END
  END xd_b[10]
  PIN xd_b[11]
    DIRECTION OUTPUT ;
    USE SIGNAL ;
    PORT
      LAYER M4 ;
        RECT  345.516 118.032 345.6 118.056 ;
    END
  END xd_b[11]
  PIN xd_b[12]
    DIRECTION OUTPUT ;
    USE SIGNAL ;
    PORT
      LAYER M4 ;
        RECT  345.516 118.224 345.6 118.248 ;
    END
  END xd_b[12]
  PIN xd_b[13]
    DIRECTION OUTPUT ;
    USE SIGNAL ;
    PORT
      LAYER M4 ;
        RECT  345.516 118.416 345.6 118.44 ;
    END
  END xd_b[13]
  PIN xd_b[14]
    DIRECTION OUTPUT ;
    USE SIGNAL ;
    PORT
      LAYER M4 ;
        RECT  345.516 118.608 345.6 118.632 ;
    END
  END xd_b[14]
  PIN xd_b[15]
    DIRECTION OUTPUT ;
    USE SIGNAL ;
    PORT
      LAYER M4 ;
        RECT  345.516 118.8 345.6 118.824 ;
    END
  END xd_b[15]
  PIN xd_b[16]
    DIRECTION OUTPUT ;
    USE SIGNAL ;
    PORT
      LAYER M4 ;
        RECT  345.516 118.992 345.6 119.016 ;
    END
  END xd_b[16]
  PIN xd_b[17]
    DIRECTION OUTPUT ;
    USE SIGNAL ;
    PORT
      LAYER M4 ;
        RECT  345.516 119.184 345.6 119.208 ;
    END
  END xd_b[17]
  PIN xd_b[18]
    DIRECTION OUTPUT ;
    USE SIGNAL ;
    PORT
      LAYER M4 ;
        RECT  345.516 119.376 345.6 119.4 ;
    END
  END xd_b[18]
  PIN xd_b[19]
    DIRECTION OUTPUT ;
    USE SIGNAL ;
    PORT
      LAYER M4 ;
        RECT  345.516 119.568 345.6 119.592 ;
    END
  END xd_b[19]
  PIN xd_b[1]
    DIRECTION OUTPUT ;
    USE SIGNAL ;
    PORT
      LAYER M4 ;
        RECT  345.516 116.112 345.6 116.136 ;
    END
  END xd_b[1]
  PIN xd_b[20]
    DIRECTION OUTPUT ;
    USE SIGNAL ;
    PORT
      LAYER M4 ;
        RECT  345.516 119.76 345.6 119.784 ;
    END
  END xd_b[20]
  PIN xd_b[21]
    DIRECTION OUTPUT ;
    USE SIGNAL ;
    PORT
      LAYER M4 ;
        RECT  345.516 119.952 345.6 119.976 ;
    END
  END xd_b[21]
  PIN xd_b[22]
    DIRECTION OUTPUT ;
    USE SIGNAL ;
    PORT
      LAYER M4 ;
        RECT  345.516 120.144 345.6 120.168 ;
    END
  END xd_b[22]
  PIN xd_b[23]
    DIRECTION OUTPUT ;
    USE SIGNAL ;
    PORT
      LAYER M4 ;
        RECT  345.516 120.336 345.6 120.36 ;
    END
  END xd_b[23]
  PIN xd_b[24]
    DIRECTION OUTPUT ;
    USE SIGNAL ;
    PORT
      LAYER M4 ;
        RECT  345.516 120.528 345.6 120.552 ;
    END
  END xd_b[24]
  PIN xd_b[25]
    DIRECTION OUTPUT ;
    USE SIGNAL ;
    PORT
      LAYER M4 ;
        RECT  345.516 120.72 345.6 120.744 ;
    END
  END xd_b[25]
  PIN xd_b[26]
    DIRECTION OUTPUT ;
    USE SIGNAL ;
    PORT
      LAYER M4 ;
        RECT  345.516 120.912 345.6 120.936 ;
    END
  END xd_b[26]
  PIN xd_b[27]
    DIRECTION OUTPUT ;
    USE SIGNAL ;
    PORT
      LAYER M4 ;
        RECT  345.516 121.104 345.6 121.128 ;
    END
  END xd_b[27]
  PIN xd_b[28]
    DIRECTION OUTPUT ;
    USE SIGNAL ;
    PORT
      LAYER M4 ;
        RECT  345.516 121.296 345.6 121.32 ;
    END
  END xd_b[28]
  PIN xd_b[29]
    DIRECTION OUTPUT ;
    USE SIGNAL ;
    PORT
      LAYER M4 ;
        RECT  345.516 121.488 345.6 121.512 ;
    END
  END xd_b[29]
  PIN xd_b[2]
    DIRECTION OUTPUT ;
    USE SIGNAL ;
    PORT
      LAYER M4 ;
        RECT  345.516 116.304 345.6 116.328 ;
    END
  END xd_b[2]
  PIN xd_b[30]
    DIRECTION OUTPUT ;
    USE SIGNAL ;
    PORT
      LAYER M4 ;
        RECT  345.516 121.68 345.6 121.704 ;
    END
  END xd_b[30]
  PIN xd_b[31]
    DIRECTION OUTPUT ;
    USE SIGNAL ;
    PORT
      LAYER M4 ;
        RECT  345.516 121.872 345.6 121.896 ;
    END
  END xd_b[31]
  PIN xd_b[3]
    DIRECTION OUTPUT ;
    USE SIGNAL ;
    PORT
      LAYER M4 ;
        RECT  345.516 116.496 345.6 116.52 ;
    END
  END xd_b[3]
  PIN xd_b[4]
    DIRECTION OUTPUT ;
    USE SIGNAL ;
    PORT
      LAYER M4 ;
        RECT  345.516 116.688 345.6 116.712 ;
    END
  END xd_b[4]
  PIN xd_b[5]
    DIRECTION OUTPUT ;
    USE SIGNAL ;
    PORT
      LAYER M4 ;
        RECT  345.516 116.88 345.6 116.904 ;
    END
  END xd_b[5]
  PIN xd_b[6]
    DIRECTION OUTPUT ;
    USE SIGNAL ;
    PORT
      LAYER M4 ;
        RECT  345.516 117.072 345.6 117.096 ;
    END
  END xd_b[6]
  PIN xd_b[7]
    DIRECTION OUTPUT ;
    USE SIGNAL ;
    PORT
      LAYER M4 ;
        RECT  345.516 117.264 345.6 117.288 ;
    END
  END xd_b[7]
  PIN xd_b[8]
    DIRECTION OUTPUT ;
    USE SIGNAL ;
    PORT
      LAYER M4 ;
        RECT  345.516 117.456 345.6 117.48 ;
    END
  END xd_b[8]
  PIN xd_b[9]
    DIRECTION OUTPUT ;
    USE SIGNAL ;
    PORT
      LAYER M4 ;
        RECT  345.516 117.648 345.6 117.672 ;
    END
  END xd_b[9]
  PIN xd_v
    DIRECTION OUTPUT ;
    USE SIGNAL ;
    PORT
      LAYER M4 ;
        RECT  345.516 122.064 345.6 122.088 ;
    END
  END xd_v
  PIN xe_v
    DIRECTION OUTPUT ;
    USE SIGNAL ;
    PORT
      LAYER M4 ;
        RECT  345.516 122.256 345.6 122.28 ;
    END
  END xe_v
  PIN xe_x[0]
    DIRECTION OUTPUT ;
    USE SIGNAL ;
    PORT
      LAYER M4 ;
        RECT  345.516 122.448 345.6 122.472 ;
    END
  END xe_x[0]
  PIN xe_x[10]
    DIRECTION OUTPUT ;
    USE SIGNAL ;
    PORT
      LAYER M4 ;
        RECT  345.516 124.368 345.6 124.392 ;
    END
  END xe_x[10]
  PIN xe_x[11]
    DIRECTION OUTPUT ;
    USE SIGNAL ;
    PORT
      LAYER M4 ;
        RECT  345.516 124.56 345.6 124.584 ;
    END
  END xe_x[11]
  PIN xe_x[12]
    DIRECTION OUTPUT ;
    USE SIGNAL ;
    PORT
      LAYER M4 ;
        RECT  345.516 124.752 345.6 124.776 ;
    END
  END xe_x[12]
  PIN xe_x[13]
    DIRECTION OUTPUT ;
    USE SIGNAL ;
    PORT
      LAYER M4 ;
        RECT  345.516 124.944 345.6 124.968 ;
    END
  END xe_x[13]
  PIN xe_x[14]
    DIRECTION OUTPUT ;
    USE SIGNAL ;
    PORT
      LAYER M4 ;
        RECT  345.516 125.136 345.6 125.16 ;
    END
  END xe_x[14]
  PIN xe_x[15]
    DIRECTION OUTPUT ;
    USE SIGNAL ;
    PORT
      LAYER M4 ;
        RECT  345.516 125.328 345.6 125.352 ;
    END
  END xe_x[15]
  PIN xe_x[16]
    DIRECTION OUTPUT ;
    USE SIGNAL ;
    PORT
      LAYER M4 ;
        RECT  345.516 125.52 345.6 125.544 ;
    END
  END xe_x[16]
  PIN xe_x[17]
    DIRECTION OUTPUT ;
    USE SIGNAL ;
    PORT
      LAYER M4 ;
        RECT  345.516 125.712 345.6 125.736 ;
    END
  END xe_x[17]
  PIN xe_x[18]
    DIRECTION OUTPUT ;
    USE SIGNAL ;
    PORT
      LAYER M4 ;
        RECT  345.516 125.904 345.6 125.928 ;
    END
  END xe_x[18]
  PIN xe_x[19]
    DIRECTION OUTPUT ;
    USE SIGNAL ;
    PORT
      LAYER M4 ;
        RECT  345.516 126.096 345.6 126.12 ;
    END
  END xe_x[19]
  PIN xe_x[1]
    DIRECTION OUTPUT ;
    USE SIGNAL ;
    PORT
      LAYER M4 ;
        RECT  345.516 122.64 345.6 122.664 ;
    END
  END xe_x[1]
  PIN xe_x[20]
    DIRECTION OUTPUT ;
    USE SIGNAL ;
    PORT
      LAYER M4 ;
        RECT  345.516 126.288 345.6 126.312 ;
    END
  END xe_x[20]
  PIN xe_x[21]
    DIRECTION OUTPUT ;
    USE SIGNAL ;
    PORT
      LAYER M4 ;
        RECT  345.516 126.48 345.6 126.504 ;
    END
  END xe_x[21]
  PIN xe_x[22]
    DIRECTION OUTPUT ;
    USE SIGNAL ;
    PORT
      LAYER M4 ;
        RECT  345.516 126.672 345.6 126.696 ;
    END
  END xe_x[22]
  PIN xe_x[23]
    DIRECTION OUTPUT ;
    USE SIGNAL ;
    PORT
      LAYER M4 ;
        RECT  345.516 126.864 345.6 126.888 ;
    END
  END xe_x[23]
  PIN xe_x[24]
    DIRECTION OUTPUT ;
    USE SIGNAL ;
    PORT
      LAYER M4 ;
        RECT  345.516 127.056 345.6 127.08 ;
    END
  END xe_x[24]
  PIN xe_x[25]
    DIRECTION OUTPUT ;
    USE SIGNAL ;
    PORT
      LAYER M4 ;
        RECT  345.516 127.248 345.6 127.272 ;
    END
  END xe_x[25]
  PIN xe_x[26]
    DIRECTION OUTPUT ;
    USE SIGNAL ;
    PORT
      LAYER M4 ;
        RECT  345.516 127.44 345.6 127.464 ;
    END
  END xe_x[26]
  PIN xe_x[27]
    DIRECTION OUTPUT ;
    USE SIGNAL ;
    PORT
      LAYER M4 ;
        RECT  345.516 127.632 345.6 127.656 ;
    END
  END xe_x[27]
  PIN xe_x[28]
    DIRECTION OUTPUT ;
    USE SIGNAL ;
    PORT
      LAYER M4 ;
        RECT  345.516 127.824 345.6 127.848 ;
    END
  END xe_x[28]
  PIN xe_x[29]
    DIRECTION OUTPUT ;
    USE SIGNAL ;
    PORT
      LAYER M4 ;
        RECT  345.516 128.016 345.6 128.04 ;
    END
  END xe_x[29]
  PIN xe_x[2]
    DIRECTION OUTPUT ;
    USE SIGNAL ;
    PORT
      LAYER M4 ;
        RECT  345.516 122.832 345.6 122.856 ;
    END
  END xe_x[2]
  PIN xe_x[30]
    DIRECTION OUTPUT ;
    USE SIGNAL ;
    PORT
      LAYER M4 ;
        RECT  345.516 134.352 345.6 134.376 ;
    END
  END xe_x[30]
  PIN xe_x[31]
    DIRECTION OUTPUT ;
    USE SIGNAL ;
    PORT
      LAYER M4 ;
        RECT  345.516 134.544 345.6 134.568 ;
    END
  END xe_x[31]
  PIN xe_x[3]
    DIRECTION OUTPUT ;
    USE SIGNAL ;
    PORT
      LAYER M4 ;
        RECT  345.516 123.024 345.6 123.048 ;
    END
  END xe_x[3]
  PIN xe_x[4]
    DIRECTION OUTPUT ;
    USE SIGNAL ;
    PORT
      LAYER M4 ;
        RECT  345.516 123.216 345.6 123.24 ;
    END
  END xe_x[4]
  PIN xe_x[5]
    DIRECTION OUTPUT ;
    USE SIGNAL ;
    PORT
      LAYER M4 ;
        RECT  345.516 123.408 345.6 123.432 ;
    END
  END xe_x[5]
  PIN xe_x[6]
    DIRECTION OUTPUT ;
    USE SIGNAL ;
    PORT
      LAYER M4 ;
        RECT  345.516 123.6 345.6 123.624 ;
    END
  END xe_x[6]
  PIN xe_x[7]
    DIRECTION OUTPUT ;
    USE SIGNAL ;
    PORT
      LAYER M4 ;
        RECT  345.516 123.792 345.6 123.816 ;
    END
  END xe_x[7]
  PIN xe_x[8]
    DIRECTION OUTPUT ;
    USE SIGNAL ;
    PORT
      LAYER M4 ;
        RECT  345.516 123.984 345.6 124.008 ;
    END
  END xe_x[8]
  PIN xe_x[9]
    DIRECTION OUTPUT ;
    USE SIGNAL ;
    PORT
      LAYER M4 ;
        RECT  345.516 124.176 345.6 124.2 ;
    END
  END xe_x[9]
  PIN yd_f
    DIRECTION INPUT ;
    USE SIGNAL ;
    PORT
      LAYER M4 ;
        RECT  345.516 134.736 345.6 134.76 ;
    END
  END yd_f
  PIN yd_v
    DIRECTION INPUT ;
    USE SIGNAL ;
    PORT
      LAYER M4 ;
        RECT  345.516 134.928 345.6 134.952 ;
    END
  END yd_v
  PIN yd_y[0]
    DIRECTION INPUT ;
    USE SIGNAL ;
    PORT
      LAYER M4 ;
        RECT  345.516 135.12 345.6 135.144 ;
    END
  END yd_y[0]
  PIN yd_y[10]
    DIRECTION INPUT ;
    USE SIGNAL ;
    PORT
      LAYER M4 ;
        RECT  345.516 137.04 345.6 137.064 ;
    END
  END yd_y[10]
  PIN yd_y[11]
    DIRECTION INPUT ;
    USE SIGNAL ;
    PORT
      LAYER M4 ;
        RECT  345.516 137.232 345.6 137.256 ;
    END
  END yd_y[11]
  PIN yd_y[12]
    DIRECTION INPUT ;
    USE SIGNAL ;
    PORT
      LAYER M4 ;
        RECT  345.516 137.424 345.6 137.448 ;
    END
  END yd_y[12]
  PIN yd_y[13]
    DIRECTION INPUT ;
    USE SIGNAL ;
    PORT
      LAYER M4 ;
        RECT  345.516 137.616 345.6 137.64 ;
    END
  END yd_y[13]
  PIN yd_y[14]
    DIRECTION INPUT ;
    USE SIGNAL ;
    PORT
      LAYER M4 ;
        RECT  345.516 137.808 345.6 137.832 ;
    END
  END yd_y[14]
  PIN yd_y[15]
    DIRECTION INPUT ;
    USE SIGNAL ;
    PORT
      LAYER M4 ;
        RECT  345.516 138 345.6 138.024 ;
    END
  END yd_y[15]
  PIN yd_y[16]
    DIRECTION INPUT ;
    USE SIGNAL ;
    PORT
      LAYER M4 ;
        RECT  345.516 138.192 345.6 138.216 ;
    END
  END yd_y[16]
  PIN yd_y[17]
    DIRECTION INPUT ;
    USE SIGNAL ;
    PORT
      LAYER M4 ;
        RECT  345.516 138.384 345.6 138.408 ;
    END
  END yd_y[17]
  PIN yd_y[18]
    DIRECTION INPUT ;
    USE SIGNAL ;
    PORT
      LAYER M4 ;
        RECT  345.516 138.576 345.6 138.6 ;
    END
  END yd_y[18]
  PIN yd_y[19]
    DIRECTION INPUT ;
    USE SIGNAL ;
    PORT
      LAYER M4 ;
        RECT  345.516 138.768 345.6 138.792 ;
    END
  END yd_y[19]
  PIN yd_y[1]
    DIRECTION INPUT ;
    USE SIGNAL ;
    PORT
      LAYER M4 ;
        RECT  345.516 135.312 345.6 135.336 ;
    END
  END yd_y[1]
  PIN yd_y[20]
    DIRECTION INPUT ;
    USE SIGNAL ;
    PORT
      LAYER M4 ;
        RECT  345.516 138.96 345.6 138.984 ;
    END
  END yd_y[20]
  PIN yd_y[21]
    DIRECTION INPUT ;
    USE SIGNAL ;
    PORT
      LAYER M4 ;
        RECT  345.516 139.152 345.6 139.176 ;
    END
  END yd_y[21]
  PIN yd_y[22]
    DIRECTION INPUT ;
    USE SIGNAL ;
    PORT
      LAYER M4 ;
        RECT  345.516 139.344 345.6 139.368 ;
    END
  END yd_y[22]
  PIN yd_y[23]
    DIRECTION INPUT ;
    USE SIGNAL ;
    PORT
      LAYER M4 ;
        RECT  345.516 139.536 345.6 139.56 ;
    END
  END yd_y[23]
  PIN yd_y[24]
    DIRECTION INPUT ;
    USE SIGNAL ;
    PORT
      LAYER M4 ;
        RECT  345.516 139.728 345.6 139.752 ;
    END
  END yd_y[24]
  PIN yd_y[25]
    DIRECTION INPUT ;
    USE SIGNAL ;
    PORT
      LAYER M4 ;
        RECT  345.516 139.92 345.6 139.944 ;
    END
  END yd_y[25]
  PIN yd_y[26]
    DIRECTION INPUT ;
    USE SIGNAL ;
    PORT
      LAYER M4 ;
        RECT  345.516 140.112 345.6 140.136 ;
    END
  END yd_y[26]
  PIN yd_y[27]
    DIRECTION INPUT ;
    USE SIGNAL ;
    PORT
      LAYER M4 ;
        RECT  345.516 140.304 345.6 140.328 ;
    END
  END yd_y[27]
  PIN yd_y[28]
    DIRECTION INPUT ;
    USE SIGNAL ;
    PORT
      LAYER M4 ;
        RECT  345.516 146.64 345.6 146.664 ;
    END
  END yd_y[28]
  PIN yd_y[29]
    DIRECTION INPUT ;
    USE SIGNAL ;
    PORT
      LAYER M4 ;
        RECT  345.516 146.832 345.6 146.856 ;
    END
  END yd_y[29]
  PIN yd_y[2]
    DIRECTION INPUT ;
    USE SIGNAL ;
    PORT
      LAYER M4 ;
        RECT  345.516 135.504 345.6 135.528 ;
    END
  END yd_y[2]
  PIN yd_y[30]
    DIRECTION INPUT ;
    USE SIGNAL ;
    PORT
      LAYER M4 ;
        RECT  345.516 147.024 345.6 147.048 ;
    END
  END yd_y[30]
  PIN yd_y[31]
    DIRECTION INPUT ;
    USE SIGNAL ;
    PORT
      LAYER M4 ;
        RECT  345.516 147.216 345.6 147.24 ;
    END
  END yd_y[31]
  PIN yd_y[3]
    DIRECTION INPUT ;
    USE SIGNAL ;
    PORT
      LAYER M4 ;
        RECT  345.516 135.696 345.6 135.72 ;
    END
  END yd_y[3]
  PIN yd_y[4]
    DIRECTION INPUT ;
    USE SIGNAL ;
    PORT
      LAYER M4 ;
        RECT  345.516 135.888 345.6 135.912 ;
    END
  END yd_y[4]
  PIN yd_y[5]
    DIRECTION INPUT ;
    USE SIGNAL ;
    PORT
      LAYER M4 ;
        RECT  345.516 136.08 345.6 136.104 ;
    END
  END yd_y[5]
  PIN yd_y[6]
    DIRECTION INPUT ;
    USE SIGNAL ;
    PORT
      LAYER M4 ;
        RECT  345.516 136.272 345.6 136.296 ;
    END
  END yd_y[6]
  PIN yd_y[7]
    DIRECTION INPUT ;
    USE SIGNAL ;
    PORT
      LAYER M4 ;
        RECT  345.516 136.464 345.6 136.488 ;
    END
  END yd_y[7]
  PIN yd_y[8]
    DIRECTION INPUT ;
    USE SIGNAL ;
    PORT
      LAYER M4 ;
        RECT  345.516 136.656 345.6 136.68 ;
    END
  END yd_y[8]
  PIN yd_y[9]
    DIRECTION INPUT ;
    USE SIGNAL ;
    PORT
      LAYER M4 ;
        RECT  345.516 136.848 345.6 136.872 ;
    END
  END yd_y[9]
  PIN ye_f
    DIRECTION INPUT ;
    USE SIGNAL ;
    PORT
      LAYER M4 ;
        RECT  345.516 147.408 345.6 147.432 ;
    END
  END ye_f
  PIN ye_v
    DIRECTION INPUT ;
    USE SIGNAL ;
    PORT
      LAYER M4 ;
        RECT  345.516 147.6 345.6 147.624 ;
    END
  END ye_v
  PIN ye_y[0]
    DIRECTION INPUT ;
    USE SIGNAL ;
    PORT
      LAYER M4 ;
        RECT  345.516 147.792 345.6 147.816 ;
    END
  END ye_y[0]
  PIN ye_y[10]
    DIRECTION INPUT ;
    USE SIGNAL ;
    PORT
      LAYER M4 ;
        RECT  345.516 149.712 345.6 149.736 ;
    END
  END ye_y[10]
  PIN ye_y[11]
    DIRECTION INPUT ;
    USE SIGNAL ;
    PORT
      LAYER M4 ;
        RECT  345.516 149.904 345.6 149.928 ;
    END
  END ye_y[11]
  PIN ye_y[12]
    DIRECTION INPUT ;
    USE SIGNAL ;
    PORT
      LAYER M4 ;
        RECT  345.516 150.096 345.6 150.12 ;
    END
  END ye_y[12]
  PIN ye_y[13]
    DIRECTION INPUT ;
    USE SIGNAL ;
    PORT
      LAYER M4 ;
        RECT  345.516 150.288 345.6 150.312 ;
    END
  END ye_y[13]
  PIN ye_y[14]
    DIRECTION INPUT ;
    USE SIGNAL ;
    PORT
      LAYER M4 ;
        RECT  345.516 150.48 345.6 150.504 ;
    END
  END ye_y[14]
  PIN ye_y[15]
    DIRECTION INPUT ;
    USE SIGNAL ;
    PORT
      LAYER M4 ;
        RECT  345.516 150.672 345.6 150.696 ;
    END
  END ye_y[15]
  PIN ye_y[16]
    DIRECTION INPUT ;
    USE SIGNAL ;
    PORT
      LAYER M4 ;
        RECT  345.516 150.864 345.6 150.888 ;
    END
  END ye_y[16]
  PIN ye_y[17]
    DIRECTION INPUT ;
    USE SIGNAL ;
    PORT
      LAYER M4 ;
        RECT  345.516 151.056 345.6 151.08 ;
    END
  END ye_y[17]
  PIN ye_y[18]
    DIRECTION INPUT ;
    USE SIGNAL ;
    PORT
      LAYER M4 ;
        RECT  345.516 151.248 345.6 151.272 ;
    END
  END ye_y[18]
  PIN ye_y[19]
    DIRECTION INPUT ;
    USE SIGNAL ;
    PORT
      LAYER M4 ;
        RECT  345.516 151.44 345.6 151.464 ;
    END
  END ye_y[19]
  PIN ye_y[1]
    DIRECTION INPUT ;
    USE SIGNAL ;
    PORT
      LAYER M4 ;
        RECT  345.516 147.984 345.6 148.008 ;
    END
  END ye_y[1]
  PIN ye_y[20]
    DIRECTION INPUT ;
    USE SIGNAL ;
    PORT
      LAYER M4 ;
        RECT  345.516 151.632 345.6 151.656 ;
    END
  END ye_y[20]
  PIN ye_y[21]
    DIRECTION INPUT ;
    USE SIGNAL ;
    PORT
      LAYER M4 ;
        RECT  345.516 151.824 345.6 151.848 ;
    END
  END ye_y[21]
  PIN ye_y[22]
    DIRECTION INPUT ;
    USE SIGNAL ;
    PORT
      LAYER M4 ;
        RECT  345.516 152.016 345.6 152.04 ;
    END
  END ye_y[22]
  PIN ye_y[23]
    DIRECTION INPUT ;
    USE SIGNAL ;
    PORT
      LAYER M4 ;
        RECT  345.516 152.208 345.6 152.232 ;
    END
  END ye_y[23]
  PIN ye_y[24]
    DIRECTION INPUT ;
    USE SIGNAL ;
    PORT
      LAYER M4 ;
        RECT  345.516 152.4 345.6 152.424 ;
    END
  END ye_y[24]
  PIN ye_y[25]
    DIRECTION INPUT ;
    USE SIGNAL ;
    PORT
      LAYER M4 ;
        RECT  345.516 152.592 345.6 152.616 ;
    END
  END ye_y[25]
  PIN ye_y[26]
    DIRECTION INPUT ;
    USE SIGNAL ;
    PORT
      LAYER M4 ;
        RECT  345.516 140.496 345.6 140.52 ;
    END
  END ye_y[26]
  PIN ye_y[27]
    DIRECTION INPUT ;
    USE SIGNAL ;
    PORT
      LAYER M4 ;
        RECT  345.516 140.688 345.6 140.712 ;
    END
  END ye_y[27]
  PIN ye_y[28]
    DIRECTION INPUT ;
    USE SIGNAL ;
    PORT
      LAYER M4 ;
        RECT  345.516 140.88 345.6 140.904 ;
    END
  END ye_y[28]
  PIN ye_y[29]
    DIRECTION INPUT ;
    USE SIGNAL ;
    PORT
      LAYER M4 ;
        RECT  345.516 141.072 345.6 141.096 ;
    END
  END ye_y[29]
  PIN ye_y[2]
    DIRECTION INPUT ;
    USE SIGNAL ;
    PORT
      LAYER M4 ;
        RECT  345.516 148.176 345.6 148.2 ;
    END
  END ye_y[2]
  PIN ye_y[30]
    DIRECTION INPUT ;
    USE SIGNAL ;
    PORT
      LAYER M4 ;
        RECT  345.516 141.264 345.6 141.288 ;
    END
  END ye_y[30]
  PIN ye_y[31]
    DIRECTION INPUT ;
    USE SIGNAL ;
    PORT
      LAYER M4 ;
        RECT  345.516 141.456 345.6 141.48 ;
    END
  END ye_y[31]
  PIN ye_y[3]
    DIRECTION INPUT ;
    USE SIGNAL ;
    PORT
      LAYER M4 ;
        RECT  345.516 148.368 345.6 148.392 ;
    END
  END ye_y[3]
  PIN ye_y[4]
    DIRECTION INPUT ;
    USE SIGNAL ;
    PORT
      LAYER M4 ;
        RECT  345.516 148.56 345.6 148.584 ;
    END
  END ye_y[4]
  PIN ye_y[5]
    DIRECTION INPUT ;
    USE SIGNAL ;
    PORT
      LAYER M4 ;
        RECT  345.516 148.752 345.6 148.776 ;
    END
  END ye_y[5]
  PIN ye_y[6]
    DIRECTION INPUT ;
    USE SIGNAL ;
    PORT
      LAYER M4 ;
        RECT  345.516 148.944 345.6 148.968 ;
    END
  END ye_y[6]
  PIN ye_y[7]
    DIRECTION INPUT ;
    USE SIGNAL ;
    PORT
      LAYER M4 ;
        RECT  345.516 149.136 345.6 149.16 ;
    END
  END ye_y[7]
  PIN ye_y[8]
    DIRECTION INPUT ;
    USE SIGNAL ;
    PORT
      LAYER M4 ;
        RECT  345.516 149.328 345.6 149.352 ;
    END
  END ye_y[8]
  PIN ye_y[9]
    DIRECTION INPUT ;
    USE SIGNAL ;
    PORT
      LAYER M4 ;
        RECT  345.516 149.52 345.6 149.544 ;
    END
  END ye_y[9]
  PIN VDD
    DIRECTION INOUT ;
    USE POWER ;
    PORT
      LAYER M5 ;
        RECT  342.792 2.151 342.912 300.249 ;
        RECT  337.392 2.151 337.512 300.249 ;
        RECT  331.992 2.151 332.112 300.249 ;
        RECT  326.592 2.151 326.712 300.249 ;
        RECT  321.192 2.151 321.312 300.249 ;
        RECT  315.792 2.151 315.912 300.249 ;
        RECT  310.392 2.151 310.512 300.249 ;
        RECT  304.992 2.151 305.112 300.249 ;
        RECT  299.592 2.151 299.712 300.249 ;
        RECT  294.192 2.151 294.312 300.249 ;
        RECT  288.792 2.151 288.912 300.249 ;
        RECT  283.392 2.151 283.512 300.249 ;
        RECT  277.992 2.151 278.112 300.249 ;
        RECT  272.592 2.151 272.712 300.249 ;
        RECT  267.192 2.151 267.312 300.249 ;
        RECT  261.792 2.151 261.912 300.249 ;
        RECT  256.392 2.151 256.512 300.249 ;
        RECT  250.992 2.151 251.112 300.249 ;
        RECT  245.592 2.151 245.712 300.249 ;
        RECT  240.192 2.151 240.312 300.249 ;
        RECT  234.792 2.151 234.912 300.249 ;
        RECT  229.392 2.151 229.512 300.249 ;
        RECT  223.992 2.151 224.112 300.249 ;
        RECT  218.592 2.151 218.712 300.249 ;
        RECT  213.192 2.151 213.312 300.249 ;
        RECT  207.792 2.151 207.912 300.249 ;
        RECT  202.392 2.151 202.512 300.249 ;
        RECT  196.992 2.151 197.112 300.249 ;
        RECT  191.592 2.151 191.712 300.249 ;
        RECT  186.192 2.151 186.312 300.249 ;
        RECT  180.792 2.151 180.912 300.249 ;
        RECT  175.392 2.151 175.512 300.249 ;
        RECT  169.992 2.151 170.112 300.249 ;
        RECT  164.592 2.151 164.712 300.249 ;
        RECT  159.192 2.151 159.312 300.249 ;
        RECT  153.792 2.151 153.912 300.249 ;
        RECT  148.392 2.151 148.512 300.249 ;
        RECT  142.992 2.151 143.112 300.249 ;
        RECT  137.592 2.151 137.712 300.249 ;
        RECT  132.192 2.151 132.312 300.249 ;
        RECT  126.792 2.151 126.912 300.249 ;
        RECT  121.392 2.151 121.512 300.249 ;
        RECT  115.992 2.151 116.112 300.249 ;
        RECT  110.592 2.151 110.712 300.249 ;
        RECT  105.192 2.151 105.312 300.249 ;
        RECT  99.792 2.151 99.912 300.249 ;
        RECT  94.392 2.151 94.512 300.249 ;
        RECT  88.992 2.151 89.112 300.249 ;
        RECT  83.592 2.151 83.712 300.249 ;
        RECT  78.192 2.151 78.312 300.249 ;
        RECT  72.792 2.151 72.912 300.249 ;
        RECT  67.392 2.151 67.512 300.249 ;
        RECT  61.992 2.151 62.112 300.249 ;
        RECT  56.592 2.151 56.712 300.249 ;
        RECT  51.192 2.151 51.312 300.249 ;
        RECT  45.792 2.151 45.912 300.249 ;
        RECT  40.392 2.151 40.512 300.249 ;
        RECT  34.992 2.151 35.112 300.249 ;
        RECT  29.592 2.151 29.712 300.249 ;
        RECT  24.192 2.151 24.312 300.249 ;
        RECT  18.792 2.151 18.912 300.249 ;
        RECT  13.392 2.151 13.512 300.249 ;
        RECT  7.992 2.151 8.112 300.249 ;
        RECT  2.592 2.151 2.712 300.249 ;
    END
  END VDD
  PIN VSS
    DIRECTION INOUT ;
    USE GROUND ;
    PORT
      LAYER M5 ;
        RECT  342.6 2.137 342.72 300.263 ;
        RECT  337.2 2.137 337.32 300.263 ;
        RECT  331.8 2.137 331.92 300.263 ;
        RECT  326.4 2.137 326.52 300.263 ;
        RECT  321 2.137 321.12 300.263 ;
        RECT  315.6 2.137 315.72 300.263 ;
        RECT  310.2 2.137 310.32 300.263 ;
        RECT  304.8 2.137 304.92 300.263 ;
        RECT  299.4 2.137 299.52 300.263 ;
        RECT  294 2.137 294.12 300.263 ;
        RECT  288.6 2.137 288.72 300.263 ;
        RECT  283.2 2.137 283.32 300.263 ;
        RECT  277.8 2.137 277.92 300.263 ;
        RECT  272.4 2.137 272.52 300.263 ;
        RECT  267 2.137 267.12 300.263 ;
        RECT  261.6 2.137 261.72 300.263 ;
        RECT  256.2 2.137 256.32 300.263 ;
        RECT  250.8 2.137 250.92 300.263 ;
        RECT  245.4 2.137 245.52 300.263 ;
        RECT  240 2.137 240.12 300.263 ;
        RECT  234.6 2.137 234.72 300.263 ;
        RECT  229.2 2.137 229.32 300.263 ;
        RECT  223.8 2.137 223.92 300.263 ;
        RECT  218.4 2.137 218.52 300.263 ;
        RECT  213 2.137 213.12 300.263 ;
        RECT  207.6 2.137 207.72 300.263 ;
        RECT  202.2 2.137 202.32 300.263 ;
        RECT  196.8 2.137 196.92 300.263 ;
        RECT  191.4 2.137 191.52 300.263 ;
        RECT  186 2.137 186.12 300.263 ;
        RECT  180.6 2.137 180.72 300.263 ;
        RECT  175.2 2.137 175.32 300.263 ;
        RECT  169.8 2.137 169.92 300.263 ;
        RECT  164.4 2.137 164.52 300.263 ;
        RECT  159 2.137 159.12 300.263 ;
        RECT  153.6 2.137 153.72 300.263 ;
        RECT  148.2 2.137 148.32 300.263 ;
        RECT  142.8 2.137 142.92 300.263 ;
        RECT  137.4 2.137 137.52 300.263 ;
        RECT  132 2.137 132.12 300.263 ;
        RECT  126.6 2.137 126.72 300.263 ;
        RECT  121.2 2.137 121.32 300.263 ;
        RECT  115.8 2.137 115.92 300.263 ;
        RECT  110.4 2.137 110.52 300.263 ;
        RECT  105 2.137 105.12 300.263 ;
        RECT  99.6 2.137 99.72 300.263 ;
        RECT  94.2 2.137 94.32 300.263 ;
        RECT  88.8 2.137 88.92 300.263 ;
        RECT  83.4 2.137 83.52 300.263 ;
        RECT  78 2.137 78.12 300.263 ;
        RECT  72.6 2.137 72.72 300.263 ;
        RECT  67.2 2.137 67.32 300.263 ;
        RECT  61.8 2.137 61.92 300.263 ;
        RECT  56.4 2.137 56.52 300.263 ;
        RECT  51 2.137 51.12 300.263 ;
        RECT  45.6 2.137 45.72 300.263 ;
        RECT  40.2 2.137 40.32 300.263 ;
        RECT  34.8 2.137 34.92 300.263 ;
        RECT  29.4 2.137 29.52 300.263 ;
        RECT  24 2.137 24.12 300.263 ;
        RECT  18.6 2.137 18.72 300.263 ;
        RECT  13.2 2.137 13.32 300.263 ;
        RECT  7.8 2.137 7.92 300.263 ;
        RECT  2.4 2.137 2.52 300.263 ;
    END
  END VSS
  OBS
    LAYER RVTN ;
     RECT  0 0 345.6 302.4 ;
    LAYER RVTP ;
     RECT  0 0 345.6 302.4 ;
    LAYER M1 ;
     RECT  2.16 2.151 343.44 300.249 ;
    LAYER M2 ;
     RECT  2.16 2.151 343.44 300.249 ;
    LAYER M3 ;
     RECT  2.415 2.143 2.505 2.413 ;
     RECT  7.815 2.143 7.905 2.413 ;
     RECT  13.215 2.143 13.305 2.413 ;
     RECT  18.615 2.143 18.705 2.413 ;
     RECT  24.015 2.143 24.105 2.413 ;
     RECT  29.415 2.143 29.505 2.413 ;
     RECT  34.815 2.143 34.905 2.413 ;
     RECT  40.215 2.143 40.305 2.413 ;
     RECT  45.615 2.143 45.705 2.413 ;
     RECT  51.015 2.143 51.105 2.413 ;
     RECT  56.415 2.143 56.505 2.413 ;
     RECT  61.815 2.143 61.905 2.413 ;
     RECT  67.215 2.143 67.305 2.413 ;
     RECT  72.615 2.143 72.705 2.413 ;
     RECT  78.015 2.143 78.105 2.413 ;
     RECT  83.415 2.143 83.505 2.413 ;
     RECT  88.815 2.143 88.905 2.413 ;
     RECT  94.215 2.143 94.305 2.413 ;
     RECT  99.615 2.143 99.705 2.413 ;
     RECT  105.015 2.143 105.105 2.413 ;
     RECT  110.415 2.143 110.505 2.413 ;
     RECT  115.815 2.143 115.905 2.413 ;
     RECT  121.215 2.143 121.305 2.413 ;
     RECT  126.615 2.143 126.705 2.413 ;
     RECT  132.015 2.143 132.105 2.413 ;
     RECT  137.415 2.143 137.505 2.413 ;
     RECT  142.815 2.143 142.905 2.413 ;
     RECT  148.215 2.143 148.305 2.413 ;
     RECT  153.615 2.143 153.705 2.413 ;
     RECT  159.015 2.143 159.105 2.413 ;
     RECT  164.415 2.143 164.505 2.413 ;
     RECT  169.815 2.143 169.905 2.413 ;
     RECT  175.215 2.143 175.305 2.413 ;
     RECT  180.615 2.143 180.705 2.413 ;
     RECT  186.015 2.143 186.105 2.413 ;
     RECT  191.415 2.143 191.505 2.413 ;
     RECT  196.815 2.143 196.905 2.413 ;
     RECT  202.215 2.143 202.305 2.413 ;
     RECT  207.615 2.143 207.705 2.413 ;
     RECT  213.015 2.143 213.105 2.413 ;
     RECT  218.415 2.143 218.505 2.413 ;
     RECT  223.815 2.143 223.905 2.413 ;
     RECT  229.215 2.143 229.305 2.413 ;
     RECT  234.615 2.143 234.705 2.413 ;
     RECT  240.015 2.143 240.105 2.413 ;
     RECT  245.415 2.143 245.505 2.413 ;
     RECT  250.815 2.143 250.905 2.413 ;
     RECT  256.215 2.143 256.305 2.413 ;
     RECT  261.615 2.143 261.705 2.413 ;
     RECT  267.015 2.143 267.105 2.413 ;
     RECT  272.415 2.143 272.505 2.413 ;
     RECT  277.815 2.143 277.905 2.413 ;
     RECT  283.215 2.143 283.305 2.413 ;
     RECT  288.615 2.143 288.705 2.413 ;
     RECT  294.015 2.143 294.105 2.413 ;
     RECT  299.415 2.143 299.505 2.413 ;
     RECT  304.815 2.143 304.905 2.413 ;
     RECT  310.215 2.143 310.305 2.413 ;
     RECT  315.615 2.143 315.705 2.413 ;
     RECT  321.015 2.143 321.105 2.413 ;
     RECT  326.415 2.143 326.505 2.413 ;
     RECT  331.815 2.143 331.905 2.413 ;
     RECT  337.215 2.143 337.305 2.413 ;
     RECT  342.615 2.143 342.705 2.413 ;
     RECT  2.415 2.413 2.697 299.987 ;
     RECT  7.815 2.413 8.097 299.987 ;
     RECT  13.215 2.413 13.497 299.987 ;
     RECT  18.615 2.413 18.897 299.987 ;
     RECT  24.015 2.413 24.297 299.987 ;
     RECT  29.415 2.413 29.697 299.987 ;
     RECT  34.815 2.413 35.097 299.987 ;
     RECT  40.215 2.413 40.497 299.987 ;
     RECT  45.615 2.413 45.897 299.987 ;
     RECT  51.015 2.413 51.297 299.987 ;
     RECT  56.415 2.413 56.697 299.987 ;
     RECT  61.815 2.413 62.097 299.987 ;
     RECT  67.215 2.413 67.497 299.987 ;
     RECT  72.615 2.413 72.897 299.987 ;
     RECT  78.015 2.413 78.297 299.987 ;
     RECT  83.415 2.413 83.697 299.987 ;
     RECT  88.815 2.413 89.097 299.987 ;
     RECT  94.215 2.413 94.497 299.987 ;
     RECT  99.615 2.413 99.897 299.987 ;
     RECT  105.015 2.413 105.297 299.987 ;
     RECT  110.415 2.413 110.697 299.987 ;
     RECT  115.815 2.413 116.097 299.987 ;
     RECT  121.215 2.413 121.497 299.987 ;
     RECT  126.615 2.413 126.897 299.987 ;
     RECT  132.015 2.413 132.297 299.987 ;
     RECT  137.415 2.413 137.697 299.987 ;
     RECT  142.815 2.413 143.097 299.987 ;
     RECT  148.215 2.413 148.497 299.987 ;
     RECT  153.615 2.413 153.897 299.987 ;
     RECT  159.015 2.413 159.297 299.987 ;
     RECT  164.415 2.413 164.697 299.987 ;
     RECT  169.815 2.413 170.097 299.987 ;
     RECT  175.215 2.413 175.497 299.987 ;
     RECT  180.615 2.413 180.897 299.987 ;
     RECT  186.015 2.413 186.297 299.987 ;
     RECT  191.415 2.413 191.697 299.987 ;
     RECT  196.815 2.413 197.097 299.987 ;
     RECT  202.215 2.413 202.497 299.987 ;
     RECT  207.615 2.413 207.897 299.987 ;
     RECT  213.015 2.413 213.297 299.987 ;
     RECT  218.415 2.413 218.697 299.987 ;
     RECT  223.815 2.413 224.097 299.987 ;
     RECT  229.215 2.413 229.497 299.987 ;
     RECT  234.615 2.413 234.897 299.987 ;
     RECT  240.015 2.413 240.297 299.987 ;
     RECT  245.415 2.413 245.697 299.987 ;
     RECT  250.815 2.413 251.097 299.987 ;
     RECT  256.215 2.413 256.497 299.987 ;
     RECT  261.615 2.413 261.897 299.987 ;
     RECT  267.015 2.413 267.297 299.987 ;
     RECT  272.415 2.413 272.697 299.987 ;
     RECT  277.815 2.413 278.097 299.987 ;
     RECT  283.215 2.413 283.497 299.987 ;
     RECT  288.615 2.413 288.897 299.987 ;
     RECT  294.015 2.413 294.297 299.987 ;
     RECT  299.415 2.413 299.697 299.987 ;
     RECT  304.815 2.413 305.097 299.987 ;
     RECT  310.215 2.413 310.497 299.987 ;
     RECT  315.615 2.413 315.897 299.987 ;
     RECT  321.015 2.413 321.297 299.987 ;
     RECT  326.415 2.413 326.697 299.987 ;
     RECT  331.815 2.413 332.097 299.987 ;
     RECT  337.215 2.413 337.497 299.987 ;
     RECT  342.615 2.413 342.897 299.987 ;
     RECT  2.415 299.987 2.505 300.257 ;
     RECT  7.815 299.987 7.905 300.257 ;
     RECT  13.215 299.987 13.305 300.257 ;
     RECT  18.615 299.987 18.705 300.257 ;
     RECT  24.015 299.987 24.105 300.257 ;
     RECT  29.415 299.987 29.505 300.257 ;
     RECT  34.815 299.987 34.905 300.257 ;
     RECT  40.215 299.987 40.305 300.257 ;
     RECT  45.615 299.987 45.705 300.257 ;
     RECT  51.015 299.987 51.105 300.257 ;
     RECT  56.415 299.987 56.505 300.257 ;
     RECT  61.815 299.987 61.905 300.257 ;
     RECT  67.215 299.987 67.305 300.257 ;
     RECT  72.615 299.987 72.705 300.257 ;
     RECT  78.015 299.987 78.105 300.257 ;
     RECT  83.415 299.987 83.505 300.257 ;
     RECT  88.815 299.987 88.905 300.257 ;
     RECT  94.215 299.987 94.305 300.257 ;
     RECT  99.615 299.987 99.705 300.257 ;
     RECT  105.015 299.987 105.105 300.257 ;
     RECT  110.415 299.987 110.505 300.257 ;
     RECT  115.815 299.987 115.905 300.257 ;
     RECT  121.215 299.987 121.305 300.257 ;
     RECT  126.615 299.987 126.705 300.257 ;
     RECT  132.015 299.987 132.105 300.257 ;
     RECT  137.415 299.987 137.505 300.257 ;
     RECT  142.815 299.987 142.905 300.257 ;
     RECT  148.215 299.987 148.305 300.257 ;
     RECT  153.615 299.987 153.705 300.257 ;
     RECT  159.015 299.987 159.105 300.257 ;
     RECT  164.415 299.987 164.505 300.257 ;
     RECT  169.815 299.987 169.905 300.257 ;
     RECT  175.215 299.987 175.305 300.257 ;
     RECT  180.615 299.987 180.705 300.257 ;
     RECT  186.015 299.987 186.105 300.257 ;
     RECT  191.415 299.987 191.505 300.257 ;
     RECT  196.815 299.987 196.905 300.257 ;
     RECT  202.215 299.987 202.305 300.257 ;
     RECT  207.615 299.987 207.705 300.257 ;
     RECT  213.015 299.987 213.105 300.257 ;
     RECT  218.415 299.987 218.505 300.257 ;
     RECT  223.815 299.987 223.905 300.257 ;
     RECT  229.215 299.987 229.305 300.257 ;
     RECT  234.615 299.987 234.705 300.257 ;
     RECT  240.015 299.987 240.105 300.257 ;
     RECT  245.415 299.987 245.505 300.257 ;
     RECT  250.815 299.987 250.905 300.257 ;
     RECT  256.215 299.987 256.305 300.257 ;
     RECT  261.615 299.987 261.705 300.257 ;
     RECT  267.015 299.987 267.105 300.257 ;
     RECT  272.415 299.987 272.505 300.257 ;
     RECT  277.815 299.987 277.905 300.257 ;
     RECT  283.215 299.987 283.305 300.257 ;
     RECT  288.615 299.987 288.705 300.257 ;
     RECT  294.015 299.987 294.105 300.257 ;
     RECT  299.415 299.987 299.505 300.257 ;
     RECT  304.815 299.987 304.905 300.257 ;
     RECT  310.215 299.987 310.305 300.257 ;
     RECT  315.615 299.987 315.705 300.257 ;
     RECT  321.015 299.987 321.105 300.257 ;
     RECT  326.415 299.987 326.505 300.257 ;
     RECT  331.815 299.987 331.905 300.257 ;
     RECT  337.215 299.987 337.305 300.257 ;
     RECT  342.615 299.987 342.705 300.257 ;
    LAYER M4 ;
     RECT  2.408 2.148 2.512 300.252 ;
     RECT  2.512 2.418 2.704 299.982 ;
     RECT  7.808 2.148 7.912 300.252 ;
     RECT  7.912 2.418 8.104 299.982 ;
     RECT  13.208 2.148 13.312 300.252 ;
     RECT  13.312 2.418 13.504 299.982 ;
     RECT  18.608 2.148 18.712 300.252 ;
     RECT  18.712 2.418 18.904 299.982 ;
     RECT  24.008 2.148 24.112 300.252 ;
     RECT  24.112 2.418 24.304 299.982 ;
     RECT  29.408 2.148 29.512 300.252 ;
     RECT  29.512 2.418 29.704 299.982 ;
     RECT  34.808 2.148 34.912 300.252 ;
     RECT  34.912 2.418 35.104 299.982 ;
     RECT  40.208 2.148 40.312 300.252 ;
     RECT  40.312 2.418 40.504 299.982 ;
     RECT  45.608 2.148 45.712 300.252 ;
     RECT  45.712 2.418 45.904 299.982 ;
     RECT  51.008 2.148 51.112 300.252 ;
     RECT  51.112 2.418 51.304 299.982 ;
     RECT  56.408 2.148 56.512 300.252 ;
     RECT  56.512 2.418 56.704 299.982 ;
     RECT  61.808 2.148 61.912 300.252 ;
     RECT  61.912 2.418 62.104 299.982 ;
     RECT  67.208 2.148 67.312 300.252 ;
     RECT  67.312 2.418 67.504 299.982 ;
     RECT  72.608 2.148 72.712 300.252 ;
     RECT  72.712 2.418 72.904 299.982 ;
     RECT  78.008 2.148 78.112 300.252 ;
     RECT  78.112 2.418 78.304 299.982 ;
     RECT  83.408 2.148 83.512 300.252 ;
     RECT  83.512 2.418 83.704 299.982 ;
     RECT  88.808 2.148 88.912 300.252 ;
     RECT  88.912 2.418 89.104 299.982 ;
     RECT  94.208 2.148 94.312 300.252 ;
     RECT  94.312 2.418 94.504 299.982 ;
     RECT  99.608 2.148 99.712 300.252 ;
     RECT  99.712 2.418 99.904 299.982 ;
     RECT  105.008 2.148 105.112 300.252 ;
     RECT  105.112 2.418 105.304 299.982 ;
     RECT  110.408 2.148 110.512 300.252 ;
     RECT  110.512 2.418 110.704 299.982 ;
     RECT  115.808 2.148 115.912 300.252 ;
     RECT  115.912 2.418 116.104 299.982 ;
     RECT  121.208 2.148 121.312 300.252 ;
     RECT  121.312 2.418 121.504 299.982 ;
     RECT  126.608 2.148 126.712 300.252 ;
     RECT  126.712 2.418 126.904 299.982 ;
     RECT  132.008 2.148 132.112 300.252 ;
     RECT  132.112 2.418 132.304 299.982 ;
     RECT  137.408 2.148 137.512 300.252 ;
     RECT  137.512 2.418 137.704 299.982 ;
     RECT  142.808 2.148 142.912 300.252 ;
     RECT  142.912 2.418 143.104 299.982 ;
     RECT  148.208 2.148 148.312 300.252 ;
     RECT  148.312 2.418 148.504 299.982 ;
     RECT  153.608 2.148 153.712 300.252 ;
     RECT  153.712 2.418 153.904 299.982 ;
     RECT  159.008 2.148 159.112 300.252 ;
     RECT  159.112 2.418 159.304 299.982 ;
     RECT  164.408 2.148 164.512 300.252 ;
     RECT  164.512 2.418 164.704 299.982 ;
     RECT  169.808 2.148 169.912 300.252 ;
     RECT  169.912 2.418 170.104 299.982 ;
     RECT  175.208 2.148 175.312 300.252 ;
     RECT  175.312 2.418 175.504 299.982 ;
     RECT  180.608 2.148 180.712 300.252 ;
     RECT  180.712 2.418 180.904 299.982 ;
     RECT  186.008 2.148 186.112 300.252 ;
     RECT  186.112 2.418 186.304 299.982 ;
     RECT  191.408 2.148 191.512 300.252 ;
     RECT  191.512 2.418 191.704 299.982 ;
     RECT  196.808 2.148 196.912 300.252 ;
     RECT  196.912 2.418 197.104 299.982 ;
     RECT  202.208 2.148 202.312 300.252 ;
     RECT  202.312 2.418 202.504 299.982 ;
     RECT  207.608 2.148 207.712 300.252 ;
     RECT  207.712 2.418 207.904 299.982 ;
     RECT  213.008 2.148 213.112 300.252 ;
     RECT  213.112 2.418 213.304 299.982 ;
     RECT  218.408 2.148 218.512 300.252 ;
     RECT  218.512 2.418 218.704 299.982 ;
     RECT  223.808 2.148 223.912 300.252 ;
     RECT  223.912 2.418 224.104 299.982 ;
     RECT  229.208 2.148 229.312 300.252 ;
     RECT  229.312 2.418 229.504 299.982 ;
     RECT  234.608 2.148 234.712 300.252 ;
     RECT  234.712 2.418 234.904 299.982 ;
     RECT  240.008 2.148 240.112 300.252 ;
     RECT  240.112 2.418 240.304 299.982 ;
     RECT  245.408 2.148 245.512 300.252 ;
     RECT  245.512 2.418 245.704 299.982 ;
     RECT  250.808 2.148 250.912 300.252 ;
     RECT  250.912 2.418 251.104 299.982 ;
     RECT  256.208 2.148 256.312 300.252 ;
     RECT  256.312 2.418 256.504 299.982 ;
     RECT  261.608 2.148 261.712 300.252 ;
     RECT  261.712 2.418 261.904 299.982 ;
     RECT  267.008 2.148 267.112 300.252 ;
     RECT  267.112 2.418 267.304 299.982 ;
     RECT  272.408 2.148 272.512 300.252 ;
     RECT  272.512 2.418 272.704 299.982 ;
     RECT  277.808 2.148 277.912 300.252 ;
     RECT  277.912 2.418 278.104 299.982 ;
     RECT  283.208 2.148 283.312 300.252 ;
     RECT  283.312 2.418 283.504 299.982 ;
     RECT  288.608 2.148 288.712 300.252 ;
     RECT  288.712 2.418 288.904 299.982 ;
     RECT  294.008 2.148 294.112 300.252 ;
     RECT  294.112 2.418 294.304 299.982 ;
     RECT  299.408 2.148 299.512 300.252 ;
     RECT  299.512 2.418 299.704 299.982 ;
     RECT  304.808 2.148 304.912 300.252 ;
     RECT  304.912 2.418 305.104 299.982 ;
     RECT  310.208 2.148 310.312 300.252 ;
     RECT  310.312 2.418 310.504 299.982 ;
     RECT  315.608 2.148 315.712 300.252 ;
     RECT  315.712 2.418 315.904 299.982 ;
     RECT  321.008 2.148 321.112 300.252 ;
     RECT  321.112 2.418 321.304 299.982 ;
     RECT  326.408 2.148 326.512 300.252 ;
     RECT  326.512 2.418 326.704 299.982 ;
     RECT  331.808 2.148 331.912 300.252 ;
     RECT  331.912 2.418 332.104 299.982 ;
     RECT  337.208 2.148 337.312 300.252 ;
     RECT  337.312 2.418 337.504 299.982 ;
     RECT  342.608 2.148 342.712 300.252 ;
     RECT  342.712 2.418 342.904 299.982 ;
    LAYER M5 ;
     RECT  2.4 2.137 2.52 2.151 ;
     RECT  7.8 2.137 7.92 2.151 ;
     RECT  13.2 2.137 13.32 2.151 ;
     RECT  18.6 2.137 18.72 2.151 ;
     RECT  24 2.137 24.12 2.151 ;
     RECT  29.4 2.137 29.52 2.151 ;
     RECT  34.8 2.137 34.92 2.151 ;
     RECT  40.2 2.137 40.32 2.151 ;
     RECT  45.6 2.137 45.72 2.151 ;
     RECT  51 2.137 51.12 2.151 ;
     RECT  56.4 2.137 56.52 2.151 ;
     RECT  61.8 2.137 61.92 2.151 ;
     RECT  67.2 2.137 67.32 2.151 ;
     RECT  72.6 2.137 72.72 2.151 ;
     RECT  78 2.137 78.12 2.151 ;
     RECT  83.4 2.137 83.52 2.151 ;
     RECT  88.8 2.137 88.92 2.151 ;
     RECT  94.2 2.137 94.32 2.151 ;
     RECT  99.6 2.137 99.72 2.151 ;
     RECT  105 2.137 105.12 2.151 ;
     RECT  110.4 2.137 110.52 2.151 ;
     RECT  115.8 2.137 115.92 2.151 ;
     RECT  121.2 2.137 121.32 2.151 ;
     RECT  126.6 2.137 126.72 2.151 ;
     RECT  132 2.137 132.12 2.151 ;
     RECT  137.4 2.137 137.52 2.151 ;
     RECT  142.8 2.137 142.92 2.151 ;
     RECT  148.2 2.137 148.32 2.151 ;
     RECT  153.6 2.137 153.72 2.151 ;
     RECT  159 2.137 159.12 2.151 ;
     RECT  164.4 2.137 164.52 2.151 ;
     RECT  169.8 2.137 169.92 2.151 ;
     RECT  175.2 2.137 175.32 2.151 ;
     RECT  180.6 2.137 180.72 2.151 ;
     RECT  186 2.137 186.12 2.151 ;
     RECT  191.4 2.137 191.52 2.151 ;
     RECT  196.8 2.137 196.92 2.151 ;
     RECT  202.2 2.137 202.32 2.151 ;
     RECT  207.6 2.137 207.72 2.151 ;
     RECT  213 2.137 213.12 2.151 ;
     RECT  218.4 2.137 218.52 2.151 ;
     RECT  223.8 2.137 223.92 2.151 ;
     RECT  229.2 2.137 229.32 2.151 ;
     RECT  234.6 2.137 234.72 2.151 ;
     RECT  240 2.137 240.12 2.151 ;
     RECT  245.4 2.137 245.52 2.151 ;
     RECT  250.8 2.137 250.92 2.151 ;
     RECT  256.2 2.137 256.32 2.151 ;
     RECT  261.6 2.137 261.72 2.151 ;
     RECT  267 2.137 267.12 2.151 ;
     RECT  272.4 2.137 272.52 2.151 ;
     RECT  277.8 2.137 277.92 2.151 ;
     RECT  283.2 2.137 283.32 2.151 ;
     RECT  288.6 2.137 288.72 2.151 ;
     RECT  294 2.137 294.12 2.151 ;
     RECT  299.4 2.137 299.52 2.151 ;
     RECT  304.8 2.137 304.92 2.151 ;
     RECT  310.2 2.137 310.32 2.151 ;
     RECT  315.6 2.137 315.72 2.151 ;
     RECT  321 2.137 321.12 2.151 ;
     RECT  326.4 2.137 326.52 2.151 ;
     RECT  331.8 2.137 331.92 2.151 ;
     RECT  337.2 2.137 337.32 2.151 ;
     RECT  342.6 2.137 342.72 2.151 ;
     RECT  2.4 2.151 2.712 300.249 ;
     RECT  7.8 2.151 8.112 300.249 ;
     RECT  13.2 2.151 13.512 300.249 ;
     RECT  18.6 2.151 18.912 300.249 ;
     RECT  24 2.151 24.312 300.249 ;
     RECT  29.4 2.151 29.712 300.249 ;
     RECT  34.8 2.151 35.112 300.249 ;
     RECT  40.2 2.151 40.512 300.249 ;
     RECT  45.6 2.151 45.912 300.249 ;
     RECT  51 2.151 51.312 300.249 ;
     RECT  56.4 2.151 56.712 300.249 ;
     RECT  61.8 2.151 62.112 300.249 ;
     RECT  67.2 2.151 67.512 300.249 ;
     RECT  72.6 2.151 72.912 300.249 ;
     RECT  78 2.151 78.312 300.249 ;
     RECT  83.4 2.151 83.712 300.249 ;
     RECT  88.8 2.151 89.112 300.249 ;
     RECT  94.2 2.151 94.512 300.249 ;
     RECT  99.6 2.151 99.912 300.249 ;
     RECT  105 2.151 105.312 300.249 ;
     RECT  110.4 2.151 110.712 300.249 ;
     RECT  115.8 2.151 116.112 300.249 ;
     RECT  121.2 2.151 121.512 300.249 ;
     RECT  126.6 2.151 126.912 300.249 ;
     RECT  132 2.151 132.312 300.249 ;
     RECT  137.4 2.151 137.712 300.249 ;
     RECT  142.8 2.151 143.112 300.249 ;
     RECT  148.2 2.151 148.512 300.249 ;
     RECT  153.6 2.151 153.912 300.249 ;
     RECT  159 2.151 159.312 300.249 ;
     RECT  164.4 2.151 164.712 300.249 ;
     RECT  169.8 2.151 170.112 300.249 ;
     RECT  175.2 2.151 175.512 300.249 ;
     RECT  180.6 2.151 180.912 300.249 ;
     RECT  186 2.151 186.312 300.249 ;
     RECT  191.4 2.151 191.712 300.249 ;
     RECT  196.8 2.151 197.112 300.249 ;
     RECT  202.2 2.151 202.512 300.249 ;
     RECT  207.6 2.151 207.912 300.249 ;
     RECT  213 2.151 213.312 300.249 ;
     RECT  218.4 2.151 218.712 300.249 ;
     RECT  223.8 2.151 224.112 300.249 ;
     RECT  229.2 2.151 229.512 300.249 ;
     RECT  234.6 2.151 234.912 300.249 ;
     RECT  240 2.151 240.312 300.249 ;
     RECT  245.4 2.151 245.712 300.249 ;
     RECT  250.8 2.151 251.112 300.249 ;
     RECT  256.2 2.151 256.512 300.249 ;
     RECT  261.6 2.151 261.912 300.249 ;
     RECT  267 2.151 267.312 300.249 ;
     RECT  272.4 2.151 272.712 300.249 ;
     RECT  277.8 2.151 278.112 300.249 ;
     RECT  283.2 2.151 283.512 300.249 ;
     RECT  288.6 2.151 288.912 300.249 ;
     RECT  294 2.151 294.312 300.249 ;
     RECT  299.4 2.151 299.712 300.249 ;
     RECT  304.8 2.151 305.112 300.249 ;
     RECT  310.2 2.151 310.512 300.249 ;
     RECT  315.6 2.151 315.912 300.249 ;
     RECT  321 2.151 321.312 300.249 ;
     RECT  326.4 2.151 326.712 300.249 ;
     RECT  331.8 2.151 332.112 300.249 ;
     RECT  337.2 2.151 337.512 300.249 ;
     RECT  342.6 2.151 342.912 300.249 ;
     RECT  2.4 300.249 2.52 300.263 ;
     RECT  7.8 300.249 7.92 300.263 ;
     RECT  13.2 300.249 13.32 300.263 ;
     RECT  18.6 300.249 18.72 300.263 ;
     RECT  24 300.249 24.12 300.263 ;
     RECT  29.4 300.249 29.52 300.263 ;
     RECT  34.8 300.249 34.92 300.263 ;
     RECT  40.2 300.249 40.32 300.263 ;
     RECT  45.6 300.249 45.72 300.263 ;
     RECT  51 300.249 51.12 300.263 ;
     RECT  56.4 300.249 56.52 300.263 ;
     RECT  61.8 300.249 61.92 300.263 ;
     RECT  67.2 300.249 67.32 300.263 ;
     RECT  72.6 300.249 72.72 300.263 ;
     RECT  78 300.249 78.12 300.263 ;
     RECT  83.4 300.249 83.52 300.263 ;
     RECT  88.8 300.249 88.92 300.263 ;
     RECT  94.2 300.249 94.32 300.263 ;
     RECT  99.6 300.249 99.72 300.263 ;
     RECT  105 300.249 105.12 300.263 ;
     RECT  110.4 300.249 110.52 300.263 ;
     RECT  115.8 300.249 115.92 300.263 ;
     RECT  121.2 300.249 121.32 300.263 ;
     RECT  126.6 300.249 126.72 300.263 ;
     RECT  132 300.249 132.12 300.263 ;
     RECT  137.4 300.249 137.52 300.263 ;
     RECT  142.8 300.249 142.92 300.263 ;
     RECT  148.2 300.249 148.32 300.263 ;
     RECT  153.6 300.249 153.72 300.263 ;
     RECT  159 300.249 159.12 300.263 ;
     RECT  164.4 300.249 164.52 300.263 ;
     RECT  169.8 300.249 169.92 300.263 ;
     RECT  175.2 300.249 175.32 300.263 ;
     RECT  180.6 300.249 180.72 300.263 ;
     RECT  186 300.249 186.12 300.263 ;
     RECT  191.4 300.249 191.52 300.263 ;
     RECT  196.8 300.249 196.92 300.263 ;
     RECT  202.2 300.249 202.32 300.263 ;
     RECT  207.6 300.249 207.72 300.263 ;
     RECT  213 300.249 213.12 300.263 ;
     RECT  218.4 300.249 218.52 300.263 ;
     RECT  223.8 300.249 223.92 300.263 ;
     RECT  229.2 300.249 229.32 300.263 ;
     RECT  234.6 300.249 234.72 300.263 ;
     RECT  240 300.249 240.12 300.263 ;
     RECT  245.4 300.249 245.52 300.263 ;
     RECT  250.8 300.249 250.92 300.263 ;
     RECT  256.2 300.249 256.32 300.263 ;
     RECT  261.6 300.249 261.72 300.263 ;
     RECT  267 300.249 267.12 300.263 ;
     RECT  272.4 300.249 272.52 300.263 ;
     RECT  277.8 300.249 277.92 300.263 ;
     RECT  283.2 300.249 283.32 300.263 ;
     RECT  288.6 300.249 288.72 300.263 ;
     RECT  294 300.249 294.12 300.263 ;
     RECT  299.4 300.249 299.52 300.263 ;
     RECT  304.8 300.249 304.92 300.263 ;
     RECT  310.2 300.249 310.32 300.263 ;
     RECT  315.6 300.249 315.72 300.263 ;
     RECT  321 300.249 321.12 300.263 ;
     RECT  326.4 300.249 326.52 300.263 ;
     RECT  331.8 300.249 331.92 300.263 ;
     RECT  337.2 300.249 337.32 300.263 ;
     RECT  342.6 300.249 342.72 300.263 ;
  END
END dsdv_gunit_l5
END LIBRARY
